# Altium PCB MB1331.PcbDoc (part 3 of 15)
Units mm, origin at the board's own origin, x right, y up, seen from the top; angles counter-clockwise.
Board outline 169.25 x 173.25 mm, 6 copper layers (Top Layer, Signal Layer 1, Signal Layer 2, Signal Layer 3, Signal Layer 4, Bottom Layer), stack 1.556 mm thick; 871 components, 699 nets, 3244 pads, 2370 vias.

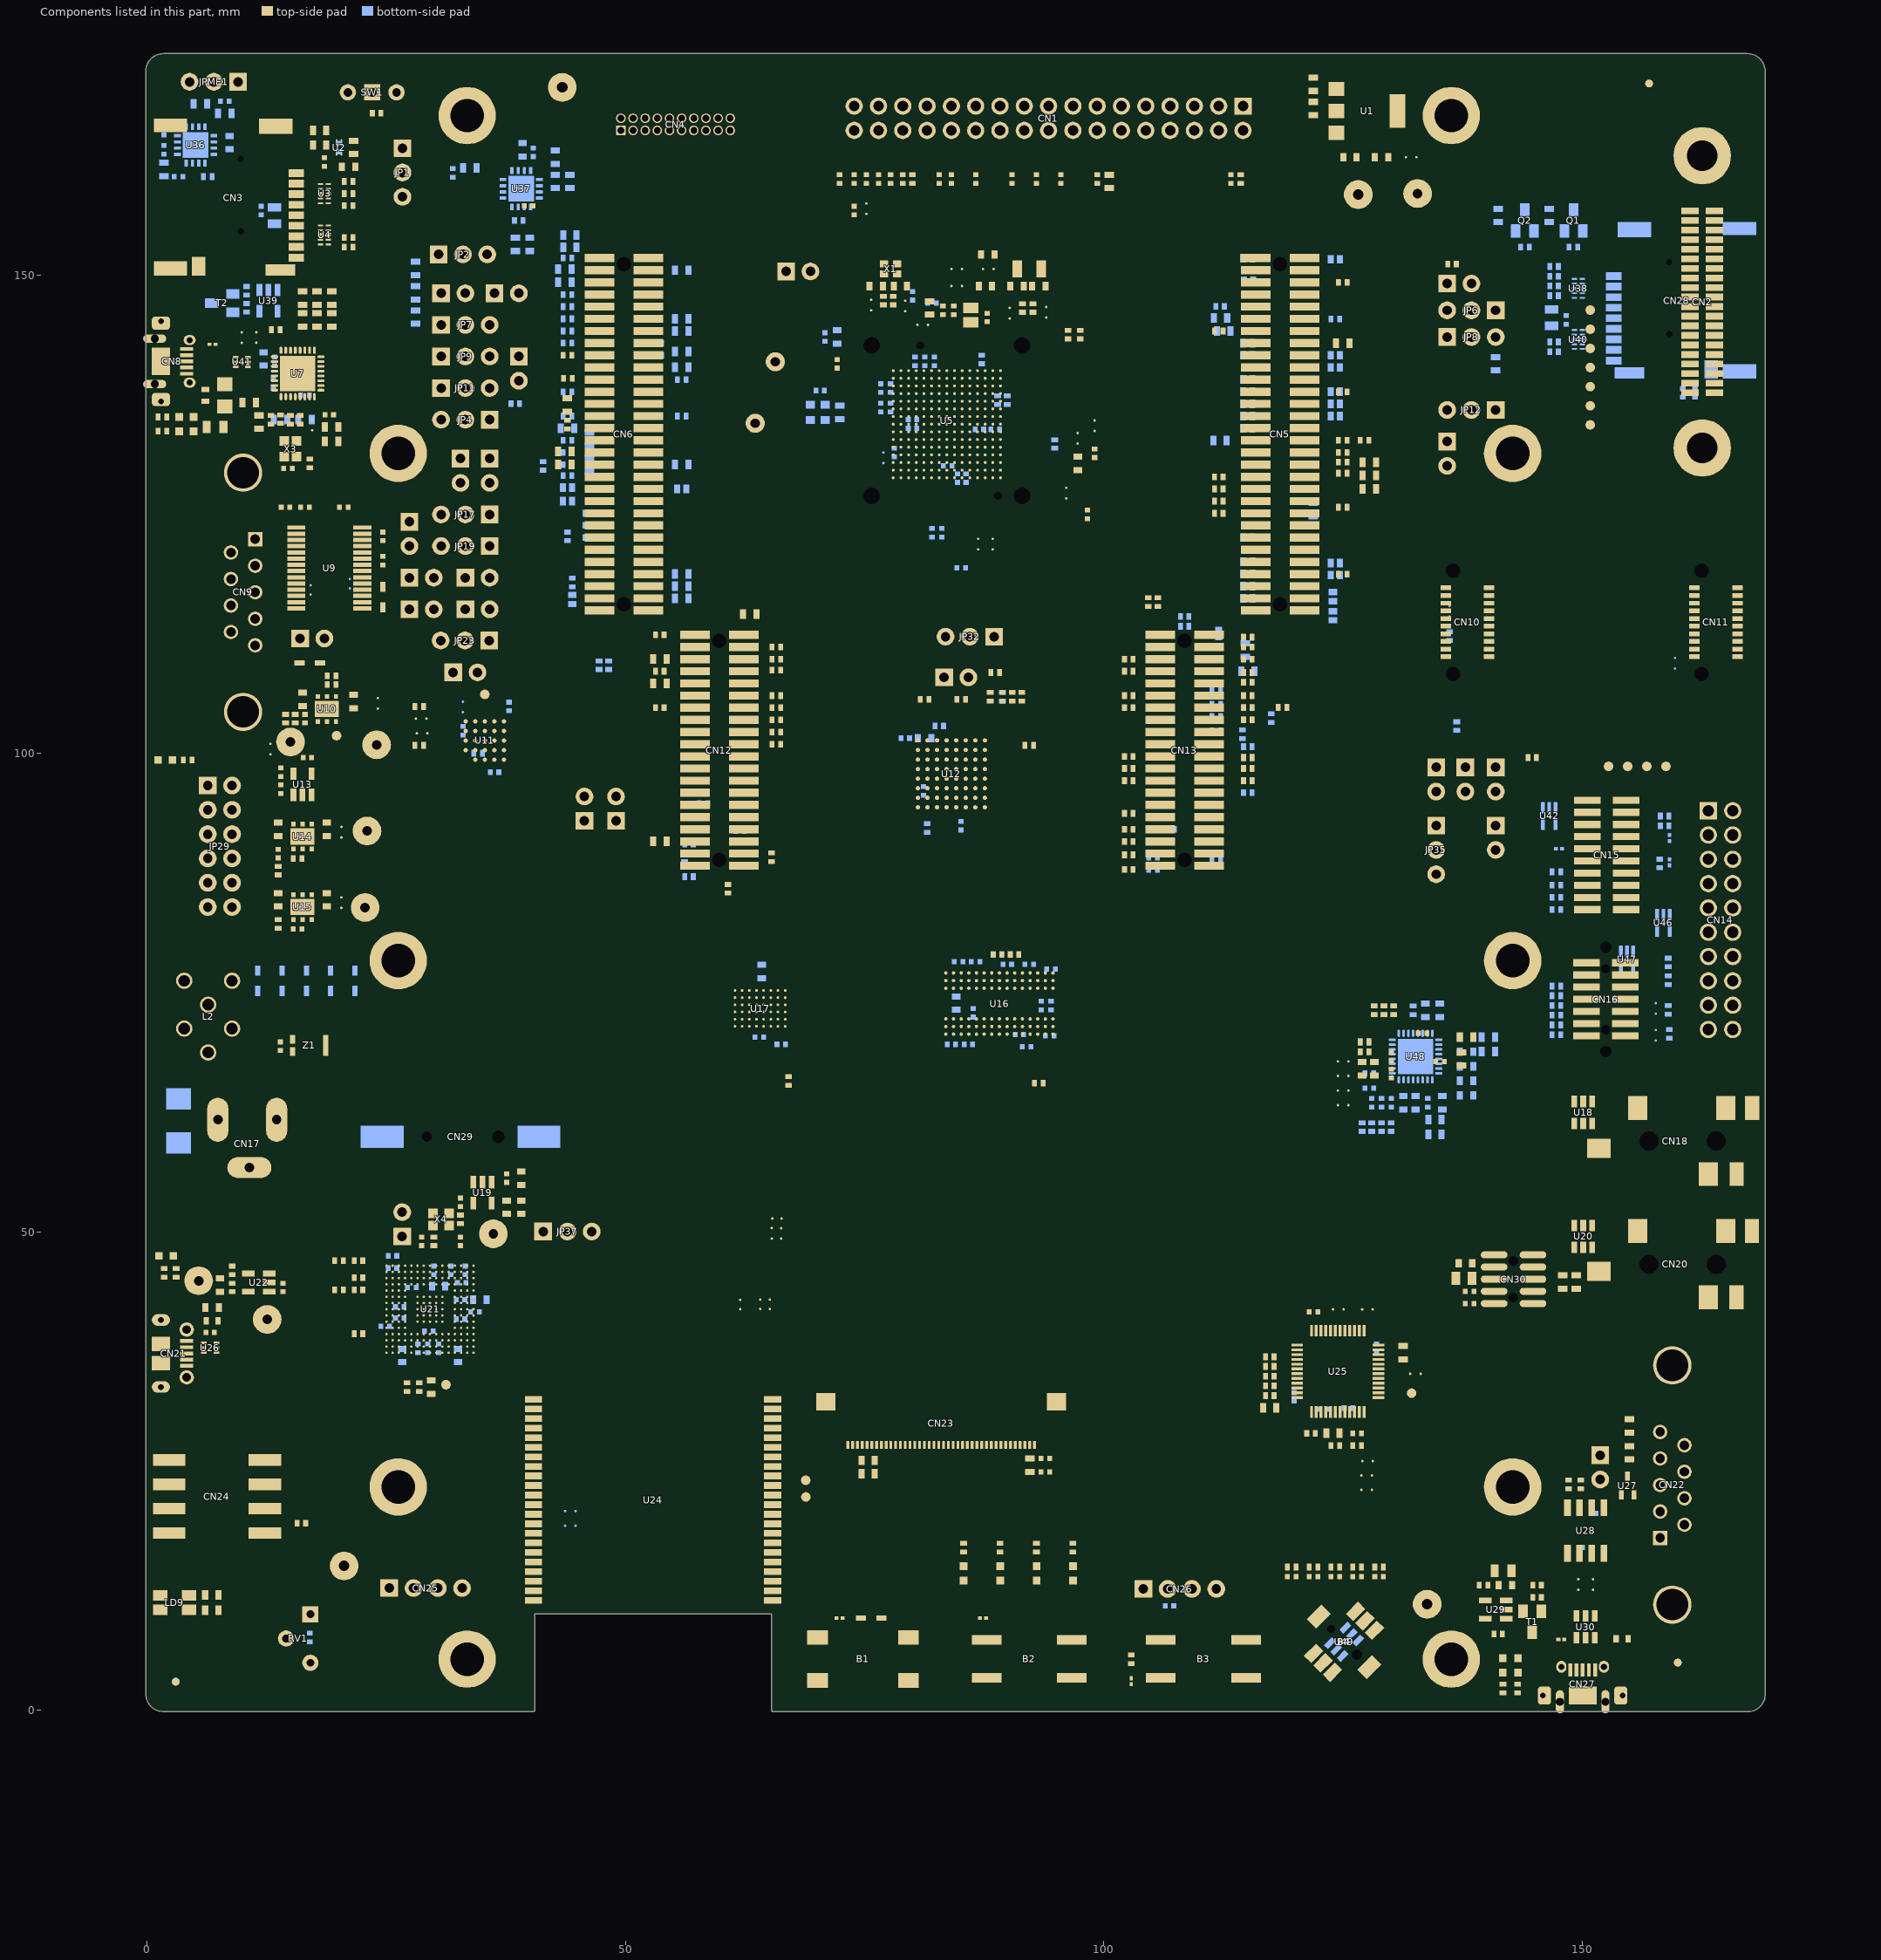
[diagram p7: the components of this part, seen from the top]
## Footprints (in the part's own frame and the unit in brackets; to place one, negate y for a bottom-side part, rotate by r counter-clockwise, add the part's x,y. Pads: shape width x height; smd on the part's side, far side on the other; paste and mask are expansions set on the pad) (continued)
ICC_TFBGA90_8X13_P080 [mm] "IPC"
  round 0.35 smd mask+0.05: A1(-3.2,5.6) A2(-2.4,5.6) A3(-1.6,5.6) A7(1.6,5.6) A8(2.4,5.6) A9(3.2,5.6) B1(-3.2,4.8) B2(-2.4,4.8) B3(-1.6,4.8) B7(1.6,4.8) B8(2.4,4.8) B9(3.2,4.8) C1(-3.2,4) C2(-2.4,4) C3(-1.6,4) C7(1.6,4) C8(2.4,4) C9(3.2,4) D1(-3.2,3.2) D2(-2.4,3.2) D3(-1.6,3.2) D7(1.6,3.2) D8(2.4,3.2) D9(3.2,3.2) E1(-3.2,2.4) E2(-2.4,2.4) E3(-1.6,2.4) E7(1.6,2.4) E8(2.4,2.4) E9(3.2,2.4) F1(-3.2,1.6) F2(-2.4,1.6) F3(-1.6,1.6) F7(1.6,1.6) F8(2.4,1.6) F9(3.2,1.6) G1(-3.2,0.8) G2(-2.4,0.8) G3(-1.6,0.8) G7(1.6,0.8) G8(2.4,0.8) G9(3.2,0.8) H1(-3.2,0) H2(-2.4,0) H3(-1.6,0) H7(1.6,0) H8(2.4,0) H9(3.2,0) J1(-3.2,-0.8) J2(-2.4,-0.8) J3(-1.6,-0.8) J7(1.6,-0.8) J8(2.4,-0.8) J9(3.2,-0.8) K1(-3.2,-1.6) K2(-2.4,-1.6) K3(-1.6,-1.6) K7(1.6,-1.6) K8(2.4,-1.6) K9(3.2,-1.6) L1(-3.2,-2.4) L2(-2.4,-2.4) L3(-1.6,-2.4) L7(1.6,-2.4) L8(2.4,-2.4) L9(3.2,-2.4) M1(-3.2,-3.2) M2(-2.4,-3.2) M3(-1.6,-3.2) M7(1.6,-3.2) M8(2.4,-3.2) M9(3.2,-3.2) N1(-3.2,-4) N2(-2.4,-4) N3(-1.6,-4) N7(1.6,-4) N8(2.4,-4) N9(3.2,-4) P1(-3.2,-4.8) P2(-2.4,-4.8) P3(-1.6,-4.8) P7(1.6,-4.8) P8(2.4,-4.8) P9(3.2,-4.8) R1(-3.2,-5.6) R2(-2.4,-5.6) R3(-1.6,-5.6) R7(1.6,-5.6) R8(2.4,-5.6) R9(3.2,-5.6)
  silkscreen extent -4.2,-6.55 4.05,6.7, body extent -4.06,-6.55 4.05,6.55, height 1.21
ICC_TFBGA225_13X13_STM32H7B3NIH6Q_P080__SOCKET_IRONWOOD_CS1222291MF_REV-A_WITHOUT-3D-SOCKET [mm] "MCD-01577"
  round 0.3 smd mask+0.05: A1(-5.6,5.6) A2(-4.8,5.6) A3(-4,5.6) A4(-3.2,5.6) A5(-2.4,5.6) A6(-1.6,5.6) A7(-0.8,5.6) A8(0,5.6) A9(0.8,5.6) A10(1.6,5.6) A11(2.4,5.6) A12(3.2,5.6) A13(4,5.6) A14(4.8,5.6) A15(5.6,5.6) B1(-5.6,4.8) B2(-4.8,4.8) B3(-4,4.8) B4(-3.2,4.8) B5(-2.4,4.8) B6(-1.6,4.8) B7(-0.8,4.8) B8(0,4.8) B9(0.8,4.8) B10(1.6,4.8) B11(2.4,4.8) B12(3.2,4.8) B13(4,4.8) B14(4.8,4.8) B15(5.6,4.8) C1(-5.6,4) C2(-4.8,4) C3(-4,4) C4(-3.2,4) C5(-2.4,4) C6(-1.6,4) C7(-0.8,4) C8(0,4) C9(0.8,4) C10(1.6,4) C11(2.4,4) C12(3.2,4) C13(4,4) C14(4.8,4) C15(5.6,4) D1(-5.6,3.2) D2(-4.8,3.2) D3(-4,3.2) D4(-3.2,3.2) D5(-2.4,3.2) D6(-1.6,3.2) D7(-0.8,3.2) D8(0,3.2) D9(0.8,3.2) D10(1.6,3.2) D11(2.4,3.2) D12(3.2,3.2) D13(4,3.2) D14(4.8,3.2) D15(5.6,3.2) E1(-5.6,2.4) E2(-4.8,2.4) E3(-4,2.4) E4(-3.2,2.4) E5(-2.4,2.4) E6(-1.6,2.4) E7(-0.8,2.4) E8(0,2.4) E9(0.8,2.4) E10(1.6,2.4) E11(2.4,2.4) E12(3.2,2.4) E13(4,2.4) E14(4.8,2.4) E15(5.6,2.4) F1(-5.6,1.6) F2(-4.8,1.6) F3(-4,1.6) F4(-3.2,1.6) F5(-2.4,1.6) F6(-1.6,1.6) F7(-0.8,1.6) F8(0,1.6) F9(0.8,1.6) F10(1.6,1.6) F11(2.4,1.6) F12(3.2,1.6) F13(4,1.6) F14(4.8,1.6) F15(5.6,1.6) G1(-5.6,0.8) G2(-4.8,0.8) G3(-4,0.8) G4(-3.2,0.8) G5(-2.4,0.8) G6(-1.6,0.8) G7(-0.8,0.8) G8(0,0.8) G9(0.8,0.8) G10(1.6,0.8) G11(2.4,0.8) G12(3.2,0.8) G13(4,0.8) G14(4.8,0.8) G15(5.6,0.8) H1(-5.6,0) H2(-4.8,0) H3(-4,0) H4(-3.2,0) H5(-2.4,0) H6(-1.6,0) H7(-0.8,0) H8(0,0) H9(0.8,0) H10(1.6,0) H11(2.4,0) H12(3.2,0) H13(4,0) H14(4.8,0) H15(5.6,0) J1(-5.6,-0.8) J2(-4.8,-0.8) J3(-4,-0.8) J4(-3.2,-0.8) J5(-2.4,-0.8) J6(-1.6,-0.8) J7(-0.8,-0.8) J8(0,-0.8) J9(0.8,-0.8) J10(1.6,-0.8) J11(2.4,-0.8) J12(3.2,-0.8) J13(4,-0.8) J14(4.8,-0.8) J15(5.6,-0.8) K1(-5.6,-1.6) K2(-4.8,-1.6) K3(-4,-1.6) K4(-3.2,-1.6) K5(-2.4,-1.6) K6(-1.6,-1.6) K7(-0.8,-1.6) K8(0,-1.6) K9(0.8,-1.6) K10(1.6,-1.6) K11(2.4,-1.6) K12(3.2,-1.6) K13(4,-1.6) K14(4.8,-1.6) K15(5.6,-1.6) L1(-5.6,-2.4) L2(-4.8,-2.4) L3(-4,-2.4) L4(-3.2,-2.4) L5(-2.4,-2.4) L6(-1.6,-2.4) L7(-0.8,-2.4) L8(0,-2.4) L9(0.8,-2.4) L10(1.6,-2.4) L11(2.4,-2.4) L12(3.2,-2.4) L13(4,-2.4) L14(4.8,-2.4) L15(5.6,-2.4) M1(-5.6,-3.2) M2(-4.8,-3.2) M3(-4,-3.2) M4(-3.2,-3.2) M5(-2.4,-3.2) M6(-1.6,-3.2) M7(-0.8,-3.2) M8(0,-3.2) M9(0.8,-3.2) M10(1.6,-3.2) M11(2.4,-3.2) M12(3.2,-3.2) M13(4,-3.2) M14(4.8,-3.2) M15(5.6,-3.2) N1(-5.6,-4) N2(-4.8,-4) N3(-4,-4) N4(-3.2,-4) N5(-2.4,-4) N6(-1.6,-4) N7(-0.8,-4) N8(0,-4) N9(0.8,-4) N10(1.6,-4) N11(2.4,-4) N12(3.2,-4) N13(4,-4) N14(4.8,-4) N15(5.6,-4) P1(-5.6,-4.8) P2(-4.8,-4.8) P3(-4,-4.8) P4(-3.2,-4.8) P5(-2.4,-4.8) P6(-1.6,-4.8) P7(-0.8,-4.8) P8(0,-4.8) P9(0.8,-4.8) P10(1.6,-4.8) P11(2.4,-4.8) P12(3.2,-4.8) P13(4,-4.8) P14(4.8,-4.8) P15(5.6,-4.8) R1(-5.6,-5.6) R2(-4.8,-5.6) R3(-4,-5.6) R4(-3.2,-5.6) R5(-2.4,-5.6) R6(-1.6,-5.6) R7(-0.8,-5.6) R8(0,-5.6) R9(0.8,-5.6) R10(1.6,-5.6) R11(2.4,-5.6) R12(3.2,-5.6) R13(4,-5.6) R14(4.8,-5.6) R15(5.6,-5.6)
  round 0 hole 0.85 unplated mask+0.05: NPTH1(7.487,5.322) NPTH2(-8.238,-2.783)
  round 0 hole 1.71 unplated mask+0.05: PTH1(-8.238,7.862) PTH2(7.487,7.862) PTH3(7.487,-7.863) PTH4(-8.238,-7.863)
  Bottom Layer keep-out circle w0.01: c7.487,7.862 r2.5
  Bottom Layer keep-out circle w0.01: c-8.238,7.862 r2.5
  Bottom Layer keep-out circle w0.01: c-8.238,-7.863 r2.5
  Bottom Layer keep-out circle w0.01: c7.487,-7.863 r2.5
  Bottom Layer keep-out region: -0.376,0 -0.376,-2.5 1.224,-2.5 5.024,-6.3 5.076,-6.378 5.094,-6.469 5.094,-6.469 5.094,-6.63 5.028,-6.963 4.839,-7.245 4.557,-7.434 4.224,-7.5 4.224,-7.5 -0.376,-7.5 -0.376,-10.365 9.988,-10.365 9.988,10.365 -0.376,10.365 -0.376,7.5 4.224,7.5 4.557,7.434 4.839,7.245 5.028,6.963 5.094,6.63 5.094,6.63 5.094,6.469 5.076,6.378 5.024,6.3 5.024,6.3 1.224,2.5 -0.376,2.5 -0.376,0 2.124,0 2.124,1.6 5.924,5.4 6.002,5.452 6.093,5.47 6.093,5.47 6.254,5.47 6.587,5.404 6.869,5.215 7.058,4.933 7.124,4.6 7.124,4.6 7.124,-4.6 7.058,-4.933 6.869,-5.215 6.587,-5.404 6.254,-5.47 6.254,-5.47 6.093,-5.47 6.002,-5.452 5.924,-5.4 5.924,-5.4 2.124,-1.6 2.124,0
  Bottom Layer keep-out region: -0.376,0 -0.376,2.5 -1.976,2.5 -5.776,6.3 -5.828,6.378 -5.846,6.469 -5.846,6.469 -5.846,6.63 -5.78,6.963 -5.591,7.245 -5.309,7.434 -4.976,7.5 -4.976,7.5 -0.376,7.5 -0.376,10.365 -10.74,10.365 -10.74,-10.365 -0.376,-10.365 -0.376,-7.5 -4.976,-7.5 -5.309,-7.434 -5.591,-7.245 -5.78,-6.963 -5.846,-6.63 -5.846,-6.63 -5.846,-6.469 -5.828,-6.378 -5.776,-6.3 -5.776,-6.3 -1.976,-2.5 -0.376,-2.5 -0.376,0 -2.876,0 -2.876,-1.6 -6.676,-5.4 -6.754,-5.452 -6.845,-5.47 -6.845,-5.47 -7.006,-5.47 -7.339,-5.404 -7.621,-5.215 -7.81,-4.933 -7.876,-4.6 -7.876,-4.6 -7.876,4.6 -7.81,4.933 -7.621,5.215 -7.339,5.404 -7.006,5.47 -7.006,5.47 -6.845,5.47 -6.754,5.452 -6.676,5.4 -6.676,5.4 -2.876,1.6 -2.876,0
  silkscreen extent -9.65,-9.13 8.75,9.28, body extent -6.55,-6.55 6.55,6.55, height 1.21
ICC_UFBGA201_176+25_10X10_P065 [mm] "IPC"
  round 0.25 smd mask+0.05: A1(-4.55,4.55) A2(-3.9,4.55) A3(-3.25,4.55) A4(-2.6,4.55) A5(-1.95,4.55) A6(-1.3,4.55) A7(-0.65,4.55) A8(0,4.55) A9(0.65,4.55) A10(1.3,4.55) A11(1.95,4.55) A12(2.6,4.55) A13(3.25,4.55) A14(3.9,4.55) A15(4.55,4.55) B1(-4.55,3.9) B2(-3.9,3.9) B3(-3.25,3.9) B4(-2.6,3.9) B5(-1.95,3.9) B6(-1.3,3.9) B7(-0.65,3.9) B8(0,3.9) B9(0.65,3.9) B10(1.3,3.9) B11(1.95,3.9) B12(2.6,3.9) B13(3.25,3.9) B14(3.9,3.9) B15(4.55,3.9) C1(-4.55,3.25) C2(-3.9,3.25) C3(-3.25,3.25) C4(-2.6,3.25) C5(-1.95,3.25) C6(-1.3,3.25) C7(-0.65,3.25) C8(0,3.25) C9(0.65,3.25) C10(1.3,3.25) C11(1.95,3.25) C12(2.6,3.25) C13(3.25,3.25) C14(3.9,3.25) C15(4.55,3.25) D1(-4.55,2.6) D2(-3.9,2.6) D3(-3.25,2.6) D4(-2.6,2.6) D5(-1.95,2.6) D6(-1.3,2.6) D7(-0.65,2.6) D8(0,2.6) D9(0.65,2.6) D10(1.3,2.6) D11(1.95,2.6) D12(2.6,2.6) D13(3.25,2.6) D14(3.9,2.6) D15(4.55,2.6) E1(-4.55,1.95) E2(-3.9,1.95) E3(-3.25,1.95) E4(-2.6,1.95) E12(2.6,1.95) E13(3.25,1.95) E14(3.9,1.95) E15(4.55,1.95) F1(-4.55,1.3) F2(-3.9,1.3) F3(-3.25,1.3) F4(-2.6,1.3) F6(-1.3,1.3) F7(-0.65,1.3) F8(0,1.3) F9(0.65,1.3) F10(1.3,1.3) F12(2.6,1.3) F13(3.25,1.3) F14(3.9,1.3) F15(4.55,1.3) G1(-4.55,0.65) G2(-3.9,0.65) G3(-3.25,0.65) G4(-2.6,0.65) G6(-1.3,0.65) G7(-0.65,0.65) G8(0,0.65) G9(0.65,0.65) G10(1.3,0.65) G12(2.6,0.65) G13(3.25,0.65) G14(3.9,0.65) G15(4.55,0.65) H1(-4.55,0) H2(-3.9,0) H3(-3.25,0) H4(-2.6,0) H6(-1.3,0) H7(-0.65,0) H8(0,0) H9(0.65,0) H10(1.3,0) H12(2.6,0) H13(3.25,0) H14(3.9,0) H15(4.55,0) J1(-4.55,-0.65) J2(-3.9,-0.65) J3(-3.25,-0.65) J4(-2.6,-0.65) J6(-1.3,-0.65) J7(-0.65,-0.65) J8(0,-0.65) J9(0.65,-0.65) J10(1.3,-0.65) J12(2.6,-0.65) J13(3.25,-0.65) J14(3.9,-0.65) J15(4.55,-0.65) K1(-4.55,-1.3) K2(-3.9,-1.3) K3(-3.25,-1.3) K4(-2.6,-1.3) K6(-1.3,-1.3) K7(-0.65,-1.3) K8(0,-1.3) K9(0.65,-1.3) K10(1.3,-1.3) K12(2.6,-1.3) K13(3.25,-1.3) K14(3.9,-1.3) K15(4.55,-1.3) L1(-4.55,-1.95) L2(-3.9,-1.95) L3(-3.25,-1.95) L4(-2.6,-1.95) L12(2.6,-1.95) L13(3.25,-1.95) L14(3.9,-1.95) L15(4.55,-1.95) M1(-4.55,-2.6) M2(-3.9,-2.6) M3(-3.25,-2.6) M4(-2.6,-2.6) M5(-1.95,-2.6) M6(-1.3,-2.6) M7(-0.65,-2.6) M8(0,-2.6) M9(0.65,-2.6) M10(1.3,-2.6) M11(1.95,-2.6) M12(2.6,-2.6) M13(3.25,-2.6) M14(3.9,-2.6) M15(4.55,-2.6) N1(-4.55,-3.25) N2(-3.9,-3.25) N3(-3.25,-3.25) N4(-2.6,-3.25) N5(-1.95,-3.25) N6(-1.3,-3.25) N7(-0.65,-3.25) N8(0,-3.25) N9(0.65,-3.25) N10(1.3,-3.25) N11(1.95,-3.25) N12(2.6,-3.25) N13(3.25,-3.25) N14(3.9,-3.25) N15(4.55,-3.25) P1(-4.55,-3.9) P2(-3.9,-3.9) P3(-3.25,-3.9) P4(-2.6,-3.9) P5(-1.95,-3.9) P6(-1.3,-3.9) P7(-0.65,-3.9) P8(0,-3.9) P9(0.65,-3.9) P10(1.3,-3.9) P11(1.95,-3.9) P12(2.6,-3.9) P13(3.25,-3.9) P14(3.9,-3.9) P15(4.55,-3.9) R1(-4.55,-4.55) R2(-3.9,-4.55) R3(-3.25,-4.55) R4(-2.6,-4.55) R5(-1.95,-4.55) R6(-1.3,-4.55) R7(-0.65,-4.55) R8(0,-4.55) R9(0.65,-4.55) R10(1.3,-4.55) R11(1.95,-4.55) R12(2.6,-4.55) R13(3.25,-4.55) R14(3.9,-4.55) R15(4.55,-4.55)
  silkscreen extent -5.22,-5.07 5.07,5.23, body extent -5.07,-5.07 5.07,5.07, height 0.61
IND_0402_MURATA_BLM15H_H0P5 [mm] "MCD-01610"
  rect 0.65x0.9 smd mask+0.05: 1(-0.475,0) 2(0.475,0)
  silkscreen extent -0.05,-0.28 0.05,0.28, body extent -0.53,-0.28 0.53,0.28, height 0.55
IND_0603_H0P8 [mm]
  rect 0.7x0.9 smd mask+0.05: 1(-0.7,0) 2(0.7,0)
  silkscreen extent -0.2,-0.4 0.2,0.4, body extent -0.8,-0.4 0.8,0.4, height 0.8
L0603 [mm]
  rect 0.8x0.95 smd mask+0.05: 1(-0.8,0) 2(0.8,0)
  silkscreen extent -1.33,-0.6 1.33,0.6, body extent -0.87,-0.47 0.87,0.47, height 0.95
L0805_H0P9 [mm]
  rect 1.1x1.6 smd mask+0.05: 1(-0.75,0) 2(0.75,0)
  silkscreen extent -0.08,-0.7 0.08,0.7, body extent -1.07,-0.7 1.07,0.7, height 1.2
LED_0603_OSRAM_LG-Q396-PS-35_GREEN_1A2K_H0P4 [mm]
  rect 0.8x0.8 smd mask+0.05: 1(-0.75,0) 2(0.75,0)
  silkscreen extent -0.85,-0.53 1.28,0.53, body extent -0.85,-0.45 0.85,0.45, height 0.6
LED_0603_OSRAM_LO-Q976-PS-25_ORANGE_1A2K_H0P8 [mm]
  rect 0.8x0.8 smd mask+0.05: 1(-0.75,0) 2(0.75,0)
  silkscreen extent -0.85,-0.53 1.28,0.53, body extent -0.85,-0.45 0.85,0.45, height 0.8
LED_0603_OSRAM_LY-Q396-P1Q2-36_YELLOW_1A2K_H0P4 [mm]
  rect 0.8x0.8 smd mask+0.05: 1(-0.75,0) 2(0.75,0)
  silkscreen extent -0.85,-0.53 1.28,0.53, body extent -0.85,-0.45 0.85,0.45, height 0.4
LED_0603_VISHAY_VLMS1300-GS08_RED_1A2K_H0P8 [mm]
  rect 0.8x0.8 smd mask+0.05: 1(-0.75,0) 2(0.75,0)
  silkscreen extent -0.85,-0.53 1.28,0.53, body extent -0.85,-0.45 0.85,0.45, height 0.8
LED_BI-GR_HSMF-A201-A00J1 [mm] "MCD-00051"
  rect 1.1x1.5 smd mask+0.05: 1(-0.75,-1.5) 2(-0.75,1.5) 3(0.75,1.5) 4(0.75,-1.5)
  silkscreen extent -1.65,-1.85 1.5,1.7, body extent -1.5,-1.85 1.5,1.85, height 2.1
MIRE_PLACE_SMD_0P8MM [mm]
  round 0.8 smd paste-10 mask+0.2: 1(0,0)
  Top Layer keep-out circle w0.01: c0,0 r0.804
MOD_WIFI_INVENTEK_ISM43362 [mm]
  rect 1.8x0.7 smd mask+0.1: 1(12.5,-12.3) 2(12.5,-11.3) 3(12.5,-10.3) 4(12.5,-9.3) 5(12.5,-8.3) 6(12.5,-7.3) 7(12.5,-6.3) 8(12.5,-5.3) 9(12.5,-4.3) 10(12.5,-3.3) 11(12.5,-2.3) 12(12.5,-1.3) 13(12.5,-0.3) 14(12.5,0.7) 15(12.5,1.7) 16(12.5,2.7) 17(12.5,3.7) 18(12.5,4.7) 19(12.5,5.7) 20(12.5,6.7) 21(12.5,7.7) 22(12.5,8.7) 23(-12.5,8.7) 24(-12.5,7.7) 25(-12.5,6.7) 26(-12.5,5.7) 27(-12.5,4.7) 28(-12.5,3.7) 29(-12.5,2.7) 30(-12.5,1.7) 31(-12.5,0.7) 32(-12.5,-0.3) 33(-12.5,-1.3) 34(-12.5,-2.3) 35(-12.5,-3.3) 36(-12.5,-4.3) 37(-12.5,-5.3) 38(-12.5,-6.3) 39(-12.5,-7.3) 40(-12.5,-8.3) 41(-12.5,-9.3) 42(-12.5,-10.3) 43(-12.5,-11.3) 44(-12.5,-12.3)
  Keep-Out Layer region: -12.5,20 12.5,20 12.5,10 -12.5,10
  silkscreen extent -12.7,-20.2 13.4,20.2, body extent -12.5,-20 12.5,20.19, height 4.1
MOS_SOT23 [mm]
  rect 1x1.4 smd mask+0.05: 1(-0.95,-1.1) 2(0.95,-1.1) 3(0,1.1)
  silkscreen extent -1.63,-0.82 1.63,0.82, body extent -1.56,-1.25 1.56,1.25, height 1.1
MOS_SOT23-5L [mm]
  rect 0.6x1.3 smd mask+0.05: 1(-0.95,-1.1) 2(0,-1.1) 3(0.95,-1.1) 4(0.95,1.1) 5(-0.95,1.1)
  silkscreen extent -1.6,-0.95 1.6,0.97, body extent -1.52,-1.25 1.52,1.25, height 1.45
NPN_SOT23 [mm]
  rect 1x1.4 smd mask+0.05: 1(-0.95,-1.1) 2(0.95,-1.1) 3(0,1.1)
  silkscreen extent -1.63,-0.82 1.63,0.82, body extent -1.56,-1.25 1.56,1.25, height 1.1
OSC_NDK_NZ2520SB_4P [mm]
  rect 1x1 smd mask+0.05: 1(-0.825,-0.625) 2(0.825,-0.625) 3(0.825,0.625) 4(-0.825,0.625)
  silkscreen extent -1.43,-1.22 1.2,1.05, body extent -1.3,-1.05 1.3,1.05, height 0.91
POT_BOURNS_3386P [mm]
  rect 1.7x1.7 hole 0.8 mask+0.05: 1(-2.54,0.02)
  round 1.7 hole 0.8 mask+0.05: 2(0,-2.52) 3(2.54,0.02)
  silkscreen extent -4.8,-4.8 4.8,4.8, body extent -4.8,-4.8 4.8,4.81, height 4.96
PTH_M1261-3005-N_3P5X6_M3_H14 [mm]
  round 6 hole 3.5 mask+0.05: 1(0,0)
  silkscreen extent -3.25,-3.25 3.25,3.25, body extent -2.5,-2.5 2.5,2.5, height 14
R0402 [mm]
  rect 0.51x0.7 smd mask+0.05: 1(-0.45,0) 2(0.45,0)
  silkscreen extent 0,-0.3 0,0.3, body extent -0.52,-0.3 0.52,0.3, height 0.4
R0603 [mm]
  rect 0.64x1 smd mask+0.05: 1(-0.7,0) 2(0.7,0)
  silkscreen extent -1.05,-0.58 1.05,0.58, body extent -0.9,-0.5 0.9,0.5, height 0.56
R0603_H0P45 [mm]
  rect 0.64x1 smd mask+0.05: 1(-0.7,0) 2(0.7,0)
  silkscreen extent -1.05,-0.58 1.05,0.58, body extent -0.9,-0.5 0.9,0.5, height 0.56
R0805 [mm]
  rect 0.85x1.3 smd mask+0.05: 1(-0.875,0) 2(0.875,0)
  silkscreen extent -0.33,-0.67 0.33,0.67, body extent -1.05,-0.68 1.05,0.68, height 0.65
REG_SOT23-5L [mm]
  rect 0.6x1.3 smd mask+0.05: 1(-0.95,-1.1) 2(0,-1.1) 3(0.95,-1.1) 4(0.95,1.1) 5(-0.95,1.1)
  silkscreen extent -1.6,-0.95 1.6,0.97, body extent -1.52,-1.25 1.52,1.25, height 1.1
REG_SOT223-TAB [mm]
  rect 1.5x1.65 smd mask+0.05: 1(-2.3,-3.175) 2(0,-3.175) 3(2.3,-3.175)
  rect 3.5x1.65 smd mask+0.05: 4(0,3.175)
  silkscreen extent -3.35,-2.15 3.35,2.12, body extent -3.35,-3.48 3.35,3.48, height 1.8
Sheetbox_6L2S [mil] "Sheetbox 6 layers / 2 silkscreens"
  round 20 on Mech16: 1(813.5,208.05) 1(2736.63,208.05)
SOLDER-BRIDGE_R0402-0R [mil] "MCD-01619"
  round 10 smd paste-393.7 mask+1.97: 1(-17.72,0) 2(20.67,0)
  Top Layer region: 1.48,13.78 8.37,0 1.48,-13.78 30.51,-13.78 30.51,13.78
  Top Layer region: -30.51,-13.78 -30.51,13.78 -8.37,13.78 -1.48,0 -8.37,-13.78
  silkscreen extent -33,-17 33,17, body extent -20,-12 20,12, height 14
SOLDER-BRIDGE_R0603-0R [mil]
  round 10 smd paste-393.7: 1(-19.68,0) 2(23.62,0)
  Top Layer region: -47.24,-19.68 -47.24,19.68 -15.75,19.68 3.94,0 -15.75,-19.68 -47.24,-19.68
  Top Layer region: -5.91,19.68 13.78,0 -5.91,-19.68 47.24,-19.68 47.24,19.68 -5.91,19.68
  silkscreen extent -50,-23 50,23, body extent -36,-20 36,20, height 22
STICKER_25X9 [mm] "Sticker 25mm x 9mm"
  silkscreen extent -12.5,-4.5 12.5,4.5
SWI_C&K_KSC721GLFS_BLUE [mm] "BLUE"
  rect 3.1x1 smd mask+0.05: 1(-4.45,2) 2(4.45,2) 3(-4.45,-2) 4(4.45,-2)
  silkscreen extent -3.25,-3.25 3.25,3.25, body extent -5,-3.25 5,3.25, height 4.3
SWI_EAO_09-03290-01_EXTENDED_STRAIGHT_BLACK [mm]
  rect 1.7x1.7 hole 0.9 mask+0.05: 1(0,0)
  round 1.7 hole 0.9 mask+0.05: 2(0,-2.54) 3(0,2.54)
  silkscreen extent -1.25,-5 1.25,5, body extent -1.25,-5 1.25,5, height 7.9
SWI_WEALTHMETAL_TD-0341_4P_BLACK [mm]
  rect 1.52x2.16 smd mask+0.05: 1(-2.25,-4.75) 2(-2.25,4.75) 3(2.25,-4.75) 4(2.25,4.75)
  silkscreen extent -3,-3.5 3,3.5, body extent -3,-5.15 3,5.15, height 7.55
SWI_XIEJIA_MT-008A_6P [mm] "MCD-00132"
  rect 1.8x1.1 smd mask+0.05: 1(-3.1,1.4) 2(-3.1,0) 3(-3.1,-1.4) 4(3.1,1.4) 5(3.1,0) 6(3.1,-1.4)
  rect 2.2x1.4 smd mask+0.05: 7(0,3.75) 8(0,-3.75)
  round 0 hole 0.8 unplated paste-10 mask+0.05: NPTH1(0,1.9)
  round 0 hole 1.1 unplated paste-10 mask+0.05: NPTH2(0,-1.9)
  silkscreen extent -3.7,-3.7 3.7,3.7, body extent -3.85,-3.75 3.85,3.75, height 5.2
TP_PTH-1MM_TEST-TERMINAL_RS_262-2185_RED [mm] "MCD-00712"
  round 3 hole 1 mask+0.05: 1(0,0)
  silkscreen extent -1.63,-1.62 1.63,1.62, body extent -1.24,-1.25 1.25,1.25, height 4.85
TP_PTH-1P02MM_TEST-TERMINAL_RS_101-2391_BLACK [mm] "MCD-00713"
  round 3 hole 1.1 mask+0.05: 1(0,0)
  silkscreen extent -1.63,-1.62 1.63,1.62, body extent -1.24,-1.25 1.25,1.25, height 4.85
TP_PTH_1MM_2MM [mm] "MCD-01506"
  round 2 hole 1 mask+0.05: 1(0,0)
  silkscreen extent -1.2,-1.2 1.2,1.2
TP_SMD_1MM [mm]
  round 1 smd paste-10 mask+0.05: 1(0,0)
  silkscreen extent -0.7,-0.7 0.7,0.7

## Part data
B1: library part MCD-00001, "Non-Open Push-Button 0.1A 24V BLACK", Manufacturer=WEALTHMETAL, Manufacturer_Part_Number=TD-0341X-A00, Package=6x10mm
B2 B3: library part MCD-00176, "Switch HW BLUE High4.3mm 2.25 Newtons", Manufacturer=C&K, Manufacturer_Part_Number=KSC721GLFS, Package=6.2x10mm
B4: library part MCD-00132, "Joystick, 4 dir, 1 OK", Manufacturer="XIEJIA Electronics", Manufacturer_Part_Number=MT-008A, Package=7.4x7.5mm
C1 C2: library part MCD-00243, "Capacitor, MLCC, 10uF, 6V3, X5R, 10%, 0603, T=0,8mm", Manufacturer=YAGEO, Manufacturer_Part_Number=CC0603KRX5R5BB106, Package=0603
C3 C5 C6 C7 C8 C9 C11 C12 C13 C14 C15 C16 C17 C30 C32 C34 C35 C36 C37 C38 C39 C40 C41 C43 C45 C51 C54 C55 C56 C57 C58 C59 C62 C64 C68 C69 C71 C73 C76 C78 C79 C87 C91 C95 C97 C98 C99 C101 C104 C107 C108 C110 C111 C112 C113 C114 C115 C116 C117 C119 C120 C121 C122 C123 C124 C125 C126 C127 C128 C129 C130 C131 C132 C134 C135 C136 C137 C138 C139 C140 C141 C143 C145 C146 C149 C150 C152 C153 C154 C155 C156 C158 C167 C171 C172 C173 C174 C175 C176 C178 C180 C181 C182 C183 C184 C185 C186 C189 C190 C191 C192 C193 C194 C195 C196 C197 C198 C199: library part MCD-00006, "Capacitor, MLCC, 100nF, 16V, X7R, 10%, 0402, T=0.5mm", Alternate_Manufacturer=MURATA, Alternate_Manufacturer_Part_Number=GCM155R71C104KA55D, Manufacturer=YAGEO, Manufacturer_Part_Number=CC0402KRX7R7BB104, Package=0402
C4 C33 C60 C61 C67 C70 C88 C89 C147 C148 C160 C161 C164 C179: library part MCD-00010, "Capacitor, MLCC, 1uF, 16V, X5R, 10%, 0603, T=0,8mm", Manufacturer=YAGEO, Manufacturer_Part_Number=CC0603KRX5R7BB105, Package=0603
C10 C18: library part MCD-00198, "Capacitor, MLCC, 1nF, 16V, X7R, 10%, 0402, T=0.5mm", Manufacturer=YAGEO, Manufacturer_Part_Number=CC0402KRX7R7BB102, Package=0402
C19 C47 C48 C90 C92 C93 C109 C118 C169 C170: library part MCD-00095, "Capacitor, MLCC, 1uF, 6V3, X5R, 10%, 0402, T=0,5mm", Alternate_Manufacturer=MURATA, Alternate_Manufacturer_Part_Number=GRM155R60J105KE19, Manufacturer_Part_Number=GRM155R61E105KA12, Package=0402
C20 C46 C65 C80 C81 C82 C83 C84: library part MCD-00011, "Capacitor, MLCC, 10nF, 16V, X7R, 10%, 0402, T=0.5mm", Manufacturer=YAGEO, Manufacturer_Part_Number=CC0402KRX7R7BB103, Package=0402
C21 C42 C44 C50 C53 C102 C133 C142 C144: library part MCD-04044, "Capacitor, MLCC, 4.7uF, 10V, X5R, 20%, 0603, T=0.8mm", Manufacturer="KEMET CORPORATION", Manufacturer_Part_Number=C0603C475M8PAC7040, Package=0603
C22 C23 C25 C26: library part MCD-01726, "Capacitor, MLCC, 2.7pF, 50V, NPO, -+0.25pF 0603", Manufacturer=YAGEO, Manufacturer_Part_Number=CC0603CRNPO9BN2R7, Package=0603
C24: library part MCD-01341, "Capacitor, MLCC, 10uF, 6V3, X5R, 20%, 0603, T=0,8mm", Manufacturer=MURATA, Manufacturer_Part_Number=GRM188R60J106ME47D, Package=0603
C27 C28: library part MCD-01716, "Capacitor, MLCC, 10uF, 6V3, X5R, 20%, 0402, T=0.5mm", Manufacturer=YAGEO, Manufacturer_Part_Number=CC0402MRX5R5BB106, Package=0402
C29 C74: library part MCD-00205, "Capacitor, MLCC, 100pF, 50V, NPO, 5%, 0402, T=0,5mm", Manufacturer=YAGEO, Manufacturer_Part_Number=CC0402JRNPO9BN101, Package=0402
C31: library part MCD-00007, "Capacitor, Tantalum, 4.7uF, 16V, 10%, 4ohms, pkg Type_A (3216 metric), T=1.6mm", Manufacturer=AVX, Manufacturer_Part_Number=TAJA475K016R, Package="3216 (metric)"
C49 C52: library part MCD-00097, "Capacitor, MLCC, 4.7uF, 16V, X5R, 20%, 0603, T=0,8mm", Alternate_Manufacturer=Murata, Alternate_Manufacturer_Part_Number=GRM188R61C475MAAJ, Manufacturer=MURATA, Manufacturer_Part_Number=GRM188R61C475KE11, Package=0603
C63: library part MCD-00238, "Capacitor, MLCC, 1uF, 6V3, X5R, 10%, 0603, T=0,8mm", Manufacturer=YAGEO, Manufacturer_Part_Number=CC0603KRX5R5BB105, Package=0603
C66: library part MCD-00211, "Capacitor, MLCC, 100nF, 16V, X7R, 10%, 0603, T=0,8mm", Manufacturer=YAGEO, Manufacturer_Part_Number=CC0603KRX7R7BB104, Package=0603
C72 C85 C177: library part MCD-00009, "Capacitor, MLCC, 4.7uF, 16V, X5R, 10%, 0603, T=0.8mm", Manufacturer=YAGEO, Manufacturer_Part_Number=CC0603KRX5R7BB475, Package=0603
C75: library part MCD-00014, "Capacitor, MLCC, 10uF, 25V, X5R, 10%, 0805, T=0,85mm", Manufacturer=YAGEO, Manufacturer_Part_Number=CC0805KRX5R8BB106, Package=0805
C77 C105 C187 C188: library part MCD-00012, "Capacitor, MLCC, 2.2uF, 10V, X5R, 10%, 0603, T=0,8mm", Alternate_Manufacturer=KEMET, Alternate_Manufacturer_Part_Number=C0603C225K8PACTU, Manufacturer=YAGEO, Manufacturer_Part_Number=CC0603KRX5R6BB225, Package=0603
C86: library part MCD-01356, "Capacitor, MLCC, 4.7uF, 6V3, X5R, 20%, 0402, T=0,5mm", Manufacturer=MURATA, Manufacturer_Part_Number=GRM155R60J475ME47, Package=0402
C94 C100: library part MCD-04042, "Capacitor, MLCC, 4.7uF, 16V, X7R, 10%, 0805, T=1.25mm", Manufacturer="WURTH ELEKTRONIK", Manufacturer_Part_Number=885012207053, Package=0805
C96: library part MCD-02119, "Capacitor, MLCC, 100nF, 6V3, X5R, 10%, 0603, T=0,8mm", Alternate_Manufacturer=N/A, Manufacturer=KEMET, Manufacturer_Part_Number=C0603C104K9PACTU, Package=0603
C103 C106: library part MCD-00716, "Capacitor, MLCC, 3.6nF, 50V, C0G, 5%, 0603, T=0,8mm", Alternate_Manufacturer=MURATA, Alternate_Manufacturer_Part_Number=GRM1885C1H362JA01D, Manufacturer=KEMET, Manufacturer_Part_Number=C0603C362J5GACTU, Package=0603
C151 C159: library part MCD-00555, "Capacitor, MLCC, 22nF, 10%, 25V, X7R, 0603, T=0,8mm", Manufacturer=YAGEO, Manufacturer_Part_Number=CC0603KRX7R8BB223, Package=0603
C157: library part MCD-00142, "Capacitor, Tantalum, 220uF, 10V, 10%, 500mOhms, pkg Type_C (6032 metric), T=2.6mm", Manufacturer=AVX, Manufacturer_Part_Number=TAJC227K010R, Package="6032 (metric)"
C162 C168: library part MCD-00694, "Capacitor, MLCC, 1.8nF, 50V, X7R, 10%, 0402, T=0.5mm", Manufacturer=YAGEO, Manufacturer_Part_Number=CC0402KRX7R9BB182, Package=0402
C163: library part MCD-00099, "Capacitor, MLCC, 10uF, 10V, X5R, 10%, 0603, T=0,8mm", Manufacturer=MURATA, Manufacturer_Part_Number=GRM188R61A106KE69D, Package=0603
C165 C166: library part MCD-00304, "Capacitor, MLCC, 150pF, 50V, COG, 5%, 0603, T=0,8mm", Manufacturer=YAGEO, Manufacturer_Part_Number=CC0603JRNPO9BN151, Package=0603
C200 C201: library part MCD-00015, "Capacitor, MLCC, 10pF, 50V, NPO, 5%, 0402, T=0,5mm", Manufacturer=YAGEO, Manufacturer_Part_Number=CC0402JRNPO9BN100, Package=0402
CN1: library part MCD-00583, "Header, 17x2, 2.54mm, VR, TH, Height 8.89mm/2.92mm, shrouded", Alternate_Manufacturer=WINPIN, Alternate_Manufacturer_Part_Number=BHFS03-34G01BT1, Manufacturer=SAMTEC, Manufacturer_Part_Number=TST-117-01-T-D
CN2: library part MCD-00138, "Socket, 20x2, 1.0mm, VR, SMT, Height 2.26mm. Symbol & Footprint dedicated to MB1183 & MB1379 camera modules (not in line with Samtec datasheet)", Manufacturer=SAMTEC, Manufacturer_Part_Number=CLM-120-02-L-D
CN3 CN28: library part MCD-00023, "MicroSD Card Conn, Reversed-Type, Mnt Push-Push, Positionning holes", Manufacturer=YAMAICHI, Manufacturer_Part_Number=PJS008-2003-1
CN4: library part MCD-00147, "Socket for MB1299, 10x2, 1.27mm, VR, TH, Height 4.30mm/2.40mm", Alternate_Manufacturer=JIUBABA, Alternate_Manufacturer_Part_Number=234220S1410, Manufacturer="AMPHENOL ICC", Manufacturer_Part_Number=20021311-00020T4LF
CN5 CN6: library part MCD-00576, "Header 30x2, 1.27mm, VR, CMS, Height 7.24mm", Alternate_Manufacturer=JIUBABA, Alternate_Manufacturer_Part_Number=P1039-2*30MGF-089-1A, Manufacturer=SAMTEC, Manufacturer_Part_Number=FTR-130-53-L-D-LC
CN7 JP10 JP13 JP14 JP16 JP22 JP24 JP25 JP26 JP27 JP28 JP30 JP31 JP34 JP38 JP39 JP40: library part MCD-00045, "Header, 2x1, 2,54mm, VR, TH, Height 5.84mm/2.54mm", Alternate_Manufacturer="JIUBABA; LIANYI", Alternate_Manufacturer_Part_Number=313102S111116;313102S111116, Manufacturer=SAMTEC, Manufacturer_Part_Number=TSW-102-07-G-S
CN8 CN27: library part MCD-00661, "USB-MICRO-AB Receptacle, RA, SMT + DIP, Standard, Top Mount, USB certified (symbol & footprint compatible with MCD-00022)", Manufacturer=HIROSE, Manufacturer_Part_Number=ZX62RD-AB-5P8(30)
CN9 CN22: library part MCD-01978, "DB9_Male, RA, TH, height 13.575mm/3.8mm", Manufacturer="TE CONNECTIVITY", Manufacturer_Part_Number=2301843-2
CN10 CN11: library part MCD-00675, "Socket High Speed, 10x2, 0.8mm, Center Strip Contacts, VR, SMT, Height 5.33 mm", Manufacturer=SAMTEC, Manufacturer_Part_Number=ERF8-010-05.0-S-DV-TR, Package=ERF8
CN12 CN13: library part MCD-00578, "Header 20x2, 1.27mm, VR, CMS, Height 7.24mm", Alternate_Manufacturer=JIUBABA, Alternate_Manufacturer_Part_Number=P1039-2*20MGF-089-1A, Manufacturer=SAMTEC, Manufacturer_Part_Number=FTR-120-53-L-D-LC
CN14: library part MCD-01058, "Header, 2.54mm, 10x2, VR, TH, Height 9.1mm/3,1mm", Alternate_Manufacturer=CVILUX, Alternate_Manufacturer_Part_Number=CH87-20-2-V-1-00, Manufacturer=SAMTEC, Manufacturer_Part_Number=TST-110-01-G-D
CN15: library part MCD-00557, "Header 10x2, 1.27mm, VR, CMS, Height 3.05mm", Alternate_Manufacturer=JIUBABA, Alternate_Manufacturer_Part_Number=P127B-2*10MGF-079-1E7A, Manufacturer=SAMTEC, Manufacturer_Part_Number=FTSH-110-01-L-DV
CN16: library part MCD-01226, "Header 5x2, 1.27mm, Dual row, Straight, Surface mount, vertical male connector. 3.05mm lead. Mates with FFSD connector. Footprint compatible with FTSH-107-01-L-DV,-K,-A,-P,-ES (STDC14 MEDIUM)", Alternate_Manufacturer=JIUBABA, Alternate_Manufacturer_Part_Number=P127B-2x05MGF-079-1A, Manufacturer=SAMTEC, Manufacturer_Part_Number=FTSH-105-01-L-DV-K
CN17: library part MCD-00173, "DC-Power-Jack, 2.5mm, 5A, RA, TH", Manufacturer=CLIFF, Manufacturer_Part_Number=DC10B
CN18 CN20: library part MCD-00263, "Connector Jack Socket Stereo 3.5mm, 4 pins, RA, SMT, Black", Manufacturer=QIAOD, Manufacturer_Part_Number=PJ-3028B-4P
CN19: library part MCD-00032, "Header, 2x1, 2,54mm, VR, TH, Height 5.84mm/2.54mm", Alternate_Manufacturer=JIUBABA, Alternate_Manufacturer_Part_Number=313102S111116, Manufacturer=SAMTEC, Manufacturer_Part_Number=TSW-102-07-G-S
CN21: library part MCD-00028, "USB-MICRO-B, 0.65mm, RA, SMT, Bottom Mount,", Manufacturer=MOLEX, Manufacturer_Part_Number=1050170001
CN23: library part MCD-01992, "FFC et FPC connector 0.5MM 40P LNG MTL FITNG SMT VERT MNT", Manufacturer=HIROSE, Manufacturer_Part_Number=FH52E-40S-05SH
CN24: library part MCD-00131, "Socket, 4x2, 2.54mm, RA, SMT, Height 5.72mm", Alternate_Manufacturer=JIUBABA, Alternate_Manufacturer_Part_Number=F206A-2x04MGF-LA, Manufacturer=SAMTEC, Manufacturer_Part_Number=SSM-104-L-DH
CN25 CN26: library part MCD-00029, "Header, 4x1, 2,54mm, VR, TH, Height 5.84mm/2.54mm", Manufacturer=SAMTEC, Manufacturer_Part_Number=TSW-104-07-G-S
CN29: library part MCD-00558, "Battery Coin Cell holder, CR1220_12mm, Height 4.25mm", Manufacturer=HARWIN, Manufacturer_Part_Number=S8411-45R
CN30: library part MCD-00610, "Surface mount, vertical male connector. Double row of 5 pins, 1.27mm pitch, 3.05mm lead. Mates with FFSD connector", Alternate_Manufacturer=JIUBABA, Alternate_Manufacturer_Part_Number=P127B-2x05MGF-079-1A, Manufacturer=SAMTEC, Manufacturer_Part_Number=FTSH-105-01-L-DV-K
D1 D2 D3 D4 D5 D6 D7 D8: library part MCD-00034, Manufacturer=STMICROELECTRONICS, Manufacturer_HQ_COO=EU, Package=SOD323
H1 H2 H3 H4 H5 H6 H7 H8 H9 H10: library part MCD-00035, "POSITION HOLE C6D3R5", Manufacturer=n/a, Manufacturer_HQ_COO=Unknown
HW21: library part MCD-00547, "Sticker to mention board CPN code", Manufacturer=n/a
HW23: library part MCD-00235, "Sticker to mention board reference + serial number", Manufacturer=n/a
JP1 JP4 JP6 JP7 JP8 JP9 JP11 JP12 JP17 JP19 JP23 JP32 JP37: library part MCD-00684, "Header, 3x1, 2,54mm, VR, TH, Height 5.84mm/2.54mm - Shunt Fitted 1-2 by default", Manufacturer=SAMTEC, Manufacturer_Part_Number=TSW-103-07-F-S
JP2 JPME1: library part MCD-00111, "Header, 3x1, 2,54mm, VR, TH, Height 5.84mm/2.54mm", Manufacturer=SAMTEC, Manufacturer_Part_Number=TSW-103-07-F-S
JP3 JP5 JP15 JP18 JP20 JP21: library part MCD-00683, "Header, 2x1, 2,54mm, VR, TH, Height 5.84mm/2.54mm - Shunt Fitted by default", Alternate_Manufacturer=LIANYI, Alternate_Manufacturer_Part_Number=313102S111116, Manufacturer=SAMTEC, Manufacturer_Part_Number=TSW-102-07-G-S
JP29: library part MCD-01147, "Header, 6x2, 2,54mm, VR, TH, Height 5.84mm/2.54mm - Shunt Fitted 1-2", Manufacturer=SAMTEC, Manufacturer_Part_Number=TSW-106-07-G-D
JP35: library part MCD-00685, "Header, 3x1, 2,54mm, VR, TH, Height 5.84mm/2.54mm - Shunt Fitted 2-3 by default", Manufacturer=SAMTEC, Manufacturer_Part_Number=TSW-103-07-F-S
L1: library part MCD-01340, "Inductor, 2.2uH, 20%, Isat 1.2A, DCR 0.228Ohm, 0805", Manufacturer=MURATA, Manufacturer_Part_Number=DFE201210U-2R2M{}P2, Package=0805
L2: library part MCD-02155, "Inductor, DC power EMI line filter, 40dB min (1MHz - 1GHz) insertion loss", Alternate_Manufacturer=N/A, Manufacturer=MURATA, Manufacturer_Part_Number=BNX002-11
LD1 LD6 LD7 LD11: library part MCD-00588, "LED Green, 0603 SMD, Forward Voltage Typ=2V, Max=2.5V", Alternate_Manufacturer="VISHAY SEMICONDUCTOR OPTO DIVISION", Alternate_Manufacturer_Part_Number=VLMTG1300-GS08, Manufacturer="OSRAM OPTO SEMICONDUCTORS", Manufacturer_Part_Number="LG Q396-PS-35", Package=0603
LD2 LD5 LD8 LD10: library part MCD-00587, "LED Red, 0603 SMD, 2V Forward Voltage", Alternate_Manufacturer="OSRAM OPTO SEMICONDUCTORS", Alternate_Manufacturer_Part_Number="LS Q976-NR-1", Manufacturer=VISHAY, Manufacturer_Part_Number=VLMS1300-GS08, Package=0603
LD3: library part MCD-01061, "LED Yellow, 0603 SMD, Forward Voltage min=1.7V, Typ=2V, Max=2.3V", Manufacturer="OSRAM OPTO SEMICONDUCTORS", Manufacturer_Part_Number="LY Q396-P1Q2-36", Package=0603
LD4: library part MCD-00590, "LED Orange, 0603 SMD, Forward Voltage Min=1.6V, Max=2.4V", Alternate_Manufacturer="VISHAY SEMICONDUCTOR OPTO DIVISION", Alternate_Manufacturer_Part_Number=VLMO1300-GS08, Manufacturer="OSRAM OPTO SEMICONDUCTORS", Manufacturer_Part_Number="LO Q976-PS-25", Package=0603
LD9: library part MCD-02402, "LED Bicolor, Red/Yellow-Green , 2V, 20mA, 4-PLCC", Manufacturer=EVERLIGHT, Manufacturer_Part_Number=67-22SURSYGC/S530-A2/TR8, Package=4-PLCC
Q1 Q2: library part MCD-01969, "N-channel enhancement mode field-effect transistor", Manufacturer=Nexperia, Manufacturer_Part_Number=BSN20BK, Package=SOT23-3
R1: library part MCD-00394, "Resistor,150,0603,1%,1/10W", Manufacturer=YAGEO, Manufacturer_Part_Number=RC0603FR-07150RL, Package=0603
R2: library part MCD-00338, "Resistor,120R,0603,1%,1/10W", Manufacturer=YAGEO, Manufacturer_Part_Number=RC0603FR-07120RL, Package=0603
R3 R12 R15 R28 R30 R31 R52 R60 R79 R84 R85 R91 R94 R99 R100 R106 R109 R111 R129 R130 R133 R134 R142 R143 R144 R148 R151 R152 R166 R167 R173 R175 R183 R184 R185 R186 R187 R188 R191 R194 R199 R217 R231 R232 R298 R321 R355 R376 R395 R400 R402 R408 R414: library part MCD-00053, "Resistor,10K,0402,1%,1/16W", Manufacturer=YAGEO, Manufacturer_Part_Number=RC0402FR-0710KL, Package=0402
R4 R5 R6 R17 R18 R19 R22 R25 R26 R27 R35 R45 R47 R50 R55 R67 R72 R81 R120 R123 R125 R126 R138 R141 R155 R156 R158 R168 R169 R170 R174 R201 R202 R206 R207 R209 R210 R213 R219 R220 R221 R223 R235 R238 R239 R246 R253 R266 R273 R274 R275 R277 R278 R282 R284 R285 R288 R294 R301 R304 R309 R314 R323 R330: library part MCD-00056, "Resistor,0R,0603,5%,1/10W", Manufacturer=YAGEO, Manufacturer_Part_Number=RC0603JR-070RL, Package=0603
R7 R420: library part MCD-00223, "Resistor,100K,0603,1%,1/10W", Manufacturer=YAGEO, Manufacturer_Part_Number=RC0603FR-07100KL, Package=0603
R8 R9: library part MCD-00184, "Resistor,3K3,0402,1%,1/16W", Manufacturer=YAGEO, Manufacturer_Part_Number=RC0402FR-073K3L, Package=0402
R10 R11 R13 R14 R171 R189 R193 R224 R227 R228 R242 R247: library part MCD-00063, "Resistor,47K,0402,1%,1/16W", Manufacturer=YAGEO, Manufacturer_Part_Number=RC0402FR-0747KL, Package=0402
R16 R20 R21 R23 R24 R29 R33 R34 R39 R48 R49 R51 R54 R56 R58 R61 R62 R63 R64 R65 R66 R68 R69 R70 R71 R73 R74 R75 R76 R77 R78 R80 R82 R87 R88 R89 R93 R95 R96 R97 R98 R101 R102 R103 R104 R105 R108 R110 R113 R114 R115 R116 R117 R118 R119 R121 R122 R124 R127 R128 R131 R132 R135 R136 R137 R139 R140 R161 R162 R177 R205 R208 R216 R229 R230 R233 R234 R236 R237 R240 R241 R244 R245 R250 R251 R255 R257 R258 R261 R262 R263 R271 R272 R280 R281 R283 R286 R287 R289 R292 R295 R296 R297 R300 R308 R316 R318 R319 R320 R322 R324 R325 R326 R331 R332 R333 R334 R335 R337 R338 R339 R340 R341 R342 R343 R344 R345 R347 R348 R349 R350 R351 R352 R353 R354 R356 R357 R358 R359 R360 R361 R362 R363 R364 R365 R366 R367 R368 R369 R370 R371 R372 R373 R374 R375 R378 R380 R381 R382 R384 R385 R386 R387 R389 R390 R391 R397 R398 R399 R401 R403 R404 R405 R406 R407 R409 R411 R413: library part MCD-00052, "Resistor,0R,0402,5%,1/16W", Manufacturer=YAGEO, Manufacturer_Part_Number=RC0402JR-070RL, Package=0402
R32 R53 R57 R59 R218 R222 R252: library part MCD-00482, "Resistor,47R,0603,1%,1/10W", Manufacturer=YAGEO, Manufacturer_Part_Number=RC0603FR-0747RL, Package=0603
R36 R225: library part MCD-00528, "Resistor,820R,0603,1%,1/10W", Manufacturer=YAGEO, Manufacturer_Part_Number=RC0603FR-07820RL, Package=0603
R37: library part MCD-00570, "Resistor,8K06,0603,1%,1/10W", Manufacturer=YAGEO, Manufacturer_Part_Number=RC0603FR-078K06L, Package=0603
R38 R145 R157 R164 R417 R418: library part MCD-00067, "Resistor,100R,0402,1%,1/16W", Manufacturer=YAGEO, Manufacturer_Part_Number=RC0402FR-07100RL, Package=0402
R40 R150 R172 R416 R419: library part MCD-00059, "Resistor,100K,0402,1%,1/16W", Alternate_Manufacturer=YAGEO, Alternate_Manufacturer_Part_Number=RT0402FRE07100KL, Manufacturer_Part_Number=RC0402FR-07100KL, Package=0402
R41 R146 R147 R154 R211 R212: library part MCD-00065, "Resistor,4K7,0402,1%,1/16W", Alternate_Manufacturer=YAGEO, Alternate_Manufacturer_Part_Number=RT0402FRE074K7L, Manufacturer_Part_Number=RC0402FR-074K7L, Package=0402
R42 R179 R195: library part MCD-00461, "Resistor,360R,0402,1%,1/16W", Manufacturer=YAGEO, Manufacturer_Part_Number=RC0402FR-07360RL, Package=0402
R43 R279 R377 R388 R392 R393 R394 R396: library part MCD-00061, "Resistor,1K,0402,1%,1/16W", Manufacturer=YAGEO, Manufacturer_Part_Number=RC0402FR-071KL, Package=0402
R44 R182: library part MCD-00179, "Resistor,0R,0805,5%", Manufacturer=YAGEO, Manufacturer_Part_Number=RC0805JR-070RL, Package=0805
R46 R178 R196: library part MCD-00441, "Resistor,270R,0402,1%,1/16W", Manufacturer=YAGEO, Manufacturer_Part_Number=RC0402FR-07270RL, Package=0402
R83: library part MCD-00443, "Resistor,27K,0402,1%,1/16W", Manufacturer=YAGEO, Manufacturer_Part_Number=RC0402FR-0727KL, Package=0402
R86 R92 R107 R336 R346: library part MCD-00164, "Resistor,220K,0402,1%,1/16W", Manufacturer=YAGEO, Manufacturer_Part_Number=RC0402FR-07220KL, Package=0402
R90: library part MCD-00493, "Resistor,56K,0402,1%,1/16W", Manufacturer=YAGEO, Manufacturer_Part_Number=RC0402FR-0756KL, Package=0402
R112: library part MCD-00499, "Resistor,620R,0402,1%,1/16W", Manufacturer=YAGEO, Manufacturer_Part_Number=RC0402FR-07620RL, Package=0402
R149: library part MCD-00527, "Resistor,820R,0402,1%,1/16W", Manufacturer=YAGEO, Manufacturer_Part_Number=RC0402FR-07820RL, Package=0402
R153: library part MCD-00055, "Resistor,2K7,0402,1%,1/16W", Manufacturer=YAGEO, Manufacturer_Part_Number=RC0402FR-072K7L, Package=0402
R159: library part MCD-00593, "Ferrite bead, 600R @ 100MHz,  1.3A, 150mOhm, 0603", Manufacturer=MURATA, Manufacturer_Part_Number=BLM18KG601SN1D, Package=0603
R163: library part MCD-00064, "Resistor,510R,0402,1%,1/16W", Manufacturer=YAGEO, Manufacturer_Part_Number=RC0402FR-07510RL, Package=0402
R165: library part MCD-00185, "Resistor,3K,0402,1%,1/16W", Manufacturer=YAGEO, Manufacturer_Part_Number=RC0402FR-073KL, Package=0402
R176: library part MCD-00194, "Resistor,120R,0402,1%,1/16W", Manufacturer=YAGEO, Manufacturer_Part_Number=RC0402FR-07120RL, Package=0402
R180 R328 R329: library part MCD-00178, "Resistor,470R,0402,1%,1/16W", Manufacturer=YAGEO, Manufacturer_Part_Number=RC0402FR-07470RL, Package=0402
R181: library part MCD-00449, "Resistor,300R,0402,1%,1/16W", Manufacturer=YAGEO, Manufacturer_Part_Number=RC0402FR-07300RL, Package=0402
R190 R192: library part MCD-00197, "Resistor,330R,0603,1%,1/10W", Manufacturer=YAGEO, Manufacturer_Part_Number=RC0603FR-07330RL, Package=0603
R197 R198: library part MCD-00070, "Resistor,1K,0603,1%,1/10W", Manufacturer=YAGEO, Manufacturer_Part_Number=RC0603FR-071KL, Package=0603
R200: library part MCD-00680, "Resistor, SMD PTS 100ohm @ 0°C Flat Chip Temperature Sensor", Manufacturer=VISHAY, Manufacturer_Part_Number=PTS060301B100RP100, Package=0603
R203: library part MCD-00352, "Resistor,3K3,0603,1%,1/10W", Manufacturer=YAGEO, Manufacturer_Part_Number=RC0603FR-073K3L, Package=0603
R204: library part MCD-00224, "Resistor,100R,0603,1%,1/10W", Manufacturer=YAGEO, Manufacturer_Part_Number=RC0603FR-07100RL, Package=0603
R214 R215 R226 R243 R248 R249 R254 R256 R259 R260 R264 R265 R269 R270 R276 R290 R291 R293 R299 R302 R303 R305 R306 R310 R312 R313 R315 R317: library part MCD-01986, "Ferrite bead, 470ohms at 100MHz, 200mA, 0.6ohms DC max", Manufacturer=Murata, Manufacturer_Part_Number=BLM15BD471SN1D, Package=0402
R267 R268: library part MCD-00047, "SMD Chip ferrite bead, 600R@100MHz +/-25%, 350mA, 500mohm DC, 0603, T=0.8mm", Manufacturer=TAI-TECH, Manufacturer_Part_Number=FCM1608KF-601T03, Package=0603
R410 R412: library part MCD-00564, "Resistor,49R9,0603,1%,1/10W", Manufacturer=YAGEO, Manufacturer_Part_Number=RC0603FR-0749R9L, Package=0603
R415: library part MCD-00349, "Resistor,2K2,0603,1%,1/10W", Manufacturer=YAGEO, Manufacturer_Part_Number=RC0603FR-072K2L, Package=0603
RV1: library part MCD-00575, "TRIMMER 10K OHM 0.5W PC PIN", Manufacturer=BOURNS, Manufacturer_Part_Number=3386P-1-103, Package=3386P
SB1 SB2 SB3 SB4 SB5 SB6 SB7 SB8 SB9 SB10 SB11 SB12 SB13 SB14 SB15 SB16 SB17 SB18 SB19 SB20 SB21 SB22 SB23 SB24 SB25 SB26 SB27 SB28 SB29 SB30 SB31 SB32 SB33 SB34 SB35 SB36 SB37 SB38 SB39 SB40 SB43 SB44 SB45 SB46: library part MCD-00071, "Solder Bridge ON", Manufacturer=YAGEO, Manufacturer_HQ_COO=Unknown, Manufacturer_Part_Number=RC0603JR-070RL, Package=0603
SB41 SB42 SB47 SB48 SB49 SB50 SB51 SB52: library part MCD-01618, "Solder Bridge 0402 ON", Manufacturer=YAGEO, Manufacturer_Part_Number=RC0402JR-070RL, Package=0402
SW1: library part MCD-00566, "Mechanical Slide Switches 1K2 BLK ACT GOLD STRT MNT", Manufacturer=EAO, Manufacturer_Part_Number=09.03290.01, Package=2.5x10mm
T1 T2: library part MCD-00073, "NPN Bipolar Transistor", Alternate_Manufacturer="ON SEMICONDUCTOR", Alternate_Manufacturer_Part_Number="MMBT2222LT1G / MMBT2222ALT1G / MMBT2222ALT3G", Manufacturer_Part_Number=BSR14, Package=SOT23
TP1 TP10 TP12 TP17 TP18 TP19 TP20 TP21: library part MCD-00712, "RS Pro 1mm Red Test Terminal", Manufacturer="RS PRO", Manufacturer_Part_Number=262-2185, Package=2.35x2.35mm
TP2 TP3 TP4 TP5 TP6 TP7 TP8 TP9 TP11 TP13 TP14 TP15 TP16 TP22 TP23 TP26 TP27: library part MCD-00074, "Test Point 1mm", Manufacturer=n/a, Manufacturer_HQ_COO=Unknown
TP24 TP25: library part MCD-01506, "Test Point trought hole 1mm/2mm", Manufacturer=n/a
TPG1 TPG2 TPG3 TPG4: library part MCD-00713, "Vero Technologies 1.02mm Black Terminal Post", Manufacturer=VERO, Manufacturer_Part_Number=20-2137, Package=2.35x2.35mm
U1: library part MCD-00721, "LDO Voltage Regulator, Adjustable, 15V in, 1.1V drop, 1.25V to 15V/0.8A out, SOT-223-3", Manufacturer=STMICROELECTRONICS, Manufacturer_HQ_COO=EU, Package=SOT-223
U2: library part MCD-00668, "Low voltage 0.5 ohm single SPDT switch with break-before-make feature and 15 kV contact ESD protection", Manufacturer=STMICROELECTRONICS, Manufacturer_HQ_COO=EU, Manufacturer_Part_Number=STG4160BJR, Package=Flip-Chip-8
U3 U4 U38 U40: library part MCD-00667, "4-line ESD protection for high speed lines", Manufacturer=STMICROELECTRONICS, Manufacturer_HQ_COO=EU, Package=uQFN-10
U5: library part MCD-01929, "STM32H7B3LIH6Q (crypto),TFBGA 225, 13x13 0.8", Manufacturer=STMICROELECTRONICS, Manufacturer_HQ_COO=EU, Manufacturer_Part_Number=STM32H7B3LIH6Q, Package=TFBGA-225
U6 U31 U32 U34 U35 U43 U44 U45: library part MCD-00170, "ESD protection 6V1", Manufacturer=STMICROELECTRONICS, Manufacturer_HQ_COO=EU, Manufacturer_Part_Number=ESDALC6V1-1U2, Package=ST0201
U7: library part MCD-00569, "USB3320C,  Hi-Speed USB Host, Device or OTG PHY with ULPI Low Pin Interface", Manufacturer=MICROCHIP, Manufacturer_Part_Number=USB3320C-EZK-TR, Package=QFN-32
U8 U23 U33: library part MCD-00251, "High power transient voltage suppressor, 7V breakdown", Manufacturer=STMICROELECTRONICS, Manufacturer_HQ_COO=EU, Manufacturer_Part_Number=ESDA7P60-1U1M, Package=QFN1610
U9: library part MCD-00152, "RS-232 transceiver with auto-power-down", Manufacturer=STMICROELECTRONICS, Manufacturer_HQ_COO=EU, Package=SSOP-28
U10: library part MCD-00581, "LDO Linear Voltage Regulator IC Positive Adjustable 1 Output Adjustable 1.3A 6-DFN (3x3)", Manufacturer=STMICROELECTRONICS, Manufacturer_HQ_COO=EU, Package=DFN-6
U11: library part MCD-00246, "Memory,Octo-SPI-NOR,512Mb,2048x16,133MHz,3V,DTR,BGA24, CMOS MXSMIO", Manufacturer=MACRONIX, Package=BGA-24
U12: library part MCD-01345, "NOR FLASH 128Mbit 75ns - 64-ball LBGA (replacing PC28F128M29EWLA)", Manufacturer=MICRON, Manufacturer_Part_Number=MT28EW128ABA1LPC-0SIT, Package=LBGA-64
U13: library part MCD-00078, "Ultra low drop-low noise BiCMOS voltage, regulators low ESR capacitors compatible", Manufacturer=STMICROELECTRONICS, Manufacturer_HQ_COO=EU, Package=SOT23-5
U14 U15: library part MCD-01025, "LDO, 3.3V, 1.3A, Very low quiescent current BiCMOS voltage regulator", Manufacturer=STMICROELECTRONICS, Manufacturer_HQ_COO=EU, Package=DFN-6
U16: library part MCD-00562, "SDRAM 256MBit 166MHZ 90BGA", Alternate_Manufacturer=ISSI, Manufacturer_Part_Number=IS42S32800J-6BLI, Package=TFBGA-90
U17: library part MCD-00560, "SRAM 16Mb 10ns 1Mx16 Async SRAM 3.3v", Manufacturer=ISSI, Package=miniBGA-48
U18 U20: library part MCD-00247, "Quad Bidir ESD protection", Manufacturer=STMICROELECTRONICS, Manufacturer_HQ_COO=EU, Package=SOT23-6
U19: library part MCD-00086, "Ultra low drop-low noise BiCMOS voltage, regulators low ESR capacitors compatible", Manufacturer=STMICROELECTRONICS, Manufacturer_HQ_COO=EU, Package=SOT23-5
U21: library part MCD-00596, "STM32F723IEK  (STM32F7) BGA176", Manufacturer=STMICROELECTRONICS, Manufacturer_HQ_COO=EU, Manufacturer_Part_Number=STM32F723IEK6, Package=UFBGA-201
U22 U29 U39: library part MCD-00159, "500mA, Enhanced single channel power switches with active high enable pin", Alternate_Manufacturer="TEXAS INSTRUMENTS", Alternate_Manufacturer_Part_Number=TPS2051C, Manufacturer=STMICROELECTRONICS, Package=SOT23-5
U24: library part MCD-01999, "44 pins Interposer for WIFI module (MB1486 module is with INVENTEK ISM43340-M4G-L44-10CF)", Manufacturer=STMICROELECTRONICS, Manufacturer_HQ_COO=EU, Manufacturer_Part_Number="MB1486 - WIFI MODULE WITH INVENTEK ISM43340-M4G-L44-10CF", Package=11.5x13.5mm
U25: library part MCD-00135, "Ultra-low-power 32-bit MCU ARM", Manufacturer=STMICROELECTRONICS, Manufacturer_HQ_COO=EU, Package=LQFP-48
U26 U41: library part MCD-00649, "Common mode filter with ESD protection for USB 2.0 interface", Manufacturer=STMICROELECTRONICS, Manufacturer_HQ_COO=EU, Package=QFN-6
U27: library part MCD-01358, "Automotive dual-line Transil, transient voltage suppressor (TVS) for CAN bus 36V. Compliant with interfaces in automotive: CAN-FD, LIN, FlexRay, MOST, SENT, USB", Manufacturer=STMICROELECTRONICS, Manufacturer_HQ_COO=EU, Manufacturer_Part_Number=ESDCAN05-2BWY, Package=SOT323-3
U28: library part MCD-00129, "High-Speed CAN Flexible Data Rate Transceiver", Manufacturer=MICROCHIP, Manufacturer_Part_Number=MCP2562FDT-H/SN, Package=SO-8
U30: library part MCD-00163, "Very low capacitance ESD protection", Manufacturer=STMICROELECTRONICS, Package=SOT23-6
U36 U37: library part MCD-00681, "Smart sensor II dual-channel 1-bit, 4 MHz, second-order sigmadelta modulator with embedded PGLNA", Manufacturer=STMICROELECTRONICS, Manufacturer_HQ_COO=EU, Package=QFN-16
U42 U46 U47: library part MCD-00136, "Dual Transil array for ESD protection", Manufacturer=STMICROELECTRONICS, Manufacturer_HQ_COO=EU, Package=SOT323-5
U48: library part MCD-00265, "Low-Power, Stereo Codec with Headphone Amp", Manufacturer="CIRRUS LOGIC", Package=QFN-32
U49: library part MCD-01066, "5 unidirectional Transil diodes ESD protection", Manufacturer=STMICROELECTRONICS, Manufacturer_HQ_COO=EU, Package=SOT23-6
X1: library part MCD-01036, "Crystal 24MHz, 6pF, +-20ppm, 80ohms max, SMD", Manufacturer=NDK, Manufacturer_Part_Number=NX2016SA-24MHZ-EXS00A-CS10820, Package=2x1.6mm
X2: library part MCD-00091, "Crystal 32.768kHz, 6pF, +-20ppm, 50Kohms max, SMD", Manufacturer=NDK, Manufacturer_Part_Number=NX3215SA-32.768KHZ-EXS00A-MU00525, Package=3.2x1.5mm
X3: library part MCD-01976, "Oscillator, SPXO, 24MHz, +/-50ppm, square wave, 3V3, 2.5x2mm", Manufacturer=NDK, Manufacturer_Part_Number=NZ2520SH-24MHZ-END4869D, Package=2.5x2mm
X4: library part MCD-00597, "Oscillator 25Mhz, +-50ppm, Vcc:3.3V typ, square wave: [0.1Vcc;0.9Vcc], Enable pin, SMD", Alternate_Manufacturer=NDK, Alternate_Manufacturer_Part_Number="NZ2520SB 25MHz END4869B", Manufacturer_Part_Number=NZ2520SH-25MHZ-END4869C, Package=2.5x2mm
Z1: library part MCD-00149, "Protection circuit Zener Diode", Manufacturer=LITTELFUSE, Package=3.85x3.85mm

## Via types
v1: diameter 0.6, hole 0.254, Top Layer to Bottom Layer, tented both sides, 1747 vias
v2: diameter 0.45, hole 0.2, Top Layer to Bottom Layer, tented both sides, 272 vias
v3: diameter 0.406, hole 0.203, Top Layer to Bottom Layer, tented both sides, 160 vias
v4: diameter 0.6, hole 0.25, Top Layer to Bottom Layer, tented both sides, 82 vias
v5: diameter 0.45, hole 0.25, Top Layer to Bottom Layer, tented both sides, 45 vias
v6: diameter 0.5, hole 0.25, Top Layer to Bottom Layer, tented both sides, 23 vias
v7: diameter 1.016, hole 0.508, Top Layer to Bottom Layer, tented both sides, 17 vias
v8: diameter 0.508, hole 0.254, Top Layer to Bottom Layer, tented both sides, 9 vias
v9: diameter 0.61, hole 0.305, Top Layer to Bottom Layer, tented both sides, 7 vias
v10: diameter 0.5, hole 0.254, Top Layer to Bottom Layer, tented both sides, 6 vias
v11: diameter 0.4, hole 0.2, Top Layer to Bottom Layer, tented both sides, 1 vias
v12: diameter 0.483, hole 0.254, Top Layer to Bottom Layer, tented both sides, 1 vias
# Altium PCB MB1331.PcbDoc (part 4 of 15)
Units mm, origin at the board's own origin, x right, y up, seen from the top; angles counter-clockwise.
Board outline 169.25 x 173.25 mm, 6 copper layers (Top Layer, Signal Layer 1, Signal Layer 2, Signal Layer 3, Signal Layer 4, Bottom Layer), stack 1.556 mm thick; 871 components, 699 nets, 3244 pads, 2370 vias.

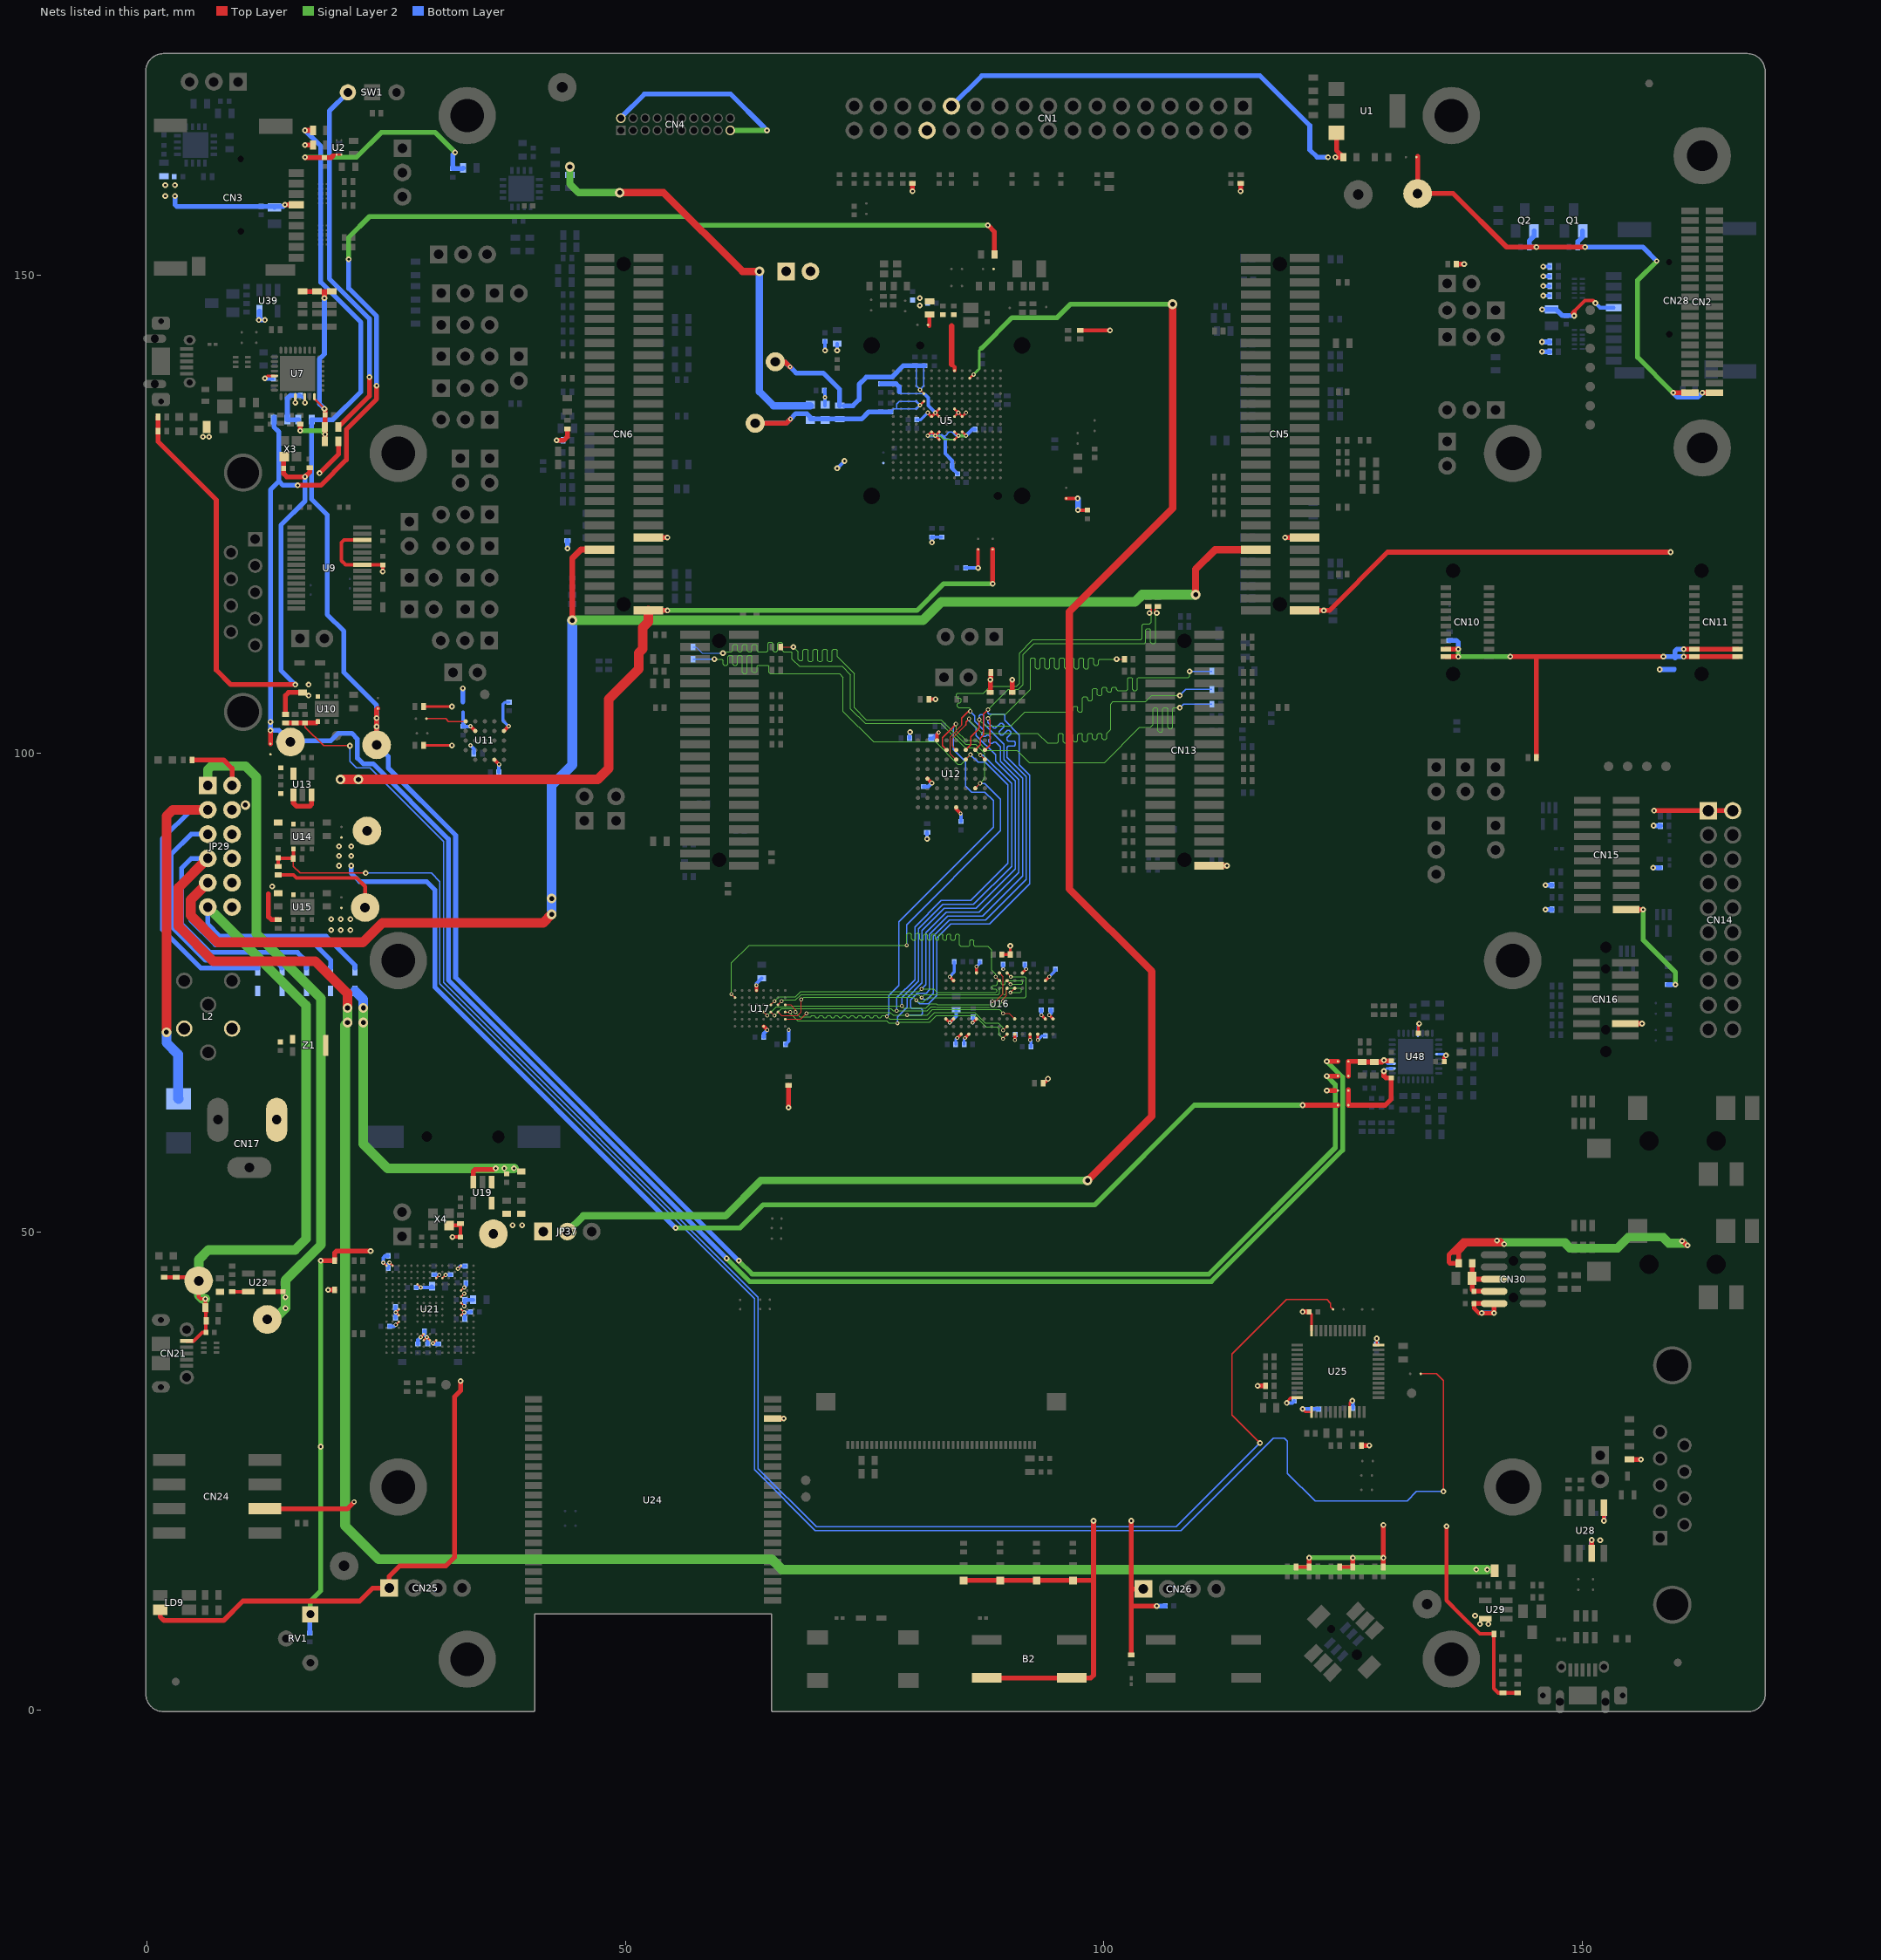
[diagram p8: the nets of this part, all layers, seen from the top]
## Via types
v1: diameter 0.6, hole 0.254, Top Layer to Bottom Layer, tented both sides, 1747 vias
v2: diameter 0.45, hole 0.2, Top Layer to Bottom Layer, tented both sides, 272 vias
v3: diameter 0.406, hole 0.203, Top Layer to Bottom Layer, tented both sides, 160 vias
v4: diameter 0.6, hole 0.25, Top Layer to Bottom Layer, tented both sides, 82 vias
v5: diameter 0.45, hole 0.25, Top Layer to Bottom Layer, tented both sides, 45 vias
v6: diameter 0.5, hole 0.25, Top Layer to Bottom Layer, tented both sides, 23 vias
v7: diameter 1.016, hole 0.508, Top Layer to Bottom Layer, tented both sides, 17 vias
v8: diameter 0.508, hole 0.254, Top Layer to Bottom Layer, tented both sides, 9 vias
v9: diameter 0.61, hole 0.305, Top Layer to Bottom Layer, tented both sides, 7 vias
v10: diameter 0.5, hole 0.254, Top Layer to Bottom Layer, tented both sides, 6 vias
v11: diameter 0.4, hole 0.2, Top Layer to Bottom Layer, tented both sides, 1 vias
v12: diameter 0.483, hole 0.254, Top Layer to Bottom Layer, tented both sides, 1 vias

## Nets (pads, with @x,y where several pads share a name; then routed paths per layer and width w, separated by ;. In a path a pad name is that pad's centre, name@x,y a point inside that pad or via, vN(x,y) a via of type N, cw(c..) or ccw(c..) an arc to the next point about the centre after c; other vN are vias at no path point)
1V8_AO: C21.2 R274.1 SB4.2 SB22.2 SB25.1 TP12.1 | length 303.3
  Top Layer w0.5: SB22.2@12.9,101 v1(12.9,102.4) ; v1(15.748,128.016) 18.161,128.016 20.828,130.683 20.828,133.858 24.003,137.033 v1(24.003,138.43) ; v1(87.884,155.194) 87.887,155.194 88.584,154.497 C21.2@88.584,152.146 ; v1(123.317,67.818) SB25.1@124.468,67.818
  Signal Layer 2 w0.5: v1(21.082,151.638) 21.082,153.924 23.258,156.1 56.498,156.1 57.404,155.194 v1(87.884,155.194) ; v1(60.579,47.244) 62.992,44.831 111.252,44.831 124.968,58.547 124.968,66.167 v1(123.317,67.818)
  Bottom Layer w0.5: R274.1@13.27,135.128 R274.1@13.27,134.874 13.27,134.112 13.778,133.604 13.778,128.462 ; TP12.1@15.494,101.346 14.854,101.346 13.8,102.4 v1(12.9,102.4) v1(12.9,103.3) 12.9,127.54 13.8,128.44 14.224,128.016 v1(15.748,128.016) ; TP12.1@15.5,101.3 19.2,101.3 20,102.1 21.4,102.1 22,101.5 22,99.514 22.6,98.914 23.641,98.914 31.496,91.059 31.496,76.327 v1(60.579,47.244) ; v1(21.082,151.638) 21.082,148.59 24.003,145.669 v1(24.003,138.43)
1V8_CODEC: C56.2 C58.2 C59.2 C60.1 C61.1 SB25.2 SB26.2 U48.5 U48.12 U48.27 | length 10.5
  Top Layer w0.254: C56.2@132.888,70.751 v1@132.888,71.674
  Top Layer w0.381: C59.2@135.578,67.818 135.578,68.268 v1(135.763,68.453)
  Top Layer w0.508: SB26.2@125.568,66.294 SB25.2@125.568,67.818 126.938,67.818 C60.1@127,67.756 C61.1@128.27,67.756 129.097,67.756 v1(129.286,67.945) 129.355,67.876 C58.2@130.048,67.876
  Bottom Layer w0.254: v1(129.286,67.945) 129.298,67.945 129.667,67.576 U48.27@130.163,67.576 ; U48.5@132.838,70.751 132.838,71.497 v1@132.969,71.628 ; U48.12@135.013,68.576 135.64,68.576 v1(135.763,68.453)
  other v1: 132.969,71.755
1V8_LDO: C47.2 SB22.1 U13.5
1V8_SW: R4.1 R273.1 SB19.2 SB26.1 TP10.1 | length 225.7
  Top Layer w0.508: v1(16.51,165.1) R4.1@17.334,165.1 ; TP10.1@24,100.9 v1(24,102.8) v1(24,103.7) 24,104.6 SB19.2@24.1,104.7 ; v1(123.317,66.294) SB26.1@124.468,66.294
  Signal Layer 2 w0.508: v1(61.849,46.99) 63.246,45.593 110.998,45.593 124.206,58.801 124.206,65.405 v1(123.317,66.294)
  Bottom Layer w0.508: v1(16.51,165.1) 18.161,163.449 18.161,149.225 22.352,145.034 22.352,137.795 19.431,134.874 R273.1@17.21,134.874 17.21,126.554 18.825,124.939 18.825,114.525 20.574,112.776 20.574,108.458 24,105.032 v1(24,103.7) v1(24,102.8) TP10.1@24,100.9 ; TP10.1@24,99.698 TP10.1@24,100.9 ; 32.2,91.5 25.2,98.5 25.2,99.7 TP10.1@24,100.9 ; 32.258,91.44 32.258,76.581 v1(61.849,46.99)
1V8_SW_ENABLE: C45.1 R99.2 R100.1 SB29.1 U10.1 | length 186
  Top Layer w0.127: C45.1@16.51,103.182 16.51,102.743 18.453,100.8 v1(21.2,100.8) ; v1(116.332,27.94) 113.411,30.861 113.411,37.236 119.101,42.926 123.317,42.926 123.698,42.545 123.698,42.172 SB29.1@123.96,41.91
  Top Layer w0.508: R99.2@14.478,103.182 R100.1@15.494,103.182 C45.1@16.51,103.182 17.68,103.182 U10.1@17.846,103.348
  Bottom Layer w0.127: v1(21.2,100.8) 21.2,99.2 21.9,98.5 23.293,98.5 30.988,90.805 30.988,76.073 63.881,43.18 63.881,25.273 69.977,19.177 107.569,19.177 v1(116.332,27.94)
1V8_USBHS: C117.1 R273.2 R274.2 U7.28 U7.30 | length 8
  Top Layer w0.254: v1(15.494,136.652) 15.498,136.656 U7.28@15.498,137.275 ; U7.30@16.498,137.275 16.498,136.664 v1(16.51,136.652)
  Bottom Layer w0.254: v1(15.494,136.652) 15.494,137.033 15.875,137.414 C117.1@16.06,137.414 16.51,136.964 v1(16.51,136.652)
  Bottom Layer w0.508: R273.2@15.81,134.874 R274.2@14.67,134.874 14.67,137.098 14.986,137.414 C117.1@15.875,137.414
2V8: C114.2 C115.2 CN2.39 CN2.40 Q1.1 Q2.1 R211.2 R212.2 SB1.2 TP1.1 | length 59.7
  Top Layer w0.508: 132.8,162.4 TP1.1@132.8,158.5 136.521,158.5 142.113,152.908 v1(145.225,152.908) v1(150.304,152.908) ; v1(159.513,137.685) CN2.39@161.28,137.685 ; v1@162.561,137.685 CN2.40@163.83,137.685
  Signal Layer 2 w0.508: v6(157.797,151.447) 155.8,149.45 155.8,141.398 v1(159.513,137.685)
  Bottom Layer w0.508: Q2.1@144.968,154.602 144.968,154.049 144.468,153.548 R212.2@144.468,152.908 v1(145.225,152.908) ; Q1.1@150.048,154.602 150.048,153.985 149.548,153.485 R211.2@149.548,152.908 v1(150.304,152.908) 156.337,152.908 v6(157.797,151.447) ; v1(159.513,137.685) 159.98,137.218 C115.2@160.528,137.218 C114.2@161.798,137.218 162.094,137.218 v1(162.56,137.684)
3V3_AO: B2.1 B2.2 C34.2 C41.1 C42.1 C55.1 C73.1 C79.2 C100.1 C101.1 C133.2 C134.1 C136.1 C137.1 C138.1 C139.1 C140.1 C141.1 C142.2 C143.1 C144.2 C145.1 C146.1 C149.1 C150.1 C152.1 C153.1 C154.1 C155.1 C156.1 C158.1 C189.2 C193.2 C194.2 C195.2 C196.1 C198.2 C199.1 CN1.28 CN4.2 CN4.19 CN5.48 CN6.48 CN13.40 CN14.1 CN14.2 CN15.1 CN16.3 CN24.4 CN26.1 CN28.4 CN30.2 JP3.1 JP37.1 LD1.1 LD2.1 LD3.1 LD4.1 R8.2 R9.2 R15.2 R31.1 R42.2 R43.1 R45.1 R46.2 R52.1 R79.2 R84.2 R85.1 R91.2 R99.1 R130.1 R134.2 R142.2 R143.2 R146.2 R166.1 R173.2 R174.1 R183.2 R184.2 R185.2 R186.2 R187.2 R193.2 R194.2 R195.2 R196.2 R217.2 R224.2 R227.2 R231.2 R242.2 R247.2 R279.1 R298.2 R376.2 R377.2 R388.2 R392.2 R394.2 R396.2 RV1.1 SB24.2 SB27.1 SB39.2 SB40.1 SW1.2 TP18.1 U9.22 U9.26 U10.6 U12.D8 U12.F1 U12.G5 U16.A7 U16.B2 U16.B7 U16.C9 U16.D9 U16.E1 U16.F9 U16.L1 U16.L7 U16.M9 U16.N9 U16.P2 U16.P7 U16.R7 U17.D6 U17.E1 U25.1 U25.9 U25.24 U25.36 U25.48 U28.5 X3.4 | length 442.8
  Top Layer w0.127: CN16.3@154.492,71.778 CN16.3@154.5,71.77
  Top Layer w0.254: v1@119.126,32.258 119.551,32.683 U25.48@120.21,32.683 ; v1(120.777,31.496) 121.09,31.183 U25.1@121.71,31.183 ; C73.1@121.47,41.656 121.71,41.416 U25.36@121.71,39.683 ; U25.9@125.71,31.183 125.71,32.095 v1(125.972,32.357) ; v1(128.524,38.862) 128.524,38.227 128.568,38.183 U25.24@128.71,38.183
  Top Layer w0.305: U16.R7@83.497,72.263 v3(83.897,71.863) U16.P7@84.297,72.263 ; v3(83.897,76.664) U16.P2@84.297,76.263 ; v3(84.696,70.263) U16.N9@85.097,70.663 ; v3(85.496,70.263) U16.M9@85.897,70.663 ; v3(86.296,71.863) U16.L7@86.696,72.263 ; U16.L1@86.697,77.063 v3@86.697,77.66 ; C55.1@89.35,78.994 R134.2@90.228,78.994 v1(90.228,79.888) ; v3@90.697,70.066 U16.F9@90.697,70.663 ; U16.E1@91.497,77.063 v3(91.896,77.463) ; v3@92.297,70.066 U16.D9@92.297,70.663 ; U16.C9@93.097,70.663 93.097,70.066 v3(93.11,70.053) ; v3(93.496,72.663) U16.B7@93.897,72.263 ; U16.B2@93.897,76.263 v3(94.296,76.663) ; v3(94.296,72.663) U16.A7@94.697,72.263
  Top Layer w0.381: R130.1@13.716,87.307 15.309,87.307 15.621,86.995 21.905,86.995 22.8,86.1 22.8,84.395 TP18.1@21.844,83.439 ; 21.265,119.705 U9.22@22.5,119.705 ; 21.34,122.305 U9.26@22.5,122.305 20.578,122.305 20.32,122.047 20.32,120.142 20.757,119.705 U9.22@22.5,119.705 ; v1(24.638,118.999) C41.1@24.638,119.692 24.625,119.705 U9.22@22.5,119.705 ; v3(63.697,75.768) 63.697,75.237 U17.E1@63.703,75.23 ; U17.D6@64.453,71.48 v3(64.828,71.105) ; U12.G5@81.567,97.366 v12(82.035,96.898) ; R91.2@81.73,105.664 v4(82.423,105.664) ; U12.F1@82.567,101.366 82.567,102.005 v3(82.747,102.184) ; U12.D8@84.568,94.366 84.568,94.187 v3(85.033,93.722) ; R143.2@93.668,65.532 93.719,65.532 v9(94.177,65.989) ; R31.1@97.536,144.214 v1(100.653,144.214) ; R183.2@120.084,14.986 R184.2@121.47,14.986 ; R185.2@124.656,14.986 R186.2@126.042,14.986 ; v1(135.826,19.241) 135.826,11.493 137.287,10.033 ; 136.271,11.049 137.287,10.033 ; R195.2@141.478,1.836 141.224,1.836 140.774,2.286 R193.2@140.774,8.001 139.319,8.001 137.287,10.033 ; R195.2@141.732,1.836 R196.2@143.256,1.836 ; 148.971,145.987 149.161,146.177 150.304,147.32 151.13,147.32 ; 150.495,147.32 151.13,147.32 ; v1(151.384,147.066) 151.13,147.32 ; v1(152.273,19.812) U28.5@152.273,21.171
  Top Layer w0.45: C79.2@138.7,42.525 138.7,42.025 139.2,41.525 v1(139.5,41.525) v1(140.8,41.525)
  Top Layer w0.5: v1(118.95,122.555) CN5.48@120.972,122.555
  Top Layer w0.508: R42.2@1.165,135.165 R46.2@1.165,133.665 1.165,132.566 7.239,126.492 7.239,108.712 8.763,107.188 v1(15.494,107.188) ; CN24.4@12.308,21.085 20.958,21.085 v6@21.59,21.717 ; X3.4@14.361,131.001 14.282,130.922 C34.2@14.282,129.794 14.282,129.228 14.605,128.905 v1(16.51,128.905) 17.018,129.413 R52.1@17.018,129.852 ; R99.1@14.478,104.082 14.478,105.156 ; 14.478,105.475 14.478,105.156 ; C42.1@16.256,106.364 14.797,106.364 14.478,106.045 14.478,105.156 ; v4(18.161,46.99) R146.2@19.55,46.99 ; 18.923,46.99 R146.2@19.55,46.99 ; R45.1@20.004,134.112 23.241,137.349 23.241,138.303 ; 23.241,138.938 23.241,138.303 ; v4(23.241,139.319) 23.241,138.303 ; v1(23.368,48.006) 19.812,48.006 19.616,47.81 R146.2@19.616,46.99 R146.2@19.55,46.99 ; v4(42.799,132.715) 43.561,132.715 43.942,133.096 R43.1@43.942,133.916 ; CN6.48@52.393,122.555 v1(54.4,122.555) ; v1(67.056,62.992) R142.2@67.056,65.336 ; v1(80.01,158.75) R8.2@80.01,159.57 ; LD1.1@85.36,13.582 LD2.1@89.17,13.582 LD3.1@92.98,13.582 LD4.1@96.79,13.582 98.926,13.582 ; B2.2@87.753,3.39 B2.1@96.653,3.39 98.64,3.39 98.933,3.683 v1(98.933,19.812) ; R84.2@88.138,106.368 v4(88.138,107.696) 88.196,107.754 R79.2@88.196,108.458 ; R85.1@90.424,106.368 90.424,106.68 ; 90.424,107.061 90.424,106.68 ; v4(90.424,107.696) 90.424,106.68 ; R194.2@102.87,5.784 v1(102.87,19.812) ; 102.933,10.922 v1(105.537,10.922) ; 102.997,12.7 CN26.1@104.14,12.7 ; CN13.40@110.992,88.265 v1(112.881,88.265) ; v4(114.3,158.75) R9.2@114.3,159.57 ; v1(116.078,33.909) R166.1@116.898,33.909 ; v1(120.777,41.656) C73.1@121.47,41.656 ; R184.2@121.47,14.986 v1(121.47,15.944) ; v1(123.317,64.77) 124.206,64.77 ; R186.2@126.042,14.986 v1(126.042,15.944) ; R173.2@126.942,27.686 v1(127.762,27.686) ; R187.2@129.228,14.986 v1(129.228,15.944) v1(129.228,19.373) ; R15.2@136.848,151.13 v1(137.668,151.13) ; C79.2@138.7,42.525 138.705,42.52 CN30.2@140.795,42.52 140.795,41.53 v1(140.8,41.525) ; v1(149.161,145.732) 149.161,146.177 ; CN16.3@154.5,71.77 v1(156.267,71.77) ; CN15.1@154.608,83.685 v1(156.375,83.685) ; R174.1@154.94,26.224 v1(156.148,26.224) ; v1(157.515,94.015) CN14.1@163.195,94.015 CN14.2@165.735,94.015
  Signal Layer 2 w0.508: RV1.1@17.075,10.414 17.075,11.43 18.161,12.516 v1(18.161,27.559) 18.161,45.339 ; 18.161,46.228 18.161,45.339 ; v4(18.161,46.99) 18.161,45.339 ; CN4.19@60.96,165.1 v1(64.8,165.1) ; v1(121.47,15.944) v1(129.228,15.944) ; v1(156.375,83.685) 156.375,80.507 159.75,77.132 v1(159.75,75.85)
  Bottom Layer w0.254: C189.2@128.524,38.296 v1(128.524,38.862)
  Bottom Layer w0.305: v3(83.897,76.664) 84.386,77.153 C139.1@84.386,78.232 ; C155.1@84.524,69.596 84.524,70.091 v3(84.696,70.263) ; C154.1@85.402,69.596 85.402,70.169 v3(85.496,70.263) ; v3@86.336,71.824 v3(86.296,71.863) 86.36,71.927 C149.1@86.36,72.448 ; v3(86.697,77.724) 87.064,78.091 C138.1@87.064,78.232 ; C141.1@89.466,77.978 89.466,77.494 v3(89.497,77.463) ; v3(90.71,70.053) 90.736,70.08 C150.1@90.736,70.612 ; C140.1@91.752,77.978 91.752,77.608 v3(91.896,77.463) ; v3(92.31,70.053) 92.398,69.965 C158.1@92.398,69.342 ; v3(93.11,70.053) 93.541,70.485 C152.1@93.911,70.485 ; v3(94.296,76.663) 94.938,77.305 C143.1@94.938,77.47 ; 159.604,108.775 SB39.2@159.702,108.874
  Bottom Layer w0.381: v3@63.697,75.895 v3(63.697,75.768) 63.697,75.951 C142.2@64.262,76.516 ; C153.1@64.458,70.358 64.458,70.736 v3(64.828,71.105) ; C156.1@66.744,69.596 67.078,69.93 v3(67.078,71.105) ; C134.1@79.698,101.6 79.698,102.177 v4(79.756,102.235) ; C136.1@81.167,96.533 81.671,96.533 v12(82.035,96.898) ; v1(81.534,91.059) R376.2@81.534,91.752 ; C133.2@81.858,101.549 82.112,101.549 v3(82.747,102.184) ; v3(83.897,71.863) 84.582,72.549 C144.2@84.582,73.214 ; v3(85.033,93.722) 85.09,93.664 C137.1@85.09,92.906 ; C146.1@93.472,73.21 93.472,72.688 v3(93.496,72.663) ; v3(94.296,72.663) 94.488,72.855 C145.1@94.488,73.21 ; v1(119.126,32.131) 119.703,32.131 C193.2@119.888,32.316 ; v1(120.777,31.496) C195.2@122.486,31.496 ; v1(125.972,32.357) 126.041,32.288 C194.2@126.041,31.595 ; v1(145.923,147.828) R231.2@146.616,147.828 ; v1(145.923,148.844) R227.2@146.616,148.844 ; v1(145.923,149.86) R224.2@146.616,149.86 ; v1(145.923,150.876) R217.2@146.616,150.876 ; v1(151.384,147.066) 151.873,146.577 CN28.4@153.301,146.577 ; v1(152.273,19.812) 152.342,19.881 C196.1@152.342,20.574
  Bottom Layer w0.508: v1(15.494,107.188) 14,108.682 14,123.855 16.51,126.365 v1(16.51,128.905) ; C199.1@17.018,8.07 17.018,9.993 RV1.1@17.075,10.05 ; 19.05,151.892 19.05,152.4 ; 19.05,152.654 19.05,153.924 ; SW1.2@20.998,169.075 19.05,167.127 19.05,153.924 ; v4(23.241,139.319) 23.241,145.415 19.05,149.606 19.05,152.4 ; SB40.1@33.02,105.402 v4(33.02,106.807) ; v4(42.799,132.715) R279.1@43.492,132.715 ; v4(43.942,121.412) R298.2@43.942,122.232 ; CN4.2@49.53,166.37 49.53,166.449 51.981,168.9 ; 53.34,168.9 51.981,168.9 ; 64.5,165.4 61,168.9 ; v1(64.8,165.1) 61,168.9 ; v1(105.537,10.922) 105.538,10.923 C198.2@106.415,10.923 ; v1(139.5,41.525) v1(140.8,41.525) ; v1(145.796,141.986) R247.2@146.616,141.986 ; v1(145.796,143.002) R242.2@146.616,143.002 ; v1(145.821,146.392) C100.1@146.812,146.392 147.295,146.392 147.95,145.738 C101.1@148.336,145.738 149.156,145.738 v1(149.161,145.732) ; v1(146.177,83.693) R394.2@146.87,83.693 ; v1(146.177,86.233) R392.2@146.87,86.233 ; v1(157.422,88.069) 158.101,88.069 R388.2@158.12,88.05 ; v1(157.48,92.456) 157.499,92.437 R377.2@158.178,92.437 ; v1(158.115,108.775) 159.604,108.775 ; R396.2@159,75.85 v1(159.75,75.85) ; 19.05,152.4 19.05,153.924 ; 51.981,168.9 61,168.9
  other v1: 19.239,81.534 20.255,81.534 21.271,81.534 19.239,82.677 20.255,82.677 21.271,82.677 16.891,106.045 16.891,107.188
  other v6: 21.642,21.792
3V3_CODEC: C62.1 SB27.2 SB28.2 U48.26 | length 10.9
  Top Layer w0.508: SB27.2@125.568,64.862 SB28.2@125.568,63.246 129.413,63.246 130.048,63.881 C62.1@130.048,66.098 129.482,66.098 129.286,66.294 v1(129.286,66.802)
  Bottom Layer w0.254: v1(129.286,66.802) 129.56,67.076 U48.26@130.163,67.076
3V3_MCU: C39.1 C98.1 C99.1 C102.2 C104.1 C112.1 C113.1 C116.1 C120.1 C123.1 C125.1 C127.1 C128.1 C129.1 C130.1 JP3.2 R22.2 R267.1 SB16.1 SB17.2 SB37.2 U5.F7 U5.F9 U5.G6 U5.G7 U5.G9 U5.G10 U5.J6 U5.J7 U5.J9 U5.J10 U5.K7 U5.K9 | length 45.6
  Top Layer w0.254: U5.G10@84.4,132.8 v2(84.8,133.2) U5.G9@84.4,133.6 ; U5.G7@84.4,135.2 v2(84.8,135.6) ; U5.G6@84.4,136 v2(84.8,135.6) ; U5.F9@85.2,133.6 v2(85.6,133.2) ; v2(85.6,135.6) U5.F7@85.2,135.2 v2(84.8,135.6)
  Top Layer w0.3: v2(81.6,133.2) U5.K9@82,133.6 v2(82.4,133.2) ; v2(81.6,135.6) U5.K7@82,135.2 v2(82.4,135.6) ; U5.J10@82.8,132.8 v2(82.4,133.2) ; U5.J9@82.8,133.6 v2(82.4,133.2) ; U5.J7@82.8,135.2 v2(82.4,135.6) ; U5.J6@82.8,136 v2(82.4,135.6)
  Top Layer w0.381: v1(86.868,119.38) SB17.2@86.868,121.32 ; SB16.1@96.075,126.65 v1(97.275,126.65) ; v1@97.275,125.45 v1(97.3,125.425) 97.307,125.418 C39.1@98.298,125.418
  Signal Layer 2 w0.127: v2(81.6,133.2) v2(82.4,133.2) 82.9,133.2 83.3,132.8 84.4,132.8 v2(84.8,133.2)
  Signal Layer 2 w0.381: v2(84.8,133.2) v2(85.6,133.2)
  Bottom Layer w0.127: 78.613,137.795 78.808,137.6 81.221,137.6 81.28,137.541 ; 82.804,133.2 83.081,133.2 83.451,133.2 83.839,133.589 84.161,133.589 84.549,133.2 v2(84.8,133.2) 84.411,132.812 83.839,132.812 83.809,132.842 83.439,132.842
  Bottom Layer w0.3: C120.1@80.46,134.874 80.874,134.874 v2(81.6,135.6) ; C129.1@82.042,122.613 C128.1@83.058,122.613
  Bottom Layer w0.381: R267.1@70.866,136.336 v2(70.866,137.2) C116.1@70.866,137.98 ; v1(70.866,142.113) C104.1@70.866,143.06 ; v1(72.136,129.794) v1(72.898,130.556) ; v1(72.136,142.113) C102.2@72.136,142.81 ; 81.28,137.541 81.661,137.16 81.661,136.339 v2(82.4,135.6) ; v2(81.6,133.2) v2(82.4,133.2) 82.804,133.2 ; v1(82.042,122.047) C129.1@82.042,122.613 ; 83.081,133.2 83.439,132.842 83.439,131.318 84.143,130.614 C125.1@84.143,130.048 84.143,129.794 C127.1@84.709,129.228 ; C130.1@85.54,119.38 v1(86.868,119.38) ; v2(85.6,133.2) 86.258,133.858 C123.1@86.545,133.858
  Bottom Layer w0.508: C113.1@76.708,138.626 C112.1@77.724,138.626 78.29,138.626 78.613,138.303 78.613,137.795
  Bottom Layer w0.6: v1(97.275,126.65) 97.3,126.625 v1(97.3,125.425)
  other v4: 80.772,146.812 80.772,147.574
3V3_OCSPI1: C131.2 C132.2 C135.2 R94.2 R106.1 R355.1 SB40.2 U11.B4 U11.D1 U11.E4 | length 15.4
  Top Layer w0.305: R106.1@28.898,100.838 v1(31.877,100.838) ; R94.2@28.898,104.902 v1(31.877,104.902)
  Top Layer w0.381: v2(33.812,102.84) U11.B4@34.306,102.346 ; U11.D1@36.306,99.346 v2(36.8,98.852) ; U11.E4@37.306,102.346 v2(37.8,102.84)
  Bottom Layer w0.305: v2(37.8,102.84) 37.211,103.429 37.211,105.156 37.407,105.352 C131.2@37.846,105.352
  Bottom Layer w0.381: SB40.2@33.02,104.302 C132.2@33.02,102.812 33.784,102.812 v2(33.812,102.84) ; v2(33.8,100.84) 34.163,100.477 R355.1@34.163,100.018 ; C135.2@36.772,98.044 36.772,98.824 v2(36.8,98.852)
3V3_OCSPI2: CN10.2 CN10.4 CN11.1 CN11.2 CN11.3 CN11.4 R111.1 R321.1 SB39.1 | length 52.3
  Top Layer w0.508: CN10.2@135.75,110.1 v1(137.062,110.1) ; CN10.4@135.75,110.9 v1(137.062,110.9) ; v4(142.494,110.109) v4(158.496,110.109) ; R111.1@145.23,99.568 145.23,110.051 ; v1(160.62,110.1) CN11.2@161.75,110.1 CN11.1@166.25,110.1 ; v1(160.62,110.9) CN11.4@161.75,110.9 CN11.3@166.25,110.9
  Signal Layer 2 w0.508: v1(137.062,110.9) v1(137.062,110.1) 142.485,110.1 v4(142.494,110.109)
  Bottom Layer w0.508: R321.1@136.144,111.818 136.848,111.818 137.062,111.604 v1(137.062,110.9) ; v4(158.496,110.109) 158.505,110.1 SB39.1@159.702,110.1 ; v1(160.62,110.1) 159.829,110.1 ; v1(160.62,110.9) 159.928,110.9 159.702,110.674 SB39.1@159.702,110.1 ; SB39.1@159.702,110.1 SB39.1@159.702,109.974 159.829,110.1 ; SB39.1@159.702,110.1 159.829,110.1
3V3_SMPS_IN: C27.2 C28.2 R22.1 SB10.2 U5.G1 | length 6
  Top Layer w0.4: 81.788,144.653 R22.1@81.788,145.858 ; 84.1,140.675 84.4,140.375 U5.G1@84.4,140
  Top Layer w0.6: 84.1,140.675 84.1,144.675
3V3_STLK: C66.2 C67.2 C69.2 C171.2 C172.2 C173.2 C174.2 C175.2 C176.2 C177.2 C178.2 C179.2 C180.2 C181.2 C182.2 C183.2 C184.2 C185.2 C186.2 C190.2 C191.2 C192.2 CN25.1 LD9.4 R144.1 TP19.1 U19.5 U21.C1 U21.C5 U21.C6 U21.C7 U21.C8 U21.C9 U21.F3 U21.G3 U21.G13 U21.H13 U21.J12 U21.J13 U21.K4 U21.N8 U21.N9 U21.N10 U21.P1 U21.R1 X4.4 | length 80.9
  Top Layer w0.2: v2(24.7,46.8) U21.R1@25.025,46.475 ; v2(25.35,46.8) U21.P1@25.675,46.475 ; v2(26,40.3) U21.N10@26.325,40.625 ; U21.N9@26.325,41.275 v2(26,41.6) U21.N8@26.325,41.925 ; U21.K4@28.275,44.525 v2(28.6,44.2) ; v2(28.6,39) U21.J12@28.925,39.325 ; U21.J13@28.925,38.675 v2(29.25,39) U21.H13@29.575,38.675 ; v2(29.9,38.35) U21.G13@30.225,38.675 ; U21.G3@30.225,45.175 v2(30.55,45.5) ; U21.F3@30.875,45.175 v2(31.2,45.5) ; v2(32.5,46.15) U21.C1@32.825,46.475 ; U21.C9@32.825,41.275 v2(33.15,41.6) U21.C8@32.825,41.925 ; U21.C7@32.825,42.575 v2(33.15,42.25) ; U21.C6@32.825,43.225 v2(33.15,43.55) ; U21.C5@32.825,43.875 v2(33.15,44.2)
  Top Layer w0.381: X4.4@31.559,50.683 32.591,50.683 R144.1@32.766,50.858 C69.2@32.766,49.472 v1(31.935,49.472)
  Top Layer w0.508: LD9.4@1.377,10.528 1.377,9.799 1.778,9.398 8.001,9.398 10.033,11.43 22.225,11.43 23.582,12.787 CN25.1@25.315,12.787 25.315,14.012 26.416,15.113 31.242,15.113 32.131,16.002 32.131,32.766 32.766,33.401 v1(32.766,34.417)
  Bottom Layer w0.381: v2(24.7,46.8) 24.7,47.306 24.892,47.498 C171.2@25.204,47.498 ; C175.2@25.204,46.228 25.204,46.654 v2(25.35,46.8) ; C185.2@25.342,40.132 25.832,40.132 v2(26,40.3) ; v2@25.966,41.814 C183.2@25.966,41.021 v2@25.966,41.566 ; C181.2@25.966,42.164 v2@25.966,41.566 ; v2(26,41.6) v2@25.966,41.566 ; C178.2@28.136,44.196 v2@28.596,44.196 ; C192.2@28.321,38.296 28.321,38.721 v2(28.6,39) ; v2(28.6,44.2) v2@28.596,44.196 ; C186.2@29,39.65 29,39.25 ; C186.2@29.014,39.624 29.014,39.264 ; C191.2@29.337,38.296 29.337,38.913 v2(29.25,39) 29.014,39.236 ; C177.2@29.78,44.323 C177.2@29.653,44.196 ; v2(29.9,38.35) 29.954,38.296 C190.2@30.48,38.296 ; C177.2@29.907,44.196 C177.2@29.653,44.196 ; C174.2@29.972,45.524 30.526,45.524 v2(30.55,45.5) ; v2(31.2,45.5) 31.224,45.524 C173.2@31.75,45.524 ; v2(32.5,46.15) 32.774,46.424 C172.2@33.274,46.424 ; v2(33.15,42.25) 33.216,42.316 C180.2@33.216,42.926 33.242,42.9 C179.2@34.098,42.9 ; v2(33.15,44.2) 33.343,44.393 C176.2@33.343,44.704 ; C184.2@33.216,40.894 33.216,41.534 v2(33.15,41.6) 33.784,41.6 C182.2@33.84,41.656 ; v2@28.596,44.196 C177.2@29.653,44.196 ; 29,39.25 29.014,39.264 ; 29,39.25 29.014,39.236 ; 29.014,39.236 29.014,39.264
  other v1: 38.2,50.7 39.2,50.7
3V3_SW: C3.1 C92.1 C93.1 C94.2 C95.2 CN3.4 R6.1 R47.1 R201.2 R202.2 R203.2 R268.1 SB23.2 SB28.1 TP17.1 U2.4 U2.5 | length 218.5
  Top Layer w0.203: 19.431,162.433 19.57,162.572 U2.4@19.816,162.572 U2.5@20.316,162.572
  Top Layer w0.508: v1(14.424,157.34) CN3.4@15.6,157.34 ; v1(16.51,162.306) 16.568,162.248 C3.1@18.542,162.248 19.246,162.248 19.431,162.433 ; v1(16.51,163.576) R6.1@17.334,163.576 ; v1(18.034,129.286) 20.004,131.256 R47.1@20.004,132.588 ; v1(120.777,63.246) SB28.1@124.468,63.246
  Top Layer w0.762: v7(49.4,158.6) 53.998,158.6 62.23,150.368 v7(64.008,150.368)
  Signal Layer 2 w0.508: v1(16.51,162.306) 21.906,162.306 24.5,164.9 30.1,164.9 v1(32.2,162.8) ; v1(55.245,50.419) 61.976,50.419 64.389,52.832 99.06,52.832 109.474,63.246 v1(120.777,63.246)
  Signal Layer 2 w0.762: v7(44.196,161.29) 44.196,159.512 45.108,158.6 v7(49.4,158.6)
  Bottom Layer w0.5: v1(2.921,158.242) 2.921,157.353 3.106,157.168 C95.2@11.938,157.168 C94.2@13.335,157.168 ; C94.2@13.335,157.06 C94.2@13.335,157.168 ; v1(14.424,157.34) 14.252,157.168 C94.2@13.335,157.168
  Bottom Layer w0.508: v1(21.336,88.265) 21.336,87.503 22.225,86.614 29.21,86.614 30.099,85.725 30.099,75.565 v1(55.245,50.419) ; v1(32.2,162.8) 31.96,162.56 C92.1@31.96,161.105 32.98,161.105 R201.2@33.038,161.163 ; R203.2@44.196,160.466 v7(44.196,161.29)
  Bottom Layer w0.762: v7(64.008,150.368) 64.008,137.795 65.467,136.336 R268.1@69.342,136.336
  other v1: 20.066,88.265 20.066,89.281 21.336,89.281 20.066,90.297 21.336,90.297 1.905,158.242 1.905,159.385 2.921,159.385
3V3_SW_ENABLE: C51.1 R129.1 R130.2 SB34.1 U14.1 | length 193.3
  Top Layer w0.127: R129.1@15.298,89.027 15.298,88.207 16.002,87.503 v1(22.86,87.503) ; SB34.1@133.125,35.175 134.775,35.175 135.5,34.45 v1(135.5,22.875)
  Top Layer w0.381: R130.2@13.716,88.207 C51.1@13.716,89.085 13.774,89.027 R129.1@15.298,89.027 15.306,89.035 U14.1@15.306,90.013
  Bottom Layer w0.127: v1(22.86,87.503) 29.718,87.503 30.607,86.614 30.607,75.946 63.5,43.053 63.5,25.146 69.85,18.796 108.077,18.796 117.731,28.45 118.875,28.45 119.2,28.125 119.2,24.775 122.1,21.875 131.7,21.875 132.7,22.875 v1(135.5,22.875)
3V3_USBHS_IO: C32.2 R17.2 R18.2 R19.2 R41.2 R45.2 R47.2 U7.32 | length 25
  Top Layer w0.254: U7.32@17.498,137.275 17.498,137.061 v1(18.542,136.017) C32.2@18.542,135.324
  Top Layer w0.508: v1(16.002,133.731) R41.2@16.002,134.424 ; R17.2@16.256,148.274 R18.2@17.78,148.274 18.542,148.274 ; v1(18.542,136.017) 18.6,135.959 C32.2@18.6,135.382 18.604,135.378 R45.2@18.604,134.112 v1(18.604,133.35) R47.2@18.604,132.588 ; v1(18.542,147.574) 18.542,148.274 ; R19.2@19.304,148.274 18.542,148.274
  Signal Layer 2 w0.508: v1(16.002,133.731) 18.223,133.731 v1(18.604,133.35)
  Bottom Layer w0.508: v1(18.542,136.017) 18.034,136.525 18.034,141.224 18.542,141.732 v1(18.542,147.574)
3V3_VBAT: JP37.2 U5.E2 | length 184.5
  Top Layer w0.254: U5.E2@86,139.2 v2(86.4,139.6)
  Top Layer w0.762: v7(98.298,55.372) 105.025,62.099 105.025,77.22 96.393,85.852 96.393,114.808 107.188,125.603 v7(107.188,146.939)
  Signal Layer 2 w0.254: v2(86.4,139.6) 86.995,140.195 86.995,142.113 87.206,142.324
  Signal Layer 2 w0.508: 87.206,142.324 90.424,145.542 95.123,145.542 96.52,146.939 v7(107.188,146.939)
  Signal Layer 2 w0.762: JP37.2@43.942,50.038 45.593,51.689 60.452,51.689 64.135,55.372 v7(98.298,55.372)
3V3_VDDA: C118.2 C119.1 R266.1 R267.2 R268.2 TP25.1 U5.L5 | length 26.3
  Top Layer w0.254: v2(80.8,136.4) U5.L5@81.2,136.8
  Top Layer w0.508: TP25.1@63.575,134.5 66.8,134.5 v2(67.25,134.95)
  Bottom Layer w0.127: C118.2@77.724,135.694 78.03,136 78.359,136 ; 80.4,136 78.359,136 ; 80.4,136.8 78.634,136.8 78.359,136.525 78.359,136
  Bottom Layer w0.254: 80.4,136 v2(80.8,136.4) 80.4,136.8
  Bottom Layer w0.508: TP25.1@63.575,134.5 66.8,134.5 v2(67.25,134.95) ; v2@67.246,134.938 67.818,135.509 68.961,135.509 69.342,135.128 69.342,134.936 70.866,134.936 R266.1@72.39,134.936 74.68,134.936 75.438,135.694 C119.1@76.708,135.694 C118.2@77.724,135.694
3V3_VREFP: C108.2 C109.2 R266.2 TP24.1 U5.L4 | length 30
  Top Layer w0.1: v2(80.8,138) U5.L4@81.2,137.6
  Top Layer w0.508: v2(67.213,140.388) 66.675,140.925 TP24.1@66.225,140.925 ; TP24.1@66.225,140.925 TP24.1@65.675,140.925 65.95,141.2 TP24.1@66.225,140.925
  Bottom Layer w0.1: C109.2@80.264,140.52 C109.2@80.391,140.393 ; C108.2@81.2,140.44 C108.2@81.28,140.52
  Bottom Layer w0.127: C109.2@80.391,140.393 80.391,138.409 v2(80.8,138) 81.2,138.4 C108.2@81.2,140.44
  Bottom Layer w0.508: TP24.1@65.675,140.925 66.675,140.925 ; v2(67.213,140.388) 66.675,140.925 ; R266.2@72.39,136.336 72.39,138.035 70.675,139.75 67.85,139.75 66.675,140.925 ; 72.898,136.336 73.787,136.336 74.422,136.971 74.422,138.557 75.184,139.319 77.851,139.319 79.052,140.52 C109.2@80.264,140.52 C108.2@81.28,140.52
5V: C1.2 C48.2 C49.1 C52.2 C111.1 C197.1 CN1.25 CN5.60 CN6.60 JP29.2 JP29.4 JP29.6 JP29.8 JP29.10 JP29.12 R112.1 R133.2 R153.2 R159.2 SB18.2 U1.3 U7.21 U13.1 U13.3 U14.6 U15.6 U24.42 U28.3 U29.5 U39.5 | length 261.2
  Top Layer w0.254: v1(12.319,139.192) 12.577,139.45 U7.21@13.323,139.45
  Top Layer w0.5: 12.7,85.344 12.7,82.931 13.012,82.619 R133.2@13.716,82.619 ; v1(141.85,48.725) v1@141.838,48.737 ; v1(160.45,49.05) 160.9,48.6 v1(161.025,48.6) ; 136.35,47.875 137.575,49.1 137.925,49.1 ; 136.35,47.875 137.1,47.875 ; 136.35,47.875 136.075,47.6 136.075,46.85 136.2,46.725 R159.2@137.1,46.725 137.1,47.875 ; 137.1,47.875 137.963,48.737 ; 137.1,47.875 137.1,48.275 137.925,49.1 ; 137.925,49.1 138.325,49.1 ; 137.963,48.737 v1@141.838,48.737 ; 137.963,48.737 138.325,49.1 ; 138.325,49.1 v1(141.1,49.1) 141.475,49.1 v1@141.838,48.737
  Top Layer w0.508: R112.1@4.71,99.314 8.001,99.314 8.89,98.425 JP29.2@8.89,96.647 ; U13.1@15.306,95.674 15.306,94.803 15.621,94.488 17.018,94.488 17.206,94.676 U13.3@17.206,95.674 ; v1(18.923,43.942) R153.2@19.616,43.942 ; CN6.60@52.393,114.935 v1(54.4,114.935) ; U24.42@65.396,30.504 U24.42@65.4,30.5 v1(66.544,30.5) ; v1(88.392,117.729) SB18.2@88.392,121.32 ; CN5.60@120.972,114.935 v1(122.994,114.935) 123.571,114.935 129.667,121.031 v1(159.258,121.031) ; v1(124.206,162.306) C1.2@125.03,162.306 124.333,163.003 U1.3@124.333,164.832 ; U28.3@151.003,16.421 v1(151.003,17.812)
  Top Layer w1.016: v7(20.218,97.282) v7(22.098,97.282) 47.117,97.282 48.26,98.425 48.26,105.664 51.4,108.804 51.4,110.5 51.816,110.916 51.816,113.157 52.393,113.734 CN6.60@52.393,114.935
  Signal Layer 2 w0.5: v1(141.1,49.1) 148.275,49.1 148.85,48.525 153.625,48.525 154.75,49.65 158.55,49.65 159.15,49.05 v1(160.45,49.05) 160.575,49.05 v1(161.025,48.6) 158.975,48.6 158.284,49.291 154.991,49.291 153.775,48.075 148.664,48.075 148.014,48.725 v1(141.85,48.725) 141.475,48.725 v1(141.1,49.1)
  Signal Layer 2 w0.508: v1(54.4,114.935) 80.469,114.935 83.263,117.729 v1(88.392,117.729)
  Bottom Layer w0.254: v1(12.319,139.192) v1@12.377,139.134 ; 12.893,139.134 C111.1@13.208,139.134
  Bottom Layer w0.381: v1@12.377,139.134 12.893,139.134
  Bottom Layer w0.5: v1(141.1,49.1) 141.475,48.725 v1(141.85,48.725) ; v1(160.45,49.05) 160.575,49.05 v1(161.025,48.6)
  Bottom Layer w0.508: U39.5@11.75,146.22 11.75,145.354 v1(11.684,145.288) v1(12.319,145.288) ; CN1.25@84.074,167.64 87.249,170.815 116.332,170.815 121.539,165.608 121.539,163.068 122.301,162.306 v1(123.444,162.306) ; C197.1@150.945,17.018 150.945,17.754 v1(151.003,17.812)
  other v1: 139.319,9.017 140.208,9.017 138.811,9.906 151.892,17.78 13.081,86.106
  other v7: 10.287,94.615
5V_D: CN5.49 CN6.49 D7.1 JP29.9 | length 185.4
  Top Layer w0.508: 45.339,121.285 CN6.49@47.293,121.285
  Top Layer w0.635: v7(44.45,113.919) 44.45,120.396 45.339,121.285 CN6.49@47.293,121.285
  Top Layer w0.762: v7(109.601,116.586) 109.601,119.253 111.633,121.285 CN5.49@115.872,121.285
  Top Layer w1.016: JP29.9@6.35,86.487 4.572,84.709 4.572,83.058 7.366,80.264 22.564,80.264 24.596,82.296 41.402,82.296 v7(42.291,83.185)
  Signal Layer 2 w1.016: v7(44.45,113.919) 81.119,113.919 83.024,115.824 103.251,115.824 104.013,116.586 v7(109.601,116.586)
  Bottom Layer w0.508: JP29.9@6.35,86.487 4.572,84.709 4.572,82.573 7.145,80 17.6,80 19.194,78.406 D7.1@19.194,77.586
  Bottom Layer w1.016: v7(42.291,83.185) v7(42.291,84.836) 42.291,96.647 44.45,98.806 v7(44.45,113.919)
5V_EXT: C157.1 D4.1 JP29.3 L2.2 | length 61.8
  Top Layer w1.016: v7(2.032,70.866) 2.032,93.472 2.667,94.107 JP29.3@6.35,94.107
  Bottom Layer w0.5: JP29.3@6.35,94.107 4.626,94.107 1.596,91.077 1.596,81.604 5.614,77.586 D4.1@11.574,77.586
  Bottom Layer w1.016: v7(2.032,70.866) 2.032,69.768 3.25,68.55 3.25,63.95 C157.1@3.3,63.9
5V_EXT_CONN: CN17.1 Z1.1
5V_EXT_UNFILT: C57.1 L2.1 Z1.3
5V_LCD: C75.2 C76.1 CN30.4 CN30.6 R159.1 | length 7.5
  Top Layer w0.508: R159.1@138.5,46.725 C75.2@138.5,45.15 ; CN30.4@140.795,43.79 138.715,43.79 C76.1@138.7,43.775 138.5,43.975 C75.2@138.5,45.15 ; CN30.6@140.795,45.06 138.59,45.06 C75.2@138.5,45.15
5V_STLK: C71.2 JP29.1 TP21.1 U22.1 | length 71
  Top Layer w0.5: U22.1@12.784,43.754 14.216,43.754 C71.2@14.224,43.746
  Signal Layer 2 w1: JP29.1@6.35,96.647 6.35,98.298 6.731,98.679 10.287,98.679 11.43,97.536 11.43,81.153 18.161,74.422 18.161,48.641 14.478,44.958 v1(14.478,43.18) v1(14.478,42.037) 13.3,40.859 TP21.1@12.562,40.859
5V_STLK_LDO_IN: C63.1 C64.2 D4.2 D5.2 D6.2 D7.2 D8.2 U19.1 U19.3 | length 36.5
  Top Layer w0.508: U19.3@34.102,55.202 34.102,56.327 34.29,56.515 v1@36.195,56.515
  Signal Layer 2 w1.016: v7(22.606,73.406) v7(22.606,71.882) 22.606,59.182 25.146,56.642 v1(36.449,56.642) v1(37.338,56.642) v1(38.354,56.642)
  Bottom Layer w1.016: D8.2@21.734,75.18 22.606,74.308 v7(22.606,73.406)
5V_USB_CHGR: C70.2 C72.1 C74.1 CN21.1 D8.1 JP29.11 R149.2 R150.2 R152.2 TP20.1 U22.5 U23.1 | length 90.3
  Top Layer w0.381: R149.2@1.778,45.27 R150.2@3.048,45.27 5.498,45.27 TP20.1@6.096,44.672 ; CN21.1@4.15,38.6 4.881,38.6 5.781,39.5 C74.1@6.15,39.5 6.158,39.5 6.158,41.581 C72.1@6.233,41.656 ; 6.096,41.643 6.1,41.647 v1(6.1,43) 5.608,43 5.4,43.208 TP20.1@5.4,43.7 ; R152.2@8.89,43.754 U22.5@10.584,43.754 ; TP20.1@5.4,43.7 5.15,43.95 TP20.1@5.4,43.95 ; TP20.1@5.4,43.7 TP20.1@5.4,43.95 ; TP20.1@5.4,43.95 5.5,43.95 5.5,44.8 TP20.1@5.4,44.9 TP20.1@5.4,43.95
  Signal Layer 2 w1: v1(6.1,43) 5.768,43 5.4,43.368 TP20.1@5.4,44.9 5.4,47.1 6.433,48.133 15.494,48.133 16.637,49.276 16.637,73.66 7.048,83.248
  Bottom Layer w0.508: JP29.11@6.35,83.947 6.35,82.15 7.62,80.88 18.72,80.88 21.734,77.866 D8.1@21.734,77.586
5V_USB_FS: D6.1 JP29.7 R182.2 | length 230.3
  Top Layer w1.016: JP29.7@6.35,89.027 3.302,85.979 3.302,81.915 6.921,78.295 17.59,78.295 20.955,74.93 v7(20.955,73.406)
  Signal Layer 2 w1.016: v7(20.955,73.406) v7(20.955,71.882) 20.701,71.628 20.701,19.304 24.194,15.811 65.278,15.811 66.372,14.718 v1(138.938,14.718) v1(140.081,14.718)
  Bottom Layer w0.508: JP29.7@6.35,89.027 4.626,89.027 3.6,88.001 3.6,82.2 6.6,79.2 15.725,79.2 16.654,78.271 D6.1@16.654,77.586
5V_USB_HS: D5.1 JP29.5 R44.2 | length 25.6
  Bottom Layer w0.508: JP29.5@6.35,91.567 4.626,91.567 2.5,89.441 2.5,82 6.1,78.4 13.3,78.4 D5.1@14.114,77.586
  other v1: 5.842,133.096 6.477,133.096
A0: R339.2 U12.E2 U16.G8 U17.A3 | length 109.4
  Top Layer w0.102: U17.A3@66.703,73.73 67.259,73.73 67.776,73.213 v3(67.776,72.974) ; v3(89.478,71.069) 89.872,71.463 U16.G8@89.897,71.463
  Top Layer w0.127: U12.E2@83.574,100.366 83.567,100.366 83.128,100.806 83.128,101.652 v5(84.548,103.073)
  Signal Layer 2 w0.102: v3(67.776,72.974) 67.776,72.959 68.243,72.492 69.361,72.492 69.462,72.593 69.739,72.593 69.942,72.39 70.145,72.39 70.349,72.593 70.552,72.593 70.755,72.39 70.958,72.39 71.161,72.593 71.365,72.593 71.568,72.39 71.771,72.39 71.974,72.593 72.177,72.593 72.381,72.39 72.584,72.39 72.787,72.593 72.99,72.593 73.193,72.39 73.397,72.39 73.6,72.593 73.803,72.593 74.006,72.39 74.209,72.39 74.413,72.593 74.616,72.593 74.819,72.39 75.022,72.39 75.225,72.593 75.429,72.593 75.632,72.39 75.835,72.39 76.038,72.593 76.241,72.593 76.445,72.39 76.648,72.39 76.851,72.593 77.252,72.593 v3(77.33,72.515) 77.607,72.238 81.629,72.238 82.321,72.93 86.531,72.93 87.63,71.831 88.97,71.831 89.478,71.323 v3(89.478,71.069) ; v5(84.548,103.073) 84.561,102.383 85.598,101.346 86.741,101.346 87.757,100.33 90.932,100.33 92.202,99.06 100.076,99.06 103.759,102.743 104.902,102.743 105.156,102.997 105.156,104.648 105.283,104.775 105.537,104.775 105.664,104.648 105.664,102.362 105.791,102.235 106.045,102.235 106.172,102.362 106.172,104.648 106.299,104.775 106.553,104.775 106.68,104.648 106.68,102.743 106.807,102.616 107.061,102.616 107.188,102.743 107.188,104.648 107.315,104.775 v1(107.95,104.775)
  Bottom Layer w0.127: v3(77.33,72.515) 77.54,72.725 77.54,74.723 78.568,75.752 78.568,82.398 88.462,92.291 88.462,95.072 87.573,95.961 86.176,95.961 85.541,96.596 85.541,99.136 84.271,100.406 84.271,102.795 v5(84.548,103.073) ; v1(107.95,104.775) 108.331,105.156 R339.2@111.31,105.156
A1: R335.2 U12.D2 U16.G9 U17.A4 | length 108.3
  Top Layer w0.102: U17.A4@66.703,72.98 v3(67.24,72.974) ; U12.D2@84.574,100.366 84.169,100.765 84.169,101.575 85.541,102.946 ; v3(89.478,70.18) 89.478,70.244 U16.G9@89.897,70.663
  Top Layer w0.127: 85.541,102.946 85.591,102.997 85.591,103.302 v5(85.922,103.632)
  Signal Layer 2 w0.102: v3(67.24,72.974) 67.24,72.847 68.002,72.085 77.286,72.085 77.54,71.831 78.302,71.831 78.327,71.806 v3(78.429,71.806) 78.53,71.908 81.807,71.908 82.525,72.625 86.499,72.625 87.7,71.425 88.838,71.425 89.052,71.211 89.052,70.606 v3(89.478,70.18) ; v5(85.922,103.632) 85.928,103.454 87.274,102.108 93.091,102.108 94.107,101.092 95.121,101.092 95.248,101.219 95.248,101.981 95.375,102.108 95.631,102.108 95.758,101.981 95.758,101.219 95.885,101.092 96.139,101.092 96.266,101.219 96.266,101.981 96.393,102.108 96.647,102.108 96.774,101.981 96.774,101.346 96.901,101.219 97.155,101.219 97.282,101.346 97.282,101.981 97.409,102.108 97.663,102.108 97.79,101.981 97.79,101.346 97.917,101.219 98.171,101.219 98.298,101.346 98.298,101.981 98.425,102.108 98.679,102.108 98.806,101.981 98.806,101.6 98.933,101.473 99.187,101.473 99.314,101.6 99.314,101.981 99.441,102.108 99.695,102.108 99.822,101.981 99.822,101.6 99.949,101.473 100.203,101.473 100.33,101.6 100.33,102.108 100.711,102.489 100.711,105.156 100.965,105.41 104.394,105.41 105.029,106.045 v1(107.95,106.045)
  Bottom Layer w0.127: v3(78.429,71.806) 78.429,72.466 79.445,73.482 79.445,74.448 81.019,76.022 81.019,81.509 83.331,83.82 86.633,83.82 90.748,87.935 90.748,97.107 88.69,99.165 88.69,99.848 86.655,101.882 86.655,102.69 85.922,103.424 v5(85.922,103.632) ; v1(107.95,106.045) 108.585,106.68 R335.2@111.31,106.68
A2: R331.2 U12.C2 U16.F7 U17.A5 | length 108.4
  Top Layer w0.102: U17.A5@66.703,72.23 68.312,72.23 v3(68.929,72.847) ; v3(89.478,72.847) 90.113,72.847 U16.F7@90.697,72.263
  Top Layer w0.127: U12.C2@85.574,100.366 86.125,100.924 86.125,101.753 86.988,102.616 v5(86.988,103.531)
  Signal Layer 2 w0.102: v5(86.988,103.531) 87.656,102.87 90.297,102.87 91.77,104.343 96.638,104.343 96.774,104.479 96.774,104.775 96.901,104.902 97.155,104.902 97.282,104.775 97.282,104.464 97.403,104.343 97.663,104.343 97.79,104.47 97.79,105.791 97.917,105.918 98.171,105.918 98.298,105.791 98.298,105.664 98.425,105.537 98.679,105.537 98.806,105.664 98.806,106.68 98.933,106.807 99.187,106.807 99.314,106.68 99.314,106.172 99.441,106.045 99.695,106.045 99.822,106.172 99.822,106.807 99.949,106.934 100.203,106.934 100.33,106.807 100.33,106.553 100.457,106.426 100.711,106.426 100.838,106.553 100.838,106.807 100.965,106.934 101.219,106.934 101.346,106.807 101.346,106.68 101.473,106.553 102.362,106.553 102.489,106.68 102.489,107.823 102.616,107.95 102.87,107.95 102.997,107.823 102.997,106.68 103.124,106.553 103.378,106.553 103.505,106.68 103.505,107.823 103.632,107.95 108.839,107.95 108.966,108.077 v1(108.966,108.585) ; v3(89.478,72.847) 89.097,73.228 82.499,73.228 82.094,73.235 81.528,72.67 v3(79.445,72.67) 77.971,72.67 77.694,72.947 v3@69.105,72.947 ; v3@69.105,72.947 v3(68.929,72.847) 69.005,72.847 v3@69.105,72.947
  Bottom Layer w0.127: v3(79.445,72.67) 80.918,72.67 81.045,72.797 81.045,73.203 80.918,73.33 79.953,73.33 79.826,73.457 79.826,74.27 80.499,74.943 81.438,74.943 81.781,75.286 81.781,81.102 83.686,83.007 87.319,83.007 91.51,87.198 91.51,97.423 89.579,99.354 89.579,100.965 87.458,103.086 87.458,103.937 87.331,104.064 87.115,104.064 86.988,103.937 v5(86.988,103.531) ; v1(108.966,108.585) R331.2@111.31,108.585
A3: R74.2 U12.A2 U16.F3 U17.B3 | length 108.3
  Top Layer w0.102: U17.B3@65.953,73.73 v3(66.328,74.105) ; v3(90.24,75.006) U16.F3@90.697,75.463 ; v1(101.346,109.855) R74.2@102.166,109.855
  Top Layer w0.127: v5(87.903,103.658) 88.106,103.454 88.106,100.874 U12.A2@87.598,100.366 ; U12.A2@87.598,100.366 U12.A2@87.574,100.366 87.568,100.366 U12.A2@87.598,100.366
  Signal Layer 2 w0.102: v3(66.328,74.105) 66.467,74.244 67.786,74.244 68.36,74.818 80.649,74.818 v3(80.969,74.498) 81.273,74.803 88.97,74.803 89.097,74.93 89.097,75.436 89.201,75.54 89.348,75.54 89.452,75.436 89.452,74.907 89.556,74.803 89.704,74.803 89.808,74.907 89.808,75.337 89.935,75.464 91.256,75.464 91.383,75.337 91.383,75.133 91.256,75.006 v3(90.24,75.006) ; v5(87.903,103.658) 87.91,103.683 88.316,104.089 89.738,104.089 92.329,106.68 92.329,109.855 92.456,109.982 92.71,109.982 92.837,109.855 92.837,108.966 92.964,108.839 93.218,108.839 93.345,108.966 93.345,109.855 93.472,109.982 93.726,109.982 93.853,109.855 93.853,108.966 93.98,108.839 94.234,108.839 94.361,108.966 94.361,109.855 94.488,109.982 94.742,109.982 94.869,109.855 94.869,108.966 94.996,108.839 95.25,108.839 95.377,108.966 95.377,109.855 95.504,109.982 95.758,109.982 95.885,109.855 95.885,108.966 96.012,108.839 96.266,108.839 96.393,108.966 96.393,109.855 96.52,109.982 96.774,109.982 96.901,109.855 96.901,108.966 97.028,108.839 97.282,108.839 97.409,108.966 97.409,109.855 97.536,109.982 97.79,109.982 97.917,109.855 97.917,108.966 98.044,108.839 98.298,108.839 98.425,108.966 98.425,109.855 98.552,109.982 98.806,109.982 98.933,109.855 98.933,109.347 99.06,109.22 99.314,109.22 99.441,109.347 99.441,109.728 99.568,109.855 v1(101.346,109.855)
  Bottom Layer w0.127: v3(80.969,74.498) 81.172,74.295 81.527,74.295 82.162,74.93 82.162,80.899 83.864,82.601 87.674,82.601 91.891,86.817 91.891,97.581 89.884,99.588 89.884,100.638 90.011,100.765 90.646,100.765 90.773,100.892 90.773,101.146 90.646,101.273 90.011,101.273 89.884,101.4 89.884,101.656 90.287,102.059 90.287,102.238 90.107,102.418 89.927,102.418 89.421,101.912 89.242,101.912 89.062,102.092 89.062,102.297 89.568,102.803 89.568,102.983 89.388,103.162 89.208,103.162 88.677,102.631 88.523,102.631 87.903,103.251 v5(87.903,103.658)
A4: R66.2 U12.B2 U16.G1 U17.B4 | length 107.7
  Top Layer w0.102: U17.B4@65.953,72.98 66.34,72.593 68.015,72.593 68.385,72.964 v3(68.385,74.295) ; U16.G1@89.897,77.063 v3@90.24,76.72 ; v3@90.24,76.72 90.24,76.695 v3(90.279,76.656) v3@90.24,76.72
  Top Layer w0.127: U12.B2@86.574,100.366 87.09,100.889 87.09,101.575 87.446,101.93 87.446,104.089 87.903,104.546 v5(87.903,104.572)
  Top Layer w0.13: v1(105.537,114.681) 105.346,114.871 105.346,115.056 R66.2@105.664,115.374
  Signal Layer 2 w0.102: v3(68.385,74.295) 68.431,74.295 68.649,74.513 80.104,74.513 v3(80.398,74.219) 80.474,74.219 80.652,74.041 81.146,74.041 81.578,74.473 91.764,74.473 91.891,74.6 91.891,76.529 91.764,76.656 v3(90.279,76.656)
  Signal Layer 2 w0.104: v5(87.903,104.572) 90.018,106.68 91.059,106.68 91.567,107.188 91.567,110.363 92.71,111.506 104.267,111.506 104.394,111.633 104.394,112.903 104.521,113.03 104.775,113.03 104.902,112.903 104.902,111.633 105.029,111.506 105.283,111.506 105.41,111.633 105.41,114.554 v1(105.537,114.681)
  Bottom Layer w0.127: v3(80.398,74.219) 80.754,73.863 81.68,73.863 82.543,74.727 82.543,80.721 84.017,82.194 88.081,82.194 92.272,86.385 92.272,97.739 91.179,98.831 91.179,101.93 89.668,103.442 89.668,103.988 89.566,104.089 88.03,104.089 87.903,104.216 v5(87.903,104.572)
A5: R65.2 U12.D3 U16.G2 U17.C3 | length 108.4
  Top Layer w0.102: U17.C3@65.203,73.73 v3(65.578,74.105) ; U12.D3@84.574,99.366 83.966,99.968 83.966,101.752 85.159,102.946 ; U16.G2@89.897,76.263 90.24,75.92 90.24,75.894 v3(90.26,75.873)
  Top Layer w0.127: 85.159,102.946 85.159,103.708 85.845,104.394 v5(86.049,104.394)
  Top Layer w0.13: R65.2@104.648,115.374 104.965,115.056 104.965,114.871 v1(104.775,114.681)
  Signal Layer 2 w0.102: v3(65.578,74.105) 66.047,74.574 67.786,74.574 68.345,75.133 80.689,75.133 v3(80.943,75.387) 82.214,75.387 82.595,75.006 88.69,75.006 88.817,75.133 88.817,75.26 88.69,75.387 88.411,75.387 88.284,75.514 88.284,75.641 88.411,75.768 88.741,75.768 88.868,75.895 88.868,76.152 88.992,76.276 89.169,76.276 89.293,76.152 89.293,75.946 89.395,75.844 89.598,75.844 89.7,75.946 89.7,76.175 89.801,76.276 91.417,76.276 91.535,76.158 91.535,75.991 91.417,75.873 v3(90.26,75.873) ; v5(86.049,104.394) 86.049,104.655 85.929,104.775 84.836,104.775 84.709,104.902 84.709,105.156 84.836,105.283 84.963,105.283 85.09,105.41 85.09,105.664 84.963,105.791 84.709,105.791 84.582,105.918 84.582,106.172 84.709,106.299 87.427,106.299 88.138,107.01 90.881,107.01 91.186,107.315
  Signal Layer 2 w0.104: 91.186,107.315 91.186,110.49 92.583,111.887 103.886,111.887 104.013,112.014 104.013,113.411 104.14,113.538 104.775,113.538 104.965,113.728 104.965,114.49 v1(104.775,114.681)
  Bottom Layer w0.127: v3(80.943,75.387) 81.4,75.844 81.4,81.28 83.534,83.414 86.988,83.414 91.129,87.554 91.129,97.265 89.198,99.196 89.198,100.685 88.679,101.205 88.499,101.205 88.336,101.042 88.157,101.042 87.977,101.221 87.977,101.401 88.14,101.564 88.14,101.744 87.96,101.923 87.78,101.923 87.618,101.761 87.438,101.761 87.258,101.94 87.258,102.12 87.421,102.283 87.421,102.463 86.938,102.946 86.531,103.353 86.531,103.911 v5(86.049,104.394)
A5_OCSPI1: SB20.1 U11.A5 | length 4.2
  Top Layer w0.127: SB20.1@29.202,103.632 31.21,103.632 31.496,103.346 U11.A5@33.306,103.346
A6: R326.2 U12.C3 U16.G3 U17.C4 | length 107.9
  Top Layer w0.102: U17.C4@65.203,72.98 v3(65.578,72.605) ; U12.C3@85.574,99.366 v5(86.067,99.866) ; v3(89.478,74.117) 89.478,74.346 89.833,74.702 89.833,75.4 U16.G3@89.897,75.463
  Signal Layer 2 w0.102: v1(59.309,109.855) 60.071,109.855 60.198,109.728 60.198,109.347 60.325,109.22 60.579,109.22 60.706,109.347 60.706,110.109 60.833,110.236 61.087,110.236 61.214,110.109 61.214,109.347 61.341,109.22 61.595,109.22 61.722,109.347 61.722,110.109 61.849,110.236 62.103,110.236 62.23,110.109 62.23,108.458 62.357,108.331 62.611,108.331 62.738,108.458 62.738,110.109 62.865,110.236 63.119,110.236 63.246,110.109 63.246,108.585 63.373,108.458 63.627,108.458 63.754,108.585 63.754,109.093 63.881,109.22 64.897,109.22 65.024,109.093 65.024,108.458 65.151,108.331 72.39,108.331 72.771,107.95 72.771,104.394 75.946,101.219 82.416,101.219 84.753,98.882 85.09,98.882 v5(86.067,99.866) ; v3(65.578,72.605) 66.302,73.33 77.742,73.33 77.971,73.101 v3(78.365,73.101) 81.529,73.101 81.967,73.54 82.431,73.54 82.488,73.482 88.843,73.482 v3(89.478,74.117)
  Bottom Layer w0.127: R326.2@57.088,109.855 v1(59.309,109.855) ; v3(78.365,73.101) 78.365,74.471 80.257,76.363 80.257,81.864 83.026,84.633 86.099,84.633 89.986,88.519 89.986,96.723 87.622,99.087 86.86,99.087 v5(86.067,99.866)
A7: R325.2 U12.A3 U16.H1 U17.D4 | length 108.3
  Top Layer w0.102: U17.D4@64.453,72.98 v3(64.827,72.605) ; v5(87.105,99.829) 87.568,99.366 U12.A3@87.574,99.366 ; v3(88.36,74.117) 88.716,74.117 89.478,74.879 89.478,76.682 U16.H1@89.097,77.063
  Signal Layer 2 w0.102: v1(60.198,110.49) 60.325,110.617 61.087,110.617 61.214,110.744 61.214,111.252 61.341,111.379 61.595,111.379 61.722,111.252 61.722,110.744 61.849,110.617 62.103,110.617 62.23,110.744 62.23,111.252 62.357,111.379 62.611,111.379 62.738,111.252 62.738,110.744 62.865,110.617 63.119,110.617 63.246,110.744 63.246,111.252 63.373,111.379 63.627,111.379 63.754,111.252 63.754,110.744 63.881,110.617 64.77,110.617 64.897,110.744 64.897,111.506 65.024,111.633 65.278,111.633 65.405,111.506 65.405,110.744 65.532,110.617 65.786,110.617 65.913,110.744 65.913,111.506 66.04,111.633 66.294,111.633 66.421,111.506 66.421,110.744 66.548,110.617 67.31,110.617 67.437,110.49 67.437,109.855 68.199,109.093 72.644,109.093 73.533,108.204 73.533,104.648 75.057,103.124 82.956,103.124 85.496,100.584 86.357,100.584 v5(87.105,99.829) ; v3(64.827,72.605) 65.755,73.533 67.532,73.533 67.634,73.635 78.877,73.635 v3(78.903,73.609) 79.106,73.406 81.402,73.406 81.86,73.863 82.492,73.863 82.594,73.762 88.309,73.762 88.36,73.813 v3(88.36,74.117)
  Bottom Layer w0.102: R325.2@57.088,111.125 57.404,111.125 58.039,110.49 v1(60.198,110.49)
  Bottom Layer w0.127: v3(78.903,73.609) 78.903,74.469 80.638,76.205 80.638,81.687 83.178,84.227 86.379,84.227 90.367,88.214 90.367,96.85 87.388,99.829 v5(87.105,99.829)
A8: R70.2 U12.B6 U16.H2 U17.H2 | length 108.4
  Top Layer w0.102: v3(61.078,74.855) U17.H2@61.453,74.48 ; R70.2@66.236,111.125 v1(67.564,111.125) ; U12.B6@86.574,96.366 v5(87.065,96.876) ; v3(88.697,76.663) U16.H2@89.097,76.263
  Signal Layer 2 w0.102: v3(61.078,74.855) 61.078,78.102 62.935,79.959 v3(79.407,79.959) 79.407,81.102 79.534,81.229 79.775,81.229 79.902,81.102 79.902,80.62 80.029,80.493 80.257,80.493 80.359,80.594 80.359,81.11 80.478,81.229 80.646,81.229 80.765,81.11 80.765,80.594 80.867,80.493 81.07,80.493 81.172,80.594 81.172,81.009 81.291,81.128 81.459,81.128 81.578,81.009 81.578,80.594 81.68,80.493 81.883,80.493 81.985,80.594 81.985,81.009 82.104,81.128 82.272,81.128 82.391,81.009 82.391,80.594 82.493,80.493 82.696,80.493 82.797,80.594 82.797,81.009 82.917,81.128 83.085,81.128 83.204,81.009 83.204,80.594 83.305,80.493 83.509,80.493 83.61,80.594 83.61,81.009 83.729,81.128 83.897,81.128 84.017,81.009 84.017,80.594 84.118,80.493 84.372,80.493 84.499,80.62 84.499,81.001 84.626,81.128 84.779,81.128 84.906,81.001 84.906,79.985 85.033,79.858 85.896,79.858 85.998,79.959 85.998,80.417 86.099,80.518 86.303,80.518 86.404,80.417 86.404,79.959 86.506,79.858 87.903,79.858 88.309,79.451 88.309,77.343 88.697,76.956 v3(88.697,76.663) ; v1(67.564,111.125) 68.072,110.617 68.072,109.855 68.199,109.728 68.453,109.728 68.58,109.855 68.58,110.744 68.707,110.871 68.961,110.871 69.088,110.744 69.088,109.728 69.215,109.601 69.469,109.601 69.596,109.728 69.596,110.744 69.723,110.871 69.977,110.871 70.104,110.744 70.104,109.728 70.231,109.601 70.485,109.601 70.612,109.728 70.612,110.744 70.739,110.871 70.993,110.871 71.12,110.744 71.12,109.728 71.247,109.601 71.501,109.601 71.628,109.728 71.628,110.744 71.755,110.871 72.009,110.871 72.136,110.744 72.136,110.109 73.914,108.331 73.914,104.775 75.184,103.505 83.007,103.505 83.413,103.098 85.547,100.965 86.614,100.965 87.579,100 87.579,97.383 v5(87.065,96.876)
  Bottom Layer w0.127: v3(79.407,79.959) 79.407,82.106 89.224,91.923 89.224,95.199 87.547,96.876 v5(87.065,96.876)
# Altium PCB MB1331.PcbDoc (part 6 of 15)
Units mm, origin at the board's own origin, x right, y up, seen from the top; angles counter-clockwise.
Board outline 169.25 x 173.25 mm, 6 copper layers (Top Layer, Signal Layer 1, Signal Layer 2, Signal Layer 3, Signal Layer 4, Bottom Layer), stack 1.556 mm thick; 871 components, 699 nets, 3244 pads, 2370 vias.

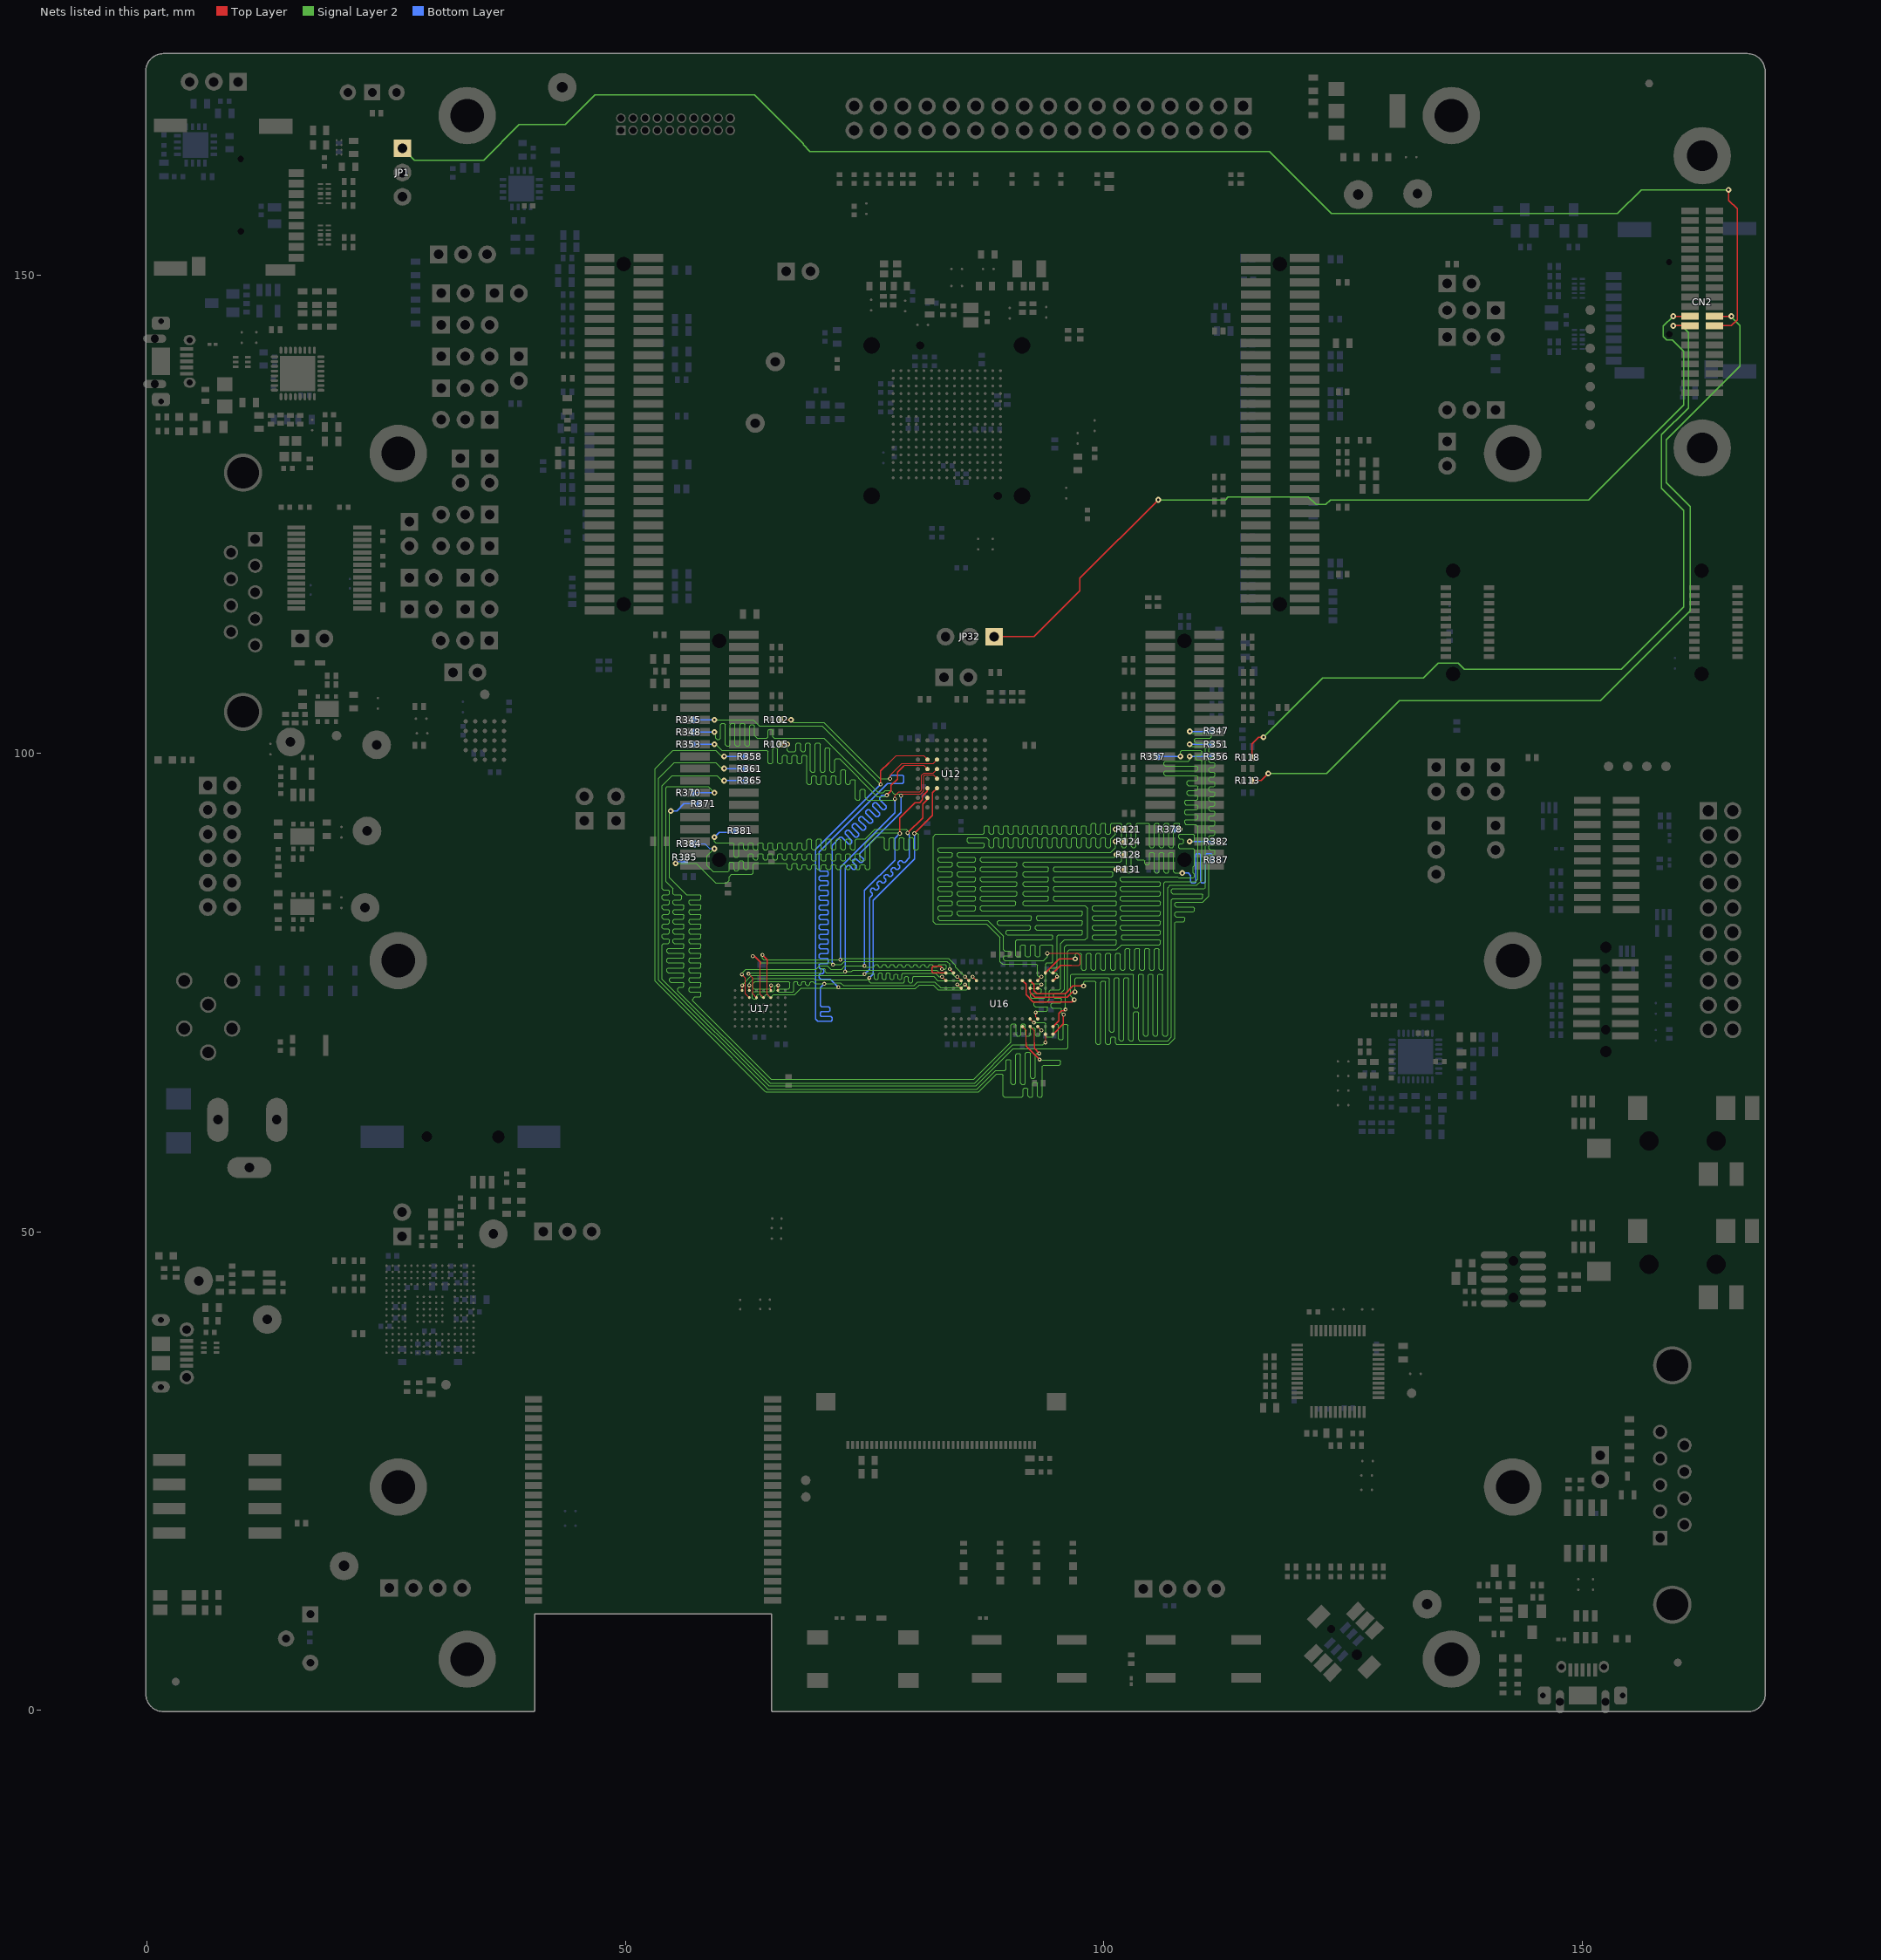
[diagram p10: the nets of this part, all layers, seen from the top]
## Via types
v1: diameter 0.6, hole 0.254, Top Layer to Bottom Layer, tented both sides, 1747 vias
v2: diameter 0.45, hole 0.2, Top Layer to Bottom Layer, tented both sides, 272 vias
v3: diameter 0.406, hole 0.203, Top Layer to Bottom Layer, tented both sides, 160 vias
v4: diameter 0.6, hole 0.25, Top Layer to Bottom Layer, tented both sides, 82 vias
v5: diameter 0.45, hole 0.25, Top Layer to Bottom Layer, tented both sides, 45 vias
v6: diameter 0.5, hole 0.25, Top Layer to Bottom Layer, tented both sides, 23 vias
v7: diameter 1.016, hole 0.508, Top Layer to Bottom Layer, tented both sides, 17 vias
v8: diameter 0.508, hole 0.254, Top Layer to Bottom Layer, tented both sides, 9 vias
v9: diameter 0.61, hole 0.305, Top Layer to Bottom Layer, tented both sides, 7 vias
v10: diameter 0.5, hole 0.254, Top Layer to Bottom Layer, tented both sides, 6 vias
v11: diameter 0.4, hole 0.2, Top Layer to Bottom Layer, tented both sides, 1 vias
v12: diameter 0.483, hole 0.254, Top Layer to Bottom Layer, tented both sides, 1 vias

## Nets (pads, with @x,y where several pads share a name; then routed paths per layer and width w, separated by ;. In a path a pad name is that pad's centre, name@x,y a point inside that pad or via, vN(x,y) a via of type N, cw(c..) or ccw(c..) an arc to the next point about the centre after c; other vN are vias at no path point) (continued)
D8: R102.2 U12.F3 U16.L2 U17.B1 | length 97.7
  Top Layer w0.102: U17.B1@65.953,75.23 65.978,75.256 v3(65.978,75.768) ; R102.2@66.236,103.505 v1(67.31,103.505) ; v5(77.667,97.358) 77.667,97.739 78.898,98.97 82.171,98.97 U12.F3@82.574,99.366 ; v3(86.297,76.663) U16.L2@86.697,76.263
  Signal Layer 2 w0.102: v3(65.978,75.768) 65.729,75.768 65.602,75.641 65.602,75.235 65.475,75.108 63.417,75.108 63.29,74.981 63.29,74.448 63.417,74.321 63.62,74.321 63.747,74.448 63.747,74.706 63.87,74.829 64.043,74.829 64.165,74.706 64.165,74.562 64.267,74.461 64.47,74.461 64.571,74.562 64.571,74.702 64.673,74.803 64.876,74.803 64.978,74.702 64.978,74.562 65.079,74.461 65.283,74.461 65.384,74.562 65.384,74.702 65.486,74.803 67.684,74.803 68.37,75.489 72.188,75.489 v3(72.264,75.565) 72.391,75.438 80.334,75.438 80.715,75.819 82.188,75.819 82.702,75.304 85.661,75.304 85.922,75.565 85.922,76.288 v3(86.297,76.663) ; v1(67.31,103.505) 67.564,103.251 70.739,103.251 76.632,97.358 v5(77.667,97.358)
  Bottom Layer w0.127: v3(72.264,75.565) 71.426,76.403 70.428,76.403 70.25,76.581 70.25,76.864 70.377,76.991 70.612,76.991 70.739,77.118 70.739,77.372 70.612,77.499 70.377,77.499 70.25,77.626 70.25,77.927 70.377,78.054 71.088,78.054 71.215,78.181 71.215,78.435 71.088,78.562 70.377,78.562 70.25,78.689 70.25,78.943 70.377,79.07 71.088,79.07 71.215,79.197 71.215,79.451 71.088,79.578 70.377,79.578 70.25,79.705 70.25,79.959 70.377,80.086 71.088,80.086 71.215,80.213 71.215,80.467 71.088,80.594 70.377,80.594 70.25,80.721 70.25,80.975 70.377,81.102 71.088,81.102 71.215,81.229 71.215,81.483 71.088,81.61 70.377,81.61 70.25,81.737 70.25,81.991 70.377,82.118 71.088,82.118 71.215,82.245 71.215,82.499 71.088,82.626 70.377,82.626 70.25,82.753 70.25,83.007 70.377,83.134 71.088,83.134 71.215,83.261 71.215,83.515 71.088,83.642 70.377,83.642 70.25,83.769 70.25,84.023 70.377,84.15 71.088,84.15 71.215,84.277 71.215,84.531 71.088,84.658 70.377,84.658 70.25,84.785 70.25,85.039 70.377,85.166 71.088,85.166 71.215,85.293 71.215,85.547 71.088,85.674 70.377,85.674 70.25,85.801 70.25,86.055 70.377,86.182 71.088,86.182 71.215,86.309 71.215,86.563 71.088,86.69 70.377,86.69 70.25,86.817 70.25,87.071 70.377,87.198 71.088,87.198 71.215,87.325 71.215,87.579 71.088,87.706 70.377,87.706 70.25,87.833 70.25,89.688 77.413,96.85 78.937,96.85 79.064,96.977 79.064,97.612 78.937,97.739 77.794,97.739 77.667,97.612 v5(77.667,97.358)
D9: R345.2 U12.G3 U16.M3 U17.C1 | length 97.7
  Top Layer w0.102: U17.C1@65.203,75.23 65.203,75.743 v3(65.228,75.768) ; 77.54,99.009 78.302,99.771 81.162,99.771 U12.G3@81.574,99.366 ; v3(85.497,75.863) U16.M3@85.897,75.463
  Top Layer w0.127: v3(76.689,96.761) 76.689,98.158 77.54,99.009
  Signal Layer 2 w0.102: v1(59.309,103.505) 63.373,103.505 64.008,102.87 70.58,102.87 v3(76.689,96.761) ; v3(65.228,75.768) 65.228,75.572 65.043,75.387 63.443,75.387 63.316,75.514 63.316,75.921 63.544,76.149 67.049,76.149 67.176,76.022 67.176,75.54 67.049,75.413 65.985,75.413 65.881,75.309 65.881,75.161 65.985,75.057 67.488,75.057 67.607,75.176 67.607,76.048 67.709,76.149 67.912,76.149 68.014,76.048 68.014,75.895 68.115,75.794 68.319,75.794 68.42,75.895 68.42,76.048 68.522,76.149 68.726,76.149 68.853,76.022 68.853,75.895 68.98,75.768 69.158,75.768 69.285,75.895 69.285,76.022 69.412,76.149 69.589,76.149 69.818,75.921 v3(70.783,75.921) 71.747,75.921 71.874,76.048 72.485,76.048 72.79,75.743 80.181,75.743 80.562,76.124 82.333,76.124 82.949,75.508 85.141,75.508 v3(85.497,75.863)
  Bottom Layer w0.127: R345.2@57.088,103.505 v1(59.309,103.505) ; v3(70.783,75.921) 70.377,75.514 70.377,73.66 70.504,73.533 71.247,73.533 71.374,73.406 71.374,73.133 71.247,73.006 70.485,73.006 70.377,72.898 70.377,72.625 70.476,72.526 71.492,72.526 71.628,72.39 71.628,72.136 71.501,72.009 70.123,72.009 69.869,72.263 69.869,89.967 76.663,96.761 v3(76.689,96.761)
D10: R353.2 U12.F4 U16.M2 U17.C2 | length 97.6
  Top Layer w0.102: 64.84,77.927 64.84,74.843 U17.C2@65.203,74.48 ; v5(78.175,95.25) 78.175,95.593 78.562,95.98 80.765,95.98 80.964,96.179 80.964,97.703 81.23,97.969 82.17,97.969 U12.F4@82.574,98.366 ; v3(85.497,76.663) U16.M2@85.897,76.263
  Top Layer w0.127: v3(64.332,78.943) 64.84,78.435 64.84,77.927
  Signal Layer 2 w0.102: v1(59.309,100.965) 59.436,100.965 60.071,100.33 64.77,100.33 64.897,100.203 64.897,99.06 65.024,98.933 65.278,98.933 65.405,99.06 65.405,100.457 65.532,100.584 65.786,100.584 65.913,100.457 65.913,99.06 66.04,98.933 66.294,98.933 66.421,99.06 66.421,99.695 66.548,99.822 66.802,99.822 66.929,99.695 66.929,99.06 67.056,98.933 67.31,98.933 67.437,99.06 67.437,99.695 67.564,99.822 67.818,99.822 67.945,99.695 67.945,99.06 68.072,98.933 68.326,98.933 68.453,99.06 68.453,99.695 68.58,99.822 68.834,99.822 68.961,99.695 68.961,96.901 69.088,96.774 69.342,96.774 69.469,96.901 69.469,97.536 69.596,97.663 69.85,97.663 69.977,97.536 69.977,96.901 70.104,96.774 70.358,96.774 70.485,96.901 70.485,97.536 70.612,97.663 70.866,97.663 70.993,97.536 70.993,96.901 71.12,96.774 71.374,96.774 71.501,96.901 71.501,97.536 71.628,97.663 71.882,97.663 72.009,97.536 72.009,96.901 72.136,96.774 72.39,96.774 72.517,96.901 72.517,98.171 72.644,98.298 72.898,98.298 73.025,98.171 73.025,96.901 73.152,96.774 73.406,96.774 73.533,96.901 73.533,97.155 73.66,97.282 73.914,97.282 74.041,97.155 74.041,95.25 74.168,95.123 74.422,95.123 74.549,95.25 74.549,96.139 74.676,96.266 74.93,96.266 75.057,96.139 75.057,95.377 75.311,95.123 78.048,95.123 v5(78.175,95.25) ; v3(64.332,78.943) 64.332,78.562 64.459,78.435 v3(72.46,78.435) 72.587,78.562 83.788,78.562 84.486,77.864 84.486,77.674 v3(85.497,76.663)
  Bottom Layer w0.127: R353.2@57.088,100.965 v1(59.309,100.965) ; v3(72.46,78.435) 72.46,88.087 78.175,93.802 v5(78.175,95.25)
D11: R105.2 U12.G4 U16.P1 U17.D2 | length 97.8
  Top Layer w0.102: 64.078,77.927 64.078,74.855 U17.D2@64.453,74.48 ; R105.2@66.236,100.965 v1(66.929,100.965) ; 79.089,98.679 79.177,98.767 81.166,98.767 U12.G4@81.574,98.366 ; v3(83.897,77.463) U16.P1@84.297,77.063
  Top Layer w0.127: v3(63.316,78.816) 63.493,78.816 64.078,78.232 64.078,77.927 ; v5(77.311,95.631) 77.768,96.088 77.768,96.673 78.429,97.333 78.429,98.019 79.089,98.679
  Signal Layer 2 w0.102: v3(63.316,78.816) 63.493,78.816 64.179,78.131 71.494,78.131 v3(71.698,77.927) 72.562,77.927 72.893,78.258 83.617,78.258 83.897,77.978 v3(83.897,77.463) ; v1(66.929,100.965) 66.929,100.33 67.056,100.203 67.691,100.203 67.818,100.33 67.818,100.965 67.945,101.092 68.199,101.092 68.326,100.965 68.326,100.33 68.453,100.203 68.707,100.203 68.834,100.33 68.834,100.965 68.961,101.092 69.215,101.092 69.342,100.965 69.342,98.171 69.469,98.044 69.723,98.044 69.85,98.171 69.85,100.965 69.977,101.092 70.231,101.092 70.358,100.965 70.358,98.171 70.485,98.044 70.739,98.044 70.866,98.171 70.866,100.457 70.993,100.584 71.247,100.584 71.374,100.457 71.374,98.171 71.501,98.044 71.755,98.044 71.882,98.171 71.882,99.314 72.009,99.441 72.39,99.441 76.327,95.504 77.184,95.504 v5(77.311,95.631)
  Bottom Layer w0.127: v3(71.698,77.927) 71.596,78.029 71.596,90.399 72.435,91.238 72.615,91.238 73.324,90.529 73.504,90.529 73.684,90.709 73.684,90.888 72.975,91.598 72.975,91.777 73.154,91.957 73.334,91.957 74.043,91.248 74.223,91.248 74.403,91.427 74.403,91.607 73.694,92.316 73.694,92.496 73.873,92.676 74.053,92.676 74.762,91.967 74.942,91.967 75.122,92.146 75.122,92.326 74.412,93.035 74.412,93.215 74.592,93.395 74.772,93.395 75.481,92.685 75.661,92.685 75.84,92.865 75.84,93.045 75.131,93.754 75.131,93.934 75.311,94.113 75.491,94.113 76.2,93.404 76.38,93.404 76.559,93.584 76.559,93.764 75.85,94.473 75.85,94.653 76.03,94.832 76.209,94.832 76.919,94.123 77.098,94.123 77.278,94.303 77.278,94.483 76.569,95.192 76.569,95.372 76.828,95.631 v5(77.311,95.631)
D12: R348.2 U12.F5 U16.N2 U17.E2 | length 97.7
  Top Layer w0.102: v3(62.874,76.972) 63.316,76.53 63.316,74.868 U17.E2@63.703,74.48 ; v5(78.81,95.58) 78.989,95.76 80.843,95.76 81.167,96.083 81.167,97.607 81.325,97.766 82.167,97.766 U12.F5@82.574,97.366 ; v3(84.697,76.663) U16.N2@85.097,76.263
  Signal Layer 2 w0.1: 64.643,101.6 64.77,101.6 64.897,101.727 64.897,102.362 65.024,102.489 65.278,102.489 65.405,102.362 65.405,101.727 65.532,101.6 70.739,101.6 76.454,95.885 76.962,95.885 77.191,96.113 77.75,96.113 78.105,95.758 78.632,95.758 v5(78.81,95.58)
  Signal Layer 2 w0.102: v1(59.309,102.235) 59.436,102.108 59.436,101.6 59.563,101.473 59.817,101.473 59.944,101.6 59.944,102.997 60.071,103.124 60.325,103.124 60.452,102.997 60.452,100.901 60.579,100.774 60.833,100.774 60.96,100.901 60.96,102.997 61.087,103.124 61.341,103.124 61.468,102.997 61.468,100.901 61.595,100.774 61.849,100.774 61.976,100.901 61.976,102.997 62.103,103.124 62.357,103.124 62.484,102.997 62.484,100.901 62.611,100.774 62.865,100.774 62.992,100.901 62.992,102.87 63.119,102.997 63.373,102.997 63.5,102.87 63.5,101.854 63.754,101.6 64.643,101.6 ; v3(62.874,76.972) 63.001,77.099 70.38,77.099 70.481,77.201 70.481,77.419 70.583,77.521 70.786,77.521 70.888,77.419 70.888,77.201 70.989,77.099 72.851,77.099 v3(72.968,77.216) 73.628,77.216 73.78,77.369 82.543,77.369 82.874,77.038 84.067,77.038 84.442,76.663 v3(84.697,76.663)
  Bottom Layer w0.127: R348.2@57.088,102.235 v1(59.309,102.235) ; v3(72.968,77.216) 72.968,88.011 73.231,88.275 73.411,88.275 73.813,87.874 73.992,87.874 74.172,88.053 74.172,88.233 73.771,88.634 73.771,88.814 73.95,88.994 74.13,88.994 74.531,88.593 74.711,88.593 74.891,88.772 74.891,88.952 74.49,89.353 74.49,89.533 78.81,93.853 v5(78.81,95.58)
D13: R384.2 U12.G6 U16.R1 U17.F2 | length 97.6
  Top Layer w0.102: v3(62.173,76.911) 62.554,76.53 62.554,75.92 62.558,75.916 62.558,74.875 U17.F2@62.953,74.48
  Top Layer w0.127: v5(78.683,91.643) 78.683,93.269 80.283,94.869 80.762,94.869 81.045,95.152 81.045,95.53 81.567,96.052 U12.G6@81.574,96.366 ; v3(83.097,77.463) 83.097,77.623 82.97,77.75 82.188,77.75 82.061,77.623 82.061,77.19 82.188,77.063 U16.R1@83.497,77.063
  Signal Layer 2 w0.102: v1(59.309,90.043) 58.547,89.281 58.547,88.265 59.182,87.63 60.706,87.63 60.833,87.757 60.833,88.519 60.96,88.646 61.214,88.646 61.341,88.519 61.341,87.884 61.468,87.757 61.722,87.757 61.849,87.884 61.849,88.646 61.976,88.773 62.23,88.773 62.357,88.646 62.357,88.011 62.484,87.884 62.738,87.884 62.865,88.011 62.865,89.408 62.992,89.535 63.246,89.535 63.373,89.408 63.373,89.027 63.5,88.9 63.754,88.9 63.881,89.027 63.881,89.408 64.008,89.535 64.262,89.535 64.389,89.408 64.389,89.027 64.516,88.9 64.77,88.9 64.897,89.027 64.897,89.408 65.024,89.535 65.278,89.535 65.405,89.408 65.405,89.027 65.532,88.9 65.786,88.9 65.913,89.027 65.913,89.408 66.04,89.535 66.294,89.535 66.421,89.408 66.421,89.027 66.548,88.9 66.802,88.9 66.929,89.027 66.929,89.408 67.056,89.535 67.31,89.535 67.437,89.408 67.437,89.027 67.564,88.9 67.818,88.9 67.945,89.027 67.945,89.408 68.072,89.535 68.326,89.535 68.453,89.408 68.453,89.027 68.58,88.9 68.834,88.9 68.961,89.027 68.961,89.408 69.088,89.535 69.342,89.535 69.469,89.408 69.469,88.9 69.596,88.773 69.85,88.773 69.977,88.9 69.977,89.408 70.104,89.535 70.358,89.535 70.485,89.408 70.485,88.9 70.612,88.773 70.866,88.773 70.993,88.9 70.993,89.408 71.12,89.535 71.374,89.535 71.501,89.408 71.501,88.9 71.628,88.773 71.882,88.773 72.009,88.9 72.009,89.408 72.136,89.535 72.39,89.535 72.517,89.408 72.517,88.9 72.644,88.773 72.898,88.773 73.025,88.9 73.025,89.408 73.152,89.535 73.406,89.535 73.533,89.408 73.533,88.9 73.66,88.773 73.914,88.773 74.041,88.9 74.041,89.408 74.168,89.535 74.422,89.535 74.549,89.408 74.549,88.9 74.676,88.773 74.93,88.773 75.057,88.9 75.057,90.551 76.225,91.719 78.613,91.719 v5(78.683,91.643) ; v3(62.173,76.911) 62.173,77.038 62.589,77.455 69.904,77.455 70.275,77.826 71.088,77.826 71.459,77.455 72.595,77.455 72.941,77.8 v3(75,77.8) 75.127,77.673 75.946,77.673 76.048,77.775 76.048,77.851 76.149,77.953 76.352,77.953 76.454,77.851 76.454,77.775 76.556,77.673 76.759,77.673 76.86,77.775 76.86,77.851 76.962,77.953 77.165,77.953 77.267,77.851 77.267,77.775 77.368,77.673 77.572,77.673 77.673,77.775 77.673,77.851 77.775,77.953 77.978,77.953 78.08,77.851 78.08,77.775 78.181,77.673 78.384,77.673 78.486,77.775 78.486,77.851 78.588,77.953 78.791,77.953 78.892,77.851 78.892,77.775 78.994,77.673 79.197,77.673 79.299,77.775 79.299,77.851 79.4,77.953 79.604,77.953 79.705,77.851 79.705,77.775 79.807,77.673 80.01,77.673 80.112,77.775 80.112,77.851 80.213,77.953 80.416,77.953 80.518,77.851 80.518,77.775 80.62,77.673 80.823,77.673 80.924,77.775 80.924,77.851 81.026,77.953 81.229,77.953 81.331,77.851 81.331,77.775 81.432,77.673 81.636,77.673 81.737,77.775 81.737,77.851 81.839,77.953 82.042,77.953 82.144,77.851 82.144,77.775 82.245,77.673 82.543,77.673 82.67,77.8 82.67,77.826 82.797,77.953 83.407,77.953 83.534,77.826 83.534,77.59 83.407,77.463 v3(83.097,77.463)
  Bottom Layer w0.1: R384.2@57.092,90.551 58.293,90.551
  Bottom Layer w0.102: 58.293,90.551 58.801,90.043 v1(59.309,90.043)
  Bottom Layer w0.127: v3(75,77.8) 75,85.674 78.175,88.849 78.175,91.135 v5(78.683,91.643)
D14: R385.2 U12.F6 U16.N3 U17.F1 | length 97.7
  Top Layer w0.102: U17.F1@62.953,75.23 v3(62.953,75.768) ; v3(84.697,75.863) U16.N3@85.097,75.463
  Top Layer w0.127: v5(80.207,91.643) 82.086,93.523 82.086,95.885 U12.F6@82.574,96.366
  Signal Layer 2 w0.102: v1(55.245,88.519) 57.404,88.519 59.436,86.487 60.579,86.487 60.833,86.741 60.833,87.122 61.087,87.376 63.246,87.376 63.373,87.503 63.373,88.392 63.5,88.519 66.802,88.519 66.929,88.392 66.929,88.011 67.056,87.884 67.31,87.884 67.437,88.011 67.437,88.392 67.564,88.519 67.818,88.519 67.945,88.392 67.945,88.011 68.072,87.884 68.326,87.884 68.453,88.011 68.453,88.265 68.58,88.392 68.834,88.392 68.961,88.265 68.961,88.011 69.088,87.884 69.342,87.884 69.469,88.011 69.469,88.265 69.596,88.392 69.85,88.392 69.977,88.265 69.977,88.011 70.104,87.884 70.358,87.884 70.485,88.011 70.485,88.265 70.612,88.392 70.866,88.392 70.993,88.265 70.993,88.011 71.12,87.884 71.374,87.884 71.501,88.011 71.501,88.265 71.628,88.392 71.882,88.392 72.009,88.265 72.009,88.011 72.136,87.884 72.39,87.884 72.517,88.011 72.517,88.265 72.644,88.392 72.898,88.392 73.025,88.265 73.025,88.011 73.152,87.884 73.406,87.884 73.533,88.011 73.533,88.265 73.66,88.392 73.914,88.392 74.041,88.265 74.041,88.011 74.168,87.884 74.422,87.884 74.549,88.011 74.549,88.265 74.676,88.392 74.93,88.392 75.057,88.265 75.057,88.011 75.184,87.884 75.438,87.884 75.565,88.011 75.565,90.551 76.276,91.262 76.962,91.262 77.089,91.135 77.089,90.043 77.216,89.916 77.495,89.916 77.597,90.018 77.597,91.059 77.724,91.186 77.978,91.186 78.105,91.059 78.105,90.018 78.207,89.916 78.511,89.916 78.613,90.018 78.613,91.059 78.74,91.186 78.994,91.186 79.121,91.059 79.121,90.018 79.223,89.916 79.527,89.916 79.629,90.018 79.629,91.059 79.756,91.186 80.01,91.186 80.137,91.059 80.137,90.018 80.239,89.916 80.518,89.916 80.645,90.043 80.645,91.516 80.518,91.643 v5(80.207,91.643) ; v3(62.953,75.768) 62.953,76.015 63.429,76.492 69.679,76.492 69.818,76.353 75.306,76.353 v3(75.502,76.548) 75.502,76.181 75.635,76.048 79.064,76.048 79.191,76.175 79.191,76.581 79.318,76.708 79.47,76.708 79.597,76.581 79.597,76.175 79.724,76.048 79.902,76.048 80.029,76.175 80.029,76.581 80.156,76.708 82.213,76.708 82.645,76.276 85.007,76.276 85.134,76.149 85.134,75.99 85.007,75.863 v3(84.697,75.863)
  Bottom Layer w0.127: v1(55.245,88.519) 55.43,88.704 R385.2@56.188,88.704 ; v3(75.502,76.548) 75.889,76.935 75.889,84.658 80.207,88.976 v5(80.207,91.643)
D15: R381.2 U12.G7 U16.R2 U17.G1 | length 97.4
  Top Layer w0.102: U17.G1@62.203,75.23 v3(62.203,75.768) ; v3(83.097,76.663) U16.R2@83.497,76.263
  Top Layer w0.127: v5(79.497,91.696) 81.07,93.269 81.07,94.691 81.567,95.188 U12.G7@81.574,95.366
  Signal Layer 2 w0.102: v1(59.309,91.249) 59.309,90.805 59.436,90.678 61.216,90.678 61.341,90.553 61.341,89.281 61.468,89.154 61.722,89.154 61.849,89.281 61.849,90.551 61.976,90.678 62.23,90.678 62.357,90.551 62.357,90.043 62.484,89.916 62.738,89.916 62.865,90.043 62.865,90.551 62.992,90.678 63.246,90.678 63.373,90.551 63.373,90.043 63.5,89.916 63.754,89.916 63.881,90.043 63.881,90.551 64.008,90.678 64.262,90.678 64.389,90.551 64.389,90.043 64.516,89.916 64.77,89.916 64.897,90.043 64.897,90.551 65.024,90.678 65.278,90.678 65.405,90.551 65.405,90.043 65.532,89.916 65.786,89.916 65.913,90.043 65.913,90.551 66.04,90.678 66.294,90.678 66.421,90.551 66.421,90.043 66.548,89.916 66.802,89.916 66.929,90.043 66.929,90.551 67.056,90.678 67.31,90.678 67.437,90.551 67.437,90.043 67.564,89.916 67.818,89.916 67.945,90.043 67.945,90.551 68.072,90.678 68.326,90.678 68.453,90.551 68.453,90.043 68.58,89.916 68.834,89.916 68.961,90.043 68.961,90.932 69.088,91.059 69.342,91.059 69.469,90.932 69.469,90.043 69.596,89.916 69.85,89.916 69.977,90.043 69.977,90.932 70.104,91.059 70.358,91.059 70.485,90.932 70.485,90.043 70.612,89.916 70.866,89.916 70.993,90.043 70.993,90.932 71.12,91.059 71.374,91.059 71.501,90.932 71.501,90.043 71.628,89.916 71.882,89.916 72.009,90.043 72.009,90.932 72.136,91.059 72.39,91.059 72.517,90.932 72.517,90.043 72.644,89.916 72.898,89.916 73.025,90.043 73.025,90.932 73.152,91.059 73.406,91.059 73.533,90.932 73.533,90.043 73.66,89.916 73.914,89.916 74.041,90.043 74.041,90.932 74.168,91.059 75.057,91.059 76.06,92.062 79.377,92.062 79.504,91.935 v5(79.497,91.696) ; v3(62.203,75.768) 62.203,75.798 63.189,76.784 74.847,76.784 v3(75,76.937) 75.097,77.034 75.934,77.034 76.035,76.933 76.035,76.48 76.137,76.378 76.34,76.378 76.442,76.48 76.442,76.945 76.561,77.064 76.729,77.064 76.848,76.945 76.848,76.48 76.95,76.378 77.153,76.378 77.254,76.48 77.254,76.945 77.373,77.064 77.542,77.064 77.661,76.945 77.661,76.48 77.762,76.378 77.946,76.378 78.073,76.505 78.073,76.836 78.199,76.962 78.378,76.962 78.505,76.836 78.505,76.505 78.632,76.378 78.759,76.378 78.886,76.505 78.886,76.907 79.013,77.034 82.395,77.034 82.766,76.663 v3(83.097,76.663)
  Bottom Layer w0.127: v1(59.309,91.249) 59.817,91.757 61.336,91.757 R381.2@61.526,91.948 ; v3(75,76.937) 75.508,77.445 75.508,84.912 75.785,85.19 75.785,85.37 75.6,85.555 75.6,85.735 75.779,85.915 75.959,85.915 76.145,85.729 76.324,85.729 76.504,85.909 76.504,86.089 76.319,86.274 76.319,86.454 76.498,86.633 76.678,86.633 76.863,86.448 77.043,86.448 77.223,86.628 77.223,86.807 77.037,86.993 77.037,87.173 77.217,87.352 77.397,87.352 77.582,87.167 77.762,87.167 77.942,87.346 77.942,87.526 77.756,87.712 77.756,87.891 77.936,88.071 78.116,88.071 78.301,87.886 78.481,87.886 78.66,88.065 78.66,88.245 78.475,88.43 78.475,88.61 78.655,88.79 78.834,88.79 79.02,88.604 79.2,88.604 79.699,89.103 79.699,91.494 v5(79.497,91.696)
D16: R358.1 U16.E8 | length 97.5
  Top Layer w0.102: U16.E8@91.497,71.463 91.528,71.432 91.891,71.07 91.891,69.781
  Top Layer w0.127: 91.891,69.781 91.891,69.418 v3(93.288,68.021)
  Signal Layer 2 w0.102: v1(60.325,99.695) 60.071,99.695 59.436,100.33 54.991,100.33 53.086,98.425 53.086,76.194 57.782,71.498 64.509,64.77 64.662,64.618 86.935,64.618 88.814,66.497 89.351,66.497 89.478,66.37 89.478,64.211 89.605,64.084 91.44,64.084 91.567,64.211 91.567,64.897 91.694,65.024 91.948,65.024 92.075,64.897 92.075,64.206 92.196,64.084 92.481,64.084 92.583,64.186 92.583,65.557 92.685,65.659 92.989,65.659 93.091,65.557 93.091,64.186 93.193,64.084 93.472,64.084 93.599,64.211 93.599,67.31 93.726,67.437 95.377,67.437 95.504,67.564 95.504,67.818 95.377,67.945 93.364,67.945 v3(93.288,68.021)
  Bottom Layer w0.127: v1(60.325,99.695) R358.1@62.542,99.695
D17: R365.1 U16.D7 | length 97.7
  Top Layer w0.102: U16.D7@92.297,72.263 v3(92.697,71.863)
  Signal Layer 2 w0.102: v1(60.325,97.155) 60.071,97.155 59.563,97.663 54.864,97.663 53.848,96.647 53.848,85.852 53.975,85.725 54.483,85.725 54.61,85.598 54.61,85.344 54.483,85.217 53.975,85.217 53.848,85.09 53.848,84.836 53.975,84.709 54.483,84.709 54.61,84.582 54.61,84.328 54.483,84.201 53.975,84.201 53.848,84.074 53.848,83.82 53.975,83.693 54.483,83.693 54.61,83.566 54.61,83.312 54.483,83.185 53.975,83.185 53.848,83.058 53.848,82.804 53.975,82.677 54.483,82.677 54.61,82.55 54.61,82.296 54.483,82.169 53.975,82.169 53.848,82.042 53.848,81.788 53.975,81.661 54.483,81.661 54.61,81.534 54.61,81.28 54.483,81.153 53.975,81.153 53.848,81.026 53.848,80.772 53.975,80.645 54.483,80.645 54.61,80.518 54.61,80.264 54.483,80.137 53.975,80.137 53.848,80.01 53.848,76.397 64.992,65.253 86.633,65.253 90.544,69.164 96.139,69.164 96.266,69.291 96.266,71.564 96.126,71.704 95.86,71.704 95.758,71.603 95.758,70.206 95.656,70.104 95.352,70.104 95.25,70.206 95.25,71.603 95.148,71.704 94.856,71.704 94.754,71.603 94.754,70.46 94.652,70.358 94.05,70.358 93.923,70.485 93.923,71.736 93.796,71.863 v3(92.697,71.863)
  Bottom Layer w0.127: v1(60.325,97.155) R365.1@62.542,97.155
D18: R361.1 U16.D8 | length 97.6
  Top Layer w0.102: U16.D8@92.297,71.463 92.328,71.431 92.741,71.019 92.741,69.781
  Top Layer w0.127: 92.741,69.781 92.741,69.178 v3(93.262,68.656)
  Signal Layer 2 w0.102: v1(60.325,98.425) 60.071,98.425 59.436,99.06 55.118,99.06 53.467,97.409 53.467,76.321 64.763,65.024 64.865,64.923 86.76,64.923 88.716,66.878 89.662,66.878 89.789,67.005 89.789,67.902 89.908,68.021 90.178,68.021 90.297,67.902 90.297,65.532 90.424,65.405 90.678,65.405 90.805,65.532 90.805,68.529 90.932,68.656 91.186,68.656 91.313,68.529 91.313,65.524 91.432,65.405 91.702,65.405 91.821,65.524 91.821,68.664 91.94,68.783 92.21,68.783 92.329,68.664 92.329,66.167 92.456,66.04 92.71,66.04 92.837,66.167 92.837,68.529 92.964,68.656 v3(93.262,68.656)
  Bottom Layer w0.127: v1(60.325,98.425) R361.1@62.542,98.425
D19: R370.1 U16.B9 | length 97.6
  Top Layer w0.102: v3(93.897,69.799) U16.B9@93.897,70.663
  Signal Layer 2 w0.102: v1(59.309,95.885) 58.674,96.52 54.356,96.52 54.229,96.393 54.229,86.614 54.991,85.852 54.991,85.344 55.118,85.217 55.753,85.217 55.88,85.09 55.88,84.836 55.753,84.709 55.118,84.709 54.991,84.582 54.991,84.328 55.118,84.201 56.007,84.201 56.134,84.074 56.134,83.82 56.007,83.693 55.118,83.693 54.991,83.566 54.991,83.312 55.118,83.185 56.007,83.185 56.134,83.058 56.134,82.804 56.007,82.677 55.118,82.677 54.991,82.55 54.991,82.296 55.118,82.169 56.007,82.169 56.134,82.042 56.134,81.788 56.007,81.661 55.118,81.661 54.991,81.534 54.991,81.28 55.118,81.153 56.007,81.153 56.134,81.026 56.134,80.772 56.007,80.645 55.118,80.645 54.991,80.518 54.991,80.264 55.118,80.137 56.007,80.137 56.134,80.01 56.134,79.756 56.007,79.629 54.483,79.629 54.356,79.502 54.356,79.248 54.483,79.121 56.007,79.121 56.134,78.994 56.134,78.74 56.007,78.613 54.483,78.613 54.356,78.486 54.356,78.232 54.483,78.105 56.007,78.105 56.134,77.978 56.134,77.724 56.007,77.597 54.483,77.597 54.356,77.47 54.356,77.216 54.483,77.089 56.007,77.089 56.134,76.962 56.134,76.708 56.007,76.581 54.737,76.581 54.61,76.454 54.61,76.2 54.737,76.073 56.007,76.073 56.134,75.946 56.134,75.692 56.007,75.565 55.626,75.565 55.496,75.435 55.496,75.181 65.119,65.558 86.506,65.558 90.494,69.545 93.643,69.545 v3(93.897,69.799)
  Bottom Layer w0.127: R370.1@57.088,95.885 v1(59.309,95.885)
D20: R371.1 U16.C8 | length 97.6
  Top Layer w0.102: U16.C8@93.097,71.463 v3(93.497,71.063)
  Signal Layer 2 w0.102: v1(54.737,93.98) 54.61,93.853 54.61,86.995 56.388,85.217 57.785,85.217 57.912,85.09 57.912,84.836 57.785,84.709 56.769,84.709 56.642,84.582 56.642,84.328 56.769,84.201 57.785,84.201 57.912,84.074 57.912,83.82 57.785,83.693 56.769,83.693 56.642,83.566 56.642,83.312 56.769,83.185 57.785,83.185 57.912,83.058 57.912,82.804 57.785,82.677 56.769,82.677 56.642,82.55 56.642,82.296 56.769,82.169 57.785,82.169 57.912,82.042 57.912,81.788 57.785,81.661 56.769,81.661 56.642,81.534 56.642,81.28 56.769,81.153 57.785,81.153 57.912,81.026 57.912,80.772 57.785,80.645 56.769,80.645 56.642,80.518 56.642,80.264 56.769,80.137 57.785,80.137 57.912,80.01 57.912,79.756 57.785,79.629 56.769,79.629 56.642,79.502 56.642,79.248 56.769,79.121 57.785,79.121 57.912,78.994 57.912,78.74 57.785,78.613 56.769,78.613 56.642,78.486 56.642,78.232 56.769,78.105 57.785,78.105 57.912,77.978 57.912,77.724 57.785,77.597 56.769,77.597 56.642,77.47 56.642,77.216 56.769,77.089 57.785,77.089 57.912,76.962 57.912,76.708 57.785,76.581 56.769,76.581 56.642,76.454 56.642,76.2 56.769,76.073 57.785,76.073 57.912,75.946 57.912,75.692 57.785,75.565 56.769,75.565 56.642,75.438 56.642,75.184 56.769,75.057 57.785,75.057 57.912,74.93 57.912,74.676 57.785,74.549 57.277,74.549 57.023,74.295 57.023,74.161 65.246,65.939 86.404,65.939 90.29,69.825 90.29,71.628 90.417,71.755 90.697,71.755 90.824,71.628 90.824,70.612 90.951,70.485 91.205,70.485 91.332,70.612 91.332,71.628 91.459,71.755 91.669,71.755 91.796,71.628 91.796,70.587 91.898,70.485 92.227,70.485 92.329,70.587 92.329,71.204 92.448,71.323 92.718,71.323 92.837,71.204 92.837,70.587 92.939,70.485 93.243,70.485 93.345,70.587 93.345,70.962 93.447,71.063 v3(93.497,71.063)
  Bottom Layer w0.127: v1(54.737,93.98) 55.372,93.98 56.134,94.742 R371.1@57.716,94.742
D21: R131.1 U16.A9 | length 97.7
  Top Layer w0.102: v1(101.346,87.884) R131.1@102.166,87.884
  Top Layer w0.127: U16.A9@94.697,70.663 95.777,71.731 95.777,72.67 v3(95.802,72.695)
  Signal Layer 2 w0.102: v3(95.802,72.695) 95.599,72.898 95.599,73.279 95.472,73.406 94.615,73.406 94.488,73.533 94.488,73.787 94.615,73.914 95.472,73.914 95.599,74.041 95.599,74.295 95.472,74.422 94.869,74.422 94.742,74.549 94.742,74.81 94.869,74.937 95.504,74.937 95.904,75.337 95.904,79.775 96.139,80.01 101.219,80.01 101.346,80.137 101.346,80.391 101.219,80.518 98.933,80.518 98.806,80.645 98.806,80.899 98.933,81.026 101.219,81.026 101.346,81.153 101.346,81.407 101.219,81.534 98.933,81.534 98.806,81.661 98.806,81.915 98.933,82.042 101.219,82.042 101.346,82.169 101.346,82.423 101.219,82.55 98.933,82.55 98.806,82.677 98.806,82.931 98.933,83.058 101.219,83.058 101.346,83.185 101.346,83.439 101.219,83.566 98.933,83.566 98.806,83.693 98.806,83.947 98.933,84.074 101.219,84.074 101.346,84.201 101.346,84.455 101.219,84.582 94.869,84.582 94.742,84.709 94.742,84.963 94.869,85.09 101.219,85.09 101.346,85.217 101.346,85.471 101.219,85.598 94.869,85.598 94.742,85.725 94.742,85.979 94.869,86.106 101.219,86.106 101.346,86.233 101.346,86.487 101.219,86.614 94.869,86.614 94.742,86.741 94.742,86.995 94.869,87.122 100.838,87.122 100.965,87.249 100.965,87.503 100.838,87.63 94.869,87.63 94.742,87.757 94.742,88.011 94.869,88.138 101.092,88.138 v1(101.346,87.884)
D22: R387.1 U16.C7 | length 97.7
  Top Layer w0.102: v3(92.881,72.949) 92.881,72.479 U16.C7@93.097,72.263
  Signal Layer 2 w0.102: v3(92.881,72.949) 93.021,73.088 94.043,73.088 94.107,73.152 94.107,73.495 94.069,73.533 92.837,73.533 92.71,73.66 92.71,73.914 92.837,74.041 94.05,74.041 94.304,74.295 94.304,75.184 94.431,75.311 95.37,75.311 95.497,75.438 95.497,80.13 95.885,80.518 98.044,80.518 98.298,80.772 98.298,83.82 98.044,84.074 91.694,84.074 91.567,84.201 91.567,84.455 91.694,84.582 94.107,84.582 94.234,84.709 94.234,84.963 94.107,85.09 91.694,85.09 91.567,85.217 91.567,85.471 91.694,85.598 94.107,85.598 94.234,85.725 94.234,85.979 94.107,86.106 91.694,86.106 91.567,86.233 91.567,86.487 91.694,86.614 94.107,86.614 94.234,86.741 94.234,86.995 94.107,87.122 91.694,87.122 91.567,87.249 91.567,87.503 91.694,87.63 94.107,87.63 94.234,87.757 94.234,88.011 94.107,88.138 91.694,88.138 91.567,88.265 91.567,88.519 91.694,88.646 101.727,88.646 101.854,88.773 101.854,89.662 101.981,89.789 102.235,89.789 102.362,89.662 102.362,87.63 102.489,87.503 102.743,87.503 102.87,87.63 102.87,89.662 102.997,89.789 103.251,89.789 103.378,89.662 103.378,89.027 103.505,88.9 104.14,88.9 104.267,88.773 104.267,88.519 104.394,88.392 104.648,88.392 104.775,88.519 104.775,89.535 104.902,89.662 105.156,89.662 105.283,89.535 105.283,87.63 105.41,87.503 105.664,87.503 105.791,87.63 105.791,89.535 105.918,89.662 106.172,89.662 106.299,89.535 106.299,87.63 106.426,87.503 106.68,87.503 106.807,87.63 106.807,89.535 106.934,89.662 107.188,89.662 107.315,89.535 107.315,87.63 107.442,87.503 v1(108.204,87.503)
  Bottom Layer w0.127: v1(108.204,87.503) 108.839,87.503 109.093,87.249 109.093,86.588 109.194,86.487 109.537,86.487 109.601,86.55 109.601,89.408 109.728,89.535 109.982,89.535 110.109,89.408 110.109,86.614 110.236,86.487 110.49,86.487 110.617,86.614 110.617,89.408 110.744,89.535 111.22,89.535 111.31,89.445 R387.1@111.31,88.9
D23: R382.1 U16.A8 | length 97.6
  Top Layer w0.127: U16.A8@94.697,71.463 94.734,71.463 95.325,72.054 95.325,72.827 95.599,73.101 95.878,73.101 v3(96.005,73.228)
  Signal Layer 2 w0.102: v3(96.005,73.228) 96.005,74.93 96.209,75.133 96.209,79.318 96.393,79.502 101.346,79.502 101.854,80.01 105.791,80.01 105.918,80.137 105.918,80.391 105.791,80.518 101.981,80.518 101.854,80.645 101.854,80.899 101.981,81.026 105.791,81.026 105.918,81.153 105.918,81.407 105.791,81.534 101.854,81.534 101.727,81.661 101.727,81.915 101.854,82.042 105.791,82.042 105.918,82.169 105.918,82.423 105.791,82.55 101.854,82.55 101.727,82.677 101.727,82.931 101.854,83.058 105.791,83.058 105.918,83.185 105.918,83.439 105.791,83.566 101.854,83.566 101.727,83.693 101.727,83.947 101.854,84.074 105.791,84.074 105.918,84.201 105.918,84.455 105.791,84.582 101.854,84.582 101.727,84.709 101.727,84.963 101.854,85.09 105.791,85.09 105.918,85.217 105.918,85.471 105.791,85.598 101.854,85.598 101.727,85.725 101.727,85.979 101.854,86.106 105.791,86.106 105.918,86.233 105.918,86.487 105.791,86.614 101.854,86.614 101.727,86.741 101.727,86.995 101.854,87.122 107.696,87.122 107.823,86.995 109.347,86.995 109.474,87.122 109.474,87.376 109.347,87.503 109.347,88.138 109.474,88.265 109.474,89.916 109.347,90.043 107.95,90.043 107.823,90.17 107.823,90.424 107.95,90.551 108.204,90.551 108.331,90.678 108.331,90.932 108.204,91.059 107.95,91.059 107.823,91.186 107.823,91.44 107.95,91.567 109.347,91.567 109.474,91.44 109.474,90.932 109.347,90.805 v1(108.966,90.805)
  Bottom Layer w0.127: v1(108.966,90.805) R382.1@111.31,90.805
D24: R128.2 U16.A2 | length 97.7
  Top Layer w0.102: v1(101.346,89.408) R128.2@102.166,89.408
  Top Layer w0.127: U16.A2@94.697,76.263 v3(95.116,76.683)
  Signal Layer 2 w0.102: v3(95.116,76.683) 95.116,76.962 94.989,77.089 94.488,77.089 94.361,77.216 94.361,77.47 94.488,77.597 94.989,77.597 95.116,77.724 95.116,79.749 95.12,79.753 95.116,79.756 95.116,80.892 95.25,81.026 97.663,81.026 97.79,81.153 97.79,81.407 97.663,81.534 92.964,81.534 92.837,81.661 92.837,81.915 92.964,82.042 97.663,82.042 97.79,82.169 97.79,82.423 97.663,82.55 93.091,82.55 92.964,82.677 92.964,82.931 93.091,83.058 97.663,83.058 97.79,83.185 97.79,83.439 97.663,83.566 87.249,83.566 87.122,83.693 87.122,83.947 87.249,84.074 90.678,84.074 90.805,84.201 90.805,84.455 90.678,84.582 87.249,84.582 87.122,84.709 87.122,84.963 87.249,85.09 90.805,85.09 90.932,85.217 90.932,85.471 90.805,85.598 87.249,85.598 87.122,85.725 87.122,85.979 87.249,86.106 90.805,86.106 90.932,86.233 90.932,86.487 90.805,86.614 87.249,86.614 87.122,86.741 87.122,86.995 87.249,87.122 90.805,87.122 90.932,87.249 90.932,87.503 90.805,87.63 87.249,87.63 87.122,87.757 87.122,88.011 87.249,88.138 90.805,88.138 90.932,88.265 90.932,88.519 90.805,88.646 87.249,88.646 87.122,88.773 87.122,89.027 87.249,89.154 101.092,89.154 v1(101.346,89.408)
D25: R124.1 U16.C3 | length 97.6
  Top Layer w0.102: U16.C3@93.097,75.463 v3(93.497,75.863) ; v1(101.219,90.805) R124.1@102.166,90.805
  Signal Layer 2 w0.102: v3(93.497,75.863) 93.414,75.946 92.456,75.946 92.329,75.819 92.329,75.565 92.456,75.438 93.345,75.438 93.472,75.311 93.472,75.057 93.345,74.93 92.456,74.93 92.329,74.803 92.329,74.549 92.456,74.422 93.814,74.422 93.941,74.549 93.941,78.007 94.043,78.109 94.583,78.109 94.685,78.211 94.685,79.883 94.558,80.01 93.472,80.01 93.345,79.883 93.345,78.867 93.218,78.74 92.964,78.74 92.837,78.867 92.837,79.883 92.71,80.01 92.456,80.01 92.329,79.883 92.329,78.867 92.202,78.74 91.948,78.74 91.821,78.867 91.821,79.883 91.694,80.01 91.44,80.01 91.313,79.883 91.313,78.867 91.186,78.74 90.932,78.74 90.805,78.867 90.805,80.391 90.932,80.518 94.553,80.518 94.685,80.65 94.685,80.899 94.558,81.026 89.916,81.026 89.789,81.153 89.789,81.407 89.916,81.534 92.202,81.534 92.329,81.661 92.329,81.915 92.202,82.042 89.027,82.042 88.9,82.169 88.9,82.423 89.027,82.55 92.329,82.55 92.456,82.677 92.456,82.931 92.329,83.058 84.836,83.058 84.709,83.185 84.709,83.439 84.836,83.566 86.487,83.566 86.614,83.693 86.614,83.947 86.487,84.074 84.836,84.074 84.709,84.201 84.709,84.455 84.836,84.582 86.487,84.582 86.614,84.709 86.614,84.963 86.487,85.09 84.836,85.09 84.709,85.217 84.709,85.471 84.836,85.598 86.487,85.598 86.614,85.725 86.614,85.979 86.487,86.106 84.836,86.106 84.709,86.233 84.709,86.487 84.836,86.614 86.487,86.614 86.614,86.741 86.614,86.995 86.487,87.122 84.836,87.122 84.709,87.249 84.709,87.503 84.836,87.63 86.487,87.63 86.614,87.757 86.614,88.011 86.487,88.138 84.836,88.138 84.709,88.265 84.709,88.519 84.836,88.646 86.487,88.646 86.614,88.773 86.614,89.027 86.487,89.154 84.836,89.154 84.709,89.281 84.709,89.535 84.836,89.662 100.711,89.662 101.219,90.17 v1(101.219,90.805)
D26: R121.1 U16.A1 | length 97.6
  Top Layer w0.102: v5(94.107,79.121) 97.282,79.121 97.536,78.867 97.536,77.978 97.409,77.851 96.647,77.851 ; v1(101.219,92.075) R121.1@102.166,92.075
  Top Layer w0.127: U16.A1@94.697,77.063 95.497,77.851 96.647,77.851
  Signal Layer 2 w0.102: v5(94.107,79.121) 94.107,78.74 93.726,78.359 89.662,78.359 89.535,78.486 89.535,78.74 89.662,78.867 90.17,78.867 90.297,78.994 90.297,79.248 90.17,79.375 89.662,79.375 89.535,79.502 89.535,80.899 87.884,82.55 82.804,82.55 82.677,82.677 82.677,82.931 82.804,83.058 84.074,83.058 84.201,83.185 84.201,83.439 84.074,83.566 82.804,83.566 82.677,83.693 82.677,83.947 82.804,84.074 84.074,84.074 84.201,84.201 84.201,84.455 84.074,84.582 82.804,84.582 82.677,84.709 82.677,84.963 82.804,85.09 84.074,85.09 84.201,85.217 84.201,85.471 84.074,85.598 82.804,85.598 82.677,85.725 82.677,85.979 82.804,86.106 84.074,86.106 84.201,86.233 84.201,86.487 84.074,86.614 82.804,86.614 82.677,86.741 82.677,86.995 82.804,87.122 84.074,87.122 84.201,87.249 84.201,87.503 84.074,87.63 82.804,87.63 82.677,87.757 82.677,88.011 82.804,88.138 84.074,88.138 84.201,88.265 84.201,88.519 84.074,88.646 82.804,88.646 82.677,88.773 82.677,89.027 82.804,89.154 84.074,89.154 84.201,89.281 84.201,89.535 84.074,89.662 82.804,89.662 82.677,89.789 82.677,90.043 82.804,90.17 87.376,90.17 87.503,90.297 87.503,90.551 87.376,90.678 85.852,90.678 85.725,90.805 85.725,91.059 85.852,91.186 87.757,91.186 88.011,90.932 88.011,90.297 88.138,90.17 88.392,90.17 88.519,90.297 88.519,91.059 88.646,91.186 88.9,91.186 89.027,91.059 89.027,90.297 89.154,90.17 89.408,90.17 89.535,90.297 89.535,91.059 89.662,91.186 89.916,91.186 90.043,91.059 90.043,90.297 90.17,90.17 90.424,90.17 90.551,90.297 90.551,91.059 90.678,91.186 90.932,91.186 91.059,91.059 91.059,90.297 91.186,90.17 91.44,90.17 91.567,90.297 91.567,91.059 91.694,91.186 91.948,91.186 92.075,91.059 92.075,90.297 92.202,90.17 92.456,90.17 92.583,90.297 92.583,91.059 92.71,91.186 92.964,91.186 93.091,91.059 93.091,90.297 93.218,90.17 93.472,90.17 93.599,90.297 93.599,91.059 93.726,91.186 93.98,91.186 94.107,91.059 94.107,90.297 94.234,90.17 94.488,90.17 94.615,90.297 94.615,91.059 94.742,91.186 94.996,91.186 95.123,91.059 95.123,90.297 95.25,90.17 95.504,90.17 95.631,90.297 95.631,91.059 95.758,91.186 96.012,91.186 96.139,91.059 96.139,90.297 96.266,90.17 96.52,90.17 96.647,90.297 96.647,91.059 96.774,91.186 97.028,91.186 97.155,91.059 97.155,90.297 97.282,90.17 97.536,90.17 97.663,90.297 97.663,91.059 97.79,91.186 98.044,91.186 98.171,91.059 98.171,90.297 98.298,90.17 98.552,90.17 98.679,90.297 98.679,91.059 98.806,91.186 99.06,91.186 99.187,91.059 99.187,90.297 99.314,90.17 99.568,90.17 99.695,90.297 99.695,91.059 99.822,91.186 100.076,91.186 100.203,91.059 100.203,90.297 100.33,90.17 100.584,90.17 100.711,90.297 100.711,91.059 101.219,91.567 v1(101.219,92.075)
D27: R378.1 U16.C2 | length 97.5
  Top Layer w0.102: U16.C2@93.097,76.263 v3(93.497,76.663)
  Signal Layer 2 w0.102: v3(93.497,76.663) 93.211,76.663 93.084,76.79 93.084,77.851 92.957,77.978 89.408,77.978 89.154,78.232 89.154,80.772 87.757,82.169 82.423,82.169 82.169,82.423 82.169,91.313 82.423,91.567 87.376,91.567 87.503,91.694 87.503,92.329 87.63,92.456 87.884,92.456 88.011,92.329 88.011,91.694 88.138,91.567 88.392,91.567 88.519,91.694 88.519,92.329 88.646,92.456 88.9,92.456 89.027,92.329 89.027,91.694 89.154,91.567 89.408,91.567 89.535,91.694 89.535,92.329 89.662,92.456 89.916,92.456 90.043,92.329 90.043,91.694 90.17,91.567 90.424,91.567 90.551,91.694 90.551,92.329 90.678,92.456 90.932,92.456 91.059,92.329 91.059,91.694 91.186,91.567 91.44,91.567 91.567,91.694 91.567,92.329 91.694,92.456 91.948,92.456 92.075,92.329 92.075,91.694 92.202,91.567 92.456,91.567 92.583,91.694 92.583,92.329 92.71,92.456 92.964,92.456 93.091,92.329 93.091,91.694 93.218,91.567 93.472,91.567 93.599,91.694 93.599,92.329 93.726,92.456 93.98,92.456 94.107,92.329 94.107,91.694 94.234,91.567 94.488,91.567 94.615,91.694 94.615,92.329 94.742,92.456 94.996,92.456 95.123,92.329 95.123,91.694 95.25,91.567 95.504,91.567 95.631,91.694 95.631,92.329 95.758,92.456 96.012,92.456 96.139,92.329 96.139,91.694 96.266,91.567 96.52,91.567 96.647,91.694 96.647,92.329 96.774,92.456 97.028,92.456 97.155,92.329 97.155,91.694 97.282,91.567 97.536,91.567 97.663,91.694 97.663,92.329 97.79,92.456 98.044,92.456 98.171,92.329 98.171,91.694 98.298,91.567 98.552,91.567 98.679,91.694 98.679,92.583 98.806,92.71 99.06,92.71 99.187,92.583 99.187,91.694 99.314,91.567 99.568,91.567 99.695,91.694 99.695,92.583 99.822,92.71 100.076,92.71 100.203,92.583 100.203,91.694 100.33,91.567 100.584,91.567 100.711,91.694 100.711,92.583 100.838,92.71 101.727,92.71 101.854,92.583 101.854,90.297 101.981,90.17 102.235,90.17 102.362,90.297 102.362,92.583 102.489,92.71 102.743,92.71 102.87,92.583 102.87,90.297 102.997,90.17 103.251,90.17 103.378,90.297 103.378,92.583 103.505,92.71 104.648,92.71 104.775,92.583 104.775,90.297 104.902,90.17 105.156,90.17 105.283,90.297 105.283,92.583 105.41,92.71 105.664,92.71 105.791,92.583 105.791,90.297 105.918,90.17 106.172,90.17 106.299,90.297 106.299,92.583 106.426,92.71 106.68,92.71 106.807,92.583 106.807,90.297 106.934,90.17 107.188,90.17 107.315,90.297 107.315,92.583 107.442,92.71 107.823,92.71 107.95,92.583 v1(107.95,92.075)
  Bottom Layer w0.127: R378.1@107.384,92.075 v1(107.95,92.075)
D28: R356.1 U16.B1 | length 97.4
  Top Layer w0.127: U16.B1@93.897,77.063 95.37,78.537 v8(97.021,78.537)
  Signal Layer 2 w0.102: v8(97.021,78.537) 97.021,78.994 97.148,79.121 97.536,79.121 97.663,78.994 97.663,77.47 97.79,77.343 98.044,77.343 98.171,77.47 98.171,78.994 98.298,79.121 98.552,79.121 98.679,78.994 98.679,77.47 98.806,77.343 99.06,77.343 99.187,77.47 99.187,78.994 99.314,79.121 99.568,79.121 99.695,78.994 99.695,77.47 99.822,77.343 100.076,77.343 100.203,77.47 100.203,78.994 100.33,79.121 100.584,79.121 100.711,78.994 100.711,77.47 100.838,77.343 101.092,77.343 101.219,77.47 101.219,78.994 101.346,79.121 101.6,79.121 101.727,78.994 101.727,77.47 101.854,77.343 102.108,77.343 102.235,77.47 102.235,79.502 102.362,79.629 102.616,79.629 102.743,79.502 102.743,77.47 102.87,77.343 103.124,77.343 103.251,77.47 103.251,79.502 103.378,79.629 103.632,79.629 103.759,79.502 103.759,77.47 103.886,77.343 104.14,77.343 104.267,77.47 104.267,79.502 104.394,79.629 104.648,79.629 104.775,79.502 104.775,77.47 104.902,77.343 105.156,77.343 105.283,77.47 105.283,79.502 105.41,79.629 105.664,79.629 105.791,79.502 105.791,77.47 105.918,77.343 106.172,77.343 106.299,77.47 106.299,86.487 106.426,86.614 109.601,86.614 109.855,86.868 109.855,92.329 109.601,92.583 108.585,92.583 108.458,92.71 108.458,92.964 108.585,93.091 109.728,93.091 109.855,93.218 109.855,93.472 109.728,93.599 108.585,93.599 108.458,93.726 108.458,93.98 108.585,94.107 109.728,94.107 109.855,94.234 109.855,94.488 109.728,94.615 108.585,94.615 108.458,94.742 108.458,94.996 108.585,95.123 109.728,95.123 109.855,95.25 109.855,95.504 109.728,95.631 108.839,95.631 108.712,95.758 108.712,96.012 108.839,96.139 109.728,96.139 109.855,96.266 109.855,96.52 109.728,96.647 108.839,96.647 108.712,96.774 108.712,97.028 108.839,97.155 109.728,97.155 109.855,97.282 109.855,97.536 109.728,97.663 106.426,97.663 106.299,97.79 106.299,98.044 106.426,98.171 109.728,98.171 109.855,98.298 109.855,98.552 109.728,98.679 106.426,98.679 106.299,98.806 106.299,99.06 106.426,99.187 108.839,99.187 108.966,99.314 v1(108.966,99.695)
  Bottom Layer w0.127: v1(108.966,99.695) R356.1@111.31,99.695
D29: R347.1 U16.D2 | length 97.7
  Top Layer w0.127: U16.D2@92.297,76.263 92.703,75.856 92.703,75.21 93.008,74.905 95.98,74.905 96.767,75.692 v8(97.885,75.692)
  Signal Layer 2 w0.102: v8(97.885,75.692) 97.885,76.073 98.012,76.2 99.06,76.2 99.187,76.073 99.187,69.723 99.314,69.596 99.568,69.596 99.695,69.723 99.695,76.073 99.822,76.2 100.108,76.2 100.203,76.105 100.203,69.723 100.33,69.596 100.584,69.596 100.711,69.723 100.711,70.231 100.838,70.358 101.092,70.358 101.219,70.231 101.219,69.723 101.346,69.596 106.807,69.596 107.442,70.231 107.442,82.296 107.569,82.423 108.331,82.423 108.458,82.55 108.458,82.804 108.331,82.931 107.569,82.931 107.442,83.058 107.442,83.312 107.569,83.439 109.347,83.439 109.474,83.566 109.474,83.82 109.347,83.947 107.569,83.947 107.442,84.074 107.442,84.328 107.569,84.455 110.363,84.455 110.998,85.09 110.998,89.281 111.125,89.408 111.506,89.408 111.633,89.535 111.633,89.789 111.506,89.916 111.125,89.916 110.998,90.043 110.998,90.297 111.125,90.424 111.506,90.424 111.633,90.551 111.633,90.805 111.506,90.932 111.125,90.932 110.998,91.059 110.998,91.313 111.125,91.44 111.506,91.44 111.633,91.567 111.633,91.821 111.506,91.948 111.125,91.948 110.998,92.075 110.998,92.329 111.125,92.456 111.506,92.456 111.633,92.583 111.633,92.837 111.506,92.964 111.125,92.964 110.998,93.091 110.998,93.345 111.125,93.472 111.506,93.472 111.633,93.599 111.633,93.853 111.506,93.98 111.125,93.98 110.998,94.107 110.998,94.361 111.125,94.488 111.506,94.488 111.633,94.615 111.633,94.869 111.506,94.996 111.125,94.996 110.998,95.123 110.998,95.377 111.125,95.504 111.506,95.504 111.633,95.631 111.633,95.885 111.506,96.012 111.125,96.012 110.998,96.139 110.998,96.393 111.125,96.52 111.506,96.52 111.633,96.647 111.633,96.901 111.506,97.028 111.125,97.028 110.998,97.155 110.998,97.409 111.125,97.536 111.506,97.536 111.633,97.663 111.633,97.917 111.506,98.044 111.125,98.044 110.998,98.171 110.998,98.425 111.125,98.552 111.506,98.552 111.633,98.679 111.633,98.933 111.506,99.06 111.125,99.06 110.998,99.187 110.998,99.441 111.125,99.568 111.506,99.568 111.633,99.695 111.633,99.949 111.506,100.076 111.125,100.076 110.998,100.203 110.998,100.457 111.125,100.584 111.506,100.584 111.633,100.711 111.633,100.965 111.506,101.092 109.601,101.092 109.474,101.219 109.474,101.473 109.601,101.6 111.125,101.6 111.252,101.727 111.252,101.981 111.125,102.108 109.192,102.108 v1(109,102.3)
  Bottom Layer w0.127: v1(109,102.3) 111.31,102.3 R347.1@111.31,102.362
D30: R351.2 U16.D3 | length 97.5
  Top Layer w0.127: U16.D3@92.297,75.463 92.296,75.032 92.805,74.524 96.158,74.524 96.717,75.083 v8(96.996,75.083)
  Signal Layer 2 w0.102: v8(96.996,75.083) 96.996,76.431 97.146,76.581 100.457,76.581 100.584,76.454 100.584,70.993 100.711,70.866 100.965,70.866 101.092,70.993 101.092,76.454 101.219,76.581 101.473,76.581 101.6,76.454 101.6,70.104 101.727,69.977 101.981,69.977 102.108,70.104 102.108,76.454 102.235,76.581 102.489,76.581 102.616,76.454 102.616,70.104 102.743,69.977 102.997,69.977 103.124,70.104 103.124,72.898 103.251,73.025 103.505,73.025 103.632,72.898 103.632,70.104 103.759,69.977 106.68,69.977 107.061,70.358 107.061,84.709 107.188,84.836 110.236,84.836 110.363,84.963 110.363,85.217 110.236,85.344 107.188,85.344 107.061,85.471 107.061,85.725 107.188,85.852 110.49,85.852 110.617,85.979 110.617,100.457 110.363,100.711 109.22,100.711 v1(108.966,100.965)
  Bottom Layer w0.127: v1(108.966,100.965) R351.2@111.31,100.965
D31: R357.2 U16.E2 | length 97.4
  Top Layer w0.127: U16.E2@91.497,76.263 91.891,75.869 91.891,74.778 92.627,74.041 96.691,74.041 v8(96.92,74.27)
  Signal Layer 2 w0.102: v8(96.92,74.27) 96.539,74.651 96.539,76.835 96.666,76.962 102.997,76.962 103.124,76.835 103.124,73.533 103.251,73.406 103.505,73.406 103.632,73.533 103.632,76.835 103.759,76.962 104.013,76.962 104.14,76.835 104.14,70.612 104.267,70.485 104.521,70.485 104.648,70.612 104.648,76.835 104.775,76.962 105.029,76.962 105.156,76.835 105.156,70.612 105.283,70.485 105.537,70.485 105.664,70.612 105.664,76.835 105.791,76.962 106.045,76.962 106.172,76.835 106.172,70.612 106.299,70.485 106.553,70.485 106.68,70.612 106.68,85.979 106.934,86.233 109.728,86.233 110.236,86.741 110.236,99.187 110.109,99.314 109.728,99.314 109.601,99.441 109.601,99.695 109.728,99.822 110.109,99.822 110.236,99.949 110.236,100.203 110.109,100.33 108.14,100.33 108.013,100.203 v1(108.013,99.695)
  Bottom Layer w0.127: R357.2@105.606,99.695 v1(108.013,99.695)
DCMI_D0: CN2.23 JP32.1 | length 96.2
  Top Layer w0.123: JP32.1@88.54,112.2 92.7,112.2 97.5,117 97.5,118.3 v1(105.7,126.5) ; v1(159.513,145.685) CN2.23@161.28,145.685
  Signal Layer 2 w0.123: v1(105.7,126.5) 112.7,126.5 113,126.8 121.4,126.8 122.2,126 123.2,126 123.7,126.5 150.7,126.5 160.6,136.4 160.6,142 159.41,143.19 158.848,143.19 158.489,143.549 158.489,144.661 v1(159.513,145.685)
DCMI_D1: CN2.24 R113.1 | length 90.3
  Top Layer w0.127: R113.1@115.512,97.155 116.455,97.155 v1(117.2,97.9) ; CN2.24@163.83,145.685 v1(165.597,145.685)
  Signal Layer 2 w0.127: v1(117.2,97.9) 123.297,97.9 130.897,105.5 151.9,105.5 161.3,114.9 161.3,125.8 158.8,128.3 158.8,132.775 166.5,140.475 166.5,144.709 165.597,145.612 v1(165.597,145.685)
DCMI_D2: CN2.25 R118.1 | length 87.4
  Top Layer w0.127: R118.1@115.512,99.568 115.512,101.012 116.2,101.7 v1(116.7,101.7) ; v1(159.513,144.685) CN2.25@161.28,144.685
  Signal Layer 2 w0.127: v1(116.7,101.7) 122.9,107.9 133.4,107.9 134.942,109.442 137.058,109.442 137.7,108.8 154.1,108.8 160.6,115.3 160.6,125.4 158.3,127.7 158.3,133.3 161.1,136.1 161.1,144 160.415,144.685 v1(159.513,144.685)
DCMI_D3: CN2.26 JP1.1 | length 164.8
  Top Layer w0.127: CN2.26@163.83,144.685 165.597,144.685 166.2,145.288 166.2,156.9 165.3,157.8 v1(165.3,158.9)
  Signal Layer 2 w0.127: JP1.1@26.7,163.24 27.94,162 35.2,162 38.9,165.7 43.7,165.7 46.8,168.8 63.5,168.8 68.6,163.7 68.6,163.6 69.3,162.9 117.3,162.9 123.8,156.4 153.7,156.4 156.2,158.9 v1(165.3,158.9)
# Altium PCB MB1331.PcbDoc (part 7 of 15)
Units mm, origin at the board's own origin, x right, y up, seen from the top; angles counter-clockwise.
Board outline 169.25 x 173.25 mm, 6 copper layers (Top Layer, Signal Layer 1, Signal Layer 2, Signal Layer 3, Signal Layer 4, Bottom Layer), stack 1.556 mm thick; 871 components, 699 nets, 3244 pads, 2370 vias.

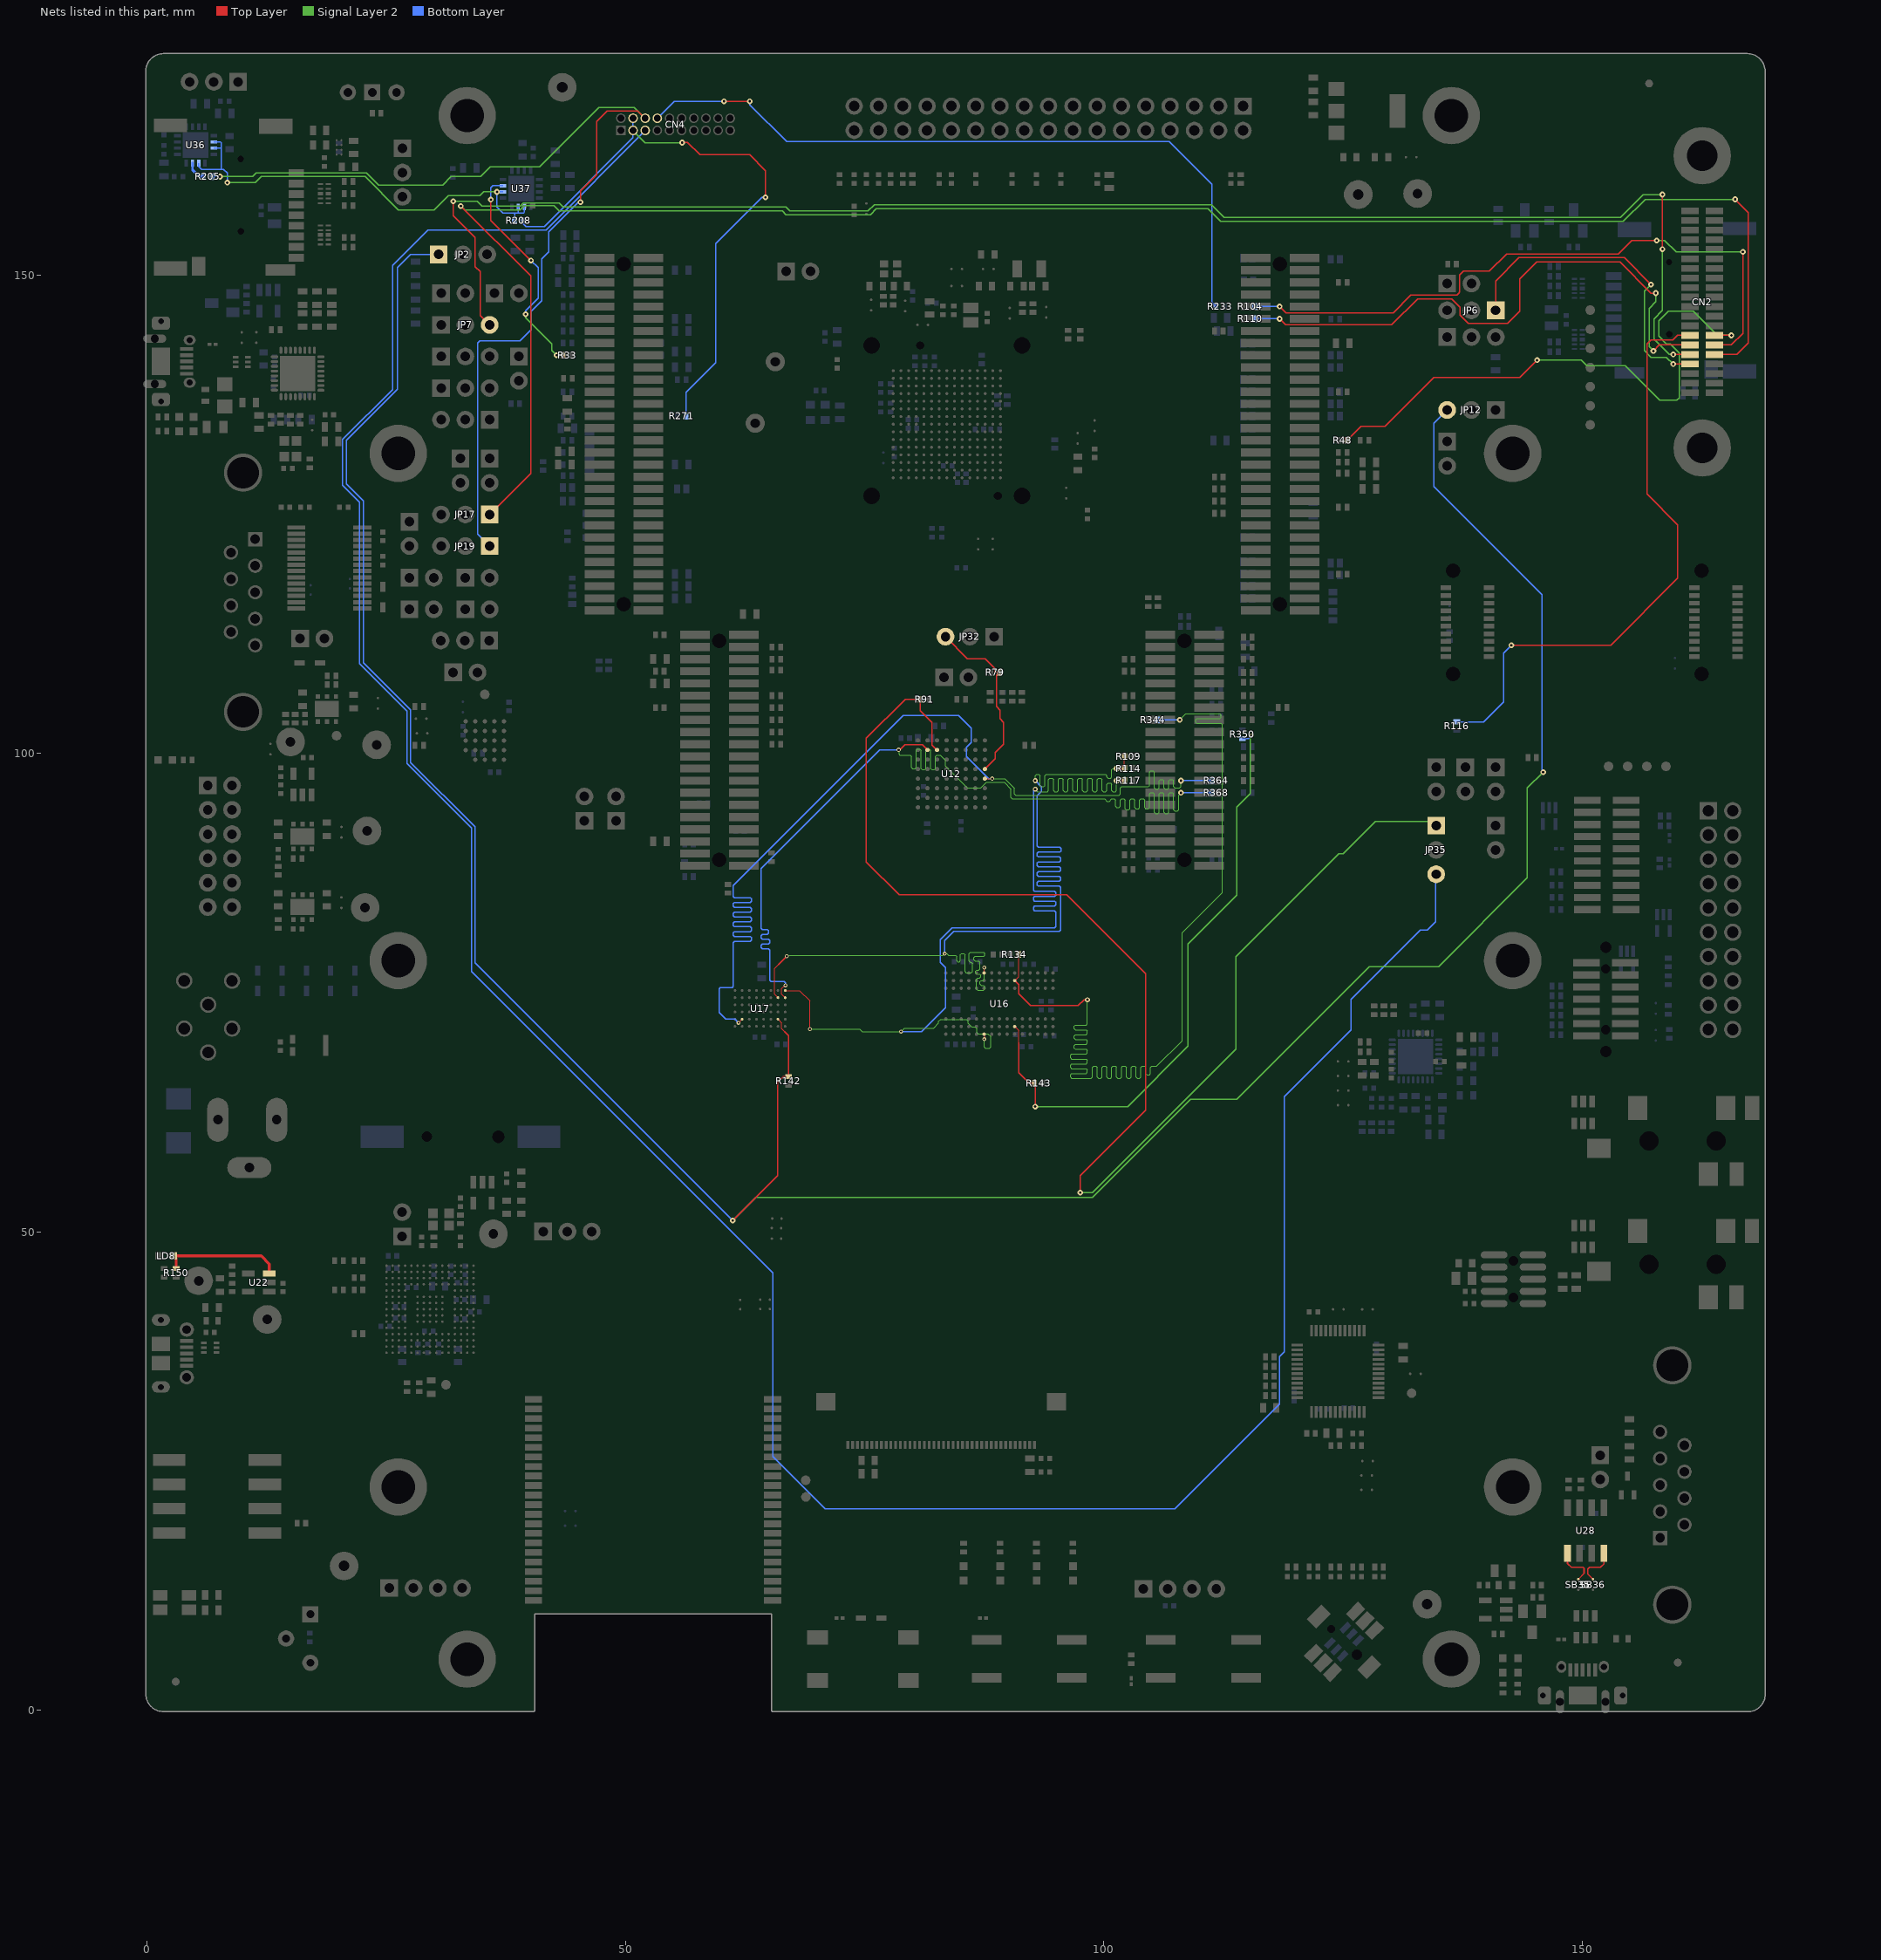
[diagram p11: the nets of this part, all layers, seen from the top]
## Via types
v1: diameter 0.6, hole 0.254, Top Layer to Bottom Layer, tented both sides, 1747 vias
v2: diameter 0.45, hole 0.2, Top Layer to Bottom Layer, tented both sides, 272 vias
v3: diameter 0.406, hole 0.203, Top Layer to Bottom Layer, tented both sides, 160 vias
v4: diameter 0.6, hole 0.25, Top Layer to Bottom Layer, tented both sides, 82 vias
v5: diameter 0.45, hole 0.25, Top Layer to Bottom Layer, tented both sides, 45 vias
v6: diameter 0.5, hole 0.25, Top Layer to Bottom Layer, tented both sides, 23 vias
v7: diameter 1.016, hole 0.508, Top Layer to Bottom Layer, tented both sides, 17 vias
v8: diameter 0.508, hole 0.254, Top Layer to Bottom Layer, tented both sides, 9 vias
v9: diameter 0.61, hole 0.305, Top Layer to Bottom Layer, tented both sides, 7 vias
v10: diameter 0.5, hole 0.254, Top Layer to Bottom Layer, tented both sides, 6 vias
v11: diameter 0.4, hole 0.2, Top Layer to Bottom Layer, tented both sides, 1 vias
v12: diameter 0.483, hole 0.254, Top Layer to Bottom Layer, tented both sides, 1 vias

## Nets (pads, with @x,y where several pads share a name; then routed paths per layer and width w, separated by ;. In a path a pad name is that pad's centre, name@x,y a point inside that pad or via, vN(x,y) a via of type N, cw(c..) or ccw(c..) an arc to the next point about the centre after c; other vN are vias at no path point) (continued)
DCMI_D4: CN2.27 R116.1 | length 63
  Top Layer w0.127: v1(142.6,111.3) 153,111.3 160,118.3 160,123.9 156.8,127.1 156.8,142.8 157.19,143.19 158.845,143.19 158.847,143.188 159.488,143.188 159.985,143.685 CN2.27@161.28,143.685
  Bottom Layer w0.127: R116.1@136.9,103.3 139.7,103.3 141.8,105.4 141.8,110.483 142.6,111.283 v1(142.6,111.3)
DCMI_D5: CN2.28 R48.2 | length 60
  Top Layer w0.127: R48.2@125.418,132.715 126.903,134.2 129.4,134.2 134.5,139.3 143.491,139.3 v1(145.288,141.097) ; CN2.28@163.83,143.685 v1(165.597,143.685)
  Signal Layer 2 w0.127: v1(145.288,141.097) 149.903,141.097 150.5,140.5 154.521,140.5 158.121,136.9 159.9,136.9 160.147,137.147 160.147,141.853 159.2,142.8 158.8,142.8 158,143.6 158,145.2 159,146.2 161.6,146.2 164.115,143.685 v1(165.597,143.685)
DCMI_D6: CN2.29 R110.2 | length 61.5
  Top Layer w0.127: v1(118.385,145.415) 119.02,144.78 130.08,144.78 132.8,147.5 136.375,147.5 137.242,146.633 137.242,145.812 138.119,144.934 142.2,144.934 143.5,146.234 143.5,149.6 145.239,151.339 153.961,151.339 157.2,148.1 v1(157.7,148.1) ; v1(157.451,142.052) 158.084,142.685 CN2.29@161.28,142.685
  Signal Layer 2 w0.127: v1(157.451,142.052) 157,142.503 157,146.5 157.7,147.2 v1(157.7,148.1)
  Bottom Layer w0.127: R110.2@115.75,145.415 v1(118.385,145.415)
DCMI_D7: CN2.30 R104.1 | length 68
  Top Layer w0.127: v1(118.385,146.7) 119.035,146.05 130.25,146.05 132.1,147.9 136.915,147.9 137.078,148.064 137.078,148.078 137.2,148.2 137.2,150 137.601,150.401 140.301,150.401 142.1,152.2 153.8,152.2 155.2,153.6 v1(157.8,153.6) ; CN2.30@163.83,142.685 165.597,142.685 166.8,143.888 v1(166.8,152.4)
  Signal Layer 2 w0.127: v1(157.8,153.6) 158.627,153.6 159.827,152.4 v1(166.8,152.4)
  Bottom Layer w0.127: R104.1@115.75,146.7 v1(118.385,146.7)
DCMI_HSYNC: CN2.31 JP7.3 | length 163.3
  Top Layer w0.127: v1(32,157.7) 32,156.2 34.295,153.905 34.295,150.871 34.824,150.342 34.824,145.77 JP7.3@35.814,144.78 ; v1(158.4,152.7) v1(158.4,158.4) ; v1(159.513,141.685) CN2.31@161.28,141.685
  Signal Layer 2 w0.127: v1(32,157.7) 34.5,157.7 35,157.2 39.037,157.2 39.362,157.525 40.324,157.525 40.325,157.526 41.463,157.526 41.464,157.525 43.075,157.525 43.5,157.1 66.8,157.1 67.2,156.7 75.362,156.7 76.015,157.353 111.247,157.353 112.6,156 154,156 156.4,158.4 v1(158.4,158.4) ; v1(158.4,152.7) 158.4,146.3 157.5,145.4 157.5,143.3 159.115,141.685 v1(159.513,141.685)
DCMI_PIXCLK: CN2.33 JP6.1 | length 34
  Top Layer w0.127: JP6.1@140.97,146.304 140.97,149.37 143.4,151.8 154.4,151.8 v1(157.2,149) ; v1(159.513,140.685) CN2.33@161.28,140.685
  Signal Layer 2 w0.127: v1(157.2,149) 156.5,148.3 156.5,142.1 157.2,141.4 158.798,141.4 v1(159.513,140.685)
DCMI_VSYNC: CN2.32 JP17.1 | length 192.4
  Top Layer w0.127: v1(32.8,157.2) 40.1,149.9 40.1,129.254 JP17.1@35.814,124.968 ; CN2.32@163.83,141.685 166.185,141.685 167.367,142.867 167.367,156.533 v1(166,157.9)
  Signal Layer 2 w0.127: v1(32.8,157.2) 33.225,156.775 38.975,156.775 39.445,157.245 42.555,157.245 43.1,156.7 66.4,156.7 66.8,156.3 75.6,156.3 76.2,156.9 110.9,156.9 112.2,155.6 154.3,155.6 156.6,157.9 v1(166,157.9)
DFSDM1_2_CKOUT: CN4.3 CN4.4 R208.2 R271.1 | length 62.7
  Top Layer w0.127: v1(55.925,163.825) 55.945,163.845 56.5,163.845 57.785,162.56 62.992,162.56 64.643,160.909 v1(64.643,158.115)
  Signal Layer 2 w0.127: CN4.3@50.8,165.1 52.075,163.825 v1(55.925,163.825)
  Bottom Layer w0.127: R208.2@39.312,155.702 39.312,155.379 39.624,155.067 41.529,155.067 50.8,164.338 CN4.3@50.8,165.1 CN4.4@50.8,166.37 ; R271.1@56.33,135.255 56.33,137.737 59.436,140.843 59.436,153.289 64.262,158.115 v1(64.643,158.115)
DFSDM1_2_CKOUT_STMPS: R208.1 U36.10 U36.11 U36.14 U37.10 U37.11 U37.14 | length 46.8
  Signal Layer 2 w0.127: v1(8.382,159.639) 11.303,159.639 11.938,160.274 22.8,160.274 26.284,156.79 29.99,156.79 31.5,158.3 34.8,158.3 35.179,158.679 v1(36.576,158.679)
  Bottom Layer w0.127: U36.14@5.405,161.676 5.405,161.346 5.715,161.036 7.747,161.036 ; U36.11@6.98,163.251 7.676,163.251 ; U36.10@6.98,163.901 7.676,163.901 7.747,163.83 7.747,161.036 ; v1(8.382,159.639) 8.382,160.655 8.001,161.036 7.747,161.036 ; U37.14@37.216,158.679 v1(36.576,158.679) 36.576,157.099 37.211,156.464 39.37,156.464 39.441,156.535 U37.10@39.441,157.104 ; R208.1@38.412,155.702 38.412,156.395 ; 38.791,156.535 U37.11@38.791,157.104
  Bottom Layer w0.254: U37.11@38.791,157.104 U37.11@38.804,157.091
DFSDM1_2_DATIN1: CN4.6 JP19.1 R205.2 | length 108.2
  Top Layer w0.127: v1(45.3,157.6) 45.3,158.775 46.99,160.465 46.99,166.015 48.109,167.134 51.306,167.134 CN4.6@52.07,166.37
  Signal Layer 2 w0.127: v1(7.62,160.274) 11.049,160.274 11.43,160.655 22.945,160.655 24.2,159.4 30.9,159.4 31.8,160.3 34.9,160.3 35.89,161.29 41.021,161.29 47.244,167.513 50.927,167.513 CN4.6@52.07,166.37
  Bottom Layer w0.127: R205.2@6.8,160.274 v1(7.62,160.274) ; JP19.1@35.814,121.666 34.544,122.936 34.544,142.875 34.798,143.129 38.989,143.129 40.1,144.24 40.1,146.145 41.275,147.32 41.275,151.675 42,152.4 42,154.5 45.1,157.6 v1(45.3,157.6)
DFSDM1_2_DATIN1_STMPS: R205.1 U36.15 | length 2.1
  Bottom Layer w0.254: U36.15@4.755,161.676 4.755,160.98 5.461,160.274 R205.1@5.9,160.274
DFSDM1_DATIN3: CN4.5 JP35.3 | length 299.8
  Bottom Layer w0.127: CN4.5@52.07,165.1 52.07,165.07 41.7,154.7 29.351,154.7 25.654,151.003 25.654,138.029 20.447,132.822 20.447,128.016 22.225,126.238 22.225,109.375 27.178,104.422 27.178,98.933 33.909,92.202 33.909,77.216 65.405,45.72 65.405,26.543 70.866,21.082 107.442,21.082 118.364,32.004 118.364,36.957 118.872,37.465 118.872,64.135 125.857,71.12 125.857,74.295 133.096,81.534 133.834,81.534 134.7,82.4 134.7,87.329 JP35.3@134.747,87.376
DFSDM1_DATIN5_STMPS: R33.1 U37.15 | length 23.5
  Top Layer w0.127: v1(35.941,157.861) 35.941,155.702 v1(40.132,151.511) ; v1(42.799,141.605) R33.1@43.492,141.605
  Signal Layer 2 w0.127: v1(39.575,145.9) 39.575,145.525 42.3,142.8 42.3,142.104 v1(42.799,141.605)
  Bottom Layer w0.127: v1(35.941,157.861) 35.941,159.131 36.139,159.329 U37.15@37.216,159.329 ; v1(39.575,145.9) 39.575,146.255 40.894,147.574 40.894,150.749 v1(40.132,151.511)
DFSDM1_DATIN7: CN4.8 R233.2 | length 75.4
  Top Layer w0.127: v1(60.3,168.15) v1(63,168.15)
  Bottom Layer w0.127: CN4.8@53.34,166.37 55.12,168.15 v1(60.3,168.15) ; v1(63,168.15) 63,167.786 66.85,163.936 106.828,163.936 111.3,159.464 111.3,147.106 R233.2@111.706,146.7
FAULTn: LD8.2 R150.1 U22.3 | length 12.8
  Top Layer w0.3: R150.1@3.048,46.17 3.048,47.202 LD8.2@2.75,47.5 11.936,47.5 12.784,46.652 U22.3@12.784,45.654
FDCAN_RX: SB36.1 U28.4 | length 4.3
  Top Layer w0.155: SB36.1@151.13,13.708 150.59,14.248 150.59,14.764 150.781,14.954 151.924,14.954 152.273,15.303 U28.4@152.273,16.421
FDCAN_TX: SB35.1 U28.1 | length 4.4
  Top Layer w0.155: U28.1@148.463,16.421 148.463,15.367 148.876,14.954 150.114,14.954 150.209,14.859 150.209,14.311 SB35.1@149.606,13.708
FMC_NBL0: R117.2 U16.K9 U17.A1 | length 108
  Top Layer w0.102: U17.A1@66.703,75.23 68.197,75.23 69.285,74.143 v3(69.285,71.196) ; v3(87.497,70.13) U16.K9@87.497,70.663 ; v1(101.346,97.155) R117.2@102.166,97.155
  Signal Layer 2 w0.102: v3(69.285,71.196) 74.492,71.196 74.746,70.942 v3(78.81,70.942) 79.165,71.298 82.213,71.298 82.741,71.826 82.741,72.011 82.949,72.219 85.644,72.219 85.852,72.011 85.852,71.774 86.207,71.419 86.562,71.419 86.734,71.247 86.734,70.841 86.861,70.714 87.877,70.714 88.182,70.409 88.182,69.317 88.055,69.19 87.624,69.19 87.497,69.317 v3(87.497,70.13) ; v8(92.837,96.266) 93.091,96.012 94.107,96.012 94.234,96.139 94.234,97.282 94.361,97.409 94.615,97.409 94.742,97.282 94.742,96.139 94.869,96.012 95.123,96.012 95.25,96.139 95.25,97.282 95.377,97.409 95.631,97.409 95.758,97.282 95.758,96.139 95.885,96.012 96.139,96.012 96.266,96.139 96.266,97.282 96.393,97.409 96.647,97.409 96.774,97.282 96.774,96.139 96.901,96.012 97.155,96.012 97.282,96.139 97.282,97.282 97.409,97.409 97.663,97.409 97.79,97.282 97.79,96.139 97.917,96.012 98.171,96.012 98.298,96.139 98.298,97.282 98.425,97.409 98.679,97.409 98.806,97.282 98.806,96.139 98.933,96.012 99.187,96.012 99.314,96.139 99.314,97.282 99.441,97.409 99.695,97.409 99.822,97.282 99.822,96.139 99.949,96.012 100.203,96.012 100.33,96.139 100.33,96.774 100.457,96.901 100.711,96.901 100.838,96.774 100.838,96.139 100.965,96.012 101.219,96.012 101.346,96.139 v1(101.346,97.155)
  Bottom Layer w0.127: v3(78.81,70.942) 80.975,70.942 83.465,73.432 83.465,76.099 83.465,77.616 82.924,78.157 82.924,80.549 84.163,81.788 94.869,81.788 94.996,81.915 94.996,83.423 94.869,83.55 92.78,83.55 92.653,83.677 92.653,83.931 92.78,84.058 94.869,84.058 94.996,84.185 94.996,84.439 94.869,84.566 92.78,84.566 92.653,84.693 92.653,84.947 92.78,85.074 94.869,85.074 94.996,85.201 94.996,85.455 94.869,85.582 92.78,85.582 92.653,85.709 92.653,96.082 v8(92.837,96.266)
FMC_NBL1: R109.2 R114.2 U16.K1 U17.B2 | length 107.7
  Top Layer w0.102: U17.B2@65.953,74.48 65.602,74.831 65.602,77.546 65.983,77.927 ; U16.K1@87.497,77.063 v3(87.497,77.622) ; v1(101.346,98.425) R114.2@102.166,98.425 R109.2@102.166,99.695
  Top Layer w0.127: 65.983,77.927 v3(66.872,78.816)
  Signal Layer 2 w0.102: v3(66.872,78.816) 66.948,78.893 83.204,78.893 v3(83.382,79.07) 83.61,79.07 83.763,78.918 84.498,78.918 84.625,78.791 84.625,78.334 84.727,78.232 84.93,78.232 85.032,78.334 85.032,78.969 85.159,79.096 85.363,79.096 85.49,78.969 85.49,77.216 85.617,77.089 86.15,77.089 86.277,77.216 86.277,78.054 86.15,78.181 86.049,78.181 85.922,78.308 85.922,79.07 86.049,79.197 87.453,79.197 87.573,79.078 87.573,78.91 87.453,78.791 86.557,78.791 86.43,78.664 86.43,78.435 86.557,78.308 86.938,78.308 87.065,78.181 87.065,77.496 86.938,77.369 86.727,77.369 86.607,77.249 86.607,77.081 86.727,76.962 87.022,76.962 87.141,76.843 87.141,76.657 87.014,76.53 86.811,76.53 86.684,76.403 86.684,75.387 86.811,75.26 87.446,75.26 87.573,75.387 87.573,75.641 87.446,75.768 87.192,75.768 87.065,75.895 87.065,76.149 87.192,76.276 87.37,76.276 87.497,76.403 v3(87.497,77.622) ; v8(92.837,97.155) 92.837,97.663 92.964,97.79 93.218,97.79 93.345,97.663 93.345,96.647 93.472,96.52 93.726,96.52 93.853,96.647 93.853,97.663 93.98,97.79 100.203,97.79 100.33,97.663 100.33,97.536 100.457,97.409 100.711,97.409 100.838,97.536 100.838,98.298 100.965,98.425 v1(101.346,98.425)
  Bottom Layer w0.127: v3(83.382,79.07) 83.382,80.467 84.321,81.407 95.377,81.407 95.504,81.534 95.504,86.003 95.377,86.13 93.161,86.13 93.034,86.257 93.034,86.511 93.161,86.638 95.377,86.638 95.504,86.765 95.504,87.019 95.377,87.146 93.161,87.146 93.034,87.273 93.034,87.527 93.161,87.654 95.377,87.654 95.504,87.781 95.504,88.035 95.377,88.162 93.161,88.162 93.034,88.289 93.034,88.543 93.161,88.67 95.377,88.67 95.504,88.797 95.504,89.051 95.377,89.178 93.161,89.178 93.034,89.305 93.034,89.559 93.161,89.686 95.396,89.686 95.523,89.813 95.523,90.067 95.396,90.194 93.161,90.194 93.034,90.321 93.034,95.574 93.491,96.031 93.491,96.501 v8(92.837,97.155)
FMC_NBL2: R143.1 R350.2 U16.F8 | length 64.8
  Top Layer w0.102: U16.F8@90.697,71.463 91.103,71.057 91.103,69.781 ; R143.1@92.717,65.481 R143.1@92.768,65.532 R143.1@92.768,65.431
  Top Layer w0.127: 91.103,69.781 91.103,66.65 92.221,65.532 R143.1@92.768,65.532 ; R143.1@92.717,65.481 92.768,65.431 92.837,65.362 v1(92.837,63.1)
  Signal Layer 2 w0.127: v1(92.837,63.1) 102.5,63.1 108.8,69.4 108.8,80.1 113.9,85.2 113.9,94.4 115.3,95.8 115.3,101.7 v2@115.5,101.9
  Bottom Layer w0.127: R350.2@114.45,101.6 R350.2@114.5,101.55 115.155,101.55 v2(115.5,101.895)
FMC_NBL3: R134.1 R344.2 U16.F2 | length 110.6
  Top Layer w0.102: U16.F2@90.697,76.263 91.097,76.663 91.097,78.956 R134.1@91.128,78.994
  Top Layer w0.127: U16.F2@90.697,76.263 91.103,75.857 91.103,74.905 92.348,73.66 97.326,73.66 97.936,74.27 v8(98.291,74.27)
  Signal Layer 2 w0.102: v8(98.291,74.27) 98.291,71.755 98.164,71.628 97.028,71.628 96.901,71.501 96.901,71.247 97.028,71.12 98.164,71.12 98.291,70.993 98.291,70.729 98.174,70.612 97.028,70.612 96.901,70.485 96.901,70.231 97.028,70.104 98.164,70.104 98.291,69.977 98.291,69.716 98.171,69.596 97.028,69.596 96.901,69.469 96.901,69.215 97.028,69.088 98.164,69.088 98.291,68.961 98.291,68.7 98.174,68.583 96.65,68.583 96.52,68.453 96.52,68.199 96.647,68.072 98.164,68.072 98.291,67.945 98.291,67.691 98.164,67.564 96.647,67.564 96.52,67.437 96.52,67.183 96.647,67.056 98.171,67.056 98.291,66.936 98.291,66.668 98.171,66.548 96.647,66.548 96.52,66.421 96.52,66.167 96.647,66.04 98.679,66.04 98.806,66.167 98.806,67.183 98.933,67.31 99.187,67.31 99.314,67.183 99.314,66.167 99.441,66.04 99.695,66.04 99.822,66.167 99.822,67.183 99.949,67.31 100.203,67.31 100.33,67.183 100.33,66.167 100.457,66.04 100.711,66.04 100.838,66.167 100.838,67.183 100.965,67.31 101.219,67.31 101.346,67.183 101.346,66.167 101.473,66.04 101.727,66.04 101.854,66.167 101.854,67.183 101.981,67.31 102.235,67.31 102.362,67.183 102.362,66.167 102.489,66.04 102.743,66.04 102.87,66.167 102.87,67.183 102.997,67.31 103.251,67.31 103.378,67.183 103.378,66.167 103.505,66.04 103.759,66.04 103.886,66.167 103.886,67.183 104.013,67.31 104.267,67.31 104.394,67.183 104.394,66.548 104.521,66.421 104.775,66.421 104.902,66.548 104.902,67.183 105.029,67.31 105.537,67.31 108.204,69.977 108.204,81.28 112.395,85.471 112.395,102.997 112.268,103.124 109.728,103.124 109.601,103.251 109.601,103.505 109.728,103.632 112.141,103.632 112.268,103.759 112.268,104.013 112.141,104.14 108.585,104.14 v1(107.95,103.505)
  Bottom Layer w0.127: R344.2@105.606,103.505 v1(107.95,103.505)
FMC_NE1: JP35.1 R91.1 U12.F2 | length 145.2
  Top Layer w0.127: U12.F2@82.567,100.366 82.061,100.873 82.061,103.232 80.83,104.463 R91.1@80.83,105.664 79.248,105.664 75.184,101.6 75.184,88.646 78.613,85.217 96.139,85.217 104.375,76.981 104.375,62.719 97.536,55.88 v1(97.536,54.102)
  Signal Layer 2 w0.127: v1(97.536,54.102) 98.806,54.102 113.792,69.088 113.792,78.74 124.587,89.535 125.035,89.535 128.4,92.9 134.303,92.9 JP35.1@134.747,92.456
FMC_NE3: JP2.1 JP12.3 R142.1 U17.B5 | length 300.5
  Top Layer w0.102: U17.B5@65.953,72.23 66.328,71.855 66.328,71.232 66.655,70.905
  Top Layer w0.127: v1(61.214,51.181) 65.933,55.9 65.933,65.679 66.49,66.236 R142.1@67.056,66.236 R142.1@67.056,66.243 ; 66.655,70.905 67.056,70.504 R142.1@67.056,66.243 ; R142.1@66.999,66.243 R142.1@67.056,66.243
  Signal Layer 2 w0.127: v1(61.214,51.181) 63.627,53.594 98.806,53.594 109.093,63.881 113.919,63.881 127.762,77.724 135.001,77.724 144.272,86.995 144.272,96.393 v1(145.923,98.044)
  Bottom Layer w0.127: JP2.1@30.48,152.146 27.546,152.146 26.162,150.762 26.162,138.062 20.828,132.728 20.828,128.143 22.606,126.365 22.606,109.494 27.559,104.541 27.559,99.06 34.29,92.329 34.29,78.105 v1(61.214,51.181) ; JP12.3@135.89,135.89 134.493,134.493 134.493,127.889 145.796,116.586 145.796,98.171 v1(145.923,98.044)
FMC_NOE: R368.2 U12.G2 U17.A2 | length 108
  Top Layer w0.102: U17.A2@66.703,74.48 66.338,74.845 66.338,75.438 66.668,75.768 v3(66.745,75.768)
  Top Layer w0.127: v5(78.556,100.368) 78.683,100.368 79.229,100.914 81.026,100.914 U12.G2@81.574,100.366
  Signal Layer 2 w0.102: v5(78.556,100.368) 78.562,99.949 78.689,99.822 79.756,99.822 79.883,99.695 79.883,98.552 80.01,98.425 80.264,98.425 80.391,98.552 80.391,100.33 80.518,100.457 80.772,100.457 80.899,100.33 80.899,98.425 81.026,98.298 81.28,98.298 81.407,98.425 81.407,100.33 81.534,100.457 81.788,100.457 81.915,100.33 81.915,98.425 82.042,98.298 82.296,98.298 82.423,98.425 82.423,99.695 82.55,99.822 82.906,99.822 83.468,99.26 83.468,98.676 85.751,96.393 87.146,96.393 87.725,96.972 89.591,96.972 90.297,96.266 90.297,95.377 90.424,95.25 100.076,95.25 100.33,94.996 100.584,94.996 100.838,95.25 101.092,95.25 101.219,95.123 101.219,94.488 101.346,94.361 101.6,94.361 101.727,94.488 101.727,95.123 101.854,95.25 102.108,95.25 102.235,95.123 102.235,94.234 102.362,94.107 102.616,94.107 102.743,94.234 102.743,95.123 102.87,95.25 103.124,95.25 103.251,95.123 103.251,94.361 103.378,94.234 103.632,94.234 103.759,94.361 103.759,95.123 103.886,95.25 104.14,95.25 104.267,95.123 104.267,94.361 104.394,94.234 104.648,94.234 104.775,94.361 104.775,95.758 104.902,95.885 105.156,95.885 105.283,95.758 105.283,93.853 105.41,93.726 105.664,93.726 105.791,93.853 105.791,95.758 105.918,95.885 106.172,95.885 106.299,95.758 106.299,93.853 106.426,93.726 106.68,93.726 106.807,93.853 106.807,95.758 106.934,95.885 107.188,95.885 107.315,95.758 107.315,94.107 107.442,93.98 107.696,93.98 107.823,94.107 107.823,95.631 v1(108.077,95.885)
  Bottom Layer w0.127: v3(66.745,75.768) 66.745,76.048 66.618,76.175 65.221,76.175 65.094,76.302 65.094,79.449 64.967,79.576 64.332,79.576 64.205,79.703 64.205,79.957 64.332,80.084 64.967,80.084 65.094,80.211 65.094,80.465 64.967,80.592 64.332,80.592 64.205,80.719 64.205,80.973 64.332,81.1 64.84,81.1 64.967,81.227 64.967,81.481 64.84,81.608 64.332,81.608 64.205,81.735 64.205,87.991 76.578,100.365 v5(78.556,100.368) ; v1(108.077,95.885) R368.2@111.31,95.885
FMC_NWAIT: JP32.3 R79.1 U12.A4 | length 18.8
  Top Layer w0.102: U12.A4@87.568,98.369 U12.A4@87.574,98.366
  Top Layer w0.122: U12.A4@87.568,98.369 U12.A4@87.569,98.371
  Top Layer w0.127: JP32.3@83.46,112.2 85.76,109.9 87.59,109.9 88.615,108.876 88.615,108.458 R79.1@89.096,108.458 88.773,108.135 88.773,104.902 89.154,104.521 89.154,103.632 89.535,103.251 89.535,100.965 88.639,100.069 88.639,99.441 87.569,98.371 U12.A4@87.574,98.366
FMC_NWE: R364.2 U12.A5 U17.G5 | length 107.6
  Top Layer w0.102: v3(61.828,71.855) U17.G5@62.203,72.23 ; U12.A5@87.574,97.366 v5(88.335,97.366)
  Signal Layer 2 w0.102: v5(88.335,97.366) 89.662,97.366 90.678,96.35 90.678,95.758 90.805,95.631 101.6,95.631 101.727,95.758 101.727,96.393 101.854,96.52 104.648,96.52 104.775,96.647 104.775,98.044 104.902,98.171 105.156,98.171 105.283,98.044 105.283,96.393 105.41,96.266 105.664,96.266 105.791,96.393 105.791,97.155 105.918,97.282 106.172,97.282 106.299,97.155 106.299,96.393 106.426,96.266 106.68,96.266 106.807,96.393 106.807,97.155 106.934,97.282 107.188,97.282 107.315,97.155 107.315,96.52 107.442,96.393 107.95,96.393 108.077,96.52 v1(108.077,97.155)
  Bottom Layer w0.127: v3(61.828,71.855) 61.459,72.224 60.51,72.224 59.785,72.949 59.785,75.387 59.912,75.514 61.157,75.514 61.284,75.641 61.284,80.238 61.411,80.365 63.062,80.365 63.189,80.492 63.189,80.746 63.062,80.873 61.411,80.873 61.284,81 61.284,81.254 61.411,81.381 63.062,81.381 63.189,81.508 63.189,81.762 63.062,81.889 61.411,81.889 61.284,82.016 61.284,82.27 61.411,82.397 63.062,82.397 63.189,82.524 63.189,82.778 63.062,82.905 61.411,82.905 61.284,83.032 61.284,83.286 61.411,83.413 63.062,83.413 63.189,83.54 63.189,83.794 63.062,83.921 61.411,83.921 61.284,84.048 61.284,84.302 61.411,84.429 63.062,84.429 63.189,84.556 63.189,84.81 63.062,84.937 61.411,84.937 61.284,85.064 61.284,86.213 79.033,103.962 84.809,103.962 86.141,102.63 86.141,101.134 85.661,100.654 85.661,99.698 87.993,97.366 v5(88.335,97.366) ; v1(108.077,97.155) R364.2@111.31,97.155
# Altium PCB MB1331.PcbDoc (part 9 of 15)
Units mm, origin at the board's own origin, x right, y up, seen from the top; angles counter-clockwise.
Board outline 169.25 x 173.25 mm, 6 copper layers (Top Layer, Signal Layer 1, Signal Layer 2, Signal Layer 3, Signal Layer 4, Bottom Layer), stack 1.556 mm thick; 871 components, 699 nets, 3244 pads, 2370 vias.

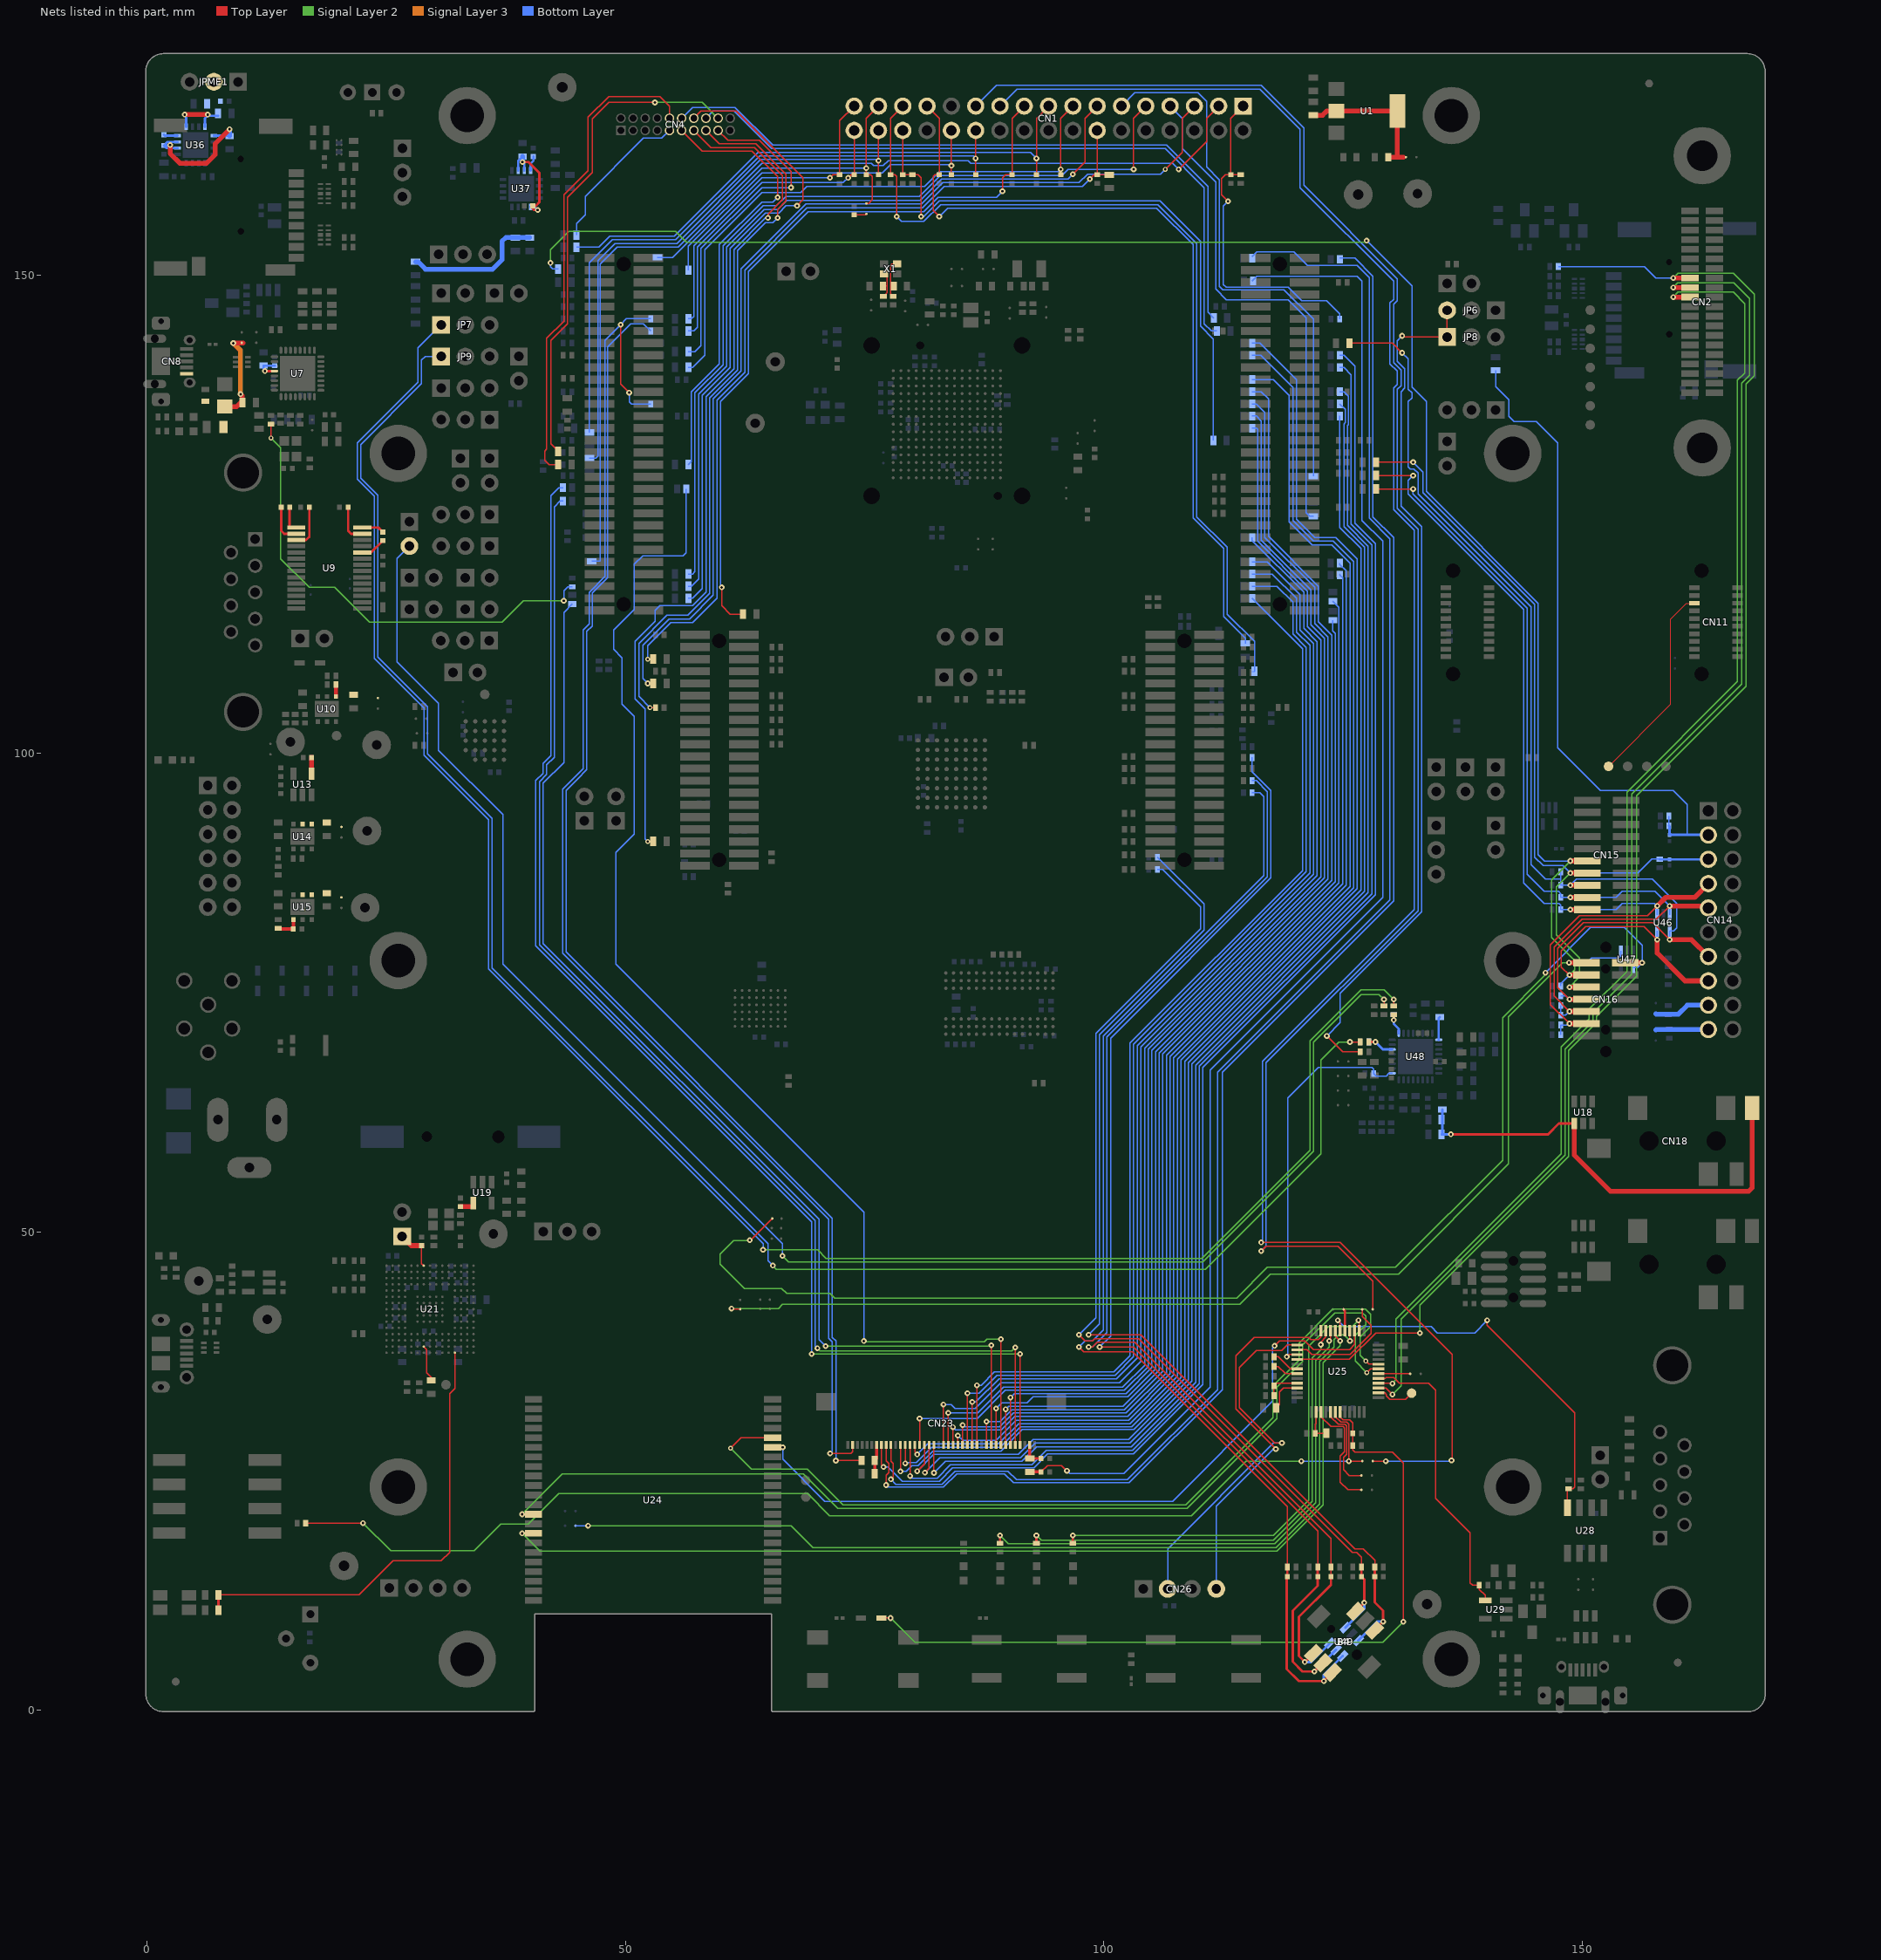
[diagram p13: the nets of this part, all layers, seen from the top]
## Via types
v1: diameter 0.6, hole 0.254, Top Layer to Bottom Layer, tented both sides, 1747 vias
v2: diameter 0.45, hole 0.2, Top Layer to Bottom Layer, tented both sides, 272 vias
v3: diameter 0.406, hole 0.203, Top Layer to Bottom Layer, tented both sides, 160 vias
v4: diameter 0.6, hole 0.25, Top Layer to Bottom Layer, tented both sides, 82 vias
v5: diameter 0.45, hole 0.25, Top Layer to Bottom Layer, tented both sides, 45 vias
v6: diameter 0.5, hole 0.25, Top Layer to Bottom Layer, tented both sides, 23 vias
v7: diameter 1.016, hole 0.508, Top Layer to Bottom Layer, tented both sides, 17 vias
v8: diameter 0.508, hole 0.254, Top Layer to Bottom Layer, tented both sides, 9 vias
v9: diameter 0.61, hole 0.305, Top Layer to Bottom Layer, tented both sides, 7 vias
v10: diameter 0.5, hole 0.254, Top Layer to Bottom Layer, tented both sides, 6 vias
v11: diameter 0.4, hole 0.2, Top Layer to Bottom Layer, tented both sides, 1 vias
v12: diameter 0.483, hole 0.254, Top Layer to Bottom Layer, tented both sides, 1 vias

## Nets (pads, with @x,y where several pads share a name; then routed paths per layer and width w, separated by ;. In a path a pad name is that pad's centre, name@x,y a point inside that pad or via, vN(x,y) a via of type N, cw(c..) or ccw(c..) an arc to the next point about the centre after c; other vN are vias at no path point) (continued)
I2S6_EXT_SD: JP6.3 JP8.1 R140.2 | length 90.5
  Top Layer w0.127: v1(123.317,70.485) 124.968,68.834 R140.2@126.804,68.834 ; v1(131.191,143.637) 131.318,143.51 JP8.1@135.89,143.51 JP6.3@135.89,146.304
  Bottom Layer w0.127: v1(123.317,70.485) 124.714,71.882 124.714,74.93 133.223,83.439 133.223,123.698 131.064,125.857 131.064,137.795 131.445,138.176 131.445,140.208 130.683,140.97 130.683,143.129 v1(131.191,143.637)
I2S6_MCK: JP9.1 R139.2 | length 194.4
  Top Layer w0.127: v1(125.73,69.85) R139.2@126.804,69.85
  Signal Layer 2 w0.127: v1(65.405,46.482) 65.786,46.101 110.617,46.101 122.682,58.166 122.682,67.945 124.587,69.85 v1(125.73,69.85)
  Bottom Layer w0.127: JP9.1@30.734,141.478 29.083,141.478 28.702,141.097 28.702,138.627 22.352,132.277 22.352,128.778 24.13,127 24.13,110.07 29.337,104.863 29.337,99.949 36.068,93.218 36.068,77.597 64.897,48.768 64.897,46.99 v1(65.405,46.482)
I2S6_SD: JP18.2 R136.2 | length 173.7
  Top Layer w0.127: R136.2@129.286,73.602 v1(129.286,74.295)
  Signal Layer 2 w0.127: v1(66.421,47.498) 67.056,46.863 110.363,46.863 121.92,58.42 121.92,69.85 126.873,74.803 128.778,74.803 v1(129.286,74.295)
  Bottom Layer w0.127: JP18.2@27.432,121.666 26.15,120.384 26.15,109.55 30.48,105.22 30.48,100.33 37.211,93.599 37.211,77.978 66.421,48.768 v1(66.421,47.498)
I2S6_WS: JP7.1 R137.2 | length 203.6
  Top Layer w0.127: R137.2@130.302,73.602 v1(130.302,74.295)
  Signal Layer 2 w0.127: v1(64.389,48.133) 70.104,48.133 70.993,47.244 110.236,47.244 121.539,58.547 121.539,69.977 126.873,75.311 129.286,75.311 v1(130.302,74.295)
  Bottom Layer w0.127: JP7.1@30.734,144.78 28.321,142.367 28.321,138.796 21.971,132.446 21.971,128.651 23.749,126.873 23.749,109.951 28.956,104.744 28.956,99.822 35.687,93.091 35.687,77.47 64.389,48.768 v1(64.389,48.133)
INTn: CN11.16 TP13.1 | length 21.3
  Top Layer w0.1: TP13.1@152.76,98.645 159.258,105.143 159.258,114.046 160.912,115.7 CN11.16@161.75,115.7
J_RX: CN16.13 SB52.1 U47.4 | length 136.2
  Top Layer w0.127: v1(62.989,49.133) 63.083,49.133 SB52.1@65.35,51.4
  Top Layer w0.508: CN16.13@154.5,78.12 v1(156.267,78.12)
  Signal Layer 2 w0.127: v1@63,49.1 61.3,49.1 59.9,47.7 59.9,46.653 62.453,44.1 66.325,44.1 66.85,43.575 71.4,43.575 71.875,43.1 113.9,43.1 117.1,46.3 130.513,46.3 141.7,57.487 141.7,72.4 146.05,76.75 146.05,76.965 v1(146.177,77.092)
  Bottom Layer w0.127: v1(146.177,77.092) 150.885,81.8 154.4,81.8 156.267,79.933 v1(156.267,78.12) 155.783,77.636 U47.4@155.336,77.636
J_TX: CN16.14 SB51.2 U47.1 | length 120.4
  Top Layer w0.127: v1(61.1,42) 61.175,41.925 SB51.2@62,41.925 ; CN16.14@150.436,78.12 CN16.14@150.444,78.112
  Top Layer w0.508: v1@148.669,78.12 CN16.14@150.436,78.12
  Signal Layer 2 w0.127: v1(61.1,42) 66,42 66.418,42.418 114.243,42.418 117.418,45.593 130.793,45.593 142.3,57.1 142.3,72.47 147.95,78.12 v1@148.669,78.12
  Bottom Layer w0.127: v1@148.669,78.12 150.495,78.12 150.988,78.613 153.797,78.613 154.036,78.852 U47.1@154.036,79.336
  other v1: 148.638,78.14
JOYSTICK.JOY_DOWN: B4.3 C80.2 R183.1 R367.1 U49.4 | length 122.1
  Top Layer w0.127: v1(97.409,37.973) 97.917,37.465 102.997,37.465 119.184,21.278 R183.1@119.184,14.986
  Top Layer w0.254: R183.1@119.184,14.986 C80.2@119.184,13.97 119.126,13.912 119.126,4.318 120.37,3.074 v1(122.999,3.074) B4.3@123.909,3.984
  Bottom Layer w0.127: v1(97.409,37.973) 98.044,38.608 98.806,38.608 99.949,39.751 99.949,70.485 116.713,87.249 116.713,95.504 116.332,95.885 R367.1@115.512,95.885
  Bottom Layer w0.254: v1(122.999,3.074) 122.999,3.71 U49.4@124.97,5.681
JOYSTICK.JOY_LEFT: B4.1 C82.2 R185.1 R363.1 U49.6 | length 121.4
  Top Layer w0.127: v1(98.425,37.973) 98.806,37.973 99.314,38.481 103.251,38.481 123.756,17.976 R185.1@123.756,14.986 C82.2@123.756,13.97
  Top Layer w0.254: B4.1@121.929,5.964 v1(121.019,5.054) 120.396,5.677 120.396,9.779 123.756,13.139 C82.2@123.756,13.97
  Bottom Layer w0.127: v1(98.425,37.973) 98.806,37.973 100.33,39.497 100.33,70.358 117.094,87.122 117.094,96.012 115.951,97.155 R363.1@115.512,97.155
  Bottom Layer w0.254: v1(121.019,5.054) 121.655,5.054 U49.6@123.626,7.025
JOYSTICK.JOY_RIGHT: B4.6 C84.2 R187.1 R386.1 U49.3 | length 108.1
  Top Layer w0.127: v1(98.425,39.243) 103.886,39.243 126.238,16.891 127.127,16.891 128.328,15.69 R187.1@128.328,14.986
  Top Layer w0.254: B4.6@128.293,8.368 v1(129.203,9.278) 129.203,10.414 128.328,11.289 C84.2@128.328,13.97 R187.1@128.328,14.986
  Bottom Layer w0.127: v1(98.425,39.243) 99.568,40.386 99.568,70.612 110.49,81.534 110.49,84.27 R386.1@105.606,89.154
  Bottom Layer w0.254: U49.3@126.596,7.307 128.567,9.278 v1(129.203,9.278)
JOYSTICK.JOY_SEL: B4.2 C81.2 R184.1 R360.1 U49.5 | length 122.5
  Top Layer w0.127: v1(99.568,37.973) 103.124,37.973 122.37,18.727 R184.1@122.37,14.986
  Top Layer w0.254: R184.1@122.37,14.986 C81.2@122.37,13.97 122.37,13.023 119.761,10.414 119.761,5.08 120.777,4.064 v1(122.009,4.064) B4.2@122.919,4.974
  Bottom Layer w0.127: v1(99.568,37.973) 100.711,39.116 100.711,70.231 117.475,86.995 117.475,96.139 115.512,98.102 R360.1@115.512,99.568
  Bottom Layer w0.254: v1(122.009,4.064) U49.5@124.298,6.353
JOYSTICK.JOY_UP: B4.4 C83.2 R186.1 R389.1 U49.1 | length 105
  Top Layer w0.127: v1(97.409,39.243) 98.044,38.608 98.806,38.608 99.06,38.862 103.632,38.862 125.984,16.51 126.434,16.51 126.942,16.002 R186.1@126.942,14.986
  Top Layer w0.254: B4.4@126.313,10.348 v1(127.223,11.258) 127.223,13.689 C83.2@126.942,13.97 R186.1@126.942,14.986
  Bottom Layer w0.127: v1(97.409,39.243) 99.187,41.021 99.187,70.739 110.109,81.661 110.109,83.947 106.172,87.884 R389.1@105.606,87.884
  Bottom Layer w0.254: U49.1@125.252,8.651 127.223,10.622 v1(127.223,11.258)
JTAG_HOST_NRST: CN14.15 CN15.10 CN16.12 R218.1 R398.2 U46.5 | length 207
  Top Layer w0.127: v1(148.669,76.85) 147.828,77.691 147.828,79.375 150.368,81.915 156.464,81.915 v1(157.846,80.533) v1@157.846,80.279 ; CN16.12@150.436,76.85 CN16.12@150.444,76.842
  Top Layer w0.508: v1(148.669,76.85) CN16.12@150.436,76.85 ; v1(148.771,88.765) CN15.10@150.538,88.765 ; v1@157.846,80.279 157.846,79.144 160.755,76.235 CN14.15@163.195,76.235
  Signal Layer 2 w0.127: v4(42.164,151.257) 42.164,152.654 44.069,154.559 55.245,154.559 56.388,153.416 127.298,153.416 v1(127.467,153.584) ; v1(148.669,76.85) 149.225,77.406 149.225,78.359 146.812,80.772 146.812,86.806 v1(148.771,88.765)
  Bottom Layer w0.127: v4(42.164,151.257) 42.164,150.876 42.418,150.622 R218.1@42.988,150.622 ; v1(127.467,153.584) 132.207,148.844 132.207,138.303 133.731,136.779 133.731,127.381 145.415,115.697 145.415,89.408 146.058,88.765 v1(148.771,88.765) ; R398.2@147.77,75.692 147.77,75.946 148.669,76.845 v1(148.669,76.85) ; v1(157.846,80.533) U46.5@157.846,81.446
JTAG_TCK: CN14.9 CN15.4 CN16.6 R59.1 R393.2 R401.2 R406.1 U46.3 | length 98
  Top Layer w0.127: R59.1@128.462,127.635 v1(132.334,127.635) ; v1(148.669,73.04) 147.066,74.643 147.066,79.756 149.987,82.677 157.764,82.677 v1(159.146,84.059) ; CN16.6@150.436,73.04 CN16.6@150.444,73.032
  Top Layer w0.508: v1(148.669,73.04) CN16.6@150.436,73.04 ; v1(148.771,84.955) CN15.4@150.538,84.955 ; v1(159.146,84.059) 162.991,84.059 CN14.9@163.195,83.855
  Bottom Layer w0.127: v1(132.334,127.635) 132.334,127.127 144.272,115.189 144.272,87.376 146.05,85.598 147.516,85.598 147.77,85.344 R393.2@147.77,84.963 v1@148.763,84.963 ; R401.2@147.77,73.66 R406.1@147.77,72.644 148.273,72.644 v1(148.669,73.04) ; v1(148.771,84.955) 153.543,84.955 154.186,85.598 157.607,85.598 v1(159.146,84.059) U46.3@159.146,83.146
JTAG_TDI: CN14.5 CN15.8 CN16.10 R53.1 R388.1 U45.1 | length 88.4
  Top Layer w0.127: R53.1@128.462,130.429 v1(132.334,130.429) ; CN16.10@150.436,75.58 CN16.10@150.444,75.572
  Top Layer w0.508: v1(148.669,75.58) CN16.10@150.436,75.58 ; v1(148.771,87.495) CN15.8@150.538,87.495
  Signal Layer 2 w0.127: v1(148.669,75.58) 149.733,76.644 149.733,78.613 147.32,81.026 147.32,86.044 v1(148.771,87.495)
  Bottom Layer w0.127: v1(132.334,130.429) 133.35,129.413 133.35,127.254 145.034,115.57 145.034,89.154 145.923,88.265 148.001,88.265 v1(148.771,87.495) ; v1@148.771,87.503 155.829,87.503 157.284,88.958 U45.1@159.136,88.958
  Bottom Layer w0.254: R388.1@158.12,88.95 158.135,88.935 CN14.5@163.195,88.935
JTAG_TDO: CN14.13 CN15.6 CN16.8 R32.1 R390.2 R392.1 R399.2 U46.4 | length 117.2
  Top Layer w0.127: R32.1@125.668,142.875 130.175,142.875 v1(131.191,141.859) ; v1(148.669,74.31) 147.447,75.532 147.447,79.629 150.114,82.296 157.383,82.296 v1(159.146,80.533) ; CN16.8@150.436,74.31 CN16.8@150.444,74.302
  Top Layer w0.508: v1(148.669,74.31) CN16.8@150.436,74.31 ; v1(148.771,86.225) CN15.6@150.538,86.225 ; v1(159.146,80.533) 161.437,80.533 CN14.13@163.195,78.775
  Bottom Layer w0.127: v1(131.191,141.859) 131.826,141.224 131.826,138.049 132.207,137.668 132.207,137.16 131.826,136.779 131.826,129.921 132.022,129.725 132.403,129.725 132.842,129.286 132.842,127.127 144.653,115.316 144.653,88.392 146.177,86.868 147.77,86.868 ; R399.2@147.77,74.676 148.303,74.676 v1(148.669,74.31) ; R390.2@147.77,87.63 147.77,86.868 ; v1(159.146,80.533) U46.4@159.146,81.446 159.551,81.446 159.893,81.788 159.893,84.328 157.353,86.868 149.414,86.868 v1(148.771,86.225) 148.763,86.233 R392.1@147.77,86.233 147.77,86.868
JTAG_TMS: CN14.7 CN15.2 CN16.4 R57.1 R394.1 R407.1 R409.2 U46.1 | length 102.2
  Top Layer w0.127: R57.1@128.462,129.032 v1(132.334,129.032) ; v1@148.527,71.628 v1(148.669,71.77) 146.685,73.754 146.685,80.01 149.733,83.058 156.845,83.058 v1(157.846,84.059) ; CN16.4@150.436,71.77 CN16.4@150.444,71.762 ; CN15.2@150.53,83.693 CN15.2@150.538,83.685
  Top Layer w0.508: v1(148.669,71.77) CN16.4@150.436,71.77 ; v1(148.763,83.693) CN15.2@150.53,83.693 ; v1(157.846,84.059) 158.75,84.963 161.763,84.963 CN14.7@163.195,86.395
  Bottom Layer w0.127: v1(132.334,129.032) 131.826,128.524 131.826,127.127 143.891,115.062 143.891,86.487 146.05,84.328 147.574,84.328 147.77,84.132 R394.1@147.77,83.693 v1(148.763,83.693) 153.543,83.693 154.178,84.328 157.577,84.328 v1(157.846,84.059) U46.1@157.846,83.146 ; R409.2@147.77,70.612 R407.1@147.77,71.628 148.527,71.628 v1(148.669,71.77)
JTAG_TRGIN: CN14.17 R400.2 SB43.1 | length 5.9
  Bottom Layer w0.508: SB43.1@157.7,72.8 157.75,72.75 R400.2@159,72.75 160.055,72.75 161,73.695 CN14.17@163.195,73.695
JTAG_TRGOUT: CN14.19 R408.2 SB44.1 | length 5.5
  Bottom Layer w0.508: SB44.1@157.7,71.1 157.75,71.15 R408.2@159.1,71.15 159.105,71.155 CN14.19@163.195,71.155
JTAG_TRST: CN14.3 R252.1 R372.2 R377.1 U43.1 | length 68.7
  Bottom Layer w0.127: R252.1@140.97,140.016 140.97,138.33 142.35,136.95 142.35,135.25 142.9,134.7 145.2,134.7 147.447,132.453 147.447,100.584 151.892,96.139 159.512,96.139 160.978,94.673 160.978,91.556 161.036,91.498 ; R377.1@159.078,92.437 R372.2@159.078,93.453
  Bottom Layer w0.254: R377.1@159.078,92.437 159.136,92.379 U43.1@159.136,91.479 159.155,91.498 161.036,91.498 163.172,91.498 CN14.3@163.195,91.475
LCD_B0: CN23.22 R259.2 | length 146.7
  Top Layer w0.127: v1(82.25,24.825) CN23.22@82.25,27.738
  Bottom Layer w0.127: v1(82.25,24.825) 83.45,26.025 91.45,26.025 92.984,27.559 102.87,27.559 109.601,34.29 109.601,67.437 127.635,85.471 127.635,121.666 125.476,123.825 125.476,134.275 125.575,134.374 125.575,137.315 125.095,137.795 R259.2@124.656,137.795
LCD_B1: CN23.23 R264.2 | length 145.8
  Top Layer w0.127: v1(81.3,24.85) 81.75,25.3 CN23.23@81.75,27.738
  Bottom Layer w0.127: v1(81.3,24.85) 82.85,26.4 91.3,26.4 92.84,27.94 102.743,27.94 109.22,34.417 109.22,67.564 127.254,85.598 127.254,121.539 125.095,123.698 125.095,134.425 125.249,134.579 125.249,135.957 R264.2@124.681,136.525 R264.2@124.656,136.525
LCD_B2: CN23.24 R269.2 | length 144.4
  Top Layer w0.127: v1(80.5,25) 81.25,25.75 CN23.24@81.25,27.738
  Bottom Layer w0.127: v1(80.5,25) 82.25,26.75 91.075,26.75 92.637,28.312 102.607,28.312 108.839,34.544 108.839,67.691 126.873,85.725 126.873,121.412 124.656,123.629 R269.2@124.656,135.255
LCD_B3: CN23.25 R276.2 | length 137.7
  Top Layer w0.127: CN23.25@80.75,27.738 v1(80.75,30.5)
  Bottom Layer w0.127: v1(80.75,30.5) 86.775,30.5 89.725,33.45 102.157,33.45 104.648,35.941 104.648,69.088 122.682,87.122 122.682,111.843 121.285,113.24 121.285,116.967 116.078,122.174 116.078,133.858 115.951,133.985 R276.2@115.512,133.985
LCD_B4: CN23.26 R256.2 | length 150
  Top Layer w0.127: CN23.26@80.25,27.738 80.25,27 v1(80.5,26.75)
  Bottom Layer w0.127: v1(80.5,26.75) 81.6,27.85 88.975,27.85 91.1,29.975 102.746,29.975 107.696,34.925 107.696,68.072 125.73,86.106 125.73,119.888 123.825,121.793 121.793,121.793 119.38,124.206 119.38,137.414 117.729,139.065 R256.2@115.512,139.065
LCD_B5: CN23.27 R254.2 | length 152.9
  Top Layer w0.127: v1(79.75,24.5) CN23.27@79.75,27.738
  Bottom Layer w0.127: v1(79.75,24.5) 79.975,24.275 82.575,24.275 83.975,25.675 92.506,25.675 94.009,27.178 102.997,27.178 109.982,34.163 109.982,67.31 128.016,85.344 128.016,121.793 125.857,123.952 125.857,139.573 125.095,140.335 R254.2@124.656,140.335
LCD_B6: CN23.28 R249.2 | length 154.9
  Top Layer w0.127: v1(79.25,25.825) CN23.28@79.25,27.738
  Bottom Layer w0.127: v1(79.25,25.825) 79.325,25.9 80.4,25.9 82.013,27.513 89.163,27.513 91.3,29.65 102.929,29.65 108.077,34.798 108.077,67.945 126.111,85.979 126.111,120.05 123.987,122.174 121.92,122.174 119.761,124.333 119.761,138.239 116.395,141.605 R249.2@115.512,141.605
LCD_B7: CN23.29 R243.2 | length 158.5
  Top Layer w0.127: v1(78.75,24.975) CN23.29@78.75,27.738
  Bottom Layer w0.127: v1(78.75,24.975) 79.35,24.975 79.938,25.563 80.588,25.563 82.125,27.1 89.25,27.1 91.5,29.35 103.137,29.35 108.458,34.671 108.458,67.818 126.492,85.852 126.492,120.308 124.245,122.555 122.047,122.555 120.142,124.46 120.142,139.065 116.332,142.875 R243.2@115.512,142.875
LCD_BL_CTRL: CN23.39 R236.1 R258.2 | length 149.5
  Top Layer w0.127: v1(49.5,144.8) 49.5,138.6 v1(50.4,137.7) ; v1(71.4,26.85) 73.55,26.85 73.75,27.05 CN23.39@73.75,27.738
  Bottom Layer w0.127: v1(50.4,137.7) 50.4,136.73 50.63,136.5 R258.2@52.65,136.5 ; R236.1@52.636,145.415 50.115,145.415 v1(49.5,144.8) 47.879,143.179 47.879,118.491 46.225,116.837 46.225,113.55 45.593,112.918 45.593,98.425 43.434,96.266 43.434,79.121 71.247,51.308 71.247,38.878 71.625,38.5 71.625,27.075 v1(71.4,26.85)
LCD_CLK: C200.2 R226.2 R285.1 | length 159.1
  Top Layer w0.127: C200.2@93.458,24.927 94.131,25.6 95.6,25.6 v1(96.15,25.05)
  Top Layer w0.3: R285.1@92.258,24.927 C200.2@93.458,24.927
  Bottom Layer w0.127: v1(96.15,25.05) 96.45,24.75 102.093,24.75 111.125,33.782 111.125,66.929 129.159,84.963 129.159,122.174 127,124.333 127,149.352 126.492,149.86 116.02,149.86 R226.2@115.512,149.352
LCD_CLK_CN: C201.2 CN23.2 R285.2 | length 2.6
  Top Layer w0.3: CN23.2@92.25,27.738 92.25,26.335 R285.2@92.258,26.327 C201.2@93.458,26.327
LCD_DE: CN23.33 R248.2 | length 157.4
  Top Layer w0.127: CN23.33@76.75,27.738 76.75,25.675 v1(76.975,25.45)
  Bottom Layer w0.127: v1(76.975,25.45) 77.45,25.45 78.95,23.95 82.8,23.95 84.2,25.35 92.698,25.35 94.145,26.797 103.124,26.797 110.363,34.036 110.363,67.183 128.397,85.217 128.397,121.92 126.238,124.079 126.238,140.462 125.095,141.605 R248.2@124.656,141.605
LCD_G0: CN23.13 R315.2 | length 112.3
  Top Layer w0.127: CN23.13@86.75,27.738 v1(86.75,33.975)
  Bottom Layer w0.127: v1(86.75,33.975) 87.175,33.975 88.575,35.375 101.034,35.375 102.743,37.084 102.743,69.723 120.777,87.757 120.777,110.94 R315.2@115.512,116.205
LCD_G1: CN23.14 R306.2 | length 116.8
  Top Layer w0.127: CN23.14@86.25,27.738 v1(86.25,32.225)
  Bottom Layer w0.127: v1(86.25,32.225) 86.625,32.225 89.05,34.65 101.325,34.65 103.505,36.83 103.505,69.469 121.539,87.503 121.539,111.286 120.142,112.683 120.142,116.205 117.602,118.745 R306.2@115.512,118.745
LCD_G2: CN23.15 R310.2 | length 116.2
  Top Layer w0.127: CN23.15@85.75,27.738 v1(85.75,33.15)
  Bottom Layer w0.127: v1(85.75,33.15) 86.95,33.15 88.825,35.025 101.192,35.025 103.124,36.957 103.124,69.596 121.158,87.63 121.158,111.092 119.761,112.489 119.761,115.824 118.11,117.475 R310.2@115.512,117.475
LCD_G3: CN23.16 R312.2 | length 114.1
  Top Layer w0.127: CN23.16@85.25,27.738 v1(85.25,29.825)
  Bottom Layer w0.127: v1(85.25,29.825) 85.425,29.65 89.125,29.65 90.55,31.075 102.322,31.075 106.553,35.306 106.553,68.453 124.587,86.487 124.587,115.276 R312.2@123.952,115.911
LCD_G4: CN23.17 R302.2 | length 119.2
  Top Layer w0.127: CN23.17@84.75,27.738 v1(84.75,28.725)
  Bottom Layer w0.127: v1(84.75,28.725) 85.275,28.2 88.725,28.2 90.85,30.325 102.588,30.325 107.315,35.052 107.315,68.199 125.349,86.233 125.349,119.076 124.681,119.744 R302.2@124.681,119.89
LCD_G5: CN23.18 R305.2 | length 118.2
  Top Layer w0.127: CN23.18@84.25,27.738 v1(84.25,29.6)
  Bottom Layer w0.127: v1(84.25,29.6) 84.525,29.325 89.275,29.325 90.7,30.75 102.505,30.75 106.934,35.179 106.934,68.326 124.968,86.36 124.968,118.358 R305.2@124.681,118.645 ; R305.2@124.656,118.745 R305.2@124.719,118.682
LCD_G6: CN23.19 R299.2 | length 122.7
  Top Layer w0.127: CN23.19@83.75,27.738 v1(83.75,31.1)
  Bottom Layer w0.127: v1(83.75,31.1) 86.825,31.1 89.5,33.775 101.974,33.775 104.267,36.068 104.267,69.215 122.301,87.249 122.301,111.674 120.904,113.071 120.904,116.84 115.512,122.232 R299.2@115.512,122.555
LCD_G7: CN23.20 R303.2 | length 121.7
  Top Layer w0.127: CN23.20@83.25,27.738 v1(83.25,31.975)
  Bottom Layer w0.127: v1(83.25,31.975) 84.05,31.975 84.475,31.55 86.575,31.55 89.25,34.225 101.662,34.225 103.886,36.449 103.886,69.342 121.92,87.376 121.92,111.48 120.523,112.877 120.523,116.586 117.094,120.015 R303.2@115.512,120.015
LCD_HSYNC: CN23.31 R215.2 | length 181.1
  Top Layer w0.127: v1(77.75,24.15) 77.975,24.375 77.975,25.825 77.75,26.05 CN23.31@77.75,27.738
  Bottom Layer w0.127: v1(77.75,24.15) 78.275,23.625 83.1,23.625 84.475,25 89.975,25 90.875,24.1 102.459,24.1 111.887,33.528 111.887,66.675 129.921,84.709 129.921,122.428 127.762,124.587 127.762,149.733 126.495,151 121.288,151 119.888,152.4 116.02,152.4 R215.2@115.512,151.892
LCD_R0: CN23.4 R290.2 | length 135.2
  Top Layer w0.127: CN23.4@91.25,27.738 91.25,36.65 v1(91.25,37.25)
  Signal Layer 2 w0.127: v1(69.475,37.25) v1(91.25,37.25)
  Bottom Layer w0.127: R290.2@43.492,127.762 43.053,127.762 42.225,126.934 42.225,99.756 41.402,98.933 41.402,97.917 40.64,97.155 40.64,79.883 69.469,51.054 69.469,37.256 v1(69.475,37.25)
LCD_R1: CN23.5 R293.2 | length 132.9
  Top Layer w0.127: CN23.5@90.75,27.738 90.75,37.4 v1(90.75,37.925)
  Signal Layer 2 w0.127: v1(70.075,37.85) 70.35,37.575 90.4,37.575 v1(90.75,37.925)
  Bottom Layer w0.127: R293.2@43.492,126.365 43.18,126.365 42.575,125.76 42.575,99.598 41.783,98.806 41.783,97.79 41.021,97.028 41.021,80.01 69.85,51.181 69.85,38.075 v1(70.075,37.85)
LCD_R2: CN23.6 R270.2 | length 131.3
  Top Layer w0.127: CN23.6@90.25,27.738 v1(90.25,32.7)
  Bottom Layer w0.127: v1(90.25,32.7) 90.65,33.1 102.315,33.1 105.029,35.814 105.029,68.961 123.063,86.995 123.063,112.037 121.666,113.434 121.666,117.094 116.459,122.301 116.459,134.747 115.951,135.255 R270.2@115.512,135.255
LCD_R3: CN23.7 R260.2 | length 135.2
  Top Layer w0.127: CN23.7@89.75,27.738 v1(89.75,31.475)
  Bottom Layer w0.127: v1(89.75,31.475) 90.05,31.775 102.006,31.775 105.791,35.56 105.791,68.707 123.825,86.741 123.825,112.35 122.428,113.747 122.428,117.475 117.221,122.682 117.221,137.033 116.459,137.795 R260.2@115.512,137.795
LCD_R4: CN23.8 R291.2 | length 132.6
  Top Layer w0.127: CN23.8@89.25,27.738 89.25,38.2 v1(89.25,38.8)
  Signal Layer 2 w0.127: v1(74.925,38.6) 75,38.525 87.5,38.525 87.775,38.8 v1(89.25,38.8)
  Bottom Layer w0.127: R291.2@56.33,127.635 56.33,120.973 56.007,120.65 51.816,120.65 50.927,119.761 50.927,115.062 48.768,112.903 48.768,110.871 49.657,109.982 49.657,105.156 50.927,103.886 50.927,91.567 49.022,89.662 49.022,77.978 74.93,52.07 74.93,38.605 v1(74.925,38.6)
LCD_R5: CN23.9 R265.2 | length 134
  Top Layer w0.127: CN23.9@88.75,27.738 v1(88.75,31.55)
  Bottom Layer w0.127: v1(88.75,31.55) 89.35,32.15 92,32.15 92.625,32.775 102.498,32.775 105.41,35.687 105.41,68.834 123.444,86.868 123.444,112.181 122.047,113.578 122.047,117.348 116.84,122.555 116.84,135.636 115.951,136.525 R265.2@115.512,136.525
LCD_R6: CN23.10 R313.2 | length 118.8
  Top Layer w0.127: CN23.10@88.25,27.738 88.25,37.725 v1(88.25,38.15)
  Signal Layer 2 w0.127: v1(70.925,38.075) 88.175,38.075 v1(88.25,38.15)
  Bottom Layer w0.127: R313.2@44.45,115.628 43.561,114.739 43.561,99.06 41.402,96.901 41.402,80.137 70.231,51.308 70.231,38.769 v1(70.925,38.075)
LCD_R7: CN23.11 R317.2 | length 109.1
  Top Layer w0.127: CN23.11@87.75,27.738 v1(87.75,30.175)
  Bottom Layer w0.127: v1(87.75,30.175) 89.15,30.175 90.375,31.4 102.139,31.4 106.172,35.433 106.172,68.58 124.206,86.614 124.206,112.544 123.952,112.798 R317.2@123.952,113.908
LCD_RESET: R126.1 R240.1 | length 138.4
  Top Layer w0.127: v1(72,26.1) 72.025,26.125 R126.1@74.675,26.125
  Bottom Layer w0.127: 44.976,97.3 43.815,96.14 43.815,79.248 71.628,51.435 71.628,38.997 72,38.625 v1(72,26.1) ; 44.976,97.3 45.974,98.298 45.974,112.774 46.525,113.325 46.525,116.756 48.133,118.364 48.133,142.494 50.546,144.907 51.874,144.907 R240.1@52.636,144.145
LCD_RESET_CN: CN23.34 R125.2 R126.2 | length 3.1
  Top Layer w0.3: R125.2@76.075,24.725 R126.2@76.075,26.125 76.25,26.3 CN23.34@76.25,27.738
LCD_VSYNC: CN23.32 R214.2 | length 173.5
  Top Layer w0.127: v1(77.25,23.55) 77.25,24.575 77.523,24.848 77.523,25.802 77.25,26.075 CN23.32@77.25,27.738
  Bottom Layer w0.127: v1(77.25,23.55) 77.45,23.35 83.25,23.35 84.625,24.725 89.625,24.725 90.55,23.8 102.667,23.8 112.395,33.528 112.395,66.675 130.302,84.582 130.302,122.555 128.143,124.714 128.143,149.86 126.238,151.765 R214.2@124.656,151.765
LED_STLK: R190.2 R192.2 U21.D15 | length 48.7
  Top Layer w0.127: R190.2@7.477,12.078 22.153,12.078 25.696,15.621 30.734,15.621 31.623,16.51 31.623,33.103 32.175,33.655 U21.D15@32.175,37.375
  Top Layer w0.254: R192.2@7.477,10.478 R190.2@7.477,12.078
LRCLK_C: R137.1 R403.1 U48.1 | length 2.7
  Top Layer w0.254: v1(130.302,72.136) R137.1@130.302,72.702
  Bottom Layer w0.254: R403.1@130.302,72.702 v1(130.302,72.136) 130.302,71.755 130.838,71.219 U48.1@130.838,70.751
MCLK_C: R139.1 R411.1 U48.30 | length 3.5
  Top Layer w0.254: R139.1@127.704,69.85 v1(128.397,69.85)
  Bottom Layer w0.254: R411.1@127.704,69.85 v1(128.397,69.85) 129.171,69.076 U48.30@130.163,69.076
MCO1: R39.1 R308.1 | length 50
  Top Layer w0.127: v6(12.954,132.969) R39.1@12.954,134.424
  Signal Layer 2 w0.127: v6(12.954,132.969) 13.97,131.953 13.97,120.33 16.95,117.35 19.614,117.35 23.263,113.7 37.1,113.7 39.351,115.951 v4@43.688,115.951
  Bottom Layer w0.127: v4@43.688,115.951 43.575,116.064 43.575,116.981 44,117.406 R308.1@44.45,117.406
  other v4: 43.563,115.951
MFX_GPO4: SB32.2 U25.3 | length 11.8
  Top Layer w0.127: U25.3@122.71,31.183 122.71,30.69 123.731,29.669 125.014,29.669 125.17,29.513 125.17,27.02 124.725,26.575 124.725,23.85 125.525,23.05 SB32.2@126.925,23.05
MFX_GPO5: SB31.2 U25.5 | length 9.4
  Top Layer w0.127: U25.5@123.71,31.183 123.71,30.69 124.504,29.896 125.218,29.896 125.397,29.718 125.397,26.775 125.05,26.428 125.05,25.175 125.675,24.55 SB31.2@126.925,24.55
MFX_GPO6: R177.2 SB33.1 U25.6 | length 123.5
  Top Layer w0.127: R177.2@16.579,19.558 22.558,19.558 v1(22.575,19.575) ; U25.6@124.21,31.183 124.21,30.702 124.789,30.123 125.402,30.123 125.624,29.901 125.624,26.477 125.625,26.475 v1(125.625,26.05) SB33.1@127.025,26.05
  Signal Layer 2 w0.127: v1(22.575,19.575) 25.475,16.675 34.175,16.675 36.975,19.475 39.85,19.475 43.025,22.65 69.05,22.65 71.35,20.35 109.175,20.35 114.875,26.05 v1(120.65,26.05)
  Bottom Layer w0.127: v1(120.65,26.05) v1(125.625,26.05)
MFX_GPO7: SB30.1 U25.38 | length 11.7
  Top Layer w0.127: U25.38@120.21,37.683 121.242,37.683 121.725,37.2 125.75,37.2 127.925,39.375 127.925,40.25 127.008,41.167 SB30.1@127.008,41.91
MFX_I2C_ADDR: R166.2 R167.1 U25.45 | length 3.5
  Top Layer w0.127: R167.1@117.798,32.893 R166.2@117.798,33.909 118.072,34.183 U25.45@120.21,34.183
MFX_I2C_SCL: R161.2 U25.42 | length 2.9
  Top Layer w0.127: R161.2@117.798,36.957 118.237,36.957 119.511,35.683 U25.42@120.21,35.683
MFX_I2C_SDA: R162.2 U25.43 | length 2.7
  Top Layer w0.127: R162.2@117.798,35.941 118.237,35.941 118.995,35.183 U25.43@120.21,35.183
MFX_IO0: SB34.2 U25.18 | length 3.3
  Top Layer w0.127: U25.18@128.71,35.183 132.017,35.183 SB34.2@132.025,35.175
MFX_IO1: U24.13 U25.19 | length 112.4
  Top Layer w0.127: v1(39.2,20.5) U24.13@40.4,20.5 ; v6(127.5,35.3) 127.883,35.683 U25.19@128.71,35.683
  Signal Layer 2 w0.127: v1(39.2,20.5) 43.4,24.7 68.6,24.7 72.2,21.1 108.72,21.1 118.1,30.48 118.1,33.783 120.8,36.483 120.8,38.2 124.15,41.55 127.05,41.55 127.4,41.2 127.4,40.3 126.3,39.2 126.3,36.5 v6(127.5,35.3)
MFX_IO2: U24.40 U25.20 | length 92.9
  Top Layer w0.127: v6(61,27.4) 62.1,28.5 U24.40@65.4,28.5 ; v6(127.4,36.5) 127.717,36.183 U25.20@128.71,36.183
  Signal Layer 2 w0.127: v6(61,27.4) 63.2,25.2 69,25.2 72.737,21.463 108.563,21.463 117.7,30.6 117.7,33.9 120.4,36.6 120.4,38.4 123.95,41.95 127.325,41.95 127.9,41.375 127.9,40.1 126.8,39 126.8,37.1 v6(127.4,36.5)
MFX_IO3: R414.2 U25.39 U48.25 | length 41.2
  Top Layer w0.127: v1(119.126,36.957) 119.352,37.183 U25.39@120.21,37.183
  Bottom Layer w0.127: v1(119.126,36.957) 119.253,37.084 119.253,64.008 122.428,67.183 128.016,67.183 128.212,66.987 R414.2@128.212,66.548 128.466,66.294 129.54,66.294 129.822,66.576 U48.25@130.163,66.576
MFX_IO4: CN2.15 R217.1 U25.40 | length 160.9
  Top Layer w0.127: U25.40@120.21,36.683 125.683,36.683 128.425,39.425 v4(133.041,39.425)
  Top Layer w0.508: v1(159.513,149.685) CN2.15@161.28,149.685
  Signal Layer 2 w0.127: v4(133.041,39.425) 133.041,42.363 148.59,57.912 148.59,68.961 151.511,71.882 151.511,72.517 155.702,76.708 155.702,95.567 167.132,106.998 167.132,138.6 168,139.468 168,147.976 165.798,150.177 160.006,150.177 v1(159.513,149.685)
  Bottom Layer w0.127: R217.1@147.516,150.876 156.528,150.876 157.719,149.685 v1(159.513,149.685)
MFX_IO5: CN2.17 U25.15 | length 142.3
  Top Layer w0.127: U25.15@128.71,33.683 129.512,33.683 v4(130.175,33.02)
  Top Layer w0.508: v1(159.513,148.685) CN2.17@161.28,148.685
  Signal Layer 2 w0.127: v4(130.175,33.02) 131.064,33.909 131.064,40.894 148.209,58.039 148.209,69.088 151.13,72.009 151.13,72.898 155.194,76.962 155.194,95.758 166.688,107.251 166.688,138.7 167.5,139.512 167.5,147.523 165.862,149.161 159.99,149.161 v1(159.513,148.685)
MFX_IO6: CN2.19 U25.16 | length 139.5
  Top Layer w0.127: U25.16@128.71,34.183 v4@130.155,34.183
  Top Layer w0.508: v1(159.513,147.685) CN2.19@161.28,147.685
  Signal Layer 2 w0.127: v4(130.175,34.163) 130.556,34.544 130.556,40.894 147.828,58.166 147.828,69.342 150.749,72.263 150.749,73.279 154.686,77.216 154.686,95.948 166.243,107.505 166.243,139 167,139.757 167,147.008 165.798,148.209 160.037,148.209 v1(159.513,147.685)
MFX_IO7: R188.1 U25.17 U29.4 | length 31.1
  Top Layer w0.127: U25.17@128.71,34.683 129.413,34.683 129.528,34.798 130.302,34.798 130.9,34.2 133.95,34.2 134.675,33.475 134.675,22.17 138.303,18.542 138.303,13.335 138.557,13.081 R188.1@139.25,13.081 139.25,12.642 139.87,12.022 U29.4@139.87,11.491
MFX_IO8: SB29.2 U25.29 | length 2.3
  Top Layer w0.254: SB29.2@125.06,41.91 125.21,41.76 U25.29@125.21,39.683
MFX_IO9: R175.1 U25.30 U28.8 | length 41.9
  Top Layer w0.127: v4(124.46,40.767) 124.71,40.517 U25.30@124.71,39.683 ; v4(140.081,40.767) 140.081,40.259 149.225,31.115 149.225,23.368 149.029,23.172 R175.1@148.59,23.172 148.463,23.045 U28.8@148.463,21.171
  Bottom Layer w0.127: v4(124.46,40.767) 125.127,40.1 134.225,40.1 134.875,39.45 138.764,39.45 v4(140.081,40.767)
MFX_IO10: U24.15 U25.31 | length 106.9
  Top Layer w0.127: v1(39.2,18.5) U24.15@40.4,18.5 ; U25.31@124.21,39.683 124.21,39.112 v4(124.714,38.608)
  Signal Layer 2 w0.127: v1(39.2,18.5) 41.063,16.637 118.11,16.637 122.936,21.463 122.936,36.322 124.714,38.1 v4(124.714,38.608)
MFX_IO11: R179.2 U25.32 | length 54.6
  Top Layer w0.127: v1(123.571,38.608) 123.71,38.747 U25.32@123.71,39.683
  Top Layer w0.254: R179.2@89.154,17.468 v1(89.154,18.288)
  Signal Layer 2 w0.127: v1(89.154,18.288) 90.043,17.399 117.856,17.399 122.174,21.717 122.174,36.576 123.571,37.973 v1(123.571,38.608)
MFX_IO12: R180.2 U25.33 | length 50
  Top Layer w0.127: v4(122.682,38.227) 122.682,38.481 123.21,39.009 U25.33@123.21,39.683
  Top Layer w0.254: R180.2@92.964,17.468 v1(92.964,18.288)
  Signal Layer 2 w0.127: v1(92.964,18.288) 93.472,17.78 117.729,17.78 121.793,21.844 121.793,36.83 122.682,37.719 v4(122.682,38.227)
MFX_IO13: R181.2 U25.26 | length 50.5
  Top Layer w0.127: v4(126.619,40.767) 126.71,40.676 U25.26@126.71,39.683
  Top Layer w0.254: R181.2@96.774,17.468 v1(96.774,18.288)
  Signal Layer 2 w0.127: v1(96.774,18.288) 117.729,18.288 121.412,21.971 121.412,38.062 123.482,40.132 125.984,40.132 v4(126.619,40.767)
MFX_IO14: U24.39 U25.27 | length 76.1
  Top Layer w0.127: U24.39@65.4,27.5 v1(66.45,27.5) ; v1(117.856,38.1) 118.364,38.608 121.031,38.608 121.92,37.719 125.702,37.719 126.21,38.227 U25.27@126.21,39.683
  Bottom Layer w0.127: v1(66.45,27.5) 66.45,26.25 70.856,21.844 107.188,21.844 117.65,32.306 117.65,37.894 v1(117.856,38.1)
MFX_IO15: SB46.2 U25.28 | length 101.6
  Top Layer w0.127: U25.28@125.71,39.683 125.71,38.628 v1(125.73,38.608)
  Signal Layer 2 w0.127: v1(46.101,19.304) 67.31,19.304 69.596,17.018 117.983,17.018 122.555,21.59 122.555,36.449 124.079,37.973 124.079,38.735 124.587,39.243 125.095,39.243 v1(125.73,38.608)
  Bottom Layer w0.127: SB46.2@44.796,19.304 v1(46.101,19.304)
MFX_IRQOUT: R168.2 U25.46 | length 3.8
  Top Layer w0.127: R168.2@118.048,31.623 118.364,31.939 118.364,33.274 118.773,33.683 U25.46@120.21,33.683
MFX_LOOP: TP23.1 U25.14 | length 4.1
  Top Layer w0.127: U25.14@128.71,33.183 129.377,33.183 129.54,33.02 129.54,32.86 129.9,32.5 131.525,32.5 TP23.1@132.175,33.15
MFX_NRST: C78.2 D3.1 R173.1 U25.7 | length 83.9
  Top Layer w0.127: D3.1@76.762,9.652 v1(77.724,9.652) ; U25.7@124.71,31.183 124.71,30.645 125.005,30.35 125.725,30.35 126.042,30.033 C78.2@126.042,28.956 R173.1@126.042,27.686 126.042,27.233 126.275,27 130.175,27 131.318,25.857 v4(131.318,9.271)
  Signal Layer 2 w0.127: v1(77.724,9.652) 80.264,7.112 129.159,7.112 v4(131.318,9.271)
MFX_SWCLK: CN26.2 U25.37 | length 37.9
  Top Layer w0.127: v1(118.618,27.94) 117.856,27.94 114.173,31.623 114.173,35.814 115.951,37.592 118.618,37.592 119.209,38.183 U25.37@120.21,38.183
  Bottom Layer w0.127: CN26.2@106.68,12.7 106.68,16.891 117.729,27.94 v1(118.618,27.94)
MFX_SWDIO: CN26.4 U25.34 | length 39.4
  Top Layer w0.127: v1(117.983,27.305) 113.792,31.496 113.792,37.042 115.739,38.989 121.412,38.989 121.666,38.735 122.428,38.735 122.71,39.017 U25.34@122.71,39.683
  Bottom Layer w0.127: CN26.4@111.76,12.7 111.76,21.336 117.729,27.305 v1(117.983,27.305)
MFX_WKUP: R170.1 R171.2 U25.2 | length 3.6
  Top Layer w0.127: U25.2@122.21,31.183 122.21,30.008 122.116,29.914 R171.2@122.116,28.956 R170.1@123.252,28.956 R170.1@123.365,29.069
MICIN: C164.1 CN18.2 R415.1 R420.2 U18.1 | length 48.9
  Top Layer w0.254: v4(136.271,60.198) 146.438,60.198 147.574,61.334 U18.1@149.164,61.334
  Top Layer w0.5: U18.1@149.164,61.334 149.164,58.039 152.974,54.229 167.386,54.229 167.755,54.598 CN18.2@167.755,62.945 CN18.2@167.767,62.933
  Bottom Layer w0.254: C164.1@135.382,62.8 135.382,60.26 R420.2@135.32,60.198 v4(136.271,60.198)
MOTOR_ADC1_INP6: C17.2 CN1.14 R7.2 R72.1 | length 93.6
  Top Layer w0.127: v6(52.328,109.855) R72.1@52.894,109.855 ; v1(98.552,160.02) 99.002,160.47 C17.2@99.314,160.47 ; CN1.14@99.314,165.1 C17.2@99.314,160.47 ; R7.2@100.584,160.466 99.318,160.466 C17.2@99.314,160.47
  Bottom Layer w0.127: v6(52.328,109.855) 52.328,111.256 54.737,113.665 57.023,113.665 59.563,116.205 59.563,136.906 62.484,139.827 62.484,150.495 68.989,157 81.054,157 83.312,159.258 97.79,159.258 v1(98.552,160.02)
MOTOR_ADC2_INP1: C12.2 CN1.26 R219.1 | length 38.2
  Top Layer w0.127: C12.2@84.074,160.47 v1(84.074,161.417) CN1.26@84.074,165.1
  Bottom Layer w0.127: R219.1@56.58,150.495 56.58,152.98 64.255,160.655 76.835,160.655 77.724,161.544 83.947,161.544 v1(84.074,161.417)
MOTOR_ADC12_INP4: C13.2 CN1.24 R277.1 | length 67.3
  Top Layer w0.127: C13.2@86.614,160.47 v1@86.614,162.052 ; v1(86.614,162.179) CN1.24@86.614,165.1
  Bottom Layer w0.127: R277.1@46.228,133.542 46.228,151.257 48.641,153.67 55.27,153.67 64.033,162.433 86.36,162.433 v1(86.614,162.179)
MOTOR_ADC12_INP7: C14.2 CN1.19 R67.1 | length 79
  Top Layer w0.127: v1(60.071,117.348) 60.071,115.429 60.946,114.554 R67.1@62.292,114.554 ; v1(89.408,158.75) 89.408,160.147 89.731,160.47 C14.2@90.424,160.47 90.424,166.37 CN1.19@91.694,167.64
  Bottom Layer w0.127: v1(60.071,117.348) 59.944,117.475 59.944,136.779 62.865,139.7 62.865,150.368 69.097,156.6 81.162,156.6 82.677,158.115 88.773,158.115 v1(89.408,158.75)
MOTOR_ADC12_INP8: C8.2 CN1.32 R282.1 | length 59.8
  Top Layer w0.127: C8.2@76.454,160.47 v1(76.454,161.925) CN1.32@76.454,165.1
  Bottom Layer w0.127: R282.1@46.228,130.875 46.928,130.875 47.117,131.064 47.117,151.511 48.895,153.289 55.389,153.289 64.152,162.052 76.327,162.052 v1(76.454,161.925)
MOTOR_ADC12_INP10: C16.2 CN1.15 R253.1 | length 61.7
  Top Layer w0.127: C16.2@95.504,160.47 v1(95.504,161.036) 95.504,166.37 CN1.15@96.774,167.64
  Bottom Layer w0.127: R253.1@56.58,140.335 57.023,140.335 58.293,141.605 58.293,152.654 64.262,158.623 68.326,158.623 68.961,159.258 81.28,159.258 82.804,160.782 95.25,160.782 v1(95.504,161.036)
MOTOR_ADC12_INP11: C15.2 CN1.17 R210.1 | length 60.1
  Top Layer w0.127: C15.2@92.964,160.47 v1(92.964,162.179) 92.964,166.37 CN1.17@94.234,167.64
  Bottom Layer w0.127: R210.1@44.896,152.908 47.244,152.908 48.387,154.051 55.118,154.051 63.881,162.814 92.329,162.814 v1(92.964,162.179)
MOTOR_DFSDM1_2_CKIN1: CN4.14 R314.1 | length 65.3
  Top Layer w0.127: CN4.14@57.15,166.37 57.914,167.134 61.593,167.134 68.58,160.147 68.58,157.861 v4(67.945,157.226)
  Bottom Layer w0.127: R314.1@56.58,116.205 57.023,116.205 58.039,117.221 58.039,137.414 60.96,140.335 60.96,152.781 64.643,156.464 66.04,156.464 66.802,157.226 v4(67.945,157.226)
MOTOR_DFSDM1_CKIN0: CN4.17 R246.1 | length 34.8
  Top Layer w0.127: CN4.17@59.69,165.1 60.706,164.084 64.008,164.084 67.31,160.782 v1(67.31,159.131)
  Bottom Layer w0.127: R246.1@56.58,141.986 57.277,141.986 57.912,142.621 57.912,152.781 64.262,159.131 v1(67.31,159.131)
MOTOR_DFSDM1_CKIN2: CN4.18 R50.1 | length 51.4
  Top Layer w0.127: R50.1@42.988,131.572 42.214,132.346 42.214,143.179 43.942,144.907 43.942,158.115 46.55,160.723 46.55,166.311 48.26,168.021 v1(53.086,168.021)
  Signal Layer 2 w0.127: v1(53.086,168.021) 58.039,168.021 CN4.18@59.69,166.37
MOTOR_DFSDM1_CKIN3: CN4.13 R123.1 | length 90.5
  Top Layer w0.127: v6(52.328,90.805) R123.1@52.894,90.805 ; CN4.13@57.15,165.1 58.928,163.322 63.5,163.322 66.421,160.401 66.421,157.861 64.897,156.337 v1(64.897,155.956)
  Bottom Layer w0.127: v6(52.328,90.805) 52.07,91.063 52.07,104.648 51,105.718 51,111.706 53.086,113.792 53.086,114.935 53.594,115.443 57.023,115.443 58.42,116.84 58.42,137.287 61.341,140.208 61.341,152.654 64.643,155.956 v1(64.897,155.956)
MOTOR_DFSDM1_CKIN4: CN4.11 R284.1 | length 46.7
  Top Layer w0.127: CN4.11@55.88,165.1 58.039,162.941 63.246,162.941 65.913,160.274 v4(65.913,158.115)
  Bottom Layer w0.127: R284.1@56.58,130.175 56.896,130.491 56.896,137.795 59.817,140.716 59.817,153.162 64.262,157.607 65.405,157.607 v4(65.913,158.115)
MOTOR_DFSDM1_CKIN5: CN4.16 R238.1 | length 71.6
  Bottom Layer w0.127: CN4.16@58.42,166.37 59.184,167.134 61.339,167.134 65.278,163.195 106.426,163.195 110.5,159.121 110.5,144.897 111.252,144.145 R238.1@111.822,144.145
MOTOR_DFSDM1_CKIN7: CN4.12 R120.1 | length 72.9
  Bottom Layer w0.127: CN4.12@55.88,166.37 57.023,167.513 61.468,167.513 65.405,163.576 106.553,163.576 110.9,159.229 110.9,146.1 R120.1@111.5,145.5
MOTOR_DFSDM1_DATIN0: CN4.9 R209.1 | length 16.1
  Bottom Layer w0.127: R209.1@44.896,154.178 44.896,155.386 45.8,156.29 45.8,158.2 51.9,164.3 53.81,164.3 CN4.9@54.61,165.1
MOTOR_DFSDM1_DATIN2: CN4.10 R55.1 | length 50.4
  Top Layer w0.127: R55.1@42.988,130.175 42.017,130.175 41.574,130.618 41.574,131.591 41.783,131.8 41.783,143.383 43.561,145.161 43.561,158.369 46.1,160.908 46.1,166.496 48.26,168.656 53.594,168.656 54.61,167.64 CN4.10@54.61,166.37
MOTOR_DFSDM1_DATIN4: CN4.15 R95.1 | length 75.2
  Top Layer w0.127: v6(52.578,104.775) R95.1@53.144,104.775 ; CN4.15@58.42,165.1 59.817,163.703 63.627,163.703 66.802,160.528 66.802,157.734 65.913,156.845 v4(65.913,155.956)
  Bottom Layer w0.127: v6(52.578,104.775) 51.4,105.953 51.4,111.471 54.356,114.427 56.515,114.427 58.801,116.713 58.801,137.16 61.722,140.081 61.722,152.527 64.643,155.448 65.405,155.448 v4(65.913,155.956)
MOTOR_GPIO1: CN1.21 SB33.2 | length 206.5
  Top Layer w0.127: v1(116.459,48.895) 124.714,48.895 136.4,37.209 136.4,26.125 v1(136.35,26.125) ; SB33.2@128.125,26.05 v1(129.475,26.05)
  Bottom Layer w0.127: CN1.21@89.154,167.64 90.932,169.418 116.332,169.418 120.523,165.227 120.523,159.131 130.302,149.352 130.302,147.447 129.921,147.066 129.921,140.716 130.683,139.954 130.683,138.557 130.302,138.176 130.302,125.476 132.461,123.317 132.461,83.693 116.586,67.818 116.586,49.022 v1(116.459,48.895) ; v1(129.475,26.05) 136.275,26.05 v1(136.35,26.125)
MOTOR_GPIO2: CN1.23 SB30.2 | length 183.1
  Top Layer w0.127: v1(116.459,48.006) 116.967,48.514 124.46,48.514 128.108,44.866 SB30.2@128.108,41.91
  Bottom Layer w0.127: CN1.23@86.614,167.64 88.773,169.799 116.459,169.799 120.904,165.354 120.904,159.385 130.683,149.606 130.683,147.32 130.302,146.939 130.302,140.843 131.064,140.081 131.064,138.43 130.683,138.049 130.683,125.603 132.842,123.444 132.842,83.566 116.967,67.691 116.967,48.514 v1(116.459,48.006)
MOTOR_TIM1_BKIN: C18.2 CN1.1 R9.1 R349.1 | length 35.4
  Top Layer w0.127: v1(113,157.7) 112.3,158.4 112.3,160.07 112.7,160.47 C18.2@113.284,160.47 ; R9.1@114.3,160.47 C18.2@113.284,160.47 ; CN1.1@114.554,167.64 113.284,166.37 C18.2@113.284,160.47
  Bottom Layer w0.127: v1(113,157.7) 112.5,157.2 112.5,149 112.8,148.7 119.3,148.7 120.7,147.3 123.3,147.3 124.65,145.95 R349.1@124.65,145.4
MOTOR_TIM1_CH1: CN1.3 R301.1 | length 105.7
  Top Layer w0.127: v1(107.823,161.036) 110.744,163.957 110.744,166.37 CN1.3@112.014,167.64
  Bottom Layer w0.127: R301.1@46.482,120.08 47.309,120.08 47.371,120.142 47.371,151.13 49.149,152.908 55.508,152.908 64.271,161.671 75.692,161.671 75.946,161.417 76.962,161.417 77.47,161.925 85.852,161.925 86.106,161.671 107.188,161.671 v1(107.823,161.036)
MOTOR_TIM1_CH1N: CN1.5 R81.1 | length 106.1
  Top Layer w0.127: v1(52.324,107.315) R81.1@52.894,107.315 ; v10(106.426,161.036) 108.204,162.814 108.204,166.37 CN1.5@109.474,167.64
  Bottom Layer w0.127: v1(52.324,107.315) 51.816,107.823 51.816,111.316 54.546,114.046 56.706,114.046 59.182,116.522 59.182,137.033 62.103,139.954 62.103,150.622 68.881,157.4 80.946,157.4 83.185,159.639 97.409,159.639 98.298,160.528 105.918,160.528 v10(106.426,161.036)
MOTOR_TIM1_CH2: CN1.7 R294.1 | length 53.1
  Bottom Layer w0.127: CN1.7@106.934,167.64 108.204,166.37 108.204,163.195 111.7,159.699 111.7,148.523 112.823,147.4 119.3,147.4 121.158,145.542 121.158,125.142 121.524,124.776 R294.1@121.92,124.776
MOTOR_TIM1_CH2N: CN1.9 R304.1 | length 89.4
  Top Layer w0.127: v1(103.124,161.036) 103.124,166.37 CN1.9@104.394,167.64
  Bottom Layer w0.127: R304.1@56.58,118.745 57.023,118.745 57.277,118.999 57.277,137.668 60.198,140.589 60.198,153.035 64.389,157.226 65.786,157.226 66.76,158.2 80.73,158.2 82.931,160.401 95.631,160.401 96.266,161.036 v1(103.124,161.036)
MOTOR_TIM1_CH3: CN1.11 R288.1 | length 57.4
  Bottom Layer w0.127: CN1.11@101.854,167.64 103.251,169.037 109.855,169.037 110.744,168.148 110.744,161.29 112.1,159.934 112.1,148.8 112.437,148.463 118.837,148.463 121.92,145.38 R288.1@121.92,128.97
MOTOR_TIM1_CH3N: CN1.13 R309.1 | length 84.8
  Top Layer w0.127: v1(96.774,160.528) 98.044,161.798 98.044,166.37 CN1.13@99.314,167.64
  Bottom Layer w0.127: R309.1@56.58,117.475 56.896,117.475 57.658,118.237 57.658,137.541 60.579,140.462 60.579,152.908 64.516,156.845 65.913,156.845 66.868,157.8 80.838,157.8 83.058,160.02 96.266,160.02 v1(96.774,160.528)
MOTOR_TIM2_CH1: C7.2 CN1.31 R213.1 SB2.1 | length 37.3
  Top Layer w0.127: SB2.1@75.184,157.472 75.43,157.472 75.819,157.861 75.819,160.274 75.623,160.47 C7.2@75.184,160.47 v1(75.184,161.163) 75.184,166.37 CN1.31@76.454,167.64
  Bottom Layer w0.127: R213.1@53.34,151.83 54.93,151.83 64.263,161.163 v1(75.184,161.163)
MOTOR_TIM2_CH2: C5.2 CN1.33 R235.1 | length 34.2
  Top Layer w0.127: v4(71.374,160.147) 71.697,160.47 C5.2@72.39,160.47 72.39,166.116 CN1.33@73.914,167.64
  Bottom Layer w0.127: R235.1@56.58,145.415 56.896,145.415 57.15,145.669 57.15,153.035 64.262,160.147 v4(71.374,160.147)
MOTOR_TIM2_CH3: C6.2 CN1.34 R239.1 | length 33.6
  Top Layer w0.127: v1(73.279,160.147) 73.602,160.47 C6.2@73.914,160.47 CN1.34@73.914,165.1
  Bottom Layer w0.127: R239.1@56.58,144.145 57.15,144.145 57.531,144.526 57.531,152.908 64.262,159.639 72.771,159.639 v1(73.279,160.147)
MOTOR_TIM15_BKIN: C10.2 CN1.30 R8.1 R278.1 | length 63.7
  Top Layer w0.127: CN1.30@78.994,165.1 C10.2@78.994,160.47 R8.1@80.01,160.47 80.576,160.47 80.899,160.147 v1(80.9,156.1)
  Bottom Layer w0.127: v1(80.9,156.1) 81.2,156.1 82.834,157.734 105.866,157.734 110.1,153.5 110.1,144.662 111.447,143.315 R278.1@111.447,132.715
MOTOR_TIM15_CH1: C11.2 CN1.27 R323.1 | length 85.2
  Top Layer w0.127: CN1.27@81.534,167.64 82.804,166.37 C11.2@82.804,160.528 ; v1(82.8,156.1) 82.169,156.731 82.169,160.274 82.365,160.47 C11.2@82.804,160.47
  Bottom Layer w0.127: v1(82.8,156.1) 83.672,156.972 105.537,156.972 109.347,153.162 109.347,124.587 112.522,121.412 112.522,114.3 114.808,112.014 114.808,111.508 R323.1@114.8,111.5
MOTOR_TIM15_CH2: C9.2 CN1.29 R330.1 | length 94
  Top Layer w0.127: v1(78.359,156.1) 78.359,160.274 78.163,160.47 C9.2@77.724,160.47 77.724,166.37 CN1.29@78.994,167.64
  Bottom Layer w0.102: R330.1@115.508,108.585 R330.1@115.762,108.585
  Bottom Layer w0.127: v1(78.359,156.1) 78.859,155.6 81.2,155.6 82.953,157.353 105.664,157.353 109.728,153.289 109.728,124.714 112.903,121.539 112.903,114.554 115.762,111.695 R330.1@115.762,108.585
NetC2_2: C2.2 R2.1 SB1.1 U1.2 U1.4 | length 15.3
  Top Layer w0.508: R2.1@121.92,166.686 122.871,166.686 123.317,167.132 U1.2@124.333,167.132 U1.4@130.683,167.132 130.683,162.363 ; C2.2@129.732,162.306 131.326,162.306
NetC19_2: C19.2 C89.2 U37.2 U37.3 U37.9 | length 10.6
  Top Layer w0.254: v1(39.243,161.798) 39.878,161.798 41.021,160.655 41.021,157.607 40.64,157.226 C19.2@40.328,157.226 40.328,156.909 40.455,156.781 v1(40.831,156.781)
  Bottom Layer w0.254: U37.2@38.791,160.904 38.791,161.916 C89.2@38.958,162.083 ; U37.3@39.441,160.904 v1@39.441,161.798 ; U37.9@40.091,157.104 40.508,157.104 v1(40.831,156.781)
  Bottom Layer w0.508: v1(39.243,161.798) C89.2@39.243,162.368
NetC20_2: C20.2 SB2.2 | length 1.3
  Top Layer w0.127: C20.2@73.914,156.268 75.08,156.268 SB2.2@75.184,156.372
NetC22_2: C22.2 R20.1 X1.3 | length 3
  Top Layer w0.15: C22.2@76.9,148.844 77.343,148.844 ; R20.1@76.962,147.77 77.343,148.151 77.343,148.844 ; X1.3@77.049,150.097 77.343,149.803 77.343,148.844
NetC23_2: C23.2 R21.1 X1.1 | length 4.4
  Top Layer w0.15: R21.1@77.978,147.77 77.724,148.024 C23.2@77.724,148.844 ; C23.2@78.04,148.844 C23.2@77.724,148.844 ; X1.1@78.399,151.147 77.868,151.147 77.724,151.003 C23.2@77.724,148.844
NetC31_1: C31.1 CN8.1 R36.2 R44.1 SB11.2 U8.1 | length 9.7
  Top Layer w0.508: C31.1@8.128,136.239 9.366,136.239 R36.2@9.968,136.841 ; v1(9.017,142.875) 10.033,142.875 ; v1(9.779,137.541) 9.968,137.352 R36.2@9.968,136.841 ; R36.2@9.968,136.652 R36.2@9.968,136.841
  Signal Layer 3 w0.508: v1(9.017,142.875) 9.779,142.113 v1(9.779,137.541)
NetC36_1: C36.1 U9.1 | length 2.8
  Top Layer w0.254: C36.1@14.928,125.73 14.893,125.695 14.893,123.605 U9.1@15.6,123.605
NetC36_2: C36.2 U9.2 | length 4.2
  Top Layer w0.254: C36.2@14.028,125.73 14.028,123.259 14.332,122.955 U9.2@15.6,122.955
NetC37_2: C37.2 U9.3 | length 4.6
  Top Layer w0.254: U9.3@15.6,122.305 16.637,122.305 16.96,122.628 C37.2@16.96,125.73
NetC38_2: C38.2 U9.27 | length 4.1
  Top Layer w0.254: C38.2@21.024,125.73 21.024,123.248 21.317,122.955 U9.27@22.5,122.955
NetC40_1: C40.1 U9.24 | length 2.6
  Top Layer w0.254: U9.24@22.5,121.005 23.411,121.005 C40.1@24.638,122.232
NetC40_2: C40.2 U9.28 | length 2.3
  Top Layer w0.254: U9.28@22.5,123.605 24.165,123.605 C40.2@24.638,123.132
NetC44_2: C44.2 R83.1 SB19.1 U10.4 | length 1.2
  Top Layer w0.381: U10.4@19.746,105.948 R83.1@19.746,107.18
NetC46_2: C46.2 U13.4 | length 1.7
  Top Layer w0.508: U13.4@17.206,97.874 17.206,99.56 C46.2@17.214,99.568
NetC50_2: C50.2 SB23.1 U14.4 U14.5
NetC53_2: C53.2 SB24.1 U15.4 U15.5
NetC54_1: C54.1 R133.1 U15.1 | length 2.6
  Top Layer w0.381: R133.1@13.716,81.719 13.774,81.661 C54.1@15.298,81.661 15.306,81.669 U15.1@15.306,82.647
NetC65_2: C65.2 U19.4 | length 1.7
  Top Layer w0.508: C65.2@32.766,52.636 34.102,52.636 U19.4@34.102,53.002
NetC68_2: C68.2 CN19.1 U21.J1 | length 4.6
  Top Layer w0.127: C68.2@28.702,48.572 28.702,46.698 U21.J1@28.925,46.475
  Top Layer w0.508: CN19.1@26.67,49.53 27.628,48.572 C68.2@28.702,48.572
NetC77_2: C77.2 U21.J14 | length 4
  Top Layer w0.127: U21.J14@28.925,38.025 29.25,37.7 29.25,35.266 29.718,34.798 C77.2@29.718,34.482 C77.2@29.718,34.355
NetC86_2: C86.2 JPME1.2 R197.1 R198.2 U36.5 U36.8 | length 6.1
  Top Layer w0.508: v1(3.937,166.751) v1(6.35,166.751)
  Bottom Layer w0.254: v1(3.937,166.751) 4.105,166.583 U36.5@4.105,165.476 ; U36.8@6.055,165.476 6.055,166.37 6.309,166.624 R198.2@7.424,166.624
NetC87_2: C87.2 U36.4 | length 1.4
  Bottom Layer w0.254: C87.2@1.778,164.65 1.877,164.551 U36.4@3.18,164.551
NetC88_2: C88.2 C90.2 U36.2 U36.3 U36.9 | length 15.8
  Top Layer w0.508: v1(2.413,163.576) 2.413,162.687 3.429,161.671 6.223,161.671 7.112,162.56 7.112,163.703 v1(8.636,165.227)
  Bottom Layer w0.254: v1(2.413,163.576) 2.355,163.518 C90.2@1.778,163.518 ; U36.2@3.18,163.251 2.045,163.251 C90.2@1.778,163.518 ; U36.3@3.18,163.901 2.161,163.901 C90.2@1.778,163.518 ; U36.9@6.98,164.551 8.615,164.551 C88.2@8.636,164.53
  Bottom Layer w0.508: C88.2@8.636,164.53 v1(8.636,165.227)
NetC91_2: C91.2 U37.4 | length 1.6
  Bottom Layer w0.254: U37.4@40.091,160.904 40.091,161.63 40.386,161.925 C91.2@40.386,162.364
NetC96_1: C96.1 R220.1 R221.1 | length 14.7
  Bottom Layer w0.5: R221.1@28.08,151.374 28.326,151.374 29.104,150.596 36.126,150.596 37.11,151.58 37.11,153.51 37.5,153.9 R220.1@38.5,153.9 C96.1@40,153.9
NetC105_2: C105.2 C110.1 U7.20 | length 2.8
  Top Layer w0.254: v1(12.315,139.95) U7.20@13.323,139.95
  Bottom Layer w0.254: v1(12.315,139.95) 12.192,140.073 C105.2@12.192,140.524 13.331,140.524 C110.1@13.335,140.52
NetC147_2: C147.2 U48.9 | length 2.4
  Bottom Layer w0.254: U48.9@135.013,70.076 135.013,72.337 C147.2@135.128,72.452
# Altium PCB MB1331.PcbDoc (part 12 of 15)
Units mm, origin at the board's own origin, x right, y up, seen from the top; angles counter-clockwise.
Board outline 169.25 x 173.25 mm, 6 copper layers (Top Layer, Signal Layer 1, Signal Layer 2, Signal Layer 3, Signal Layer 4, Bottom Layer), stack 1.556 mm thick; 871 components, 699 nets, 3244 pads, 2370 vias.

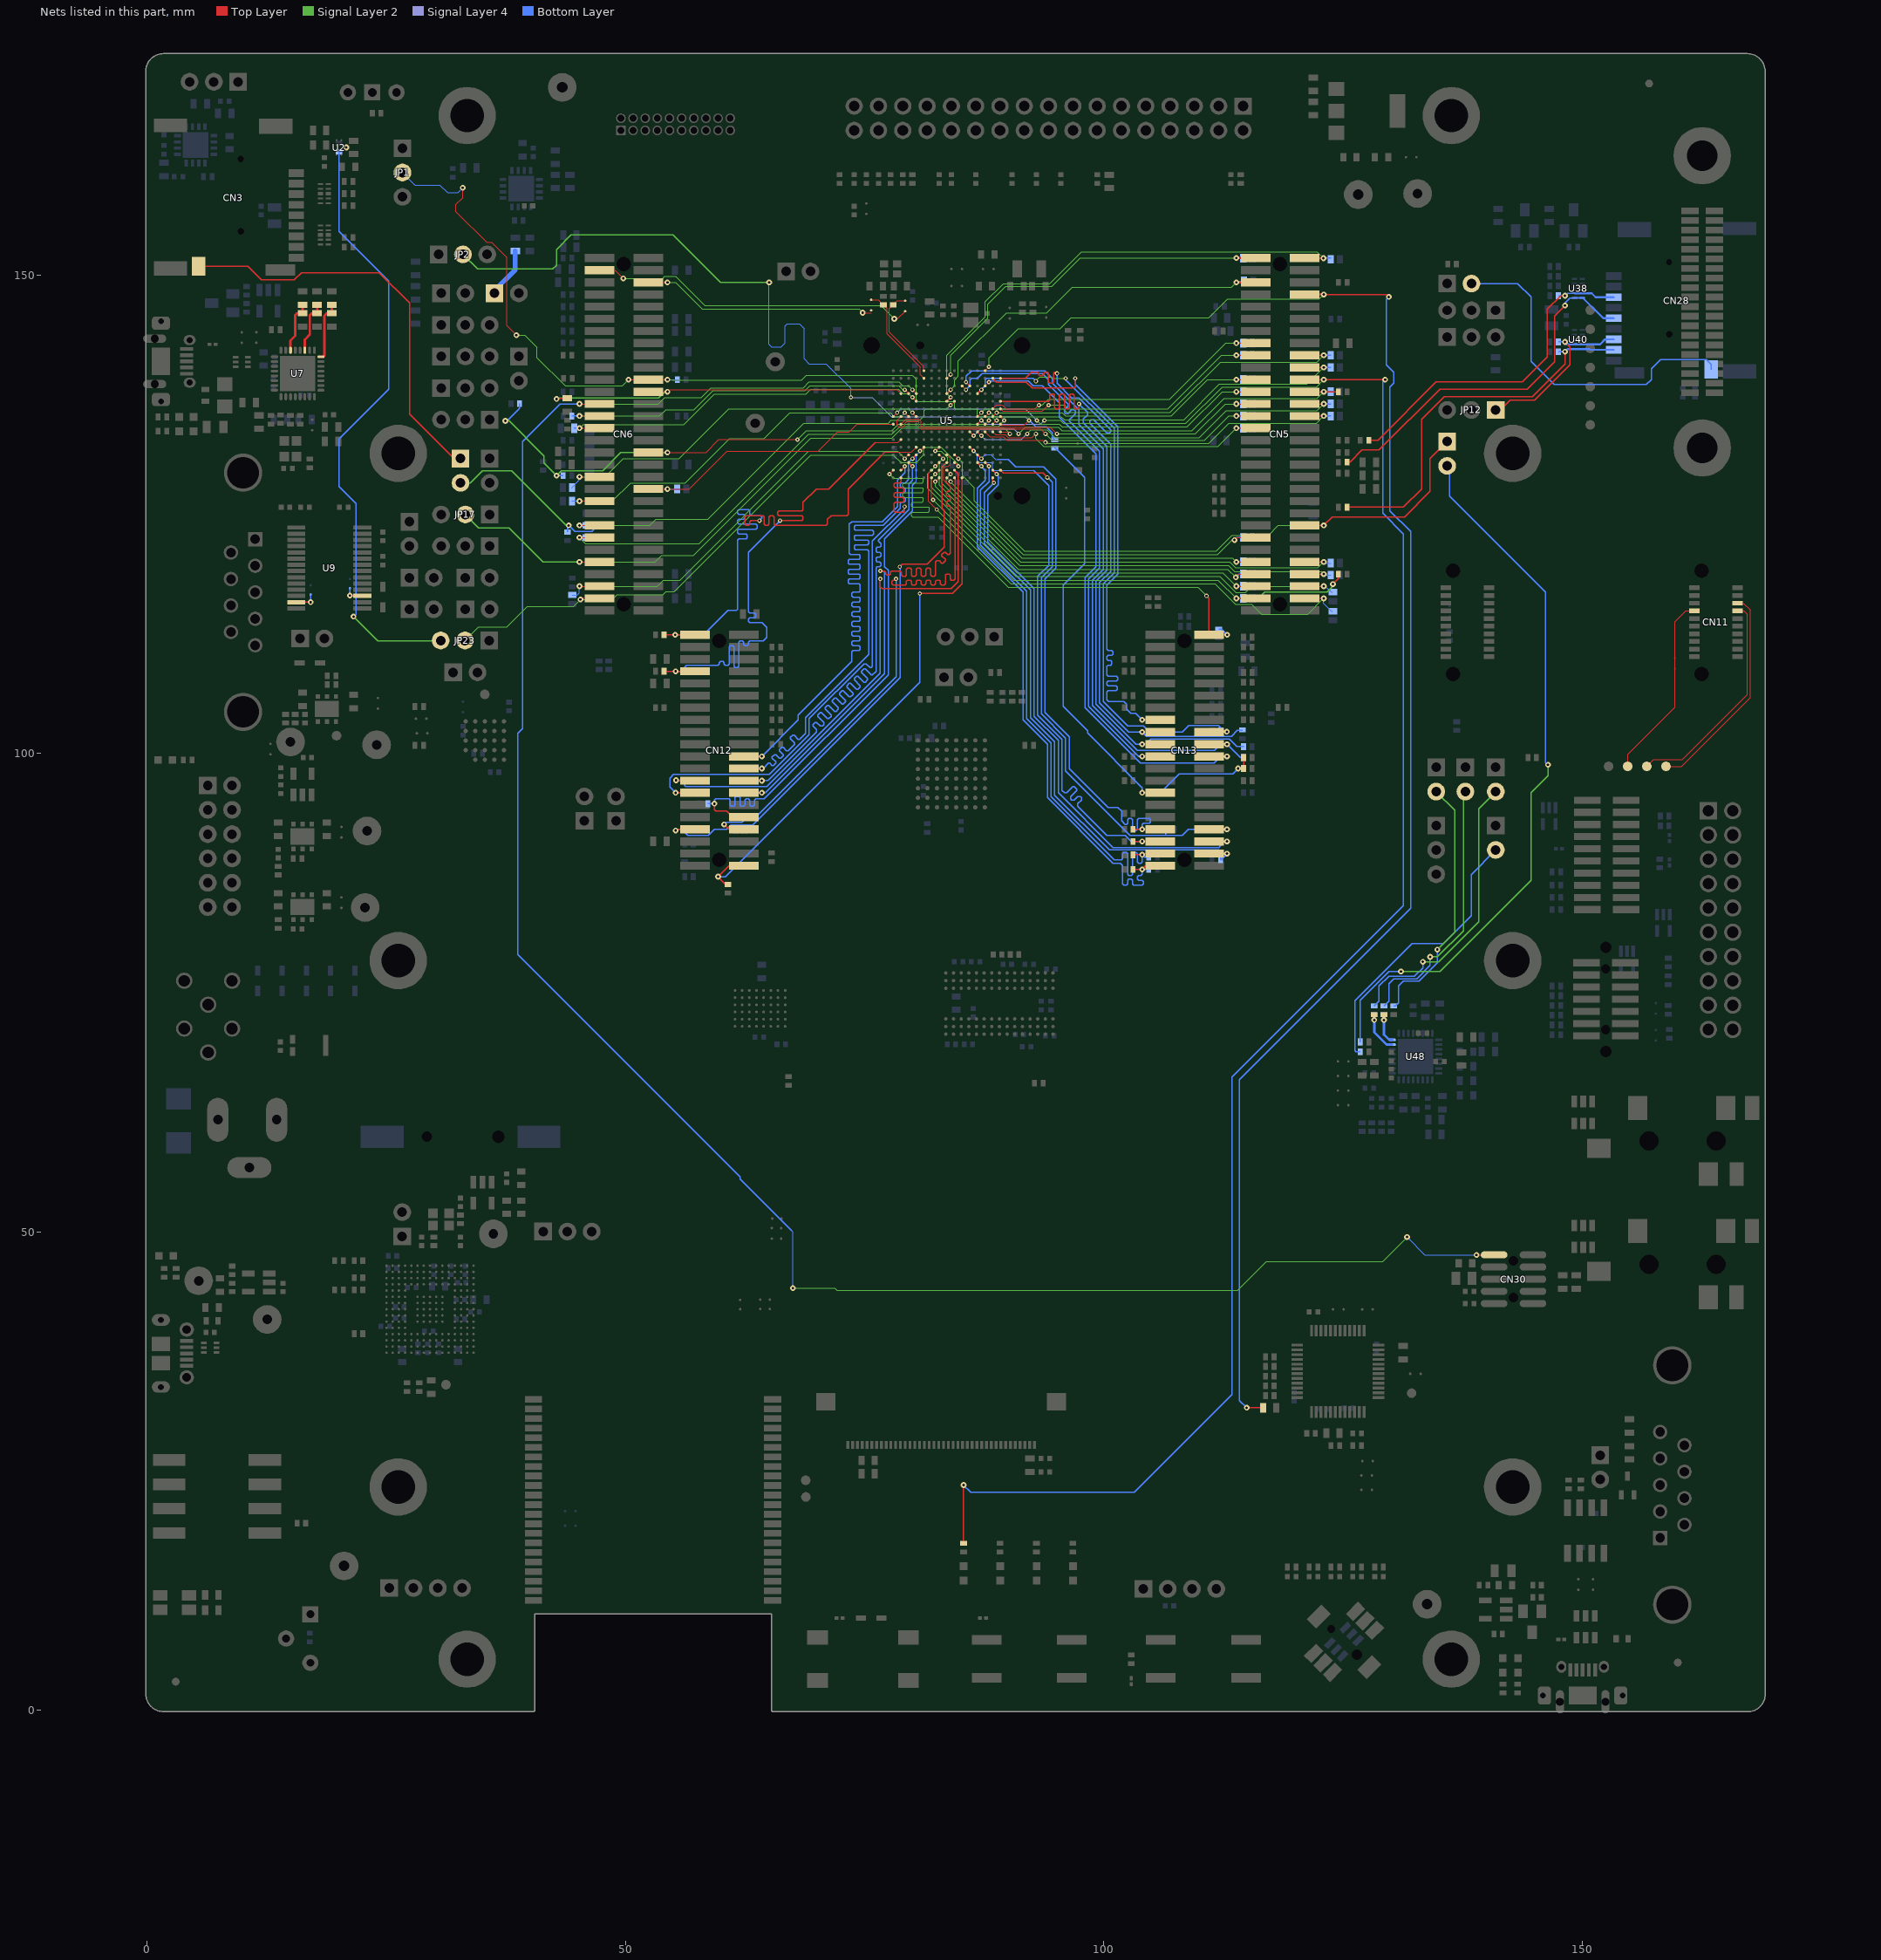
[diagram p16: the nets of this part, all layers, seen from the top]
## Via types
v1: diameter 0.6, hole 0.254, Top Layer to Bottom Layer, tented both sides, 1747 vias
v2: diameter 0.45, hole 0.2, Top Layer to Bottom Layer, tented both sides, 272 vias
v3: diameter 0.406, hole 0.203, Top Layer to Bottom Layer, tented both sides, 160 vias
v4: diameter 0.6, hole 0.25, Top Layer to Bottom Layer, tented both sides, 82 vias
v5: diameter 0.45, hole 0.25, Top Layer to Bottom Layer, tented both sides, 45 vias
v6: diameter 0.5, hole 0.25, Top Layer to Bottom Layer, tented both sides, 23 vias
v7: diameter 1.016, hole 0.508, Top Layer to Bottom Layer, tented both sides, 17 vias
v8: diameter 0.508, hole 0.254, Top Layer to Bottom Layer, tented both sides, 9 vias
v9: diameter 0.61, hole 0.305, Top Layer to Bottom Layer, tented both sides, 7 vias
v10: diameter 0.5, hole 0.254, Top Layer to Bottom Layer, tented both sides, 6 vias
v11: diameter 0.4, hole 0.2, Top Layer to Bottom Layer, tented both sides, 1 vias
v12: diameter 0.483, hole 0.254, Top Layer to Bottom Layer, tented both sides, 1 vias

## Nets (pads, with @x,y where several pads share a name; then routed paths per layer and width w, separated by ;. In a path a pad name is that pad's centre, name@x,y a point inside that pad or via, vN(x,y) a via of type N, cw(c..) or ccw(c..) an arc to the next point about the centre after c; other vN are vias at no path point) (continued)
PG1: CN12.7 R77.2 R333.2 U5.P10 | length 59.8
  Top Layer w0.1: 76.112,132.5 78.5,132.5 U5.P10@78.8,132.8
  Top Layer w0.127: R77.2@54.044,108.585 v1(55.251,108.585) CN12.7@57.273,108.585 ; v2(66.167,124.333) 68.453,124.333 68.58,124.46 68.58,124.714 68.453,124.841 66.04,124.841 65.913,124.968 65.913,125.222 66.04,125.349 68.453,125.349 68.58,125.476 68.58,126.238 69.977,127.635 71.247,127.635 76.112,132.5
  Bottom Layer w0.127: v1(55.251,108.585) R333.2@56.188,108.585 56.188,109.02 56.388,109.22 59.69,109.22 59.817,109.347 59.817,109.474 59.944,109.601 60.198,109.601 60.325,109.474 60.325,109.347 60.452,109.22 60.706,109.22 60.833,109.347 60.833,111.125 60.96,111.252 61.214,111.252 61.341,111.125 61.341,109.093 61.468,108.966 61.722,108.966 61.849,109.093 61.849,111.633 61.976,111.76 62.23,111.76 62.357,111.633 62.357,111.379 62.484,111.252 62.738,111.252 62.865,111.379 62.865,111.633 62.992,111.76 64.389,111.76 64.77,112.141 64.77,113.157 64.262,113.665 62.992,113.665 62.865,113.792 62.865,114.046 62.992,114.173 63.5,114.173 63.627,114.3 63.627,114.554 63.5,114.681 62.992,114.681 62.865,114.808 62.865,121.031 v2(66.167,124.333)
PG2: CN12.33 R380.2 U5.H13 | length 59.3
  Top Layer w0.1: 83.1,128.27 83.1,130 83.5,130.4 U5.H13@83.6,130.4
  Top Layer w0.127: v1(55.245,91.948) 55.251,92.075 CN12.33@57.273,92.075 ; v2(78.676,119.507) 78.93,119.761 81.534,119.761 83.312,121.539 83.312,125.391 83.1,125.603 83.1,128.27
  Bottom Layer w0.127: v1(55.245,91.948) 55.372,92.075 R380.2@56.188,92.075 56.188,91.758 56.506,91.44 58.674,91.44 59.309,92.075 60.579,92.075 61.023,92.519 63.309,92.519 78.74,107.95 78.74,119.444 v2(78.676,119.507)
PG3: CN12.34 R374.2 U5.G15 | length 59.5
  Top Layer w0.127: v1(60.325,92.583) 60.833,92.075 CN12.34@62.373,92.075 ; v2(78.295,118.237) 78.168,118.11 77.978,118.11 77.851,117.983 77.851,117.729 77.978,117.602 79.248,117.602 79.375,117.729 79.375,117.983 79.502,118.11 79.756,118.11 79.883,117.983 79.883,117.729 80.01,117.602 80.264,117.602 80.391,117.729 80.391,117.983 80.518,118.11 80.772,118.11 80.899,117.983 80.899,117.729 81.026,117.602 81.28,117.602 81.407,117.729 81.407,117.983 81.534,118.11 81.788,118.11 81.915,117.983 81.915,117.729 82.042,117.602 82.296,117.602 82.423,117.729 82.423,117.983 82.55,118.11 82.804,118.11 82.931,117.983 82.931,117.729 83.058,117.602 83.312,117.602 83.439,117.729 83.439,118.618 83.566,118.745 83.82,118.745 83.947,118.618 83.947,118.237 84.074,118.11 84.328,118.11 84.455,118.237 84.455,128.745 U5.G15@84.4,128.8
  Bottom Layer w0.127: v1(60.325,92.583) 60.547,92.805 62.198,92.805 62.426,93.033 R374.2@62.426,93.345 63.627,93.345 78.295,108.013 v2(78.295,118.237)
PG4: CN12.28 R369.2 U5.H12 | length 59.9
  Top Layer w0.1: 83.439,128.397 83.3,128.536 83.3,129.9 83.4,130 83.747,130 83.947,130.2 83.947,130.853 U5.H12@83.6,131.2
  Top Layer w0.127: CN12.28@62.373,95.885 v1(64.262,95.885) ; v2(76.644,119.062) 77.089,119.062 77.216,118.935 77.216,118.745 77.343,118.618 77.597,118.618 77.724,118.745 77.724,118.968 77.818,119.062 78.74,119.062 78.867,118.935 78.867,118.618 78.994,118.491 79.248,118.491 79.375,118.618 79.375,119.253 79.502,119.38 79.756,119.38 79.883,119.253 79.883,118.618 80.01,118.491 80.264,118.491 80.391,118.618 80.391,119.253 80.518,119.38 80.772,119.38 80.899,119.253 80.899,118.618 81.026,118.491 81.28,118.491 81.407,118.618 81.407,119.253 81.534,119.38 81.788,119.38 81.915,119.253 81.915,118.618 82.042,118.491 82.296,118.491 82.423,118.618 82.423,120.015 82.55,120.142 82.804,120.142 83.058,119.888 83.185,119.888 83.439,120.142 83.439,120.269 83.058,120.65 83.058,120.777 83.312,121.031 83.439,121.031 83.693,120.777 83.82,120.777 83.947,120.904 83.947,125.73 83.82,125.857 83.693,125.857 83.566,125.984 83.566,126.238 83.693,126.365 83.82,126.365 83.947,126.492 83.947,126.746 83.82,126.873 83.693,126.873 83.566,127 83.566,127.254 83.693,127.381 83.82,127.381 83.947,127.508 83.947,127.889 83.439,128.397
  Bottom Layer w0.127: R369.2@63.442,95.885 v1(64.262,95.885) 64.643,95.885 77.089,108.331 77.089,118.999 77.025,119.062 v2(76.644,119.062)
PG5: CN12.25 R366.2 U5.G14 | length 59.9
  Top Layer w0.127: v1(55.3,97.2) 55.3,97.155 CN12.25@57.273,97.155 ; v2(76.644,118.237) 76.644,117.411 76.835,117.221 84.074,117.221 84.8,117.947 84.8,129.2 U5.G14@84.4,129.6
  Bottom Layer w0.127: v1(55.3,97.2) 55.345,97.155 R366.2@56.188,97.155 56.188,96.647 56.315,96.52 64.77,96.52 76.644,108.394 v2(76.644,118.237)
PG6: CN6.57 JP23.2 U5.G13 | length 64.5
  Top Layer w0.1: v1@45.2,116.205 45.3,116.205 CN6.57@47.293,116.205 ; U5.G13@84.4,130.4 v2(84.8,130)
  Signal Layer 2 w0.1: JP23.2@33.235,111.8 34.635,113.2 37.6,113.2 39.775,115.375 44.595,115.375 v1(45.3,116.08) 48.643,116.08 48.768,116.205 49.149,116.586 53.915,116.586 54.229,116.9 55.1,116.9 69.391,131.191 78.009,131.191 78.8,130.4 80.4,130.4 81.2,131.2 81.2,131.793 81.407,132 83,132 84.8,130.2 v2(84.8,130)
PG7: CN5.46 JP14.1 U5.G12 | length 66
  Top Layer w0.1: U5.G12@84.4,131.2 v2(84.8,130.8) ; CN5.46@120.972,123.825 v1(122.994,123.825)
  Top Layer w0.127: v1(122.994,123.825) 123.883,124.714 131.445,124.714 134.112,127.381 134.112,130.81 JP14.1@135.89,132.588
  Signal Layer 2 w0.1: v2(84.8,130.8) 85.217,130.383 85.217,129.032 86.487,127.762 86.487,126.365 91.694,121.158 111.76,121.158 113.411,122.809 117.221,122.809 118.237,123.825 v1(122.994,123.825)
PG8: CN12.40 R132.2 U5.F15 | length 59.2
  Top Layer w0.127: R132.2@60.706,86.302 60.51,86.302 v1(59.69,87.122) 60.833,88.265 CN12.40@62.373,88.265 ; v2(80.772,116.713) 84.201,116.713 85.2,117.712 U5.F15@85.2,128.8
  Bottom Layer w0.127: v1(59.69,87.122) 60.452,87.122 80.772,107.442 v2(80.772,116.713)
PG9: CN6.51 JP17.2 U5.A9 | length 68.2
  Top Layer w0.1: v1(45.2,120.015) CN6.51@47.293,120.015 ; U5.A9@89.2,133.6 90,133.6 v2(90.2,133.4)
  Signal Layer 2 w0.1: v1(45.2,120.015) 53.086,120.015 53.771,120.7 57.1,120.7 69.369,132.969 77.851,132.969 78.882,134 89.6,134 v2(90.2,133.4)
  Signal Layer 2 w0.127: JP17.2@33.274,124.968 34.671,123.571 37.846,123.571 41.402,120.015 v1(45.2,120.015)
PG10: JP2.2 R280.2 U5.A8 | length 86.5
  Top Layer w0.1: U5.A8@89.2,134.4 89.3,134.3 91.7,134.3 v2(92.2,134.8)
  Signal Layer 2 w0.127: JP2.2@33.02,152.146 34.544,150.622 42.418,150.622 42.799,151.003 42.799,152.654 44.323,154.178 54.991,154.178 59.944,149.225 v1(65.024,149.225)
  Signal Layer 4 w0.1: v2(73.573,137.2) 75.8,137.2 77.8,135.2 91.8,135.2 v2(92.2,134.8)
  Bottom Layer w0.1: v1(65.024,149.225) 65.024,142.748 65.278,142.494 66.294,142.494 66.675,142.875 66.675,144.653 66.929,144.907 68.199,144.907 68.707,144.399 68.707,141.224 69.215,140.716 70.993,140.716 73.573,138.136 v2(73.573,137.2)
  Bottom Layer w0.127: v2(92.2,134.8) 92.888,134.112 93.98,134.112 94.615,133.477 94.615,133.038 R280.2@94.869,132.784
PG10_E: CN13.27 R115.2 R118.2 R280.1 | length 56.4
  Top Layer w0.102: v1(104.013,95.885) CN13.27@105.892,95.885
  Top Layer w0.127: v1(114.046,98.425) R115.2@114.612,98.425 R118.2@114.612,99.568
  Bottom Layer w0.127: R280.1@94.869,131.884 94.958,131.884 97.999,128.843 97.999,119.843 95.758,117.602 95.758,104.902 98.298,102.362 98.298,102.128 104.013,96.414 v1(104.013,95.885) 105.918,95.885 107.886,97.853 113.474,97.853 v1(114.046,98.425)
PG11: CN6.22 JP1.2 R257.2 U5.B8 | length 85
  Top Layer w0.1: v1(33,159.1) 33,158.064 32.3,157.364 32.3,156.6 35.5,153.4 36,153.4 37.6,151.8 37.6,144.7 v1(38.6,143.7) ; v1(50.335,139.065) CN6.22@52.393,139.065 v1(54.4,139.065) ; U5.B8@88.4,134.4 v2(88.8,134.8)
  Signal Layer 2 w0.1: v1(38.6,143.7) 39.5,143.7 40.767,142.433 40.767,141.352 43.719,138.4 49.67,138.4 v1(50.335,139.065) ; v1(54.4,139.065) 54.8,139.065 54.865,139 68.4,139 68.9,139.5 80,139.5 80.4,139.1 80.4,136.9 80.5,136.8 84.3,136.8 84.4,136.7 84.4,136.1 84.5,136 86.7,136 86.8,135.9 86.8,135.3 86.9,135.2 88.3,135.2 88.7,134.8 v2(88.8,134.8)
  Bottom Layer w0.1: JP1.2@26.7,160.7 28,159.4 30.6,159.4 31.4,158.6 32.5,158.6 v1(33,159.1) ; v1(54.4,139.065) R257.2@55.43,139.065
PG12: CN6.34 R122.2 R287.2 U5.C8 | length 61.7
  Top Layer w0.1: CN6.34@52.393,131.445 v1(54.4,131.445) 58.42,131.445 59.775,132.8 v2(68,132.8) ; U5.C8@87.7,134.4 U5.C8@87.6,134.4 v2(88,134.8)
  Signal Layer 2 w0.1: v2(68,132.8) 68.931,133.731 77.851,133.731 78.52,134.4 87.6,134.4 v2(88,134.8)
  Signal Layer 2 w0.127: v1(37.45,134.75) 37.85,134.75 41.5,131.1 41.5,130.331 v4(42.799,129.032) 43.307,129.54 47.625,129.54 49.53,131.445 v1(54.4,131.445)
  Bottom Layer w0.127: v1(37.45,134.75) 37.65,134.75 38.95,136.05 R122.2@38.95,136.55 ; v4(42.799,129.032) R287.2@43.492,129.032
PG13: CN5.22 R178.2 U5.D8 | length 200.3
  Top Layer w0.1: U5.D8@86.8,134.4 v2(87.2,134.8) ; CN5.22@120.972,139.065 v1(122.994,139.065)
  Top Layer w0.127: R178.2@85.344,17.468 v4@85.344,23.544 ; v1(122.994,139.065) v1(129.413,139.065)
  Signal Layer 2 w0.1: v2(93.8,134.8) 95.451,134.8 95.758,134.493 108.593,134.493 112.4,138.3 122.229,138.3 v1(122.994,139.065)
  Signal Layer 4 w0.1: v2(87.2,134.8) 87.6,134.4 93.4,134.4 v2(93.8,134.8)
  Bottom Layer w0.127: v4(85.35,23.55) 86.1,22.8 103.191,22.8 113.411,33.02 113.411,66.167 131.318,84.074 131.318,122.936 129.159,125.095 129.159,138.811 v1(129.413,139.065)
PG14: CN6.47 R300.2 U5.A7 | length 53.3
  Top Layer w0.1: v1(45.2,122.555) CN6.47@47.293,122.555 ; U5.A7@89.2,135.2 v2(89.6,134.8)
  Signal Layer 2 w0.1: v1(45.2,122.555) 45.835,121.92 57.72,121.92 69.15,133.35 77.851,133.35 78.701,134.2 89,134.2 v2(89.6,134.8)
  Bottom Layer w0.1: v1(45.2,122.555) R300.2@45.778,122.555
  Bottom Layer w0.127: v1(45.2,122.555) v1@45.212,122.543
PG15: CN13.19 R352.2 R354.2 U5.A5 | length 69.3
  Top Layer w0.127: U5.A5@89.2,136.8 94.234,136.8 94.361,136.927 94.361,137.414 94.488,137.541 94.742,137.541 94.869,137.414 94.869,136.144 94.996,136.017 95.25,136.017 95.377,136.144 95.377,137.414 95.504,137.541 95.758,137.541 95.885,137.414 95.885,136.144 96.012,136.017 96.266,136.017 96.393,136.144 96.393,137.414 96.52,137.541 96.774,137.541 96.901,137.414 96.901,136.144 97.028,136.017 97.282,136.017 97.409,136.144 v2(97.409,136.525) ; v1(104.013,100.965) CN13.19@105.892,100.965
  Bottom Layer w0.127: v2(97.409,136.525) 98.298,135.636 98.298,135.38 97.853,134.935 97.853,134.556 100.33,132.08 100.33,119.126 99.187,117.983 99.187,105.156 103.378,100.965 v1(104.013,100.965) R352.2@104.706,100.965 104.706,101.277 104.929,101.5 113.13,101.5 113.919,100.711 R354.2@114.612,100.711
PH0: R21.2 SB7.1 U5.L1 | length 10
  Top Layer w0.1: SB7.1@79.248,147.312 78.42,147.312 R21.2@77.978,146.87 77.597,146.489 77.597,144.018 81.2,140.415 U5.L1@81.2,140
PH0_E: CN6.3 SB7.2 | length 34.6
  Top Layer w0.1: CN6.3@47.293,150.495 48.929,150.495 v1(49.784,149.64) ; v1(78.105,145.415) 78.451,145.415 SB7.2@79.248,146.212
  Signal Layer 2 w0.1: v1(49.784,149.64) 53.882,149.64 54.102,149.86 55.245,149.86 58.293,146.812 76.708,146.812 v1(78.105,145.415)
PH1: R20.2 SB6.2 U5.L2 | length 10.9
  Top Layer w0.1: SB6.2@75.692,147.412 76.42,147.412 R20.2@76.962,146.87 77.343,146.489 77.343,143.857 80.8,140.4 80.8,139.6 U5.L2@81.2,139.2
PH1_E: CN6.6 SB6.1 | length 24.6
  Top Layer w0.1: CN6.6@52.393,149.225 v1(54.4,149.225) ; v1(74.803,146.05) 75.692,146.05
  Signal Layer 2 w0.1: v1(54.4,149.225) 55.245,149.225 58.039,146.431 74.422,146.431 v1(74.803,146.05)
PH2: CN6.25 CN30.10 U5.M4 | length 223.4
  Top Layer w0.1: v1(45.2,136.525) CN6.25@47.293,136.525 ; v2(80,138) U5.M4@80.4,137.6 ; v1(138.95,47.6) CN30.10@140.795,47.6
  Signal Layer 2 w0.1: v1(45.2,136.525) 53.427,136.525 54.102,137.2 57.952,137.2 58.952,138.2 68.589,138.2 69.2,138.811 78.589,138.811 79,138.4 79.6,138.4 v2(80,138) ; v1(67.5,44.125) 71.9,44.125 72.125,43.9 113.975,43.9 117,46.925 129.15,46.925 v1(131.7,49.475)
  Bottom Layer w0.1: 67.35,50.125 67.5,49.975 v1(67.5,44.125) ; v1(131.7,49.475) 131.7,49.45 133.55,47.6 v1(138.95,47.6)
  Bottom Layer w0.127: v1(45.2,136.525) 43.18,136.525 39.243,132.588 39.243,102.616 38.735,102.108 38.735,78.994 61.976,55.753 61.976,55.499 67.35,50.125
PH3: CN6.27 R272.2 U5.N4 | length 39
  Top Layer w0.1: v1(45.2,135.255) CN6.27@47.293,135.255 ; v2(79.2,138) U5.N4@79.6,137.6
  Signal Layer 2 w0.1: v1(45.2,135.255) 53.584,135.255 54.229,135.9 57.16,135.9 59.16,137.9 68.77,137.9 69.3,138.43 78.57,138.43 79,138 v2(79.2,138)
  Bottom Layer w0.127: R272.2@44.392,135.255 v1(45.2,135.255)
PH4: CN6.29 R275.2 U5.M5 | length 40.1
  Top Layer w0.1: v1(45.2,133.985) CN6.29@47.293,133.985 ; v2(80,137.2) U5.M5@80.4,136.8
  Signal Layer 2 w0.1: v1(45.2,133.985) 45.581,134.366 56.134,134.366 59.311,137.543 68.894,137.543 69.4,138.049 78.551,138.049 79,137.6 79.6,137.6 v2(80,137.2)
  Bottom Layer w0.127: R275.2@44.642,133.985 v1(45.2,133.985)
PH5: CN6.24 R35.2 U5.P4 | length 39.7
  Top Layer w0.1: CN6.24@52.393,137.795 v1(54.4,137.795) 54.605,138 78.4,138 U5.P4@78.8,137.6
  Top Layer w0.127: v4(42.799,137.033) 42.864,137.098 R35.2@43.942,137.098
  Signal Layer 2 w0.127: v4(42.799,137.033) 42.926,137.16 53.467,137.16 54.102,137.795 v1(54.4,137.795)
PH6: CN12.1 R68.2 U5.M11 | length 60
  Top Layer w0.1: 76.795,131.151 77.144,131.5 79.9,131.5 U5.M11@80.4,132
  Top Layer w0.127: R68.2@54.044,112.395 v1(55.2,112.4) CN12.1@57.273,112.395 ; v2(64.008,124.333) 63.119,124.333 62.992,124.206 62.992,123.952 62.865,123.825 62.611,123.825 62.484,123.952 62.484,124.714 62.611,124.841 64.389,124.841 64.516,124.714 64.516,123.952 64.643,123.825 64.897,123.825 65.024,123.952 65.024,124.714 65.151,124.841 65.405,124.841 65.532,124.714 65.532,123.952 65.659,123.825 70.993,123.825 71.12,123.952 71.12,124.46 71.501,124.841 73.152,124.841 73.279,124.968 73.279,127.635 76.795,131.151
  Bottom Layer w0.127: v1(55.2,112.4) 58.171,112.4 60.706,114.935 61.595,114.935 61.722,115.062 61.722,122.301 61.849,122.428 62.611,122.428 62.738,122.555 62.738,122.809 62.611,122.936 61.849,122.936 61.722,123.063 61.722,123.317 61.849,123.444 63.627,123.444 63.754,123.571 63.754,123.825 63.627,123.952 61.849,123.952 61.722,124.079 61.722,124.333 61.849,124.46 62.357,124.46 62.484,124.587 62.484,124.841 62.357,124.968 61.849,124.968 61.722,125.095 61.722,125.349 61.849,125.476 62.865,125.476 62.992,125.349 62.992,124.968 63.119,124.841 64.135,124.841 64.262,124.714 64.262,124.587 v2(64.008,124.333)
PH7: CN13.2 R320.2 U5.R14 | length 62.4
  Top Layer w0.1: v2(77.6,129.2) U5.R14@78,129.6
  Top Layer w0.127: v5(110.744,116.459) 110.992,116.211 CN13.2@110.992,112.395 v1(112.903,112.395)
  Signal Layer 2 w0.1: v2(77.6,129.2) 78.022,128.778 81.026,128.778 81.153,128.651 81.153,128.397 81.026,128.27 79.121,128.27 78.994,128.143 78.994,127.889 79.121,127.762 81.026,127.762 81.153,127.635 81.153,127.381 81.026,127.254 79.121,127.254 78.994,127.127 78.994,126.873 79.121,126.746 81.026,126.746 81.153,126.619 81.153,126.365 81.026,126.238 80.01,126.238 79.883,126.111 79.883,125.857 80.01,125.73 81.661,125.73 81.788,125.603 81.788,125.349 81.661,125.222 80.01,125.222 79.883,125.095 79.883,124.841 80.01,124.714 82.677,124.714 90.043,117.348 109.855,117.348 v5(110.744,116.459)
  Bottom Layer w0.127: R320.2@112.014,112.972 112.326,112.972 v1(112.903,112.395)
PH8: CN12.22 R358.2 U5.P14 | length 59.1
  Top Layer w0.127: CN12.22@62.373,99.695 v1(64.262,99.695) ; U5.P14@78.8,129.6 v2(79.2,130)
  Bottom Layer w0.127: R358.2@63.442,99.695 v1(64.262,99.695) 68.072,103.505 68.072,104.013 73.66,109.601 73.66,110.617 73.787,110.744 74.422,110.744 74.549,110.871 74.549,111.125 74.422,111.252 73.787,111.252 73.66,111.379 73.66,111.633 73.787,111.76 74.422,111.76 74.549,111.887 74.549,112.141 74.422,112.268 73.787,112.268 73.66,112.395 73.66,112.649 73.787,112.776 74.422,112.776 74.549,112.903 74.549,113.157 74.422,113.284 73.787,113.284 73.66,113.411 73.66,113.665 73.787,113.792 74.422,113.792 74.549,113.919 74.549,114.173 74.422,114.3 73.787,114.3 73.66,114.427 73.66,114.681 73.787,114.808 74.422,114.808 74.549,114.935 74.549,115.189 74.422,115.316 73.787,115.316 73.66,115.443 73.66,115.697 73.787,115.824 74.422,115.824 74.549,115.951 74.549,116.205 74.422,116.332 73.787,116.332 73.66,116.459 73.66,116.713 73.787,116.84 74.422,116.84 74.549,116.967 74.549,117.602 74.422,117.729 73.406,117.729 73.279,117.856 73.279,118.11 73.406,118.237 74.422,118.237 74.549,118.364 74.549,118.618 74.422,118.745 73.406,118.745 73.279,118.872 73.279,119.126 73.406,119.253 74.422,119.253 74.549,119.38 74.549,119.634 74.422,119.761 73.406,119.761 73.279,119.888 73.279,120.142 73.406,120.269 74.422,120.269 74.549,120.396 74.549,120.65 74.422,120.777 73.533,120.777 73.406,120.904 73.406,123.952 73.66,124.206 76.837,124.206 78.429,125.798 78.429,128.594 79.2,129.365 v2(79.2,130)
PH9: CN12.26 R365.2 U5.N13 | length 59.7
  Top Layer w0.127: CN12.26@62.373,97.155 v1(64.262,97.155) ; U5.N13@79.6,130.4 v2(80,130)
  Bottom Layer w0.127: R365.2@63.442,97.155 v1(64.262,97.155) 64.897,97.155 69.977,102.235 69.977,102.489 69.596,102.87 69.596,102.997 69.85,103.251 69.977,103.251 70.358,102.87 70.612,102.87 70.739,102.997 70.739,103.251 70.104,103.886 70.104,104.013 70.358,104.267 70.485,104.267 71.12,103.632 71.247,103.632 71.501,103.886 71.501,104.013 70.866,104.648 70.866,104.775 71.12,105.029 71.247,105.029 71.882,104.394 72.009,104.394 72.263,104.648 72.263,104.775 71.628,105.41 71.628,105.537 71.882,105.791 72.009,105.791 72.644,105.156 72.771,105.156 73.025,105.41 73.025,105.537 72.39,106.172 72.39,106.299 72.644,106.553 72.771,106.553 73.406,105.918 73.533,105.918 73.787,106.172 73.787,106.299 73.152,106.934 73.152,107.061 73.406,107.315 73.533,107.315 74.168,106.68 74.295,106.68 74.549,106.934 74.549,107.061 73.914,107.696 73.914,107.823 74.168,108.077 74.295,108.077 74.93,107.442 75.057,107.442 75.311,107.696 75.311,107.823 74.676,108.458 74.676,108.585 74.93,108.839 75.057,108.839 75.692,108.204 75.819,108.204 76.2,108.585 76.2,119.38 76.327,119.507 76.581,119.507 76.708,119.634 76.708,119.888 76.581,120.015 76.327,120.015 76.2,120.142 76.2,120.396 76.327,120.523 76.581,120.523 76.708,120.65 76.708,120.904 76.581,121.031 76.327,121.031 76.2,121.158 76.2,121.412 76.327,121.539 76.581,121.539 76.708,121.666 76.708,121.92 76.454,122.174 76.454,122.301 79.629,125.476 79.629,128.143 80,128.514 v2(80,130)
PH10: CN12.24 R361.2 U5.M12 | length 58.6
  Top Layer w0.127: CN12.24@62.373,98.425 v1(64.262,98.425) ; v2(80,130.8) U5.M12@80.4,131.2
  Bottom Layer w0.127: R361.2@63.442,98.425 v1(64.262,98.425) 64.389,98.425 64.96,98.996 65.087,98.996 65.341,98.742 65.468,98.742 65.722,98.996 65.722,99.123 65.341,99.504 65.341,99.632 65.595,99.885 65.722,99.885 66.103,99.504 66.23,99.504 66.484,99.758 66.484,99.885 66.103,100.266 66.103,100.393 66.357,100.647 66.484,100.647 66.838,100.294 67.02,100.294 67.691,100.965 67.691,101.092 67.246,101.536 67.246,101.663 67.5,101.917 67.627,101.917 68.072,101.473 68.199,101.473 68.834,102.108 68.834,103.759 75.438,110.363 75.438,121.158 75.311,121.285 74.041,121.285 73.914,121.412 73.914,121.666 74.041,121.793 75.311,121.793 75.438,121.92 75.438,122.174 75.311,122.301 74.041,122.301 73.914,122.428 73.914,122.682 74.041,122.809 75.819,122.809 75.946,122.936 75.946,123.19 75.819,123.317 74.041,123.317 73.914,123.444 73.914,123.698 74.041,123.825 76.962,123.825 78.74,125.603 78.74,126.111 78.867,126.238 79.121,126.238 79.248,126.365 79.248,126.619 79.121,126.746 78.867,126.746 78.74,126.873 78.74,127.127 78.867,127.254 79.121,127.254 79.248,127.381 79.248,127.635 79.121,127.762 78.867,127.762 78.74,127.889 78.74,128.143 78.867,128.27 79.248,128.27 79.6,128.622 79.6,130.4 v2(80,130.8)
PH11: CN12.27 R370.2 U5.P15 | length 59.2
  Top Layer w0.127: v1(55.251,95.885) CN12.27@57.273,95.885 ; U5.P15@78.8,128.8 78.8,128.397 78.673,128.27 78.232,128.27 78.105,128.143 78.105,127.889 78.232,127.762 78.994,127.762 79.121,127.635 79.121,127.381 78.994,127.254 78.232,127.254 78.105,127.127 78.105,126.873 78.232,126.746 78.994,126.746 79.121,126.619 79.121,126.365 78.994,126.238 78.232,126.238 78.105,126.111 78.105,125.349 78.232,125.222 79.088,125.222 79.184,125.318 v2(79.184,125.793)
  Bottom Layer w0.127: R370.2@56.188,95.885 v1(55.251,95.885) 54.636,96.5 54.636,97.4 55.036,97.8 65.034,97.8 68.834,101.6 69.215,101.981 69.215,103.632 74.93,109.347 75.184,109.347 75.565,108.966 75.692,108.966 75.819,109.093 75.819,122.174 79.184,125.539 v2(79.184,125.793)
PH12: CN12.32 R371.2 U5.L11 | length 58.5
  Top Layer w0.127: v1(59.309,94.742) 59.309,94.107 59.436,93.98 60.579,93.98 61.214,93.345 CN12.32@62.373,93.345 ; v2(80.8,131.6) U5.L11@81.2,132
  Bottom Layer w0.1: 80.333,128.339 80.4,128.406 80.4,131.2 v2(80.8,131.6)
  Bottom Layer w0.127: R371.2@58.616,94.742 v1(59.309,94.742) 59.309,95.123 59.436,95.25 60.833,95.25 60.96,95.123 60.96,94.615 61.087,94.488 61.341,94.488 61.468,94.615 61.468,95.377 61.595,95.504 61.849,95.504 61.976,95.377 61.976,94.615 62.103,94.488 62.357,94.488 62.484,94.615 62.484,95.123 62.611,95.25 62.865,95.25 62.992,95.123 62.992,94.615 63.119,94.488 63.373,94.488 63.5,94.615 63.5,95.123 63.627,95.25 64.516,95.25 77.47,108.204 77.47,119.126 77.089,119.507 77.089,122.428 80.01,125.349 80.01,128.016 80.333,128.339
PH13: CN13.39 R131.2 R389.2 U5.D13 | length 60.7
  Top Layer w0.127: U5.D13@86.8,130.4 v2(87.2,130) ; R131.2@103.066,87.884 v1(104.013,87.884) 104.394,88.265 CN13.39@105.892,88.265
  Bottom Layer w0.127: v2(87.2,130) 87.63,129.57 87.63,128.524 86.8,127.694 86.8,121.607 91.567,116.84 91.567,103.505 94.107,100.965 94.107,95.377 100.965,88.519 101.727,88.519 101.981,88.265 101.981,86.36 102.108,86.233 102.362,86.233 102.489,86.36 102.489,86.741 102.616,86.868 102.87,86.868 102.997,86.741 102.997,86.36 103.124,86.233 104.013,86.233 104.14,86.36 104.14,86.614 104.013,86.741 103.632,86.741 103.505,86.868 103.505,87.122 103.632,87.249 103.886,87.249 104.013,87.376 v1(104.013,87.884) R389.2@104.706,87.884
PH14: CN13.38 R387.2 U5.B15 | length 60.1
  Top Layer w0.127: U5.B15@88.4,128.8 88.4,128.389 v2(88.519,128.27) ; CN13.38@110.992,89.535 v1(112.881,89.535)
  Bottom Layer w0.127: v2(88.519,128.27) 87.503,127.254 87.503,121.92 92.329,117.094 92.329,103.759 94.869,101.219 94.869,95.631 100.584,89.916 112.014,89.916 112.21,89.72 R387.2@112.21,88.9 112.246,88.9 v1(112.881,89.535)
PH15: CN13.36 R382.2 U5.B14 | length 59.9
  Top Layer w0.127: U5.B14@88.4,129.6 v2(88.8,129.2) ; CN13.36@110.992,90.805 v1(112.881,90.805)
  Bottom Layer w0.127: v2(88.8,129.2) 88.963,129.037 88.963,128.078 87.884,127 87.884,122.047 92.71,117.221 92.71,103.886 95.25,101.346 95.25,95.885 100.965,90.17 112.014,90.17 112.21,90.366 R382.2@112.21,90.805 v1(112.881,90.805)
PI0: CN13.37 R128.1 R386.2 U5.C13 | length 61.4
  Top Layer w0.127: U5.C13@87.6,130.4 v2(88,130) ; R128.1@103.066,89.408 v1(104.013,89.408) 104.14,89.535 CN13.37@105.892,89.535
  Bottom Layer w0.127: v2(88,130) 88,128.386 87.122,127.508 87.122,121.793 91.948,116.967 91.948,103.632 94.488,101.092 94.488,95.504 101.092,88.9 101.854,88.9 101.981,89.027 101.981,89.535 102.108,89.662 102.362,89.662 102.489,89.535 102.489,87.376 102.616,87.249 102.87,87.249 102.997,87.376 102.997,89.535 103.124,89.662 103.378,89.662 103.505,89.535 103.505,88.646 103.632,88.519 103.886,88.519 104.013,88.646 v1(104.013,89.408) 104.267,89.154 R386.2@104.706,89.154
PI1: CN13.35 R124.2 U5.E11 | length 60.8
  Top Layer w0.127: U5.E11@86,132 v2(86.4,131.6) ; R124.2@103.066,90.805 v1(104.013,90.805) CN13.35@105.892,90.805
  Bottom Layer w0.102: v2(86.4,131.6) 86.8,131.2 86.8,130.6 87,130.4 88.3,130.4 88.4,130.3 88.4,129.7 88.5,129.6 92.65,129.6
  Bottom Layer w0.127: 92.65,129.6 94.247,128.003 94.247,119.647 93.091,118.491 93.091,104.013 95.631,101.473 95.631,96.139 95.885,95.885 96.139,95.885 96.774,96.52 96.901,96.52 97.155,96.266 97.155,96.139 96.52,95.504 96.52,95.25 96.647,95.123 96.901,95.123 97.282,95.504 97.536,95.504 97.663,95.377 97.663,95.123 97.282,94.742 97.282,94.488 100.33,91.44 102.235,91.44 102.87,90.805 v1(104.013,90.805)
PI2: CN13.33 R121.2 U5.D12 | length 60.2
  Top Layer w0.127: U5.D12@86.8,131.2 v2(87.2,130.8) ; R121.2@103.066,92.075 v1(104.013,92.075) CN13.33@105.892,92.075
  Bottom Layer w0.102: v2(87.2,130.8) 87.6,131.2 88.2,131.2 88.7,130.7 88.901,130.7
  Bottom Layer w0.127: 88.901,130.7 90,130.7 90.779,129.921 93.726,129.921 94.996,128.651 94.996,119.38 93.853,118.237 93.853,104.267 96.393,101.727 96.393,98.425 100.457,94.361 101.473,94.361 101.854,93.98 101.854,92.964 102.235,92.583 102.362,92.583 102.489,92.71 102.489,93.091 102.616,93.218 102.87,93.218 102.997,93.091 102.997,92.075 103.124,91.948 103.378,91.948 103.505,92.075 103.505,93.091 103.632,93.218 104.775,93.218 104.902,93.091 104.902,92.837 104.775,92.71 104.14,92.71 104.013,92.583 v1(104.013,92.075)
PI3: CN13.34 R378.2 U5.A14 | length 60.1
  Top Layer w0.127: U5.A14@89.2,129.6 89.514,129.286 93.662,129.286 v5(94.107,128.841) ; CN13.34@110.992,92.075 v1(112.881,92.075)
  Bottom Layer w0.127: v5(94.107,128.841) 94.615,128.333 94.615,119.507 93.472,118.364 93.472,104.14 96.012,101.6 96.012,98.171 102.743,91.44 106.484,91.44 ; R378.2@106.484,92.075 106.484,91.44 ; v1(112.881,92.075) 108.839,92.075 108.204,91.44 106.484,91.44
PI4: CN13.17 R350.1 U5.A2 | length 69.8
  Top Layer w0.127: U5.A2@89.2,139.2 91.8,139.2 92.427,139.827 93.091,139.827 93.218,139.7 93.218,139.573 93.345,139.446 93.599,139.446 93.726,139.573 93.726,139.7 93.853,139.827 94.107,139.827 94.234,139.7 94.234,138.811 94.361,138.684 94.615,138.684 94.742,138.811 94.742,139.7 94.869,139.827 94.996,139.827 v2(95.123,139.7) ; v1(104.013,102.235) CN13.17@105.892,102.235
  Bottom Layer w0.127: v2(95.123,139.7) 95.123,138.684 96.647,137.16 97.409,137.16 100.751,133.818 100.751,133.644 100.585,133.478 100.329,133.478 98.933,134.874 98.679,134.874 98.552,134.747 98.552,134.493 100.711,132.334 100.711,118.999 99.568,117.856 99.568,105.283 102.616,102.235 v1(104.013,102.235) 104.448,101.8 113.357,101.8 113.957,102.4 R350.1@114.5,102.4
PI5: CN13.15 R344.1 U5.B2 | length 58.9
  Top Layer w0.102: v1(104.013,103.505) CN13.15@105.892,103.505
  Top Layer w0.127: U5.B2@88.4,139.2 88.8,138.8 91.9,138.8 92.524,138.176 96.901,138.176 97.028,138.303 v2(97.028,139.192)
  Bottom Layer w0.127: v2(97.028,139.192) 97.028,138.557 101.473,134.112 101.473,118.745 100.33,117.602 100.33,110.871 100.457,110.744 100.838,110.744 100.965,110.617 100.965,110.363 100.838,110.236 100.457,110.236 100.33,110.109 100.33,109.855 100.457,109.728 100.711,109.728 100.838,109.601 100.838,109.347 100.711,109.22 100.457,109.22 100.33,109.093 100.33,108.204 100.457,108.077 101.346,108.077 101.473,107.95 101.473,107.696 101.346,107.569 100.457,107.569 100.33,107.442 100.33,107.188 100.457,107.061 101.282,107.061 101.409,106.934 101.409,106.68 101.282,106.553 100.457,106.553 100.33,106.426 100.33,105.6 100.52,105.41 102.108,105.41 102.362,105.156 102.362,104.648 102.806,104.203 103.314,104.203 v1(104.013,103.505) R344.1@104.706,103.505
PI6: CN13.22 R356.2 U5.C3 | length 62.3
  Top Layer w0.1: U5.C3@87.6,138.4 v2(88,138.8)
  Top Layer w0.102: CN13.22@110.992,99.695 v1(112.881,99.695)
  Bottom Layer w0.127: v2(88,138.8) 88.138,138.938 92.1,138.938 92.638,138.4 93.6,138.4 95.377,136.623 95.377,135.128 99.187,131.318 99.187,119.507 98.044,118.364 98.044,104.775 103.822,98.996 111.511,98.996 R356.2@112.21,99.695 v1(112.881,99.695)
PI7: CN13.18 R347.2 U5.D4 | length 63.9
  Top Layer w0.102: v1(112.871,102.267) v1@112.903,102.235
  Top Layer w0.127: U5.D4@86.8,137.6 v2(87.2,138) ; CN13.18@110.992,102.235 v1@112.903,102.235
  Signal Layer 2 w0.102: v5(92.9,138.9) 93.319,139.319 94.488,139.319 94.615,139.192 v2(96.012,139.192)
  Bottom Layer w0.127: v2(87.2,138) 87.6,138.4 87.6,139.035 87.757,139.192 92.608,139.192 v5(92.9,138.9) ; v2(96.012,139.192) 96.012,139.065 101.092,133.985 101.092,118.872 99.949,117.729 99.949,105.41 102.489,102.87 104.14,102.87 104.775,102.235 108.204,102.235 108.869,102.9 111.984,102.9 112.21,102.674 R347.2@112.21,102.362 112.754,102.362 v1(112.871,102.267)
PI8: CN5.8 R168.1 U5.C1 | length 175.2
  Top Layer w0.1: U5.C1@87.6,140 v2(88,140.4)
  Top Layer w0.127: v1(114.935,31.623) R168.1@116.648,31.623 ; v1(122.994,147.955) 129.54,147.955 v1(129.794,147.701)
  Top Layer w0.2: CN5.8@120.972,147.955 v1(122.994,147.955)
  Signal Layer 2 w0.1: v2(88,140.4) 88,141.34 91.059,144.399 95.451,144.399 96.594,145.542 110.998,145.542 112.956,147.5 122.539,147.5 v1(122.994,147.955)
  Bottom Layer w0.127: v1(114.935,31.623) 114.173,32.385 114.173,65.913 132.08,83.82 132.08,123.19 129.921,125.349 129.921,138.303 130.302,138.684 130.302,139.827 129.54,140.589 129.54,147.447 v1(129.794,147.701)
PI9: CN13.20 R351.1 R360.2 U5.E3 | length 68.1
  Top Layer w0.102: CN13.20@110.992,100.965 v1(112.881,100.965)
  Top Layer w0.127: v2(85.6,138.8) U5.E3@86,138.4
  Bottom Layer w0.127: v2(85.6,138.8) 85.6,139.4 86.188,139.988 87.333,139.988 87.375,139.946 93.854,139.946 94.615,139.185 94.615,138.684 97.409,135.89 97.409,134.366 99.949,131.826 99.949,119.253 98.806,118.11 98.806,105.029 103.505,100.33 111.575,100.33 R351.1@112.21,100.965 v1(112.881,100.965) 114.278,99.568 R360.2@114.612,99.568
PI10: CN13.21 R357.1 U5.F3 | length 59.6
  Top Layer w0.1: U5.F3@85.2,138.4 v2(85.6,138)
  Top Layer w0.102: v1(104.013,99.695) CN13.21@105.892,99.695
  Bottom Layer w0.127: v2(85.6,138) 86,138.4 86,139 86.2,139.2 86.8,139.2 87.3,139.7 93.6,139.7 94.234,139.066 94.234,138.557 96.266,136.525 96.266,136.271 95.885,135.89 95.885,135.636 96.012,135.509 96.266,135.509 96.647,135.89 96.901,135.89 97.028,135.763 97.028,135.509 96.393,134.874 96.393,134.747 99.568,131.572 99.568,119.38 98.425,118.237 98.425,104.902 103.632,99.695 v1(104.013,99.695) R357.1@104.706,99.695
PI11: CN6.45 R297.1 U5.G5 | length 47.6
  Top Layer w0.1: v1(45.2,123.825) CN6.45@47.293,123.825 ; v2(84,136.4) U5.G5@84.4,136.8
  Signal Layer 2 w0.1: v1(45.2,123.825) 52.578,123.825 53.213,124.46 58.61,124.46 68.644,134.493 77.47,134.493 77.777,134.8 80.761,134.8 81.216,135.255 81.216,135.826 81.39,136 83.6,136 v2(84,136.4)
  Bottom Layer w0.1: v1(45.2,123.825) R297.1@45.778,123.825
PI12: CN5.1 R215.1 U5.H2 | length 40.3
  Top Layer w0.1: U5.H2@83.6,139.2 v2(84,139.6)
  Top Layer w0.2: v1(113.85,151.765) CN5.1@115.872,151.765
  Signal Layer 2 w0.1: v2(84,139.6) 84,141.6 87.884,145.484 87.884,146.939 89.751,148.806 94.577,148.806 97.536,151.765 v1(113.85,151.765)
  Bottom Layer w0.127: v1(113.85,151.765) R215.1@114.612,151.765
PI13: CN5.2 R214.1 U5.H5 | length 53
  Top Layer w0.127: U5.H5@83.6,136.8 v2(84,137.2)
  Top Layer w0.2: CN5.2@120.935,151.75 CN5.2@120.972,151.75 ; CN5.2@120.972,151.765 CN5.2@120.972,151.75 ; v1(122.957,151.75) CN5.2@120.972,151.75
  Signal Layer 2 w0.1: v2(84,137.2) 83.6,137.6 83.6,141.6 87.63,145.63 87.63,147.193 89.535,149.098 94.361,149.098 97.663,152.4 122.307,152.4 v1(122.957,151.75)
  Bottom Layer w0.127: v1(122.957,151.75) 123.741,151.75 R214.1@123.756,151.765
PI14: CN5.5 R226.1 U5.H4 | length 39.2
  Top Layer w0.127: U5.H4@83.6,137.6 v2(84,138)
  Top Layer w0.2: v1(113.85,149.225) CN5.5@115.872,149.225
  Signal Layer 2 w0.1: v2(84,138) 84.4,138.4 84.4,139 84.8,139.4 84.8,141 89.85,146.05 94.043,146.05 96.71,148.717 113.342,148.717 v1(113.85,149.225)
  Bottom Layer w0.1: v1(113.85,149.225) 114,149.375 R226.1@114.65,149.375
PI15: CN6.37 R290.1 U5.M7 | length 42
  Top Layer w0.1: v1(45.2,128.905) CN6.37@47.293,128.905 ; v2(80,135.6) U5.M7@80.4,135.2
  Signal Layer 2 w0.1: v1(45.2,128.905) 47.879,128.905 49.784,130.81 55.61,130.81 60.8,136 79.6,136 v2(80,135.6)
  Bottom Layer w0.1: R290.1@44.392,127.762 45.2,128.57 v1(45.2,128.905)
PJ0: CN6.41 R293.1 U5.N7 | length 41.6
  Top Layer w0.1: v1(45.2,126.365) CN6.41@47.293,126.365 ; v2(79.2,135.6) U5.N7@79.6,135.2
  Signal Layer 2 w0.1: v1(45.2,126.365) 48.641,126.365 50.546,128.27 56.261,128.27 60.891,132.9 64.5,132.9 67.2,135.6 77.7,135.6 78.1,135.2 78.8,135.2 v2(79.2,135.6)
  Bottom Layer w0.1: R293.1@44.392,126.365 v1(45.2,126.365)
PJ1: CN5.27 R270.1 U5.P7 | length 41.9
  Top Layer w0.1: U5.P7@78.8,135.2 78.4,134.8 78.4,134.3 78.6,134.1 79,134.1 79.2,134.3 79.2,134.5 79.4,134.7 80.6,134.7 80.7,134.6 80.7,134.1 80.9,133.9 93.4,133.9 v2(93.9,133.4) ; v1(113.85,135.255) CN5.27@115.872,135.255
  Signal Layer 2 w0.1: v2(93.9,133.4) 94.6,132.7 110.545,132.7 113.1,135.255 v1(113.85,135.255)
  Bottom Layer w0.127: v1(113.85,135.255) R270.1@114.612,135.255
PJ2: CN5.23 R260.1 U5.R7 | length 41.3
  Top Layer w0.1: U5.R7@78,135.2 v2(78.4,135.6) ; v1(113.85,137.795) CN5.23@115.872,137.795
  Signal Layer 2 w0.1: v2(93,134.8) 93.4,134.4 95.343,134.4 95.631,134.112 108.717,134.112 112.4,137.795 v1(113.85,137.795)
  Signal Layer 4 w0.1: v2(78.4,135.6) 78.8,136 91.8,136 v2(93,134.8)
  Bottom Layer w0.127: v1(113.85,137.795) R260.1@114.612,137.795
PJ3: CN6.40 R291.1 U5.R8 | length 29.2
  Top Layer w0.1: CN6.40@52.393,127.635 v1(54.4,127.635) 56.642,127.635 60.607,131.6 70.132,131.6 72.136,133.604 73.404,133.604 74.2,134.4 U5.R8@78,134.4
  Bottom Layer w0.1: v1(54.4,127.635) R291.1@55.176,127.635
PJ4: CN5.25 R265.1 U5.P8 | length 40.2
  Top Layer w0.1: U5.P8@78.8,134.4 79.3,134.9 80.7,134.9 80.9,134.7 80.9,134.2 81,134.1 94.4,134.1 v2(95.1,133.4) ; v1(113.85,136.525) CN5.25@115.872,136.525
  Signal Layer 2 w0.1: v2(95.1,133.4) 109.575,133.4 112.7,136.525 v1(113.85,136.525)
  Bottom Layer w0.127: v1(113.85,136.525) R265.1@114.612,136.525
PJ5: CN6.55 R313.1 U5.N12 | length 44.4
  Top Layer w0.1: v1(45.2,117.475) CN6.55@47.293,117.475 ; v2(79.2,130.8) U5.N12@79.6,131.2
  Signal Layer 2 w0.1: v1(45.2,117.475) 53.34,117.475 53.965,118.1 55.7,118.1 69.172,131.572 78.428,131.572 v2(79.2,130.8)
  Bottom Layer w0.1: R313.1@44.45,116.528 44.953,116.528 45.2,116.775 v1(45.2,117.475)
PJ6: CN5.58 R317.1 U5.K14 | length 54.1
  Top Layer w0.1: U5.K14@82,129.6 81.7,129.3 81.7,126.326 v2(82.55,125.476) ; CN5.58@120.972,116.205 v1(122.994,116.205)
  Signal Layer 2 w0.1: v2(82.55,125.476) 90.297,117.729 111.633,117.729 113.762,115.6 115.443,115.6 116.489,114.554 121.343,114.554 v1(122.994,116.205)
  Bottom Layer w0.1: v1(122.994,116.205) 122.994,115.656 123.792,114.858 R317.1@123.952,114.858
PJ7: CN5.57 R64.2 R315.1 U5.K15 | length 53.2
  Top Layer w0.1: U5.K15@82,128.8 82,126.661 v2(82.169,126.492) ; v1(113.85,116.205) CN5.57@115.872,116.205
  Top Layer w0.127: v1(123.95,117.7) 124.518,118.268 R64.2@124.518,118.745
  Signal Layer 2 w0.1: v2(82.169,126.492) 90.551,118.11 111.945,118.11 v1(113.85,116.205)
  Signal Layer 2 w0.127: v1(113.85,116.205) 116.205,116.205 116.84,116.84 123.317,116.84 123.952,117.475 123.95,117.477 v1(123.95,117.7)
  Bottom Layer w0.127: v1(113.85,116.205) R315.1@114.612,116.205
PJ8: CN5.53 R306.1 U5.J15 | length 39.6
  Top Layer w0.1: v2(82.4,128.4) U5.J15@82.8,128.8 ; v1(113.8,118.4) 114.145,118.745 CN5.53@115.872,118.745
  Signal Layer 2 w0.1: v2(82.4,128.4) 82.4,127.912 91.059,119.253 112.947,119.253 v1(113.8,118.4)
  Bottom Layer w0.127: v1(113.8,118.4) 114.145,118.745 R306.1@114.612,118.745
PJ9: CN5.55 R310.1 U5.J14 | length 41
  Top Layer w0.1: v2(82.4,129.2) U5.J14@82.8,129.6 ; v1(113.85,117.475) CN5.55@115.872,117.475
  Signal Layer 2 w0.1: v2(82.4,129.2) 82,128.8 82,127.804 90.932,118.872 112.453,118.872 v1(113.85,117.475)
  Bottom Layer w0.127: v1(113.85,117.475) R310.1@114.612,117.475
PJ10: CN5.56 R312.1 U5.J13 | length 52.6
  Top Layer w0.1: v2(82.4,130) U5.J13@82.8,130.4 ; CN5.56@120.972,117.475 v1(122.994,117.475)
  Signal Layer 2 w0.1: v2(82.4,130) 81.6,129.2 81.6,127.696 90.805,118.491 112.141,118.491 113.832,116.8 114.808,116.8 115.483,117.475 v1(122.994,117.475)
  Bottom Layer w0.1: v1(122.994,117.475) 123.175,117.475 123.789,116.861 R312.1@123.952,116.861
PJ11: CN5.52 R302.1 U5.J11 | length 51.7
  Top Layer w0.1: v2(82.4,131.6) U5.J11@82.8,132 ; CN5.52@120.972,120.015 v1(122.994,120.015)
  Signal Layer 2 w0.1: v2(82.4,131.6) 83,131.6 83.7,130.9 83.7,130.5 83.1,129.9 83.1,128.228 91.313,120.015 113.157,120.015 113.772,119.4 122.379,119.4 v1(122.994,120.015)
  Bottom Layer w0.1: v1(122.994,120.015) 123.119,119.89 R302.1@123.731,119.89
PJ12: CN5.24 R34.2 R259.1 U5.E9 | length 44.1
  Top Layer w0.1: U5.E9@86,133.6 v2(86.4,133.2) ; CN5.24@120.972,137.795 v1(122.994,137.795)
  Top Layer w0.127: v1(122.994,137.795) R34.2@124.518,137.795
  Signal Layer 2 w0.1: v2(91.1,133.4) 91.8,134.1 95.25,134.1 95.619,133.731 109.231,133.731 112.6,137.1 122.299,137.1 v1(122.994,137.795)
  Signal Layer 4 w0.1: v2(86.4,133.2) 87.1,133.9 90.6,133.9 v2(91.1,133.4)
  Bottom Layer w0.127: v1(122.994,137.795) R259.1@123.756,137.795
PJ13: CN5.26 R264.1 U5.D9 | length 41.5
  Top Layer w0.1: U5.D9@86.8,133.6 v2(87.2,133.2) ; CN5.26@120.972,136.525 v1(122.994,136.525)
  Signal Layer 2 w0.1: v2(92,133.4) 92.4,133.8 94.1,133.8 94.9,133 110,133 112.8,135.8 122.269,135.8 v1(122.994,136.525)
  Signal Layer 4 w0.1: v2(87.2,133.2) 87.6,132.8 91.4,132.8 v2(92,133.4)
  Bottom Layer w0.127: v1(122.994,136.525) R264.1@123.756,136.525
PJ14: CN5.28 R269.1 U5.C9 | length 39.9
  Top Layer w0.1: U5.C9@87.6,133.6 88.1,133.1 89.5,133.1 89.9,132.7 93.7,132.7 v2(93.9,132.5) ; CN5.28@120.972,135.255 v1(122.994,135.255)
  Signal Layer 2 w0.1: v2(93.9,132.5) 94,132.4 111,132.4 113.1,134.5 122.239,134.5 v1(122.994,135.255)
  Bottom Layer w0.127: v1(122.994,135.255) R269.1@123.756,135.255
PJ15: CN5.29 R276.1 U5.B9 | length 30.3
  Top Layer w0.1: U5.B9@88.4,133.6 88.7,133.3 89.7,133.3 90,133 92.5,133 v2(92.9,133.4) ; v1(113.85,133.985) CN5.29@115.872,133.985
  Signal Layer 2 w0.1: v2(92.9,133.4) 92.9,132.9 93.7,132.1 111.965,132.1 v1(113.85,133.985)
  Bottom Layer w0.127: v1(113.85,133.985) R276.1@114.612,133.985
PK0: CN5.54 R305.1 U5.J12 | length 50.3
  Top Layer w0.1: U5.J12@82.8,131.2 v2(83.2,130.8) ; CN5.54@120.972,118.745 v1(122.994,118.745)
  Signal Layer 2 w0.1: v2(83.2,130.8) 82.8,130.4 82.8,128.02 91.186,119.634 113.03,119.634 113.664,119 122.739,119 v1(122.994,118.745)
  Bottom Layer w0.1: v1(122.994,118.745) 123.094,118.645 R305.1@123.731,118.645
PK1: CN5.47 R299.1 U5.H15 | length 37.4
  Top Layer w0.1: U5.H15@83.6,128.8 v2(84,128.4) ; v1(113.665,122.301) 113.919,122.555 CN5.47@115.872,122.555
  Signal Layer 2 w0.1: v2(84,128.4) 84,128.344 91.567,120.777 111.887,120.777 113.411,122.301 v1(113.665,122.301)
  Bottom Layer w0.127: v1(113.665,122.301) 113.919,122.555 R299.1@114.612,122.555
PK2: CN5.51 R303.1 U5.H14 | length 38.2
  Top Layer w0.1: U5.H14@83.6,129.6 v2(84,129.2) ; v1(113.85,120.015) CN5.51@115.872,120.015
  Signal Layer 2 w0.1: v2(84,129.2) 83.566,128.766 83.566,128.27 91.44,120.396 113.469,120.396 v1(113.85,120.015)
  Bottom Layer w0.127: v1(113.85,120.015) R303.1@114.612,120.015
PK3: CN5.21 R256.1 U5.B7 | length 30.1
  Top Layer w0.1: U5.B7@88.4,135.2 v2(88.8,135.6) ; v1(113.85,139.065) CN5.21@115.872,139.065
  Signal Layer 2 w0.1: v2(88.8,135.6) 95.667,135.6 96.012,135.255 107.055,135.255 110.865,139.065 v1(113.85,139.065)
  Bottom Layer w0.127: v1(113.85,139.065) R256.1@114.612,139.065
PK4: CN5.20 R254.1 U5.C7 | length 40.9
  Top Layer w0.1: U5.C7@87.6,135.2 v2(88,135.6) ; CN5.20@120.972,140.335 v1(122.994,140.335)
  Signal Layer 2 w0.1: v2(88,135.6) 88.2,135.6 88.6,135.2 95.559,135.2 95.885,134.874 108.374,134.874 112.1,138.6 121.259,138.6 v1(122.994,140.335)
  Bottom Layer w0.127: v1(122.994,140.335) R254.1@123.756,140.335
PK5: CN5.17 R249.1 U5.A6 | length 30.3
  Top Layer w0.1: U5.A6@89.2,136 89.437,135.763 93.597,135.763 v2(94.234,136.4) ; v1(113.85,141.605) CN5.17@115.872,141.605
  Signal Layer 2 w0.1: v2(94.234,136.4) 95.883,136.4 96.266,136.017 106.712,136.017 112.3,141.605 v1(113.85,141.605)
  Bottom Layer w0.127: v1(113.85,141.605) R249.1@114.612,141.605
PK6: CN5.15 R243.1 U5.B6 | length 31.4
  Top Layer w0.1: U5.B6@88.4,136 88.8,136.4 89.4,136.4 89.8,136 92.82,136 v2(93.218,136.398) ; v1(113.85,142.875) CN5.15@115.872,142.875
  Signal Layer 2 w0.1: v2(93.218,136.398) 93.599,136.398 94.201,137 106.9,137 112.775,142.875 v1(113.85,142.875)
  Bottom Layer w0.127: v1(113.85,142.875) R243.1@114.612,142.875
PK7: CN5.18 R248.1 U5.D7 | length 41.9
  Top Layer w0.1: U5.D7@86.8,135.2 v2(87.2,135.6) ; CN5.18@120.972,141.605 v1(122.994,141.605)
  Signal Layer 2 w0.1: v2(87.2,135.6) 87.6,136 95.775,136 96.139,135.636 106.936,135.636 107.664,136.364 112.2,140.9 122.289,140.9 v1(122.994,141.605)
  Bottom Layer w0.127: v1(122.994,141.605) R248.1@123.756,141.605
POTENTIOMETER: JP5.1 R220.2 | length 5.3
  Bottom Layer w0.5: JP5.1@36.322,148.082 36.322,148.362 38.5,150.54 R220.2@38.5,152.5
REFSEL0: R19.1 R27.2 U7.8 | length 6.3
  Top Layer w0.254: U7.8@18.173,141.45 18.443,141.45 18.542,141.549 18.542,145.734 18.796,145.988 R27.2@19.304,145.988 R19.1@19.304,146.874
REFSEL1: R18.1 R26.2 U7.11 | length 5.6
  Top Layer w0.254: U7.11@16.498,142.125 16.498,143.244 17.018,143.764 17.018,145.796 17.21,145.988 R26.2@17.78,145.988 R18.1@17.78,146.874
REFSEL2: R17.1 R25.2 U7.14 | length 5.8
  Top Layer w0.254: U7.14@14.998,142.125 14.998,143.129 15.494,143.625 15.494,145.796 15.686,145.988 R25.2@16.256,145.988 R17.1@16.256,146.874 ; R17.1@16.002,146.874 R17.1@16.002,147.066
RFU1: CN11.14 TP14.1 | length 19.7
  Top Layer w0.1: TP14.1@154.76,98.645 154.76,99.896 159.702,104.838 159.702,113.757 160.845,114.9 CN11.14@161.75,114.9
RFU2: CN11.13 TP15.1 | length 23.2
  Top Layer w0.1: TP15.1@156.76,98.645 157.493,99.377 160.464,99.377 167.259,106.172 167.259,114.554 166.913,114.9 CN11.13@166.25,114.9
RS232_USART_RX: SB49.1 U9.17 | length 2.1
  Top Layer w0.127: v1(21.2,116.5) 21.245,116.455 U9.17@22.5,116.455
  Bottom Layer w0.127: v1(21.2,116.5) SB49.1@21.2,117.25
RS232_USART_TX: SB50.1 U9.13 | length 2.3
  Top Layer w0.127: U9.13@15.6,115.805 17.095,115.805 v1(17.1,115.8)
  Bottom Layer w0.127: v1(17.1,115.8) SB50.1@17.1,116.6
RSTOUTn: CN11.15 TP16.1 | length 22.6
  Top Layer w0.1: TP16.1@158.76,98.645 160.367,98.645 167.576,105.855 167.576,114.998 166.875,115.7 CN11.15@166.25,115.7
SAI1_FS_A: JP26.2 R403.2 | length 27
  Signal Layer 2 w0.127: JP26.2@134.747,96.012 136.7,94.059 136.7,81.328 v1(134.874,79.502)
  Bottom Layer w0.127: R403.2@130.302,73.602 130.498,73.602 130.81,73.914 130.81,75.692 131.318,76.2 132.969,76.2 134.874,78.105 v1(134.874,79.502)
SAI1_MCLK_A: JP14.2 R411.2 | length 75.7
  Signal Layer 2 w0.127: v1(131.064,77.216) 135.128,77.216 144.653,86.741 144.653,95.885 146.431,97.663 v1(146.431,98.806)
  Bottom Layer w0.127: R411.2@126.804,69.85 126.804,74.226 129.794,77.216 v1(131.064,77.216) ; JP14.2@136.144,130.048 136.144,126.873 146.177,116.84 146.177,99.06 v1(146.431,98.806)
SAI1_SCK_A: JP28.2 R405.2 | length 30.2
  Signal Layer 2 w0.127: v1(133.35,78.232) 135.001,78.232 139.192,82.423 139.192,94.234 JP28.2@140.97,96.012
  Bottom Layer w0.127: R405.2@128.27,73.602 128.778,74.11 128.778,75.692 129.794,76.708 132.461,76.708 133.35,77.597 v1(133.35,78.232)
SAI1_SD_A: JP27.2 R404.2 | length 27.8
  Signal Layer 2 w0.127: v1(134.112,78.74) 134.874,78.74 137.6,81.466 137.6,95.817 JP27.2@137.795,96.012
  Bottom Layer w0.127: R404.2@129.286,73.602 129.794,74.11 129.794,75.946 130.302,76.454 132.715,76.454 134.112,77.851 v1(134.112,78.74)
SAI1_SD_B: JP34.2 R413.2 | length 29.6
  Bottom Layer w0.127: R413.2@126.804,68.834 126.365,68.834 126.238,68.961 126.238,74.168 132.207,80.137 135.509,80.137 138.4,83.028 138.4,87.346 JP34.2@140.97,89.916
SCLK_C: R135.1 R405.1 U48.31 | length 4.8
  Top Layer w0.254: v1(128.27,72.136) R135.1@128.27,72.702
  Bottom Layer w0.254: R405.1@128.27,72.702 v1(128.27,72.136) 128.27,70.866 129.56,69.576 U48.31@130.163,69.576
SD_DETECT1_CN: CN28.10 JP15.2 | length 35.9
  Bottom Layer w0.127: JP15.2@138.43,149.098 143.256,149.098 144.653,147.701 144.653,140.97 147.066,138.557 156.718,138.557 157.226,139.065 157.226,140.208 158.178,141.16 163.005,141.16 163.501,140.664 CN28.10@163.501,140.127
SD_DETECT2: JP13.2 R297.2 R298.1 | length 18.3
  Signal Layer 2 w0.127: JP13.2@32.766,128.27 33.782,128.27 35.052,129.54 38.1,129.54 43.815,123.825 v1(44.069,123.825)
  Bottom Layer w0.127: R298.1@43.942,123.132 43.942,123.698 v1(44.069,123.825) 44.704,123.19 46.482,123.19 46.678,123.386 R297.2@46.678,123.825
SD_DETECT2_CN: CN3.10 JP13.1 | length 43.1
  Top Layer w0.127: CN3.10@5.4,150.89 10.527,150.89 11.938,149.479 15.367,149.479 16.129,150.241 24.259,150.241 27.432,147.068 27.432,135.468 32.09,130.81 JP13.1@32.766,130.81
SD_LDO_SEL: JP23.3 R199.2 U2.6 | length 65.5
  Top Layer w0.127: U2.6@20.316,163.072 20.578,163.072 v1(20.828,163.322)
  Signal Layer 2 w0.127: v1(21.59,114.3) 24.13,111.76 JP23.3@30.735,111.76
  Bottom Layer w0.127: v1(20.828,163.322) 20.378,162.872 R199.2@20.066,162.872 20.066,154.559 25.273,149.352 25.273,138.073 20.066,132.866 20.066,127.889 21.844,126.111 21.844,114.554 v1(21.59,114.3)
SDIN_C: R136.1 R404.1 U48.32 | length 3.8
  Top Layer w0.254: v1(129.286,72.136) R136.1@129.286,72.702
  Bottom Layer w0.254: R404.1@129.286,72.702 v1(129.286,72.136) 129.286,70.612 129.822,70.076 U48.32@130.163,70.076
SDIO1_CK: CN28.5 R54.1 U38.1 U38.10 | length 38.8
  Top Layer w0.127: R54.1@125.418,130.429 125.73,130.429 127,131.699 128.778,131.699 135.128,138.049 144.272,138.049 147.13,140.906 147.13,145.732 v1(148.209,146.812)
  Bottom Layer w0.127: v1(148.209,146.812) 148.209,147.066 148.733,147.59 U38.1@149.196,147.59
  Bottom Layer w0.203: U38.1@149.196,147.59 U38.10@150.016,147.59 150.098,147.59 152.211,145.477 CN28.5@153.301,145.477
SDIO1_CMD: CN28.3 R49.2 R231.1 U38.2 U38.9 | length 35.8
  Top Layer w0.127: R49.2@127.704,132.715 128.651,132.715 134.747,138.811 143.764,138.811 146.368,141.415 146.368,146.431 147.764,147.828 v1(148.209,147.828)
  Bottom Layer w0.127: R231.1@147.516,147.828 v1(148.209,147.828) 148.471,148.09 U38.2@149.196,148.09
  Bottom Layer w0.203: U38.2@149.196,148.09 U38.9@150.016,148.09 151.003,148.09 151.416,147.677 CN28.3@153.301,147.677
SDIO1_D0: CN28.7 JP12.1 R242.1 U40.2 U40.9 | length 17.9
  Top Layer w0.127: JP12.1@141.478,135.89 142.494,136.906 145.034,136.906 148.717,140.589 148.717,142.494 v1(148.209,143.002)
  Bottom Layer w0.127: R242.1@147.516,143.002 v1(148.209,143.002)
  Bottom Layer w0.203: v1(148.209,143.002) 148.455,142.756 U40.2@149.196,142.756 U40.9@150.016,142.756 151.879,142.756 152.387,143.264 153.288,143.264 CN28.7@153.301,143.277 CN28.7@153.288,143.277
SDIO1_D1: CN28.8 R62.1 R247.1 U40.1 U40.10 | length 40.5
  Top Layer w0.127: R62.1@125.418,125.73 131.318,125.73 133.223,127.635 133.223,134.904 135.606,137.287 144.78,137.287 148.209,140.716 v1(148.209,141.986)
  Bottom Layer w0.127: R247.1@147.516,141.986 v1(148.209,141.986)
  Bottom Layer w0.203: v1(148.209,141.986) 148.479,142.256 U40.1@149.196,142.256 U40.10@150.016,142.256 150.749,142.256 150.828,142.177 CN28.8@153.301,142.177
